VERSION 5.8 ;
BUSBITCHARS "[]" ;
DIVIDERCHAR "/" ;
UNITS
    DATABASE MICRONS 1000 ;
END UNITS

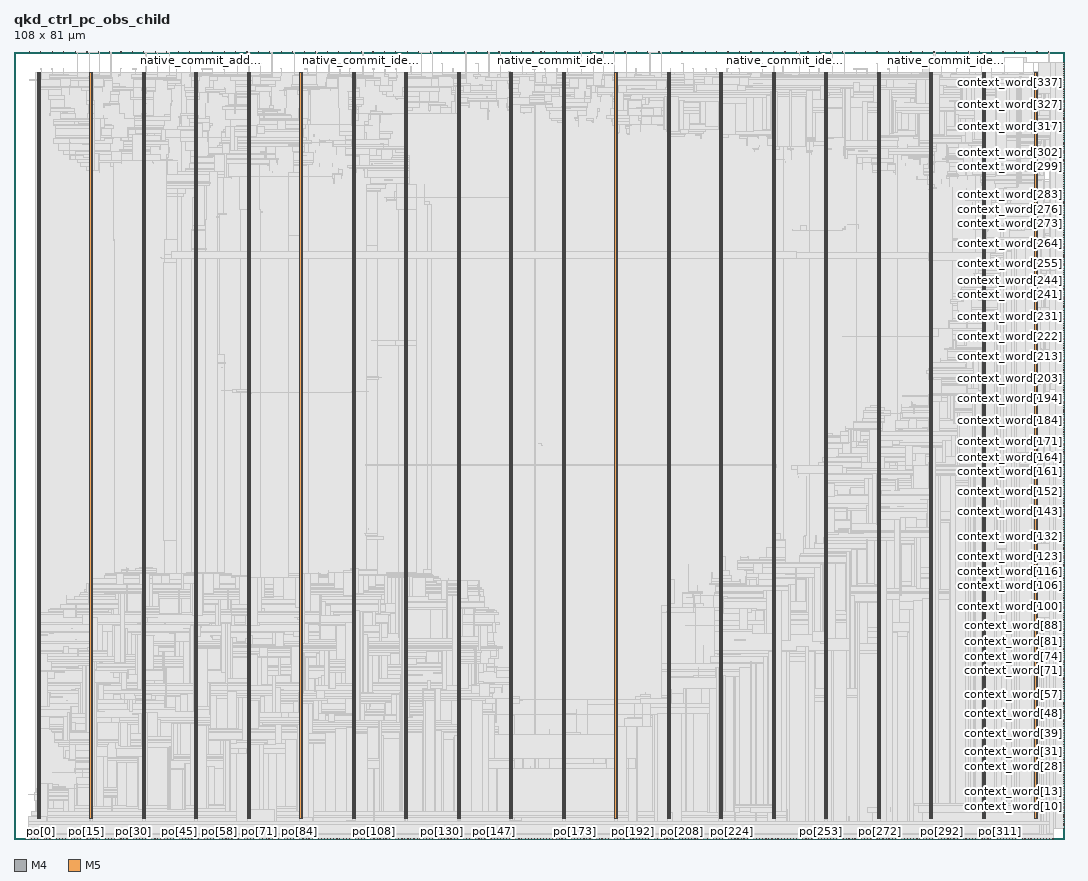
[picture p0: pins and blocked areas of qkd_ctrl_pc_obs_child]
MACRO qkd_ctrl_pc_obs_child
  FOREIGN qkd_ctrl_pc_obs_child 0 0 ;
  CLASS BLOCK ;
  SIZE 108 BY 81 ;
  PIN context_word[0]
    DIRECTION INPUT ;
    USE SIGNAL ;
    PORT
      LAYER M4 ;
        RECT  107.916 1.104 108 1.128 ;
    END
  END context_word[0]
  PIN context_word[100]
    DIRECTION INPUT ;
    USE SIGNAL ;
    PORT
      LAYER M4 ;
        RECT  107.916 23.856 108 23.88 ;
    END
  END context_word[100]
  PIN context_word[101]
    DIRECTION INPUT ;
    USE SIGNAL ;
    PORT
      LAYER M4 ;
        RECT  107.916 24.096 108 24.12 ;
    END
  END context_word[101]
  PIN context_word[102]
    DIRECTION INPUT ;
    USE SIGNAL ;
    PORT
      LAYER M4 ;
        RECT  107.916 24.336 108 24.36 ;
    END
  END context_word[102]
  PIN context_word[103]
    DIRECTION INPUT ;
    USE SIGNAL ;
    PORT
      LAYER M4 ;
        RECT  107.916 24.528 108 24.552 ;
    END
  END context_word[103]
  PIN context_word[104]
    DIRECTION INPUT ;
    USE SIGNAL ;
    PORT
      LAYER M4 ;
        RECT  107.916 24.768 108 24.792 ;
    END
  END context_word[104]
  PIN context_word[105]
    DIRECTION INPUT ;
    USE SIGNAL ;
    PORT
      LAYER M4 ;
        RECT  107.916 25.008 108 25.032 ;
    END
  END context_word[105]
  PIN context_word[106]
    DIRECTION INPUT ;
    USE SIGNAL ;
    PORT
      LAYER M4 ;
        RECT  107.916 25.248 108 25.272 ;
    END
  END context_word[106]
  PIN context_word[107]
    DIRECTION INPUT ;
    USE SIGNAL ;
    PORT
      LAYER M4 ;
        RECT  107.916 25.44 108 25.464 ;
    END
  END context_word[107]
  PIN context_word[108]
    DIRECTION INPUT ;
    USE SIGNAL ;
    PORT
      LAYER M4 ;
        RECT  107.916 25.68 108 25.704 ;
    END
  END context_word[108]
  PIN context_word[109]
    DIRECTION INPUT ;
    USE SIGNAL ;
    PORT
      LAYER M4 ;
        RECT  107.916 25.92 108 25.944 ;
    END
  END context_word[109]
  PIN context_word[10]
    DIRECTION INPUT ;
    USE SIGNAL ;
    PORT
      LAYER M4 ;
        RECT  107.916 3.36 108 3.384 ;
    END
  END context_word[10]
  PIN context_word[110]
    DIRECTION INPUT ;
    USE SIGNAL ;
    PORT
      LAYER M4 ;
        RECT  107.916 26.16 108 26.184 ;
    END
  END context_word[110]
  PIN context_word[111]
    DIRECTION INPUT ;
    USE SIGNAL ;
    PORT
      LAYER M4 ;
        RECT  107.916 26.352 108 26.376 ;
    END
  END context_word[111]
  PIN context_word[112]
    DIRECTION INPUT ;
    USE SIGNAL ;
    PORT
      LAYER M4 ;
        RECT  107.916 26.592 108 26.616 ;
    END
  END context_word[112]
  PIN context_word[113]
    DIRECTION INPUT ;
    USE SIGNAL ;
    PORT
      LAYER M4 ;
        RECT  107.916 26.832 108 26.856 ;
    END
  END context_word[113]
  PIN context_word[114]
    DIRECTION INPUT ;
    USE SIGNAL ;
    PORT
      LAYER M4 ;
        RECT  107.916 27.072 108 27.096 ;
    END
  END context_word[114]
  PIN context_word[115]
    DIRECTION INPUT ;
    USE SIGNAL ;
    PORT
      LAYER M4 ;
        RECT  107.916 27.264 108 27.288 ;
    END
  END context_word[115]
  PIN context_word[116]
    DIRECTION INPUT ;
    USE SIGNAL ;
    PORT
      LAYER M4 ;
        RECT  107.916 27.504 108 27.528 ;
    END
  END context_word[116]
  PIN context_word[117]
    DIRECTION INPUT ;
    USE SIGNAL ;
    PORT
      LAYER M4 ;
        RECT  107.916 27.744 108 27.768 ;
    END
  END context_word[117]
  PIN context_word[118]
    DIRECTION INPUT ;
    USE SIGNAL ;
    PORT
      LAYER M4 ;
        RECT  107.916 27.984 108 28.008 ;
    END
  END context_word[118]
  PIN context_word[119]
    DIRECTION INPUT ;
    USE SIGNAL ;
    PORT
      LAYER M4 ;
        RECT  107.916 28.176 108 28.2 ;
    END
  END context_word[119]
  PIN context_word[11]
    DIRECTION INPUT ;
    USE SIGNAL ;
    PORT
      LAYER M4 ;
        RECT  107.916 3.6 108 3.624 ;
    END
  END context_word[11]
  PIN context_word[120]
    DIRECTION INPUT ;
    USE SIGNAL ;
    PORT
      LAYER M4 ;
        RECT  107.916 28.416 108 28.44 ;
    END
  END context_word[120]
  PIN context_word[121]
    DIRECTION INPUT ;
    USE SIGNAL ;
    PORT
      LAYER M4 ;
        RECT  107.916 28.656 108 28.68 ;
    END
  END context_word[121]
  PIN context_word[122]
    DIRECTION INPUT ;
    USE SIGNAL ;
    PORT
      LAYER M4 ;
        RECT  107.916 28.896 108 28.92 ;
    END
  END context_word[122]
  PIN context_word[123]
    DIRECTION INPUT ;
    USE SIGNAL ;
    PORT
      LAYER M4 ;
        RECT  107.916 29.088 108 29.112 ;
    END
  END context_word[123]
  PIN context_word[124]
    DIRECTION INPUT ;
    USE SIGNAL ;
    PORT
      LAYER M4 ;
        RECT  107.916 29.328 108 29.352 ;
    END
  END context_word[124]
  PIN context_word[125]
    DIRECTION INPUT ;
    USE SIGNAL ;
    PORT
      LAYER M4 ;
        RECT  107.916 29.568 108 29.592 ;
    END
  END context_word[125]
  PIN context_word[126]
    DIRECTION INPUT ;
    USE SIGNAL ;
    PORT
      LAYER M4 ;
        RECT  107.916 29.808 108 29.832 ;
    END
  END context_word[126]
  PIN context_word[127]
    DIRECTION INPUT ;
    USE SIGNAL ;
    PORT
      LAYER M4 ;
        RECT  107.916 30 108 30.024 ;
    END
  END context_word[127]
  PIN context_word[128]
    DIRECTION INPUT ;
    USE SIGNAL ;
    PORT
      LAYER M4 ;
        RECT  107.916 30.24 108 30.264 ;
    END
  END context_word[128]
  PIN context_word[129]
    DIRECTION INPUT ;
    USE SIGNAL ;
    PORT
      LAYER M4 ;
        RECT  107.916 30.48 108 30.504 ;
    END
  END context_word[129]
  PIN context_word[12]
    DIRECTION INPUT ;
    USE SIGNAL ;
    PORT
      LAYER M4 ;
        RECT  107.916 3.84 108 3.864 ;
    END
  END context_word[12]
  PIN context_word[130]
    DIRECTION INPUT ;
    USE SIGNAL ;
    PORT
      LAYER M4 ;
        RECT  107.916 30.72 108 30.744 ;
    END
  END context_word[130]
  PIN context_word[131]
    DIRECTION INPUT ;
    USE SIGNAL ;
    PORT
      LAYER M4 ;
        RECT  107.916 30.912 108 30.936 ;
    END
  END context_word[131]
  PIN context_word[132]
    DIRECTION INPUT ;
    USE SIGNAL ;
    PORT
      LAYER M4 ;
        RECT  107.916 31.152 108 31.176 ;
    END
  END context_word[132]
  PIN context_word[133]
    DIRECTION INPUT ;
    USE SIGNAL ;
    PORT
      LAYER M4 ;
        RECT  107.916 31.392 108 31.416 ;
    END
  END context_word[133]
  PIN context_word[134]
    DIRECTION INPUT ;
    USE SIGNAL ;
    PORT
      LAYER M4 ;
        RECT  107.916 31.632 108 31.656 ;
    END
  END context_word[134]
  PIN context_word[135]
    DIRECTION INPUT ;
    USE SIGNAL ;
    PORT
      LAYER M4 ;
        RECT  107.916 31.824 108 31.848 ;
    END
  END context_word[135]
  PIN context_word[136]
    DIRECTION INPUT ;
    USE SIGNAL ;
    PORT
      LAYER M4 ;
        RECT  107.916 32.064 108 32.088 ;
    END
  END context_word[136]
  PIN context_word[137]
    DIRECTION INPUT ;
    USE SIGNAL ;
    PORT
      LAYER M4 ;
        RECT  107.916 32.304 108 32.328 ;
    END
  END context_word[137]
  PIN context_word[138]
    DIRECTION INPUT ;
    USE SIGNAL ;
    PORT
      LAYER M4 ;
        RECT  107.916 32.544 108 32.568 ;
    END
  END context_word[138]
  PIN context_word[139]
    DIRECTION INPUT ;
    USE SIGNAL ;
    PORT
      LAYER M4 ;
        RECT  107.916 32.736 108 32.76 ;
    END
  END context_word[139]
  PIN context_word[13]
    DIRECTION INPUT ;
    USE SIGNAL ;
    PORT
      LAYER M4 ;
        RECT  107.916 4.08 108 4.104 ;
    END
  END context_word[13]
  PIN context_word[140]
    DIRECTION INPUT ;
    USE SIGNAL ;
    PORT
      LAYER M4 ;
        RECT  107.916 32.976 108 33 ;
    END
  END context_word[140]
  PIN context_word[141]
    DIRECTION INPUT ;
    USE SIGNAL ;
    PORT
      LAYER M4 ;
        RECT  107.916 33.216 108 33.24 ;
    END
  END context_word[141]
  PIN context_word[142]
    DIRECTION INPUT ;
    USE SIGNAL ;
    PORT
      LAYER M4 ;
        RECT  107.916 33.408 108 33.432 ;
    END
  END context_word[142]
  PIN context_word[143]
    DIRECTION INPUT ;
    USE SIGNAL ;
    PORT
      LAYER M4 ;
        RECT  107.916 33.648 108 33.672 ;
    END
  END context_word[143]
  PIN context_word[144]
    DIRECTION INPUT ;
    USE SIGNAL ;
    PORT
      LAYER M4 ;
        RECT  107.916 33.888 108 33.912 ;
    END
  END context_word[144]
  PIN context_word[145]
    DIRECTION INPUT ;
    USE SIGNAL ;
    PORT
      LAYER M4 ;
        RECT  107.916 34.128 108 34.152 ;
    END
  END context_word[145]
  PIN context_word[146]
    DIRECTION INPUT ;
    USE SIGNAL ;
    PORT
      LAYER M4 ;
        RECT  107.916 34.32 108 34.344 ;
    END
  END context_word[146]
  PIN context_word[147]
    DIRECTION INPUT ;
    USE SIGNAL ;
    PORT
      LAYER M4 ;
        RECT  107.916 34.56 108 34.584 ;
    END
  END context_word[147]
  PIN context_word[148]
    DIRECTION INPUT ;
    USE SIGNAL ;
    PORT
      LAYER M4 ;
        RECT  107.916 34.8 108 34.824 ;
    END
  END context_word[148]
  PIN context_word[149]
    DIRECTION INPUT ;
    USE SIGNAL ;
    PORT
      LAYER M4 ;
        RECT  107.916 35.04 108 35.064 ;
    END
  END context_word[149]
  PIN context_word[14]
    DIRECTION INPUT ;
    USE SIGNAL ;
    PORT
      LAYER M4 ;
        RECT  107.916 4.272 108 4.296 ;
    END
  END context_word[14]
  PIN context_word[150]
    DIRECTION INPUT ;
    USE SIGNAL ;
    PORT
      LAYER M4 ;
        RECT  107.916 35.232 108 35.256 ;
    END
  END context_word[150]
  PIN context_word[151]
    DIRECTION INPUT ;
    USE SIGNAL ;
    PORT
      LAYER M4 ;
        RECT  107.916 35.472 108 35.496 ;
    END
  END context_word[151]
  PIN context_word[152]
    DIRECTION INPUT ;
    USE SIGNAL ;
    PORT
      LAYER M4 ;
        RECT  107.916 35.712 108 35.736 ;
    END
  END context_word[152]
  PIN context_word[153]
    DIRECTION INPUT ;
    USE SIGNAL ;
    PORT
      LAYER M4 ;
        RECT  107.916 35.952 108 35.976 ;
    END
  END context_word[153]
  PIN context_word[154]
    DIRECTION INPUT ;
    USE SIGNAL ;
    PORT
      LAYER M4 ;
        RECT  107.916 36.144 108 36.168 ;
    END
  END context_word[154]
  PIN context_word[155]
    DIRECTION INPUT ;
    USE SIGNAL ;
    PORT
      LAYER M4 ;
        RECT  107.916 36.384 108 36.408 ;
    END
  END context_word[155]
  PIN context_word[156]
    DIRECTION INPUT ;
    USE SIGNAL ;
    PORT
      LAYER M4 ;
        RECT  107.916 36.624 108 36.648 ;
    END
  END context_word[156]
  PIN context_word[157]
    DIRECTION INPUT ;
    USE SIGNAL ;
    PORT
      LAYER M4 ;
        RECT  107.916 36.864 108 36.888 ;
    END
  END context_word[157]
  PIN context_word[158]
    DIRECTION INPUT ;
    USE SIGNAL ;
    PORT
      LAYER M4 ;
        RECT  107.916 37.056 108 37.08 ;
    END
  END context_word[158]
  PIN context_word[159]
    DIRECTION INPUT ;
    USE SIGNAL ;
    PORT
      LAYER M4 ;
        RECT  107.916 37.296 108 37.32 ;
    END
  END context_word[159]
  PIN context_word[15]
    DIRECTION INPUT ;
    USE SIGNAL ;
    PORT
      LAYER M4 ;
        RECT  107.916 4.512 108 4.536 ;
    END
  END context_word[15]
  PIN context_word[160]
    DIRECTION INPUT ;
    USE SIGNAL ;
    PORT
      LAYER M4 ;
        RECT  107.916 37.536 108 37.56 ;
    END
  END context_word[160]
  PIN context_word[161]
    DIRECTION INPUT ;
    USE SIGNAL ;
    PORT
      LAYER M4 ;
        RECT  107.916 37.776 108 37.8 ;
    END
  END context_word[161]
  PIN context_word[162]
    DIRECTION INPUT ;
    USE SIGNAL ;
    PORT
      LAYER M4 ;
        RECT  107.916 37.968 108 37.992 ;
    END
  END context_word[162]
  PIN context_word[163]
    DIRECTION INPUT ;
    USE SIGNAL ;
    PORT
      LAYER M4 ;
        RECT  107.916 38.208 108 38.232 ;
    END
  END context_word[163]
  PIN context_word[164]
    DIRECTION INPUT ;
    USE SIGNAL ;
    PORT
      LAYER M4 ;
        RECT  107.916 38.448 108 38.472 ;
    END
  END context_word[164]
  PIN context_word[165]
    DIRECTION INPUT ;
    USE SIGNAL ;
    PORT
      LAYER M4 ;
        RECT  107.916 38.688 108 38.712 ;
    END
  END context_word[165]
  PIN context_word[166]
    DIRECTION INPUT ;
    USE SIGNAL ;
    PORT
      LAYER M4 ;
        RECT  107.916 38.88 108 38.904 ;
    END
  END context_word[166]
  PIN context_word[167]
    DIRECTION INPUT ;
    USE SIGNAL ;
    PORT
      LAYER M4 ;
        RECT  107.916 39.12 108 39.144 ;
    END
  END context_word[167]
  PIN context_word[168]
    DIRECTION INPUT ;
    USE SIGNAL ;
    PORT
      LAYER M4 ;
        RECT  107.916 39.36 108 39.384 ;
    END
  END context_word[168]
  PIN context_word[169]
    DIRECTION INPUT ;
    USE SIGNAL ;
    PORT
      LAYER M4 ;
        RECT  107.916 39.6 108 39.624 ;
    END
  END context_word[169]
  PIN context_word[16]
    DIRECTION INPUT ;
    USE SIGNAL ;
    PORT
      LAYER M4 ;
        RECT  107.916 4.752 108 4.776 ;
    END
  END context_word[16]
  PIN context_word[170]
    DIRECTION INPUT ;
    USE SIGNAL ;
    PORT
      LAYER M4 ;
        RECT  107.916 39.792 108 39.816 ;
    END
  END context_word[170]
  PIN context_word[171]
    DIRECTION INPUT ;
    USE SIGNAL ;
    PORT
      LAYER M4 ;
        RECT  107.916 40.032 108 40.056 ;
    END
  END context_word[171]
  PIN context_word[172]
    DIRECTION INPUT ;
    USE SIGNAL ;
    PORT
      LAYER M4 ;
        RECT  107.916 40.272 108 40.296 ;
    END
  END context_word[172]
  PIN context_word[173]
    DIRECTION INPUT ;
    USE SIGNAL ;
    PORT
      LAYER M4 ;
        RECT  107.916 40.512 108 40.536 ;
    END
  END context_word[173]
  PIN context_word[174]
    DIRECTION INPUT ;
    USE SIGNAL ;
    PORT
      LAYER M4 ;
        RECT  107.916 40.704 108 40.728 ;
    END
  END context_word[174]
  PIN context_word[175]
    DIRECTION INPUT ;
    USE SIGNAL ;
    PORT
      LAYER M4 ;
        RECT  107.916 40.944 108 40.968 ;
    END
  END context_word[175]
  PIN context_word[176]
    DIRECTION INPUT ;
    USE SIGNAL ;
    PORT
      LAYER M4 ;
        RECT  107.916 41.184 108 41.208 ;
    END
  END context_word[176]
  PIN context_word[177]
    DIRECTION INPUT ;
    USE SIGNAL ;
    PORT
      LAYER M4 ;
        RECT  107.916 41.376 108 41.4 ;
    END
  END context_word[177]
  PIN context_word[178]
    DIRECTION INPUT ;
    USE SIGNAL ;
    PORT
      LAYER M4 ;
        RECT  107.916 41.616 108 41.64 ;
    END
  END context_word[178]
  PIN context_word[179]
    DIRECTION INPUT ;
    USE SIGNAL ;
    PORT
      LAYER M4 ;
        RECT  107.916 41.856 108 41.88 ;
    END
  END context_word[179]
  PIN context_word[17]
    DIRECTION INPUT ;
    USE SIGNAL ;
    PORT
      LAYER M4 ;
        RECT  107.916 4.992 108 5.016 ;
    END
  END context_word[17]
  PIN context_word[180]
    DIRECTION INPUT ;
    USE SIGNAL ;
    PORT
      LAYER M4 ;
        RECT  107.916 42.096 108 42.12 ;
    END
  END context_word[180]
  PIN context_word[181]
    DIRECTION INPUT ;
    USE SIGNAL ;
    PORT
      LAYER M4 ;
        RECT  107.916 42.288 108 42.312 ;
    END
  END context_word[181]
  PIN context_word[182]
    DIRECTION INPUT ;
    USE SIGNAL ;
    PORT
      LAYER M4 ;
        RECT  107.916 42.528 108 42.552 ;
    END
  END context_word[182]
  PIN context_word[183]
    DIRECTION INPUT ;
    USE SIGNAL ;
    PORT
      LAYER M4 ;
        RECT  107.916 42.768 108 42.792 ;
    END
  END context_word[183]
  PIN context_word[184]
    DIRECTION INPUT ;
    USE SIGNAL ;
    PORT
      LAYER M4 ;
        RECT  107.916 43.008 108 43.032 ;
    END
  END context_word[184]
  PIN context_word[185]
    DIRECTION INPUT ;
    USE SIGNAL ;
    PORT
      LAYER M4 ;
        RECT  107.916 43.2 108 43.224 ;
    END
  END context_word[185]
  PIN context_word[186]
    DIRECTION INPUT ;
    USE SIGNAL ;
    PORT
      LAYER M4 ;
        RECT  107.916 43.44 108 43.464 ;
    END
  END context_word[186]
  PIN context_word[187]
    DIRECTION INPUT ;
    USE SIGNAL ;
    PORT
      LAYER M4 ;
        RECT  107.916 43.68 108 43.704 ;
    END
  END context_word[187]
  PIN context_word[188]
    DIRECTION INPUT ;
    USE SIGNAL ;
    PORT
      LAYER M4 ;
        RECT  107.916 43.92 108 43.944 ;
    END
  END context_word[188]
  PIN context_word[189]
    DIRECTION INPUT ;
    USE SIGNAL ;
    PORT
      LAYER M4 ;
        RECT  107.916 44.112 108 44.136 ;
    END
  END context_word[189]
  PIN context_word[18]
    DIRECTION INPUT ;
    USE SIGNAL ;
    PORT
      LAYER M4 ;
        RECT  107.916 5.184 108 5.208 ;
    END
  END context_word[18]
  PIN context_word[190]
    DIRECTION INPUT ;
    USE SIGNAL ;
    PORT
      LAYER M4 ;
        RECT  107.916 44.352 108 44.376 ;
    END
  END context_word[190]
  PIN context_word[191]
    DIRECTION INPUT ;
    USE SIGNAL ;
    PORT
      LAYER M4 ;
        RECT  107.916 44.592 108 44.616 ;
    END
  END context_word[191]
  PIN context_word[192]
    DIRECTION INPUT ;
    USE SIGNAL ;
    PORT
      LAYER M4 ;
        RECT  107.916 44.832 108 44.856 ;
    END
  END context_word[192]
  PIN context_word[193]
    DIRECTION INPUT ;
    USE SIGNAL ;
    PORT
      LAYER M4 ;
        RECT  107.916 45.024 108 45.048 ;
    END
  END context_word[193]
  PIN context_word[194]
    DIRECTION INPUT ;
    USE SIGNAL ;
    PORT
      LAYER M4 ;
        RECT  107.916 45.264 108 45.288 ;
    END
  END context_word[194]
  PIN context_word[195]
    DIRECTION INPUT ;
    USE SIGNAL ;
    PORT
      LAYER M4 ;
        RECT  107.916 45.504 108 45.528 ;
    END
  END context_word[195]
  PIN context_word[196]
    DIRECTION INPUT ;
    USE SIGNAL ;
    PORT
      LAYER M4 ;
        RECT  107.916 45.744 108 45.768 ;
    END
  END context_word[196]
  PIN context_word[197]
    DIRECTION INPUT ;
    USE SIGNAL ;
    PORT
      LAYER M4 ;
        RECT  107.916 45.936 108 45.96 ;
    END
  END context_word[197]
  PIN context_word[198]
    DIRECTION INPUT ;
    USE SIGNAL ;
    PORT
      LAYER M4 ;
        RECT  107.916 46.176 108 46.2 ;
    END
  END context_word[198]
  PIN context_word[199]
    DIRECTION INPUT ;
    USE SIGNAL ;
    PORT
      LAYER M4 ;
        RECT  107.916 46.416 108 46.44 ;
    END
  END context_word[199]
  PIN context_word[19]
    DIRECTION INPUT ;
    USE SIGNAL ;
    PORT
      LAYER M4 ;
        RECT  107.916 5.424 108 5.448 ;
    END
  END context_word[19]
  PIN context_word[1]
    DIRECTION INPUT ;
    USE SIGNAL ;
    PORT
      LAYER M4 ;
        RECT  107.916 1.344 108 1.368 ;
    END
  END context_word[1]
  PIN context_word[200]
    DIRECTION INPUT ;
    USE SIGNAL ;
    PORT
      LAYER M4 ;
        RECT  107.916 46.656 108 46.68 ;
    END
  END context_word[200]
  PIN context_word[201]
    DIRECTION INPUT ;
    USE SIGNAL ;
    PORT
      LAYER M4 ;
        RECT  107.916 46.848 108 46.872 ;
    END
  END context_word[201]
  PIN context_word[202]
    DIRECTION INPUT ;
    USE SIGNAL ;
    PORT
      LAYER M4 ;
        RECT  107.916 47.088 108 47.112 ;
    END
  END context_word[202]
  PIN context_word[203]
    DIRECTION INPUT ;
    USE SIGNAL ;
    PORT
      LAYER M4 ;
        RECT  107.916 47.328 108 47.352 ;
    END
  END context_word[203]
  PIN context_word[204]
    DIRECTION INPUT ;
    USE SIGNAL ;
    PORT
      LAYER M4 ;
        RECT  107.916 47.568 108 47.592 ;
    END
  END context_word[204]
  PIN context_word[205]
    DIRECTION INPUT ;
    USE SIGNAL ;
    PORT
      LAYER M4 ;
        RECT  107.916 47.76 108 47.784 ;
    END
  END context_word[205]
  PIN context_word[206]
    DIRECTION INPUT ;
    USE SIGNAL ;
    PORT
      LAYER M4 ;
        RECT  107.916 48 108 48.024 ;
    END
  END context_word[206]
  PIN context_word[207]
    DIRECTION INPUT ;
    USE SIGNAL ;
    PORT
      LAYER M4 ;
        RECT  107.916 48.24 108 48.264 ;
    END
  END context_word[207]
  PIN context_word[208]
    DIRECTION INPUT ;
    USE SIGNAL ;
    PORT
      LAYER M4 ;
        RECT  107.916 48.48 108 48.504 ;
    END
  END context_word[208]
  PIN context_word[209]
    DIRECTION INPUT ;
    USE SIGNAL ;
    PORT
      LAYER M4 ;
        RECT  107.916 48.672 108 48.696 ;
    END
  END context_word[209]
  PIN context_word[20]
    DIRECTION INPUT ;
    USE SIGNAL ;
    PORT
      LAYER M4 ;
        RECT  107.916 5.664 108 5.688 ;
    END
  END context_word[20]
  PIN context_word[210]
    DIRECTION INPUT ;
    USE SIGNAL ;
    PORT
      LAYER M4 ;
        RECT  107.916 48.912 108 48.936 ;
    END
  END context_word[210]
  PIN context_word[211]
    DIRECTION INPUT ;
    USE SIGNAL ;
    PORT
      LAYER M4 ;
        RECT  107.916 49.152 108 49.176 ;
    END
  END context_word[211]
  PIN context_word[212]
    DIRECTION INPUT ;
    USE SIGNAL ;
    PORT
      LAYER M4 ;
        RECT  107.916 49.344 108 49.368 ;
    END
  END context_word[212]
  PIN context_word[213]
    DIRECTION INPUT ;
    USE SIGNAL ;
    PORT
      LAYER M4 ;
        RECT  107.916 49.584 108 49.608 ;
    END
  END context_word[213]
  PIN context_word[214]
    DIRECTION INPUT ;
    USE SIGNAL ;
    PORT
      LAYER M4 ;
        RECT  107.916 49.824 108 49.848 ;
    END
  END context_word[214]
  PIN context_word[215]
    DIRECTION INPUT ;
    USE SIGNAL ;
    PORT
      LAYER M4 ;
        RECT  107.916 50.064 108 50.088 ;
    END
  END context_word[215]
  PIN context_word[216]
    DIRECTION INPUT ;
    USE SIGNAL ;
    PORT
      LAYER M4 ;
        RECT  107.916 50.256 108 50.28 ;
    END
  END context_word[216]
  PIN context_word[217]
    DIRECTION INPUT ;
    USE SIGNAL ;
    PORT
      LAYER M4 ;
        RECT  107.916 50.496 108 50.52 ;
    END
  END context_word[217]
  PIN context_word[218]
    DIRECTION INPUT ;
    USE SIGNAL ;
    PORT
      LAYER M4 ;
        RECT  107.916 50.736 108 50.76 ;
    END
  END context_word[218]
  PIN context_word[219]
    DIRECTION INPUT ;
    USE SIGNAL ;
    PORT
      LAYER M4 ;
        RECT  107.916 50.976 108 51 ;
    END
  END context_word[219]
  PIN context_word[21]
    DIRECTION INPUT ;
    USE SIGNAL ;
    PORT
      LAYER M4 ;
        RECT  107.916 5.904 108 5.928 ;
    END
  END context_word[21]
  PIN context_word[220]
    DIRECTION INPUT ;
    USE SIGNAL ;
    PORT
      LAYER M4 ;
        RECT  107.916 51.168 108 51.192 ;
    END
  END context_word[220]
  PIN context_word[221]
    DIRECTION INPUT ;
    USE SIGNAL ;
    PORT
      LAYER M4 ;
        RECT  107.916 51.408 108 51.432 ;
    END
  END context_word[221]
  PIN context_word[222]
    DIRECTION INPUT ;
    USE SIGNAL ;
    PORT
      LAYER M4 ;
        RECT  107.916 51.648 108 51.672 ;
    END
  END context_word[222]
  PIN context_word[223]
    DIRECTION INPUT ;
    USE SIGNAL ;
    PORT
      LAYER M4 ;
        RECT  107.916 51.888 108 51.912 ;
    END
  END context_word[223]
  PIN context_word[224]
    DIRECTION INPUT ;
    USE SIGNAL ;
    PORT
      LAYER M4 ;
        RECT  107.916 52.08 108 52.104 ;
    END
  END context_word[224]
  PIN context_word[225]
    DIRECTION INPUT ;
    USE SIGNAL ;
    PORT
      LAYER M4 ;
        RECT  107.916 52.32 108 52.344 ;
    END
  END context_word[225]
  PIN context_word[226]
    DIRECTION INPUT ;
    USE SIGNAL ;
    PORT
      LAYER M4 ;
        RECT  107.916 52.56 108 52.584 ;
    END
  END context_word[226]
  PIN context_word[227]
    DIRECTION INPUT ;
    USE SIGNAL ;
    PORT
      LAYER M4 ;
        RECT  107.916 52.8 108 52.824 ;
    END
  END context_word[227]
  PIN context_word[228]
    DIRECTION INPUT ;
    USE SIGNAL ;
    PORT
      LAYER M4 ;
        RECT  107.916 52.992 108 53.016 ;
    END
  END context_word[228]
  PIN context_word[229]
    DIRECTION INPUT ;
    USE SIGNAL ;
    PORT
      LAYER M4 ;
        RECT  107.916 53.232 108 53.256 ;
    END
  END context_word[229]
  PIN context_word[22]
    DIRECTION INPUT ;
    USE SIGNAL ;
    PORT
      LAYER M4 ;
        RECT  107.916 6.096 108 6.12 ;
    END
  END context_word[22]
  PIN context_word[230]
    DIRECTION INPUT ;
    USE SIGNAL ;
    PORT
      LAYER M4 ;
        RECT  107.916 53.472 108 53.496 ;
    END
  END context_word[230]
  PIN context_word[231]
    DIRECTION INPUT ;
    USE SIGNAL ;
    PORT
      LAYER M4 ;
        RECT  107.916 53.712 108 53.736 ;
    END
  END context_word[231]
  PIN context_word[232]
    DIRECTION INPUT ;
    USE SIGNAL ;
    PORT
      LAYER M4 ;
        RECT  107.916 53.904 108 53.928 ;
    END
  END context_word[232]
  PIN context_word[233]
    DIRECTION INPUT ;
    USE SIGNAL ;
    PORT
      LAYER M4 ;
        RECT  107.916 54.144 108 54.168 ;
    END
  END context_word[233]
  PIN context_word[234]
    DIRECTION INPUT ;
    USE SIGNAL ;
    PORT
      LAYER M4 ;
        RECT  107.916 54.384 108 54.408 ;
    END
  END context_word[234]
  PIN context_word[235]
    DIRECTION INPUT ;
    USE SIGNAL ;
    PORT
      LAYER M4 ;
        RECT  107.916 54.624 108 54.648 ;
    END
  END context_word[235]
  PIN context_word[236]
    DIRECTION INPUT ;
    USE SIGNAL ;
    PORT
      LAYER M4 ;
        RECT  107.916 54.816 108 54.84 ;
    END
  END context_word[236]
  PIN context_word[237]
    DIRECTION INPUT ;
    USE SIGNAL ;
    PORT
      LAYER M4 ;
        RECT  107.916 55.056 108 55.08 ;
    END
  END context_word[237]
  PIN context_word[238]
    DIRECTION INPUT ;
    USE SIGNAL ;
    PORT
      LAYER M4 ;
        RECT  107.916 55.296 108 55.32 ;
    END
  END context_word[238]
  PIN context_word[239]
    DIRECTION INPUT ;
    USE SIGNAL ;
    PORT
      LAYER M4 ;
        RECT  107.916 55.536 108 55.56 ;
    END
  END context_word[239]
  PIN context_word[23]
    DIRECTION INPUT ;
    USE SIGNAL ;
    PORT
      LAYER M4 ;
        RECT  107.916 6.336 108 6.36 ;
    END
  END context_word[23]
  PIN context_word[240]
    DIRECTION INPUT ;
    USE SIGNAL ;
    PORT
      LAYER M4 ;
        RECT  107.916 55.728 108 55.752 ;
    END
  END context_word[240]
  PIN context_word[241]
    DIRECTION INPUT ;
    USE SIGNAL ;
    PORT
      LAYER M4 ;
        RECT  107.916 55.968 108 55.992 ;
    END
  END context_word[241]
  PIN context_word[242]
    DIRECTION INPUT ;
    USE SIGNAL ;
    PORT
      LAYER M4 ;
        RECT  107.916 56.208 108 56.232 ;
    END
  END context_word[242]
  PIN context_word[243]
    DIRECTION INPUT ;
    USE SIGNAL ;
    PORT
      LAYER M4 ;
        RECT  107.916 56.448 108 56.472 ;
    END
  END context_word[243]
  PIN context_word[244]
    DIRECTION INPUT ;
    USE SIGNAL ;
    PORT
      LAYER M4 ;
        RECT  107.916 56.64 108 56.664 ;
    END
  END context_word[244]
  PIN context_word[245]
    DIRECTION INPUT ;
    USE SIGNAL ;
    PORT
      LAYER M4 ;
        RECT  107.916 56.88 108 56.904 ;
    END
  END context_word[245]
  PIN context_word[246]
    DIRECTION INPUT ;
    USE SIGNAL ;
    PORT
      LAYER M4 ;
        RECT  107.916 57.12 108 57.144 ;
    END
  END context_word[246]
  PIN context_word[247]
    DIRECTION INPUT ;
    USE SIGNAL ;
    PORT
      LAYER M4 ;
        RECT  107.916 57.312 108 57.336 ;
    END
  END context_word[247]
  PIN context_word[248]
    DIRECTION INPUT ;
    USE SIGNAL ;
    PORT
      LAYER M4 ;
        RECT  107.916 57.552 108 57.576 ;
    END
  END context_word[248]
  PIN context_word[249]
    DIRECTION INPUT ;
    USE SIGNAL ;
    PORT
      LAYER M4 ;
        RECT  107.916 57.792 108 57.816 ;
    END
  END context_word[249]
  PIN context_word[24]
    DIRECTION INPUT ;
    USE SIGNAL ;
    PORT
      LAYER M4 ;
        RECT  107.916 6.576 108 6.6 ;
    END
  END context_word[24]
  PIN context_word[250]
    DIRECTION INPUT ;
    USE SIGNAL ;
    PORT
      LAYER M4 ;
        RECT  107.916 58.032 108 58.056 ;
    END
  END context_word[250]
  PIN context_word[251]
    DIRECTION INPUT ;
    USE SIGNAL ;
    PORT
      LAYER M4 ;
        RECT  107.916 58.224 108 58.248 ;
    END
  END context_word[251]
  PIN context_word[252]
    DIRECTION INPUT ;
    USE SIGNAL ;
    PORT
      LAYER M4 ;
        RECT  107.916 58.464 108 58.488 ;
    END
  END context_word[252]
  PIN context_word[253]
    DIRECTION INPUT ;
    USE SIGNAL ;
    PORT
      LAYER M4 ;
        RECT  107.916 58.704 108 58.728 ;
    END
  END context_word[253]
  PIN context_word[254]
    DIRECTION INPUT ;
    USE SIGNAL ;
    PORT
      LAYER M4 ;
        RECT  107.916 58.944 108 58.968 ;
    END
  END context_word[254]
  PIN context_word[255]
    DIRECTION INPUT ;
    USE SIGNAL ;
    PORT
      LAYER M4 ;
        RECT  107.916 59.136 108 59.16 ;
    END
  END context_word[255]
  PIN context_word[256]
    DIRECTION INPUT ;
    USE SIGNAL ;
    PORT
      LAYER M4 ;
        RECT  107.916 59.376 108 59.4 ;
    END
  END context_word[256]
  PIN context_word[257]
    DIRECTION INPUT ;
    USE SIGNAL ;
    PORT
      LAYER M4 ;
        RECT  107.916 59.616 108 59.64 ;
    END
  END context_word[257]
  PIN context_word[258]
    DIRECTION INPUT ;
    USE SIGNAL ;
    PORT
      LAYER M4 ;
        RECT  107.916 59.856 108 59.88 ;
    END
  END context_word[258]
  PIN context_word[259]
    DIRECTION INPUT ;
    USE SIGNAL ;
    PORT
      LAYER M4 ;
        RECT  107.916 60.048 108 60.072 ;
    END
  END context_word[259]
  PIN context_word[25]
    DIRECTION INPUT ;
    USE SIGNAL ;
    PORT
      LAYER M4 ;
        RECT  107.916 6.816 108 6.84 ;
    END
  END context_word[25]
  PIN context_word[260]
    DIRECTION INPUT ;
    USE SIGNAL ;
    PORT
      LAYER M4 ;
        RECT  107.916 60.288 108 60.312 ;
    END
  END context_word[260]
  PIN context_word[261]
    DIRECTION INPUT ;
    USE SIGNAL ;
    PORT
      LAYER M4 ;
        RECT  107.916 60.528 108 60.552 ;
    END
  END context_word[261]
  PIN context_word[262]
    DIRECTION INPUT ;
    USE SIGNAL ;
    PORT
      LAYER M4 ;
        RECT  107.916 60.768 108 60.792 ;
    END
  END context_word[262]
  PIN context_word[263]
    DIRECTION INPUT ;
    USE SIGNAL ;
    PORT
      LAYER M4 ;
        RECT  107.916 60.96 108 60.984 ;
    END
  END context_word[263]
  PIN context_word[264]
    DIRECTION INPUT ;
    USE SIGNAL ;
    PORT
      LAYER M4 ;
        RECT  107.916 61.2 108 61.224 ;
    END
  END context_word[264]
  PIN context_word[265]
    DIRECTION INPUT ;
    USE SIGNAL ;
    PORT
      LAYER M4 ;
        RECT  107.916 61.44 108 61.464 ;
    END
  END context_word[265]
  PIN context_word[266]
    DIRECTION INPUT ;
    USE SIGNAL ;
    PORT
      LAYER M4 ;
        RECT  107.916 61.68 108 61.704 ;
    END
  END context_word[266]
  PIN context_word[267]
    DIRECTION INPUT ;
    USE SIGNAL ;
    PORT
      LAYER M4 ;
        RECT  107.916 61.872 108 61.896 ;
    END
  END context_word[267]
  PIN context_word[268]
    DIRECTION INPUT ;
    USE SIGNAL ;
    PORT
      LAYER M4 ;
        RECT  107.916 62.112 108 62.136 ;
    END
  END context_word[268]
  PIN context_word[269]
    DIRECTION INPUT ;
    USE SIGNAL ;
    PORT
      LAYER M4 ;
        RECT  107.916 62.352 108 62.376 ;
    END
  END context_word[269]
  PIN context_word[26]
    DIRECTION INPUT ;
    USE SIGNAL ;
    PORT
      LAYER M4 ;
        RECT  107.916 7.008 108 7.032 ;
    END
  END context_word[26]
  PIN context_word[270]
    DIRECTION INPUT ;
    USE SIGNAL ;
    PORT
      LAYER M4 ;
        RECT  107.916 62.592 108 62.616 ;
    END
  END context_word[270]
  PIN context_word[271]
    DIRECTION INPUT ;
    USE SIGNAL ;
    PORT
      LAYER M4 ;
        RECT  107.916 62.784 108 62.808 ;
    END
  END context_word[271]
  PIN context_word[272]
    DIRECTION INPUT ;
    USE SIGNAL ;
    PORT
      LAYER M4 ;
        RECT  107.916 63.024 108 63.048 ;
    END
  END context_word[272]
  PIN context_word[273]
    DIRECTION INPUT ;
    USE SIGNAL ;
    PORT
      LAYER M4 ;
        RECT  107.916 63.264 108 63.288 ;
    END
  END context_word[273]
  PIN context_word[274]
    DIRECTION INPUT ;
    USE SIGNAL ;
    PORT
      LAYER M4 ;
        RECT  107.916 63.504 108 63.528 ;
    END
  END context_word[274]
  PIN context_word[275]
    DIRECTION INPUT ;
    USE SIGNAL ;
    PORT
      LAYER M4 ;
        RECT  107.916 63.696 108 63.72 ;
    END
  END context_word[275]
  PIN context_word[276]
    DIRECTION INPUT ;
    USE SIGNAL ;
    PORT
      LAYER M4 ;
        RECT  107.916 63.936 108 63.96 ;
    END
  END context_word[276]
  PIN context_word[277]
    DIRECTION INPUT ;
    USE SIGNAL ;
    PORT
      LAYER M4 ;
        RECT  107.916 64.176 108 64.2 ;
    END
  END context_word[277]
  PIN context_word[278]
    DIRECTION INPUT ;
    USE SIGNAL ;
    PORT
      LAYER M4 ;
        RECT  107.916 64.416 108 64.44 ;
    END
  END context_word[278]
  PIN context_word[279]
    DIRECTION INPUT ;
    USE SIGNAL ;
    PORT
      LAYER M4 ;
        RECT  107.916 64.608 108 64.632 ;
    END
  END context_word[279]
  PIN context_word[27]
    DIRECTION INPUT ;
    USE SIGNAL ;
    PORT
      LAYER M4 ;
        RECT  107.916 7.248 108 7.272 ;
    END
  END context_word[27]
  PIN context_word[280]
    DIRECTION INPUT ;
    USE SIGNAL ;
    PORT
      LAYER M4 ;
        RECT  107.916 64.848 108 64.872 ;
    END
  END context_word[280]
  PIN context_word[281]
    DIRECTION INPUT ;
    USE SIGNAL ;
    PORT
      LAYER M4 ;
        RECT  107.916 65.088 108 65.112 ;
    END
  END context_word[281]
  PIN context_word[282]
    DIRECTION INPUT ;
    USE SIGNAL ;
    PORT
      LAYER M4 ;
        RECT  107.916 65.328 108 65.352 ;
    END
  END context_word[282]
  PIN context_word[283]
    DIRECTION INPUT ;
    USE SIGNAL ;
    PORT
      LAYER M4 ;
        RECT  107.916 65.52 108 65.544 ;
    END
  END context_word[283]
  PIN context_word[284]
    DIRECTION INPUT ;
    USE SIGNAL ;
    PORT
      LAYER M4 ;
        RECT  107.916 65.76 108 65.784 ;
    END
  END context_word[284]
  PIN context_word[285]
    DIRECTION INPUT ;
    USE SIGNAL ;
    PORT
      LAYER M4 ;
        RECT  107.916 66 108 66.024 ;
    END
  END context_word[285]
  PIN context_word[286]
    DIRECTION INPUT ;
    USE SIGNAL ;
    PORT
      LAYER M4 ;
        RECT  107.916 66.192 108 66.216 ;
    END
  END context_word[286]
  PIN context_word[287]
    DIRECTION INPUT ;
    USE SIGNAL ;
    PORT
      LAYER M4 ;
        RECT  107.916 66.432 108 66.456 ;
    END
  END context_word[287]
  PIN context_word[288]
    DIRECTION INPUT ;
    USE SIGNAL ;
    PORT
      LAYER M4 ;
        RECT  107.916 66.672 108 66.696 ;
    END
  END context_word[288]
  PIN context_word[289]
    DIRECTION INPUT ;
    USE SIGNAL ;
    PORT
      LAYER M4 ;
        RECT  107.916 66.912 108 66.936 ;
    END
  END context_word[289]
  PIN context_word[28]
    DIRECTION INPUT ;
    USE SIGNAL ;
    PORT
      LAYER M4 ;
        RECT  107.916 7.488 108 7.512 ;
    END
  END context_word[28]
  PIN context_word[290]
    DIRECTION INPUT ;
    USE SIGNAL ;
    PORT
      LAYER M4 ;
        RECT  107.916 67.104 108 67.128 ;
    END
  END context_word[290]
  PIN context_word[291]
    DIRECTION INPUT ;
    USE SIGNAL ;
    PORT
      LAYER M4 ;
        RECT  107.916 67.344 108 67.368 ;
    END
  END context_word[291]
  PIN context_word[292]
    DIRECTION INPUT ;
    USE SIGNAL ;
    PORT
      LAYER M4 ;
        RECT  107.916 67.584 108 67.608 ;
    END
  END context_word[292]
  PIN context_word[293]
    DIRECTION INPUT ;
    USE SIGNAL ;
    PORT
      LAYER M4 ;
        RECT  107.916 67.824 108 67.848 ;
    END
  END context_word[293]
  PIN context_word[294]
    DIRECTION INPUT ;
    USE SIGNAL ;
    PORT
      LAYER M4 ;
        RECT  107.916 68.016 108 68.04 ;
    END
  END context_word[294]
  PIN context_word[295]
    DIRECTION INPUT ;
    USE SIGNAL ;
    PORT
      LAYER M4 ;
        RECT  107.916 68.256 108 68.28 ;
    END
  END context_word[295]
  PIN context_word[296]
    DIRECTION INPUT ;
    USE SIGNAL ;
    PORT
      LAYER M4 ;
        RECT  107.916 68.496 108 68.52 ;
    END
  END context_word[296]
  PIN context_word[297]
    DIRECTION INPUT ;
    USE SIGNAL ;
    PORT
      LAYER M4 ;
        RECT  107.916 68.736 108 68.76 ;
    END
  END context_word[297]
  PIN context_word[298]
    DIRECTION INPUT ;
    USE SIGNAL ;
    PORT
      LAYER M4 ;
        RECT  107.916 68.928 108 68.952 ;
    END
  END context_word[298]
  PIN context_word[299]
    DIRECTION INPUT ;
    USE SIGNAL ;
    PORT
      LAYER M4 ;
        RECT  107.916 69.168 108 69.192 ;
    END
  END context_word[299]
  PIN context_word[29]
    DIRECTION INPUT ;
    USE SIGNAL ;
    PORT
      LAYER M4 ;
        RECT  107.916 7.728 108 7.752 ;
    END
  END context_word[29]
  PIN context_word[2]
    DIRECTION INPUT ;
    USE SIGNAL ;
    PORT
      LAYER M4 ;
        RECT  107.916 1.536 108 1.56 ;
    END
  END context_word[2]
  PIN context_word[300]
    DIRECTION INPUT ;
    USE SIGNAL ;
    PORT
      LAYER M4 ;
        RECT  107.916 69.408 108 69.432 ;
    END
  END context_word[300]
  PIN context_word[301]
    DIRECTION INPUT ;
    USE SIGNAL ;
    PORT
      LAYER M4 ;
        RECT  107.916 69.648 108 69.672 ;
    END
  END context_word[301]
  PIN context_word[302]
    DIRECTION INPUT ;
    USE SIGNAL ;
    PORT
      LAYER M4 ;
        RECT  107.916 69.84 108 69.864 ;
    END
  END context_word[302]
  PIN context_word[303]
    DIRECTION INPUT ;
    USE SIGNAL ;
    PORT
      LAYER M4 ;
        RECT  107.916 70.08 108 70.104 ;
    END
  END context_word[303]
  PIN context_word[304]
    DIRECTION INPUT ;
    USE SIGNAL ;
    PORT
      LAYER M4 ;
        RECT  107.916 70.32 108 70.344 ;
    END
  END context_word[304]
  PIN context_word[305]
    DIRECTION INPUT ;
    USE SIGNAL ;
    PORT
      LAYER M4 ;
        RECT  107.916 70.56 108 70.584 ;
    END
  END context_word[305]
  PIN context_word[306]
    DIRECTION INPUT ;
    USE SIGNAL ;
    PORT
      LAYER M4 ;
        RECT  107.916 70.752 108 70.776 ;
    END
  END context_word[306]
  PIN context_word[307]
    DIRECTION INPUT ;
    USE SIGNAL ;
    PORT
      LAYER M4 ;
        RECT  107.916 70.992 108 71.016 ;
    END
  END context_word[307]
  PIN context_word[308]
    DIRECTION INPUT ;
    USE SIGNAL ;
    PORT
      LAYER M4 ;
        RECT  107.916 71.232 108 71.256 ;
    END
  END context_word[308]
  PIN context_word[309]
    DIRECTION INPUT ;
    USE SIGNAL ;
    PORT
      LAYER M4 ;
        RECT  107.916 71.472 108 71.496 ;
    END
  END context_word[309]
  PIN context_word[30]
    DIRECTION INPUT ;
    USE SIGNAL ;
    PORT
      LAYER M4 ;
        RECT  107.916 7.92 108 7.944 ;
    END
  END context_word[30]
  PIN context_word[310]
    DIRECTION INPUT ;
    USE SIGNAL ;
    PORT
      LAYER M4 ;
        RECT  107.916 71.664 108 71.688 ;
    END
  END context_word[310]
  PIN context_word[311]
    DIRECTION INPUT ;
    USE SIGNAL ;
    PORT
      LAYER M4 ;
        RECT  107.916 71.904 108 71.928 ;
    END
  END context_word[311]
  PIN context_word[312]
    DIRECTION INPUT ;
    USE SIGNAL ;
    PORT
      LAYER M4 ;
        RECT  107.916 72.144 108 72.168 ;
    END
  END context_word[312]
  PIN context_word[313]
    DIRECTION INPUT ;
    USE SIGNAL ;
    PORT
      LAYER M4 ;
        RECT  107.916 72.384 108 72.408 ;
    END
  END context_word[313]
  PIN context_word[314]
    DIRECTION INPUT ;
    USE SIGNAL ;
    PORT
      LAYER M4 ;
        RECT  107.916 72.576 108 72.6 ;
    END
  END context_word[314]
  PIN context_word[315]
    DIRECTION INPUT ;
    USE SIGNAL ;
    PORT
      LAYER M4 ;
        RECT  107.916 72.816 108 72.84 ;
    END
  END context_word[315]
  PIN context_word[316]
    DIRECTION INPUT ;
    USE SIGNAL ;
    PORT
      LAYER M4 ;
        RECT  107.916 73.056 108 73.08 ;
    END
  END context_word[316]
  PIN context_word[317]
    DIRECTION INPUT ;
    USE SIGNAL ;
    PORT
      LAYER M4 ;
        RECT  107.916 73.296 108 73.32 ;
    END
  END context_word[317]
  PIN context_word[318]
    DIRECTION INPUT ;
    USE SIGNAL ;
    PORT
      LAYER M4 ;
        RECT  107.916 73.488 108 73.512 ;
    END
  END context_word[318]
  PIN context_word[319]
    DIRECTION INPUT ;
    USE SIGNAL ;
    PORT
      LAYER M4 ;
        RECT  107.916 73.728 108 73.752 ;
    END
  END context_word[319]
  PIN context_word[31]
    DIRECTION INPUT ;
    USE SIGNAL ;
    PORT
      LAYER M4 ;
        RECT  107.916 8.16 108 8.184 ;
    END
  END context_word[31]
  PIN context_word[320]
    DIRECTION INPUT ;
    USE SIGNAL ;
    PORT
      LAYER M4 ;
        RECT  107.916 73.968 108 73.992 ;
    END
  END context_word[320]
  PIN context_word[321]
    DIRECTION INPUT ;
    USE SIGNAL ;
    PORT
      LAYER M4 ;
        RECT  107.916 74.16 108 74.184 ;
    END
  END context_word[321]
  PIN context_word[322]
    DIRECTION INPUT ;
    USE SIGNAL ;
    PORT
      LAYER M4 ;
        RECT  107.916 74.4 108 74.424 ;
    END
  END context_word[322]
  PIN context_word[323]
    DIRECTION INPUT ;
    USE SIGNAL ;
    PORT
      LAYER M4 ;
        RECT  107.916 74.64 108 74.664 ;
    END
  END context_word[323]
  PIN context_word[324]
    DIRECTION INPUT ;
    USE SIGNAL ;
    PORT
      LAYER M4 ;
        RECT  107.916 74.88 108 74.904 ;
    END
  END context_word[324]
  PIN context_word[325]
    DIRECTION INPUT ;
    USE SIGNAL ;
    PORT
      LAYER M4 ;
        RECT  107.916 75.072 108 75.096 ;
    END
  END context_word[325]
  PIN context_word[326]
    DIRECTION INPUT ;
    USE SIGNAL ;
    PORT
      LAYER M4 ;
        RECT  107.916 75.312 108 75.336 ;
    END
  END context_word[326]
  PIN context_word[327]
    DIRECTION INPUT ;
    USE SIGNAL ;
    PORT
      LAYER M4 ;
        RECT  107.916 75.552 108 75.576 ;
    END
  END context_word[327]
  PIN context_word[328]
    DIRECTION INPUT ;
    USE SIGNAL ;
    PORT
      LAYER M4 ;
        RECT  107.916 75.792 108 75.816 ;
    END
  END context_word[328]
  PIN context_word[329]
    DIRECTION INPUT ;
    USE SIGNAL ;
    PORT
      LAYER M4 ;
        RECT  107.916 75.984 108 76.008 ;
    END
  END context_word[329]
  PIN context_word[32]
    DIRECTION INPUT ;
    USE SIGNAL ;
    PORT
      LAYER M4 ;
        RECT  107.916 8.4 108 8.424 ;
    END
  END context_word[32]
  PIN context_word[330]
    DIRECTION INPUT ;
    USE SIGNAL ;
    PORT
      LAYER M4 ;
        RECT  107.916 76.224 108 76.248 ;
    END
  END context_word[330]
  PIN context_word[331]
    DIRECTION INPUT ;
    USE SIGNAL ;
    PORT
      LAYER M4 ;
        RECT  107.916 76.464 108 76.488 ;
    END
  END context_word[331]
  PIN context_word[332]
    DIRECTION INPUT ;
    USE SIGNAL ;
    PORT
      LAYER M4 ;
        RECT  107.916 76.704 108 76.728 ;
    END
  END context_word[332]
  PIN context_word[333]
    DIRECTION INPUT ;
    USE SIGNAL ;
    PORT
      LAYER M4 ;
        RECT  107.916 76.896 108 76.92 ;
    END
  END context_word[333]
  PIN context_word[334]
    DIRECTION INPUT ;
    USE SIGNAL ;
    PORT
      LAYER M4 ;
        RECT  107.916 77.136 108 77.16 ;
    END
  END context_word[334]
  PIN context_word[335]
    DIRECTION INPUT ;
    USE SIGNAL ;
    PORT
      LAYER M4 ;
        RECT  107.916 77.376 108 77.4 ;
    END
  END context_word[335]
  PIN context_word[336]
    DIRECTION INPUT ;
    USE SIGNAL ;
    PORT
      LAYER M4 ;
        RECT  107.916 77.616 108 77.64 ;
    END
  END context_word[336]
  PIN context_word[337]
    DIRECTION INPUT ;
    USE SIGNAL ;
    PORT
      LAYER M4 ;
        RECT  107.916 77.808 108 77.832 ;
    END
  END context_word[337]
  PIN context_word[338]
    DIRECTION INPUT ;
    USE SIGNAL ;
    PORT
      LAYER M4 ;
        RECT  107.916 78.048 108 78.072 ;
    END
  END context_word[338]
  PIN context_word[339]
    DIRECTION INPUT ;
    USE SIGNAL ;
    PORT
      LAYER M4 ;
        RECT  107.916 78.288 108 78.312 ;
    END
  END context_word[339]
  PIN context_word[33]
    DIRECTION INPUT ;
    USE SIGNAL ;
    PORT
      LAYER M4 ;
        RECT  107.916 8.592 108 8.616 ;
    END
  END context_word[33]
  PIN context_word[340]
    DIRECTION INPUT ;
    USE SIGNAL ;
    PORT
      LAYER M4 ;
        RECT  107.916 78.528 108 78.552 ;
    END
  END context_word[340]
  PIN context_word[341]
    DIRECTION INPUT ;
    USE SIGNAL ;
    PORT
      LAYER M4 ;
        RECT  107.916 78.72 108 78.744 ;
    END
  END context_word[341]
  PIN context_word[342]
    DIRECTION INPUT ;
    USE SIGNAL ;
    PORT
      LAYER M4 ;
        RECT  107.916 78.96 108 78.984 ;
    END
  END context_word[342]
  PIN context_word[343]
    DIRECTION INPUT ;
    USE SIGNAL ;
    PORT
      LAYER M4 ;
        RECT  107.916 79.2 108 79.224 ;
    END
  END context_word[343]
  PIN context_word[344]
    DIRECTION INPUT ;
    USE SIGNAL ;
    PORT
      LAYER M4 ;
        RECT  107.916 79.44 108 79.464 ;
    END
  END context_word[344]
  PIN context_word[345]
    DIRECTION INPUT ;
    USE SIGNAL ;
    PORT
      LAYER M4 ;
        RECT  107.916 79.632 108 79.656 ;
    END
  END context_word[345]
  PIN context_word[346]
    DIRECTION INPUT ;
    USE SIGNAL ;
    PORT
      LAYER M4 ;
        RECT  107.916 79.872 108 79.896 ;
    END
  END context_word[346]
  PIN context_word[34]
    DIRECTION INPUT ;
    USE SIGNAL ;
    PORT
      LAYER M4 ;
        RECT  107.916 8.832 108 8.856 ;
    END
  END context_word[34]
  PIN context_word[35]
    DIRECTION INPUT ;
    USE SIGNAL ;
    PORT
      LAYER M4 ;
        RECT  107.916 9.072 108 9.096 ;
    END
  END context_word[35]
  PIN context_word[36]
    DIRECTION INPUT ;
    USE SIGNAL ;
    PORT
      LAYER M4 ;
        RECT  107.916 9.312 108 9.336 ;
    END
  END context_word[36]
  PIN context_word[37]
    DIRECTION INPUT ;
    USE SIGNAL ;
    PORT
      LAYER M4 ;
        RECT  107.916 9.504 108 9.528 ;
    END
  END context_word[37]
  PIN context_word[38]
    DIRECTION INPUT ;
    USE SIGNAL ;
    PORT
      LAYER M4 ;
        RECT  107.916 9.744 108 9.768 ;
    END
  END context_word[38]
  PIN context_word[39]
    DIRECTION INPUT ;
    USE SIGNAL ;
    PORT
      LAYER M4 ;
        RECT  107.916 9.984 108 10.008 ;
    END
  END context_word[39]
  PIN context_word[3]
    DIRECTION INPUT ;
    USE SIGNAL ;
    PORT
      LAYER M4 ;
        RECT  107.916 1.776 108 1.8 ;
    END
  END context_word[3]
  PIN context_word[40]
    DIRECTION INPUT ;
    USE SIGNAL ;
    PORT
      LAYER M4 ;
        RECT  107.916 10.224 108 10.248 ;
    END
  END context_word[40]
  PIN context_word[41]
    DIRECTION INPUT ;
    USE SIGNAL ;
    PORT
      LAYER M4 ;
        RECT  107.916 10.416 108 10.44 ;
    END
  END context_word[41]
  PIN context_word[42]
    DIRECTION INPUT ;
    USE SIGNAL ;
    PORT
      LAYER M4 ;
        RECT  107.916 10.656 108 10.68 ;
    END
  END context_word[42]
  PIN context_word[43]
    DIRECTION INPUT ;
    USE SIGNAL ;
    PORT
      LAYER M4 ;
        RECT  107.916 10.896 108 10.92 ;
    END
  END context_word[43]
  PIN context_word[44]
    DIRECTION INPUT ;
    USE SIGNAL ;
    PORT
      LAYER M4 ;
        RECT  107.916 11.136 108 11.16 ;
    END
  END context_word[44]
  PIN context_word[45]
    DIRECTION INPUT ;
    USE SIGNAL ;
    PORT
      LAYER M4 ;
        RECT  107.916 11.328 108 11.352 ;
    END
  END context_word[45]
  PIN context_word[46]
    DIRECTION INPUT ;
    USE SIGNAL ;
    PORT
      LAYER M4 ;
        RECT  107.916 11.568 108 11.592 ;
    END
  END context_word[46]
  PIN context_word[47]
    DIRECTION INPUT ;
    USE SIGNAL ;
    PORT
      LAYER M4 ;
        RECT  107.916 11.808 108 11.832 ;
    END
  END context_word[47]
  PIN context_word[48]
    DIRECTION INPUT ;
    USE SIGNAL ;
    PORT
      LAYER M4 ;
        RECT  107.916 12.048 108 12.072 ;
    END
  END context_word[48]
  PIN context_word[49]
    DIRECTION INPUT ;
    USE SIGNAL ;
    PORT
      LAYER M4 ;
        RECT  107.916 12.24 108 12.264 ;
    END
  END context_word[49]
  PIN context_word[4]
    DIRECTION INPUT ;
    USE SIGNAL ;
    PORT
      LAYER M4 ;
        RECT  107.916 2.016 108 2.04 ;
    END
  END context_word[4]
  PIN context_word[50]
    DIRECTION INPUT ;
    USE SIGNAL ;
    PORT
      LAYER M4 ;
        RECT  107.916 12.48 108 12.504 ;
    END
  END context_word[50]
  PIN context_word[51]
    DIRECTION INPUT ;
    USE SIGNAL ;
    PORT
      LAYER M4 ;
        RECT  107.916 12.72 108 12.744 ;
    END
  END context_word[51]
  PIN context_word[52]
    DIRECTION INPUT ;
    USE SIGNAL ;
    PORT
      LAYER M4 ;
        RECT  107.916 12.96 108 12.984 ;
    END
  END context_word[52]
  PIN context_word[53]
    DIRECTION INPUT ;
    USE SIGNAL ;
    PORT
      LAYER M4 ;
        RECT  107.916 13.152 108 13.176 ;
    END
  END context_word[53]
  PIN context_word[54]
    DIRECTION INPUT ;
    USE SIGNAL ;
    PORT
      LAYER M4 ;
        RECT  107.916 13.392 108 13.416 ;
    END
  END context_word[54]
  PIN context_word[55]
    DIRECTION INPUT ;
    USE SIGNAL ;
    PORT
      LAYER M4 ;
        RECT  107.916 13.632 108 13.656 ;
    END
  END context_word[55]
  PIN context_word[56]
    DIRECTION INPUT ;
    USE SIGNAL ;
    PORT
      LAYER M4 ;
        RECT  107.916 13.872 108 13.896 ;
    END
  END context_word[56]
  PIN context_word[57]
    DIRECTION INPUT ;
    USE SIGNAL ;
    PORT
      LAYER M4 ;
        RECT  107.916 14.064 108 14.088 ;
    END
  END context_word[57]
  PIN context_word[58]
    DIRECTION INPUT ;
    USE SIGNAL ;
    PORT
      LAYER M4 ;
        RECT  107.916 14.304 108 14.328 ;
    END
  END context_word[58]
  PIN context_word[59]
    DIRECTION INPUT ;
    USE SIGNAL ;
    PORT
      LAYER M4 ;
        RECT  107.916 14.544 108 14.568 ;
    END
  END context_word[59]
  PIN context_word[5]
    DIRECTION INPUT ;
    USE SIGNAL ;
    PORT
      LAYER M4 ;
        RECT  107.916 2.256 108 2.28 ;
    END
  END context_word[5]
  PIN context_word[60]
    DIRECTION INPUT ;
    USE SIGNAL ;
    PORT
      LAYER M4 ;
        RECT  107.916 14.784 108 14.808 ;
    END
  END context_word[60]
  PIN context_word[61]
    DIRECTION INPUT ;
    USE SIGNAL ;
    PORT
      LAYER M4 ;
        RECT  107.916 14.976 108 15 ;
    END
  END context_word[61]
  PIN context_word[62]
    DIRECTION INPUT ;
    USE SIGNAL ;
    PORT
      LAYER M4 ;
        RECT  107.916 15.216 108 15.24 ;
    END
  END context_word[62]
  PIN context_word[63]
    DIRECTION INPUT ;
    USE SIGNAL ;
    PORT
      LAYER M4 ;
        RECT  107.916 15.456 108 15.48 ;
    END
  END context_word[63]
  PIN context_word[64]
    DIRECTION INPUT ;
    USE SIGNAL ;
    PORT
      LAYER M4 ;
        RECT  107.916 15.696 108 15.72 ;
    END
  END context_word[64]
  PIN context_word[65]
    DIRECTION INPUT ;
    USE SIGNAL ;
    PORT
      LAYER M4 ;
        RECT  107.916 15.888 108 15.912 ;
    END
  END context_word[65]
  PIN context_word[66]
    DIRECTION INPUT ;
    USE SIGNAL ;
    PORT
      LAYER M4 ;
        RECT  107.916 16.128 108 16.152 ;
    END
  END context_word[66]
  PIN context_word[67]
    DIRECTION INPUT ;
    USE SIGNAL ;
    PORT
      LAYER M4 ;
        RECT  107.916 16.368 108 16.392 ;
    END
  END context_word[67]
  PIN context_word[68]
    DIRECTION INPUT ;
    USE SIGNAL ;
    PORT
      LAYER M4 ;
        RECT  107.916 16.56 108 16.584 ;
    END
  END context_word[68]
  PIN context_word[69]
    DIRECTION INPUT ;
    USE SIGNAL ;
    PORT
      LAYER M4 ;
        RECT  107.916 16.8 108 16.824 ;
    END
  END context_word[69]
  PIN context_word[6]
    DIRECTION INPUT ;
    USE SIGNAL ;
    PORT
      LAYER M4 ;
        RECT  107.916 2.448 108 2.472 ;
    END
  END context_word[6]
  PIN context_word[70]
    DIRECTION INPUT ;
    USE SIGNAL ;
    PORT
      LAYER M4 ;
        RECT  107.916 17.04 108 17.064 ;
    END
  END context_word[70]
  PIN context_word[71]
    DIRECTION INPUT ;
    USE SIGNAL ;
    PORT
      LAYER M4 ;
        RECT  107.916 17.28 108 17.304 ;
    END
  END context_word[71]
  PIN context_word[72]
    DIRECTION INPUT ;
    USE SIGNAL ;
    PORT
      LAYER M4 ;
        RECT  107.916 17.472 108 17.496 ;
    END
  END context_word[72]
  PIN context_word[73]
    DIRECTION INPUT ;
    USE SIGNAL ;
    PORT
      LAYER M4 ;
        RECT  107.916 17.712 108 17.736 ;
    END
  END context_word[73]
  PIN context_word[74]
    DIRECTION INPUT ;
    USE SIGNAL ;
    PORT
      LAYER M4 ;
        RECT  107.916 17.952 108 17.976 ;
    END
  END context_word[74]
  PIN context_word[75]
    DIRECTION INPUT ;
    USE SIGNAL ;
    PORT
      LAYER M4 ;
        RECT  107.916 18.192 108 18.216 ;
    END
  END context_word[75]
  PIN context_word[76]
    DIRECTION INPUT ;
    USE SIGNAL ;
    PORT
      LAYER M4 ;
        RECT  107.916 18.384 108 18.408 ;
    END
  END context_word[76]
  PIN context_word[77]
    DIRECTION INPUT ;
    USE SIGNAL ;
    PORT
      LAYER M4 ;
        RECT  107.916 18.624 108 18.648 ;
    END
  END context_word[77]
  PIN context_word[78]
    DIRECTION INPUT ;
    USE SIGNAL ;
    PORT
      LAYER M4 ;
        RECT  107.916 18.864 108 18.888 ;
    END
  END context_word[78]
  PIN context_word[79]
    DIRECTION INPUT ;
    USE SIGNAL ;
    PORT
      LAYER M4 ;
        RECT  107.916 19.104 108 19.128 ;
    END
  END context_word[79]
  PIN context_word[7]
    DIRECTION INPUT ;
    USE SIGNAL ;
    PORT
      LAYER M4 ;
        RECT  107.916 2.688 108 2.712 ;
    END
  END context_word[7]
  PIN context_word[80]
    DIRECTION INPUT ;
    USE SIGNAL ;
    PORT
      LAYER M4 ;
        RECT  107.916 19.296 108 19.32 ;
    END
  END context_word[80]
  PIN context_word[81]
    DIRECTION INPUT ;
    USE SIGNAL ;
    PORT
      LAYER M4 ;
        RECT  107.916 19.536 108 19.56 ;
    END
  END context_word[81]
  PIN context_word[82]
    DIRECTION INPUT ;
    USE SIGNAL ;
    PORT
      LAYER M4 ;
        RECT  107.916 19.776 108 19.8 ;
    END
  END context_word[82]
  PIN context_word[83]
    DIRECTION INPUT ;
    USE SIGNAL ;
    PORT
      LAYER M4 ;
        RECT  107.916 20.016 108 20.04 ;
    END
  END context_word[83]
  PIN context_word[84]
    DIRECTION INPUT ;
    USE SIGNAL ;
    PORT
      LAYER M4 ;
        RECT  107.916 20.208 108 20.232 ;
    END
  END context_word[84]
  PIN context_word[85]
    DIRECTION INPUT ;
    USE SIGNAL ;
    PORT
      LAYER M4 ;
        RECT  107.916 20.448 108 20.472 ;
    END
  END context_word[85]
  PIN context_word[86]
    DIRECTION INPUT ;
    USE SIGNAL ;
    PORT
      LAYER M4 ;
        RECT  107.916 20.688 108 20.712 ;
    END
  END context_word[86]
  PIN context_word[87]
    DIRECTION INPUT ;
    USE SIGNAL ;
    PORT
      LAYER M4 ;
        RECT  107.916 20.928 108 20.952 ;
    END
  END context_word[87]
  PIN context_word[88]
    DIRECTION INPUT ;
    USE SIGNAL ;
    PORT
      LAYER M4 ;
        RECT  107.916 21.12 108 21.144 ;
    END
  END context_word[88]
  PIN context_word[89]
    DIRECTION INPUT ;
    USE SIGNAL ;
    PORT
      LAYER M4 ;
        RECT  107.916 21.36 108 21.384 ;
    END
  END context_word[89]
  PIN context_word[8]
    DIRECTION INPUT ;
    USE SIGNAL ;
    PORT
      LAYER M4 ;
        RECT  107.916 2.928 108 2.952 ;
    END
  END context_word[8]
  PIN context_word[90]
    DIRECTION INPUT ;
    USE SIGNAL ;
    PORT
      LAYER M4 ;
        RECT  107.916 21.6 108 21.624 ;
    END
  END context_word[90]
  PIN context_word[91]
    DIRECTION INPUT ;
    USE SIGNAL ;
    PORT
      LAYER M4 ;
        RECT  107.916 21.84 108 21.864 ;
    END
  END context_word[91]
  PIN context_word[92]
    DIRECTION INPUT ;
    USE SIGNAL ;
    PORT
      LAYER M4 ;
        RECT  107.916 22.032 108 22.056 ;
    END
  END context_word[92]
  PIN context_word[93]
    DIRECTION INPUT ;
    USE SIGNAL ;
    PORT
      LAYER M4 ;
        RECT  107.916 22.272 108 22.296 ;
    END
  END context_word[93]
  PIN context_word[94]
    DIRECTION INPUT ;
    USE SIGNAL ;
    PORT
      LAYER M4 ;
        RECT  107.916 22.512 108 22.536 ;
    END
  END context_word[94]
  PIN context_word[95]
    DIRECTION INPUT ;
    USE SIGNAL ;
    PORT
      LAYER M4 ;
        RECT  107.916 22.752 108 22.776 ;
    END
  END context_word[95]
  PIN context_word[96]
    DIRECTION INPUT ;
    USE SIGNAL ;
    PORT
      LAYER M4 ;
        RECT  107.916 22.944 108 22.968 ;
    END
  END context_word[96]
  PIN context_word[97]
    DIRECTION INPUT ;
    USE SIGNAL ;
    PORT
      LAYER M4 ;
        RECT  107.916 23.184 108 23.208 ;
    END
  END context_word[97]
  PIN context_word[98]
    DIRECTION INPUT ;
    USE SIGNAL ;
    PORT
      LAYER M4 ;
        RECT  107.916 23.424 108 23.448 ;
    END
  END context_word[98]
  PIN context_word[99]
    DIRECTION INPUT ;
    USE SIGNAL ;
    PORT
      LAYER M4 ;
        RECT  107.916 23.664 108 23.688 ;
    END
  END context_word[99]
  PIN context_word[9]
    DIRECTION INPUT ;
    USE SIGNAL ;
    PORT
      LAYER M4 ;
        RECT  107.916 3.168 108 3.192 ;
    END
  END context_word[9]
  PIN expected_static_column
    DIRECTION INPUT ;
    USE SIGNAL ;
    PORT
      LAYER M5 ;
        RECT  1.152 0 1.176 0.084 ;
    END
  END expected_static_column
  PIN fault
    DIRECTION OUTPUT ;
    USE SIGNAL ;
    PORT
      LAYER M5 ;
        RECT  1.488 0 1.512 0.084 ;
    END
  END fault
  PIN hrst
    DIRECTION INPUT ;
    USE SIGNAL ;
    PORT
      LAYER M5 ;
        RECT  1.776 0 1.8 0.084 ;
    END
  END hrst
  PIN native_commit_address[0]
    DIRECTION OUTPUT ;
    USE SIGNAL ;
    PORT
      LAYER M5 ;
        RECT  1.584 80.916 1.608 81 ;
    END
  END native_commit_address[0]
  PIN native_commit_address[10]
    DIRECTION OUTPUT ;
    USE SIGNAL ;
    PORT
      LAYER M5 ;
        RECT  13.344 80.916 13.368 81 ;
    END
  END native_commit_address[10]
  PIN native_commit_address[11]
    DIRECTION OUTPUT ;
    USE SIGNAL ;
    PORT
      LAYER M5 ;
        RECT  14.544 80.916 14.568 81 ;
    END
  END native_commit_address[11]
  PIN native_commit_address[12]
    DIRECTION OUTPUT ;
    USE SIGNAL ;
    PORT
      LAYER M5 ;
        RECT  15.696 80.916 15.72 81 ;
    END
  END native_commit_address[12]
  PIN native_commit_address[13]
    DIRECTION OUTPUT ;
    USE SIGNAL ;
    PORT
      LAYER M5 ;
        RECT  16.896 80.916 16.92 81 ;
    END
  END native_commit_address[13]
  PIN native_commit_address[14]
    DIRECTION OUTPUT ;
    USE SIGNAL ;
    PORT
      LAYER M5 ;
        RECT  18.048 80.916 18.072 81 ;
    END
  END native_commit_address[14]
  PIN native_commit_address[15]
    DIRECTION OUTPUT ;
    USE SIGNAL ;
    PORT
      LAYER M5 ;
        RECT  19.248 80.916 19.272 81 ;
    END
  END native_commit_address[15]
  PIN native_commit_address[16]
    DIRECTION OUTPUT ;
    USE SIGNAL ;
    PORT
      LAYER M5 ;
        RECT  20.4 80.916 20.424 81 ;
    END
  END native_commit_address[16]
  PIN native_commit_address[17]
    DIRECTION OUTPUT ;
    USE SIGNAL ;
    PORT
      LAYER M5 ;
        RECT  21.6 80.916 21.624 81 ;
    END
  END native_commit_address[17]
  PIN native_commit_address[18]
    DIRECTION OUTPUT ;
    USE SIGNAL ;
    PORT
      LAYER M5 ;
        RECT  22.8 80.916 22.824 81 ;
    END
  END native_commit_address[18]
  PIN native_commit_address[19]
    DIRECTION OUTPUT ;
    USE SIGNAL ;
    PORT
      LAYER M5 ;
        RECT  23.952 80.916 23.976 81 ;
    END
  END native_commit_address[19]
  PIN native_commit_address[1]
    DIRECTION OUTPUT ;
    USE SIGNAL ;
    PORT
      LAYER M5 ;
        RECT  2.736 80.916 2.76 81 ;
    END
  END native_commit_address[1]
  PIN native_commit_address[20]
    DIRECTION OUTPUT ;
    USE SIGNAL ;
    PORT
      LAYER M5 ;
        RECT  25.152 80.916 25.176 81 ;
    END
  END native_commit_address[20]
  PIN native_commit_address[21]
    DIRECTION OUTPUT ;
    USE SIGNAL ;
    PORT
      LAYER M5 ;
        RECT  26.304 80.916 26.328 81 ;
    END
  END native_commit_address[21]
  PIN native_commit_address[22]
    DIRECTION OUTPUT ;
    USE SIGNAL ;
    PORT
      LAYER M5 ;
        RECT  27.504 80.916 27.528 81 ;
    END
  END native_commit_address[22]
  PIN native_commit_address[23]
    DIRECTION OUTPUT ;
    USE SIGNAL ;
    PORT
      LAYER M5 ;
        RECT  28.656 80.916 28.68 81 ;
    END
  END native_commit_address[23]
  PIN native_commit_address[24]
    DIRECTION OUTPUT ;
    USE SIGNAL ;
    PORT
      LAYER M5 ;
        RECT  29.856 80.916 29.88 81 ;
    END
  END native_commit_address[24]
  PIN native_commit_address[25]
    DIRECTION OUTPUT ;
    USE SIGNAL ;
    PORT
      LAYER M5 ;
        RECT  31.008 80.916 31.032 81 ;
    END
  END native_commit_address[25]
  PIN native_commit_address[26]
    DIRECTION OUTPUT ;
    USE SIGNAL ;
    PORT
      LAYER M5 ;
        RECT  32.208 80.916 32.232 81 ;
    END
  END native_commit_address[26]
  PIN native_commit_address[27]
    DIRECTION OUTPUT ;
    USE SIGNAL ;
    PORT
      LAYER M5 ;
        RECT  33.36 80.916 33.384 81 ;
    END
  END native_commit_address[27]
  PIN native_commit_address[28]
    DIRECTION OUTPUT ;
    USE SIGNAL ;
    PORT
      LAYER M5 ;
        RECT  34.56 80.916 34.584 81 ;
    END
  END native_commit_address[28]
  PIN native_commit_address[2]
    DIRECTION OUTPUT ;
    USE SIGNAL ;
    PORT
      LAYER M5 ;
        RECT  3.936 80.916 3.96 81 ;
    END
  END native_commit_address[2]
  PIN native_commit_address[3]
    DIRECTION OUTPUT ;
    USE SIGNAL ;
    PORT
      LAYER M5 ;
        RECT  5.088 80.916 5.112 81 ;
    END
  END native_commit_address[3]
  PIN native_commit_address[4]
    DIRECTION OUTPUT ;
    USE SIGNAL ;
    PORT
      LAYER M5 ;
        RECT  6.288 80.916 6.312 81 ;
    END
  END native_commit_address[4]
  PIN native_commit_address[5]
    DIRECTION OUTPUT ;
    USE SIGNAL ;
    PORT
      LAYER M5 ;
        RECT  7.488 80.916 7.512 81 ;
    END
  END native_commit_address[5]
  PIN native_commit_address[6]
    DIRECTION OUTPUT ;
    USE SIGNAL ;
    PORT
      LAYER M5 ;
        RECT  8.64 80.916 8.664 81 ;
    END
  END native_commit_address[6]
  PIN native_commit_address[7]
    DIRECTION OUTPUT ;
    USE SIGNAL ;
    PORT
      LAYER M5 ;
        RECT  9.84 80.916 9.864 81 ;
    END
  END native_commit_address[7]
  PIN native_commit_address[8]
    DIRECTION OUTPUT ;
    USE SIGNAL ;
    PORT
      LAYER M5 ;
        RECT  10.992 80.916 11.016 81 ;
    END
  END native_commit_address[8]
  PIN native_commit_address[9]
    DIRECTION OUTPUT ;
    USE SIGNAL ;
    PORT
      LAYER M5 ;
        RECT  12.192 80.916 12.216 81 ;
    END
  END native_commit_address[9]
  PIN native_commit_identity[0]
    DIRECTION OUTPUT ;
    USE SIGNAL ;
    PORT
      LAYER M5 ;
        RECT  35.712 80.916 35.736 81 ;
    END
  END native_commit_identity[0]
  PIN native_commit_identity[10]
    DIRECTION OUTPUT ;
    USE SIGNAL ;
    PORT
      LAYER M5 ;
        RECT  47.52 80.916 47.544 81 ;
    END
  END native_commit_identity[10]
  PIN native_commit_identity[11]
    DIRECTION OUTPUT ;
    USE SIGNAL ;
    PORT
      LAYER M5 ;
        RECT  48.672 80.916 48.696 81 ;
    END
  END native_commit_identity[11]
  PIN native_commit_identity[12]
    DIRECTION OUTPUT ;
    USE SIGNAL ;
    PORT
      LAYER M5 ;
        RECT  49.872 80.916 49.896 81 ;
    END
  END native_commit_identity[12]
  PIN native_commit_identity[13]
    DIRECTION OUTPUT ;
    USE SIGNAL ;
    PORT
      LAYER M5 ;
        RECT  51.024 80.916 51.048 81 ;
    END
  END native_commit_identity[13]
  PIN native_commit_identity[14]
    DIRECTION OUTPUT ;
    USE SIGNAL ;
    PORT
      LAYER M5 ;
        RECT  52.224 80.916 52.248 81 ;
    END
  END native_commit_identity[14]
  PIN native_commit_identity[15]
    DIRECTION OUTPUT ;
    USE SIGNAL ;
    PORT
      LAYER M5 ;
        RECT  53.376 80.916 53.4 81 ;
    END
  END native_commit_identity[15]
  PIN native_commit_identity[16]
    DIRECTION OUTPUT ;
    USE SIGNAL ;
    PORT
      LAYER M5 ;
        RECT  54.576 80.916 54.6 81 ;
    END
  END native_commit_identity[16]
  PIN native_commit_identity[17]
    DIRECTION OUTPUT ;
    USE SIGNAL ;
    PORT
      LAYER M5 ;
        RECT  55.776 80.916 55.8 81 ;
    END
  END native_commit_identity[17]
  PIN native_commit_identity[18]
    DIRECTION OUTPUT ;
    USE SIGNAL ;
    PORT
      LAYER M5 ;
        RECT  56.928 80.916 56.952 81 ;
    END
  END native_commit_identity[18]
  PIN native_commit_identity[19]
    DIRECTION OUTPUT ;
    USE SIGNAL ;
    PORT
      LAYER M5 ;
        RECT  58.128 80.916 58.152 81 ;
    END
  END native_commit_identity[19]
  PIN native_commit_identity[1]
    DIRECTION OUTPUT ;
    USE SIGNAL ;
    PORT
      LAYER M5 ;
        RECT  36.912 80.916 36.936 81 ;
    END
  END native_commit_identity[1]
  PIN native_commit_identity[20]
    DIRECTION OUTPUT ;
    USE SIGNAL ;
    PORT
      LAYER M5 ;
        RECT  59.28 80.916 59.304 81 ;
    END
  END native_commit_identity[20]
  PIN native_commit_identity[21]
    DIRECTION OUTPUT ;
    USE SIGNAL ;
    PORT
      LAYER M5 ;
        RECT  60.48 80.916 60.504 81 ;
    END
  END native_commit_identity[21]
  PIN native_commit_identity[22]
    DIRECTION OUTPUT ;
    USE SIGNAL ;
    PORT
      LAYER M5 ;
        RECT  61.632 80.916 61.656 81 ;
    END
  END native_commit_identity[22]
  PIN native_commit_identity[23]
    DIRECTION OUTPUT ;
    USE SIGNAL ;
    PORT
      LAYER M5 ;
        RECT  62.832 80.916 62.856 81 ;
    END
  END native_commit_identity[23]
  PIN native_commit_identity[24]
    DIRECTION OUTPUT ;
    USE SIGNAL ;
    PORT
      LAYER M5 ;
        RECT  63.984 80.916 64.008 81 ;
    END
  END native_commit_identity[24]
  PIN native_commit_identity[25]
    DIRECTION OUTPUT ;
    USE SIGNAL ;
    PORT
      LAYER M5 ;
        RECT  65.184 80.916 65.208 81 ;
    END
  END native_commit_identity[25]
  PIN native_commit_identity[26]
    DIRECTION OUTPUT ;
    USE SIGNAL ;
    PORT
      LAYER M5 ;
        RECT  66.336 80.916 66.36 81 ;
    END
  END native_commit_identity[26]
  PIN native_commit_identity[27]
    DIRECTION OUTPUT ;
    USE SIGNAL ;
    PORT
      LAYER M5 ;
        RECT  67.536 80.916 67.56 81 ;
    END
  END native_commit_identity[27]
  PIN native_commit_identity[28]
    DIRECTION OUTPUT ;
    USE SIGNAL ;
    PORT
      LAYER M5 ;
        RECT  68.688 80.916 68.712 81 ;
    END
  END native_commit_identity[28]
  PIN native_commit_identity[29]
    DIRECTION OUTPUT ;
    USE SIGNAL ;
    PORT
      LAYER M5 ;
        RECT  69.888 80.916 69.912 81 ;
    END
  END native_commit_identity[29]
  PIN native_commit_identity[2]
    DIRECTION OUTPUT ;
    USE SIGNAL ;
    PORT
      LAYER M5 ;
        RECT  38.112 80.916 38.136 81 ;
    END
  END native_commit_identity[2]
  PIN native_commit_identity[30]
    DIRECTION OUTPUT ;
    USE SIGNAL ;
    PORT
      LAYER M5 ;
        RECT  71.088 80.916 71.112 81 ;
    END
  END native_commit_identity[30]
  PIN native_commit_identity[31]
    DIRECTION OUTPUT ;
    USE SIGNAL ;
    PORT
      LAYER M5 ;
        RECT  72.24 80.916 72.264 81 ;
    END
  END native_commit_identity[31]
  PIN native_commit_identity[32]
    DIRECTION OUTPUT ;
    USE SIGNAL ;
    PORT
      LAYER M5 ;
        RECT  73.44 80.916 73.464 81 ;
    END
  END native_commit_identity[32]
  PIN native_commit_identity[33]
    DIRECTION OUTPUT ;
    USE SIGNAL ;
    PORT
      LAYER M5 ;
        RECT  74.592 80.916 74.616 81 ;
    END
  END native_commit_identity[33]
  PIN native_commit_identity[34]
    DIRECTION OUTPUT ;
    USE SIGNAL ;
    PORT
      LAYER M5 ;
        RECT  75.792 80.916 75.816 81 ;
    END
  END native_commit_identity[34]
  PIN native_commit_identity[35]
    DIRECTION OUTPUT ;
    USE SIGNAL ;
    PORT
      LAYER M5 ;
        RECT  76.944 80.916 76.968 81 ;
    END
  END native_commit_identity[35]
  PIN native_commit_identity[36]
    DIRECTION OUTPUT ;
    USE SIGNAL ;
    PORT
      LAYER M5 ;
        RECT  78.144 80.916 78.168 81 ;
    END
  END native_commit_identity[36]
  PIN native_commit_identity[37]
    DIRECTION OUTPUT ;
    USE SIGNAL ;
    PORT
      LAYER M5 ;
        RECT  79.296 80.916 79.32 81 ;
    END
  END native_commit_identity[37]
  PIN native_commit_identity[38]
    DIRECTION OUTPUT ;
    USE SIGNAL ;
    PORT
      LAYER M5 ;
        RECT  80.496 80.916 80.52 81 ;
    END
  END native_commit_identity[38]
  PIN native_commit_identity[39]
    DIRECTION OUTPUT ;
    USE SIGNAL ;
    PORT
      LAYER M5 ;
        RECT  81.648 80.916 81.672 81 ;
    END
  END native_commit_identity[39]
  PIN native_commit_identity[3]
    DIRECTION OUTPUT ;
    USE SIGNAL ;
    PORT
      LAYER M5 ;
        RECT  39.264 80.916 39.288 81 ;
    END
  END native_commit_identity[3]
  PIN native_commit_identity[40]
    DIRECTION OUTPUT ;
    USE SIGNAL ;
    PORT
      LAYER M5 ;
        RECT  82.848 80.916 82.872 81 ;
    END
  END native_commit_identity[40]
  PIN native_commit_identity[41]
    DIRECTION OUTPUT ;
    USE SIGNAL ;
    PORT
      LAYER M5 ;
        RECT  84 80.916 84.024 81 ;
    END
  END native_commit_identity[41]
  PIN native_commit_identity[42]
    DIRECTION OUTPUT ;
    USE SIGNAL ;
    PORT
      LAYER M5 ;
        RECT  85.2 80.916 85.224 81 ;
    END
  END native_commit_identity[42]
  PIN native_commit_identity[43]
    DIRECTION OUTPUT ;
    USE SIGNAL ;
    PORT
      LAYER M5 ;
        RECT  86.4 80.916 86.424 81 ;
    END
  END native_commit_identity[43]
  PIN native_commit_identity[44]
    DIRECTION OUTPUT ;
    USE SIGNAL ;
    PORT
      LAYER M5 ;
        RECT  87.552 80.916 87.576 81 ;
    END
  END native_commit_identity[44]
  PIN native_commit_identity[45]
    DIRECTION OUTPUT ;
    USE SIGNAL ;
    PORT
      LAYER M5 ;
        RECT  88.752 80.916 88.776 81 ;
    END
  END native_commit_identity[45]
  PIN native_commit_identity[46]
    DIRECTION OUTPUT ;
    USE SIGNAL ;
    PORT
      LAYER M5 ;
        RECT  89.904 80.916 89.928 81 ;
    END
  END native_commit_identity[46]
  PIN native_commit_identity[47]
    DIRECTION OUTPUT ;
    USE SIGNAL ;
    PORT
      LAYER M5 ;
        RECT  91.104 80.916 91.128 81 ;
    END
  END native_commit_identity[47]
  PIN native_commit_identity[48]
    DIRECTION OUTPUT ;
    USE SIGNAL ;
    PORT
      LAYER M5 ;
        RECT  92.256 80.916 92.28 81 ;
    END
  END native_commit_identity[48]
  PIN native_commit_identity[49]
    DIRECTION OUTPUT ;
    USE SIGNAL ;
    PORT
      LAYER M5 ;
        RECT  93.456 80.916 93.48 81 ;
    END
  END native_commit_identity[49]
  PIN native_commit_identity[4]
    DIRECTION OUTPUT ;
    USE SIGNAL ;
    PORT
      LAYER M5 ;
        RECT  40.464 80.916 40.488 81 ;
    END
  END native_commit_identity[4]
  PIN native_commit_identity[50]
    DIRECTION OUTPUT ;
    USE SIGNAL ;
    PORT
      LAYER M5 ;
        RECT  94.608 80.916 94.632 81 ;
    END
  END native_commit_identity[50]
  PIN native_commit_identity[51]
    DIRECTION OUTPUT ;
    USE SIGNAL ;
    PORT
      LAYER M5 ;
        RECT  95.808 80.916 95.832 81 ;
    END
  END native_commit_identity[51]
  PIN native_commit_identity[52]
    DIRECTION OUTPUT ;
    USE SIGNAL ;
    PORT
      LAYER M5 ;
        RECT  96.96 80.916 96.984 81 ;
    END
  END native_commit_identity[52]
  PIN native_commit_identity[53]
    DIRECTION OUTPUT ;
    USE SIGNAL ;
    PORT
      LAYER M5 ;
        RECT  98.16 80.916 98.184 81 ;
    END
  END native_commit_identity[53]
  PIN native_commit_identity[54]
    DIRECTION OUTPUT ;
    USE SIGNAL ;
    PORT
      LAYER M5 ;
        RECT  99.312 80.916 99.336 81 ;
    END
  END native_commit_identity[54]
  PIN native_commit_identity[55]
    DIRECTION OUTPUT ;
    USE SIGNAL ;
    PORT
      LAYER M5 ;
        RECT  100.512 80.916 100.536 81 ;
    END
  END native_commit_identity[55]
  PIN native_commit_identity[56]
    DIRECTION OUTPUT ;
    USE SIGNAL ;
    PORT
      LAYER M5 ;
        RECT  101.712 80.916 101.736 81 ;
    END
  END native_commit_identity[56]
  PIN native_commit_identity[57]
    DIRECTION OUTPUT ;
    USE SIGNAL ;
    PORT
      LAYER M5 ;
        RECT  102.864 80.916 102.888 81 ;
    END
  END native_commit_identity[57]
  PIN native_commit_identity[58]
    DIRECTION OUTPUT ;
    USE SIGNAL ;
    PORT
      LAYER M5 ;
        RECT  104.064 80.916 104.088 81 ;
    END
  END native_commit_identity[58]
  PIN native_commit_identity[59]
    DIRECTION OUTPUT ;
    USE SIGNAL ;
    PORT
      LAYER M5 ;
        RECT  105.216 80.916 105.24 81 ;
    END
  END native_commit_identity[59]
  PIN native_commit_identity[5]
    DIRECTION OUTPUT ;
    USE SIGNAL ;
    PORT
      LAYER M5 ;
        RECT  41.616 80.916 41.64 81 ;
    END
  END native_commit_identity[5]
  PIN native_commit_identity[60]
    DIRECTION OUTPUT ;
    USE SIGNAL ;
    PORT
      LAYER M5 ;
        RECT  106.416 80.916 106.44 81 ;
    END
  END native_commit_identity[60]
  PIN native_commit_identity[6]
    DIRECTION OUTPUT ;
    USE SIGNAL ;
    PORT
      LAYER M5 ;
        RECT  42.816 80.916 42.84 81 ;
    END
  END native_commit_identity[6]
  PIN native_commit_identity[7]
    DIRECTION OUTPUT ;
    USE SIGNAL ;
    PORT
      LAYER M5 ;
        RECT  43.968 80.916 43.992 81 ;
    END
  END native_commit_identity[7]
  PIN native_commit_identity[8]
    DIRECTION OUTPUT ;
    USE SIGNAL ;
    PORT
      LAYER M5 ;
        RECT  45.168 80.916 45.192 81 ;
    END
  END native_commit_identity[8]
  PIN native_commit_identity[9]
    DIRECTION OUTPUT ;
    USE SIGNAL ;
    PORT
      LAYER M5 ;
        RECT  46.32 80.916 46.344 81 ;
    END
  END native_commit_identity[9]
  PIN native_commit_valid
    DIRECTION OUTPUT ;
    USE SIGNAL ;
    PORT
      LAYER M5 ;
        RECT  2.112 0 2.136 0.084 ;
    END
  END native_commit_valid
  PIN obs_commit_valid
    DIRECTION OUTPUT ;
    USE SIGNAL ;
    PORT
      LAYER M5 ;
        RECT  2.4 0 2.424 0.084 ;
    END
  END obs_commit_valid
  PIN pll_hbm
    DIRECTION INPUT ;
    USE SIGNAL ;
    PORT
      LAYER M5 ;
        RECT  54.192 80.916 54.216 81 ;
    END
  END pll_hbm
  PIN po[0]
    DIRECTION INPUT ;
    USE SIGNAL ;
    PORT
      LAYER M5 ;
        RECT  2.736 0 2.76 0.084 ;
    END
  END po[0]
  PIN po[100]
    DIRECTION INPUT ;
    USE SIGNAL ;
    PORT
      LAYER M5 ;
        RECT  34.464 0 34.488 0.084 ;
    END
  END po[100]
  PIN po[101]
    DIRECTION INPUT ;
    USE SIGNAL ;
    PORT
      LAYER M5 ;
        RECT  34.8 0 34.824 0.084 ;
    END
  END po[101]
  PIN po[102]
    DIRECTION INPUT ;
    USE SIGNAL ;
    PORT
      LAYER M5 ;
        RECT  35.088 0 35.112 0.084 ;
    END
  END po[102]
  PIN po[103]
    DIRECTION INPUT ;
    USE SIGNAL ;
    PORT
      LAYER M5 ;
        RECT  35.424 0 35.448 0.084 ;
    END
  END po[103]
  PIN po[104]
    DIRECTION INPUT ;
    USE SIGNAL ;
    PORT
      LAYER M5 ;
        RECT  35.76 0 35.784 0.084 ;
    END
  END po[104]
  PIN po[105]
    DIRECTION INPUT ;
    USE SIGNAL ;
    PORT
      LAYER M5 ;
        RECT  36.048 0 36.072 0.084 ;
    END
  END po[105]
  PIN po[106]
    DIRECTION INPUT ;
    USE SIGNAL ;
    PORT
      LAYER M5 ;
        RECT  36.384 0 36.408 0.084 ;
    END
  END po[106]
  PIN po[107]
    DIRECTION INPUT ;
    USE SIGNAL ;
    PORT
      LAYER M5 ;
        RECT  36.672 0 36.696 0.084 ;
    END
  END po[107]
  PIN po[108]
    DIRECTION INPUT ;
    USE SIGNAL ;
    PORT
      LAYER M5 ;
        RECT  37.008 0 37.032 0.084 ;
    END
  END po[108]
  PIN po[109]
    DIRECTION INPUT ;
    USE SIGNAL ;
    PORT
      LAYER M5 ;
        RECT  37.344 0 37.368 0.084 ;
    END
  END po[109]
  PIN po[10]
    DIRECTION INPUT ;
    USE SIGNAL ;
    PORT
      LAYER M5 ;
        RECT  5.904 0 5.928 0.084 ;
    END
  END po[10]
  PIN po[110]
    DIRECTION INPUT ;
    USE SIGNAL ;
    PORT
      LAYER M5 ;
        RECT  37.632 0 37.656 0.084 ;
    END
  END po[110]
  PIN po[111]
    DIRECTION INPUT ;
    USE SIGNAL ;
    PORT
      LAYER M5 ;
        RECT  37.968 0 37.992 0.084 ;
    END
  END po[111]
  PIN po[112]
    DIRECTION INPUT ;
    USE SIGNAL ;
    PORT
      LAYER M5 ;
        RECT  38.256 0 38.28 0.084 ;
    END
  END po[112]
  PIN po[113]
    DIRECTION INPUT ;
    USE SIGNAL ;
    PORT
      LAYER M5 ;
        RECT  38.592 0 38.616 0.084 ;
    END
  END po[113]
  PIN po[114]
    DIRECTION INPUT ;
    USE SIGNAL ;
    PORT
      LAYER M5 ;
        RECT  38.928 0 38.952 0.084 ;
    END
  END po[114]
  PIN po[115]
    DIRECTION INPUT ;
    USE SIGNAL ;
    PORT
      LAYER M5 ;
        RECT  39.216 0 39.24 0.084 ;
    END
  END po[115]
  PIN po[116]
    DIRECTION INPUT ;
    USE SIGNAL ;
    PORT
      LAYER M5 ;
        RECT  39.552 0 39.576 0.084 ;
    END
  END po[116]
  PIN po[117]
    DIRECTION INPUT ;
    USE SIGNAL ;
    PORT
      LAYER M5 ;
        RECT  39.888 0 39.912 0.084 ;
    END
  END po[117]
  PIN po[118]
    DIRECTION INPUT ;
    USE SIGNAL ;
    PORT
      LAYER M5 ;
        RECT  40.176 0 40.2 0.084 ;
    END
  END po[118]
  PIN po[119]
    DIRECTION INPUT ;
    USE SIGNAL ;
    PORT
      LAYER M5 ;
        RECT  40.512 0 40.536 0.084 ;
    END
  END po[119]
  PIN po[11]
    DIRECTION INPUT ;
    USE SIGNAL ;
    PORT
      LAYER M5 ;
        RECT  6.24 0 6.264 0.084 ;
    END
  END po[11]
  PIN po[120]
    DIRECTION INPUT ;
    USE SIGNAL ;
    PORT
      LAYER M5 ;
        RECT  40.8 0 40.824 0.084 ;
    END
  END po[120]
  PIN po[121]
    DIRECTION INPUT ;
    USE SIGNAL ;
    PORT
      LAYER M5 ;
        RECT  41.136 0 41.16 0.084 ;
    END
  END po[121]
  PIN po[122]
    DIRECTION INPUT ;
    USE SIGNAL ;
    PORT
      LAYER M5 ;
        RECT  41.472 0 41.496 0.084 ;
    END
  END po[122]
  PIN po[123]
    DIRECTION INPUT ;
    USE SIGNAL ;
    PORT
      LAYER M5 ;
        RECT  41.76 0 41.784 0.084 ;
    END
  END po[123]
  PIN po[124]
    DIRECTION INPUT ;
    USE SIGNAL ;
    PORT
      LAYER M5 ;
        RECT  42.096 0 42.12 0.084 ;
    END
  END po[124]
  PIN po[125]
    DIRECTION INPUT ;
    USE SIGNAL ;
    PORT
      LAYER M5 ;
        RECT  42.384 0 42.408 0.084 ;
    END
  END po[125]
  PIN po[126]
    DIRECTION INPUT ;
    USE SIGNAL ;
    PORT
      LAYER M5 ;
        RECT  42.72 0 42.744 0.084 ;
    END
  END po[126]
  PIN po[127]
    DIRECTION INPUT ;
    USE SIGNAL ;
    PORT
      LAYER M5 ;
        RECT  43.056 0 43.08 0.084 ;
    END
  END po[127]
  PIN po[128]
    DIRECTION INPUT ;
    USE SIGNAL ;
    PORT
      LAYER M5 ;
        RECT  43.344 0 43.368 0.084 ;
    END
  END po[128]
  PIN po[129]
    DIRECTION INPUT ;
    USE SIGNAL ;
    PORT
      LAYER M5 ;
        RECT  43.68 0 43.704 0.084 ;
    END
  END po[129]
  PIN po[12]
    DIRECTION INPUT ;
    USE SIGNAL ;
    PORT
      LAYER M5 ;
        RECT  6.528 0 6.552 0.084 ;
    END
  END po[12]
  PIN po[130]
    DIRECTION INPUT ;
    USE SIGNAL ;
    PORT
      LAYER M5 ;
        RECT  43.968 0 43.992 0.084 ;
    END
  END po[130]
  PIN po[131]
    DIRECTION INPUT ;
    USE SIGNAL ;
    PORT
      LAYER M5 ;
        RECT  44.304 0 44.328 0.084 ;
    END
  END po[131]
  PIN po[132]
    DIRECTION INPUT ;
    USE SIGNAL ;
    PORT
      LAYER M5 ;
        RECT  44.64 0 44.664 0.084 ;
    END
  END po[132]
  PIN po[133]
    DIRECTION INPUT ;
    USE SIGNAL ;
    PORT
      LAYER M5 ;
        RECT  44.928 0 44.952 0.084 ;
    END
  END po[133]
  PIN po[134]
    DIRECTION INPUT ;
    USE SIGNAL ;
    PORT
      LAYER M5 ;
        RECT  45.264 0 45.288 0.084 ;
    END
  END po[134]
  PIN po[135]
    DIRECTION INPUT ;
    USE SIGNAL ;
    PORT
      LAYER M5 ;
        RECT  45.6 0 45.624 0.084 ;
    END
  END po[135]
  PIN po[136]
    DIRECTION INPUT ;
    USE SIGNAL ;
    PORT
      LAYER M5 ;
        RECT  45.888 0 45.912 0.084 ;
    END
  END po[136]
  PIN po[137]
    DIRECTION INPUT ;
    USE SIGNAL ;
    PORT
      LAYER M5 ;
        RECT  46.224 0 46.248 0.084 ;
    END
  END po[137]
  PIN po[138]
    DIRECTION INPUT ;
    USE SIGNAL ;
    PORT
      LAYER M5 ;
        RECT  46.512 0 46.536 0.084 ;
    END
  END po[138]
  PIN po[139]
    DIRECTION INPUT ;
    USE SIGNAL ;
    PORT
      LAYER M5 ;
        RECT  46.848 0 46.872 0.084 ;
    END
  END po[139]
  PIN po[13]
    DIRECTION INPUT ;
    USE SIGNAL ;
    PORT
      LAYER M5 ;
        RECT  6.864 0 6.888 0.084 ;
    END
  END po[13]
  PIN po[140]
    DIRECTION INPUT ;
    USE SIGNAL ;
    PORT
      LAYER M5 ;
        RECT  47.184 0 47.208 0.084 ;
    END
  END po[140]
  PIN po[141]
    DIRECTION INPUT ;
    USE SIGNAL ;
    PORT
      LAYER M5 ;
        RECT  47.472 0 47.496 0.084 ;
    END
  END po[141]
  PIN po[142]
    DIRECTION INPUT ;
    USE SIGNAL ;
    PORT
      LAYER M5 ;
        RECT  47.808 0 47.832 0.084 ;
    END
  END po[142]
  PIN po[143]
    DIRECTION INPUT ;
    USE SIGNAL ;
    PORT
      LAYER M5 ;
        RECT  48.096 0 48.12 0.084 ;
    END
  END po[143]
  PIN po[144]
    DIRECTION INPUT ;
    USE SIGNAL ;
    PORT
      LAYER M5 ;
        RECT  48.432 0 48.456 0.084 ;
    END
  END po[144]
  PIN po[145]
    DIRECTION INPUT ;
    USE SIGNAL ;
    PORT
      LAYER M5 ;
        RECT  48.768 0 48.792 0.084 ;
    END
  END po[145]
  PIN po[146]
    DIRECTION INPUT ;
    USE SIGNAL ;
    PORT
      LAYER M5 ;
        RECT  49.056 0 49.08 0.084 ;
    END
  END po[146]
  PIN po[147]
    DIRECTION INPUT ;
    USE SIGNAL ;
    PORT
      LAYER M5 ;
        RECT  49.392 0 49.416 0.084 ;
    END
  END po[147]
  PIN po[148]
    DIRECTION INPUT ;
    USE SIGNAL ;
    PORT
      LAYER M5 ;
        RECT  49.728 0 49.752 0.084 ;
    END
  END po[148]
  PIN po[149]
    DIRECTION INPUT ;
    USE SIGNAL ;
    PORT
      LAYER M5 ;
        RECT  50.016 0 50.04 0.084 ;
    END
  END po[149]
  PIN po[14]
    DIRECTION INPUT ;
    USE SIGNAL ;
    PORT
      LAYER M5 ;
        RECT  7.2 0 7.224 0.084 ;
    END
  END po[14]
  PIN po[150]
    DIRECTION INPUT ;
    USE SIGNAL ;
    PORT
      LAYER M5 ;
        RECT  50.352 0 50.376 0.084 ;
    END
  END po[150]
  PIN po[151]
    DIRECTION INPUT ;
    USE SIGNAL ;
    PORT
      LAYER M5 ;
        RECT  50.64 0 50.664 0.084 ;
    END
  END po[151]
  PIN po[152]
    DIRECTION INPUT ;
    USE SIGNAL ;
    PORT
      LAYER M5 ;
        RECT  50.976 0 51 0.084 ;
    END
  END po[152]
  PIN po[153]
    DIRECTION INPUT ;
    USE SIGNAL ;
    PORT
      LAYER M5 ;
        RECT  51.312 0 51.336 0.084 ;
    END
  END po[153]
  PIN po[154]
    DIRECTION INPUT ;
    USE SIGNAL ;
    PORT
      LAYER M5 ;
        RECT  51.6 0 51.624 0.084 ;
    END
  END po[154]
  PIN po[155]
    DIRECTION INPUT ;
    USE SIGNAL ;
    PORT
      LAYER M5 ;
        RECT  51.936 0 51.96 0.084 ;
    END
  END po[155]
  PIN po[156]
    DIRECTION INPUT ;
    USE SIGNAL ;
    PORT
      LAYER M5 ;
        RECT  52.224 0 52.248 0.084 ;
    END
  END po[156]
  PIN po[157]
    DIRECTION INPUT ;
    USE SIGNAL ;
    PORT
      LAYER M5 ;
        RECT  52.56 0 52.584 0.084 ;
    END
  END po[157]
  PIN po[158]
    DIRECTION INPUT ;
    USE SIGNAL ;
    PORT
      LAYER M5 ;
        RECT  52.896 0 52.92 0.084 ;
    END
  END po[158]
  PIN po[159]
    DIRECTION INPUT ;
    USE SIGNAL ;
    PORT
      LAYER M5 ;
        RECT  53.184 0 53.208 0.084 ;
    END
  END po[159]
  PIN po[15]
    DIRECTION INPUT ;
    USE SIGNAL ;
    PORT
      LAYER M5 ;
        RECT  7.488 0 7.512 0.084 ;
    END
  END po[15]
  PIN po[160]
    DIRECTION INPUT ;
    USE SIGNAL ;
    PORT
      LAYER M5 ;
        RECT  53.52 0 53.544 0.084 ;
    END
  END po[160]
  PIN po[161]
    DIRECTION INPUT ;
    USE SIGNAL ;
    PORT
      LAYER M5 ;
        RECT  53.808 0 53.832 0.084 ;
    END
  END po[161]
  PIN po[162]
    DIRECTION INPUT ;
    USE SIGNAL ;
    PORT
      LAYER M5 ;
        RECT  54.144 0 54.168 0.084 ;
    END
  END po[162]
  PIN po[163]
    DIRECTION INPUT ;
    USE SIGNAL ;
    PORT
      LAYER M5 ;
        RECT  54.48 0 54.504 0.084 ;
    END
  END po[163]
  PIN po[164]
    DIRECTION INPUT ;
    USE SIGNAL ;
    PORT
      LAYER M5 ;
        RECT  54.768 0 54.792 0.084 ;
    END
  END po[164]
  PIN po[165]
    DIRECTION INPUT ;
    USE SIGNAL ;
    PORT
      LAYER M5 ;
        RECT  55.104 0 55.128 0.084 ;
    END
  END po[165]
  PIN po[166]
    DIRECTION INPUT ;
    USE SIGNAL ;
    PORT
      LAYER M5 ;
        RECT  55.44 0 55.464 0.084 ;
    END
  END po[166]
  PIN po[167]
    DIRECTION INPUT ;
    USE SIGNAL ;
    PORT
      LAYER M5 ;
        RECT  55.728 0 55.752 0.084 ;
    END
  END po[167]
  PIN po[168]
    DIRECTION INPUT ;
    USE SIGNAL ;
    PORT
      LAYER M5 ;
        RECT  56.064 0 56.088 0.084 ;
    END
  END po[168]
  PIN po[169]
    DIRECTION INPUT ;
    USE SIGNAL ;
    PORT
      LAYER M5 ;
        RECT  56.352 0 56.376 0.084 ;
    END
  END po[169]
  PIN po[16]
    DIRECTION INPUT ;
    USE SIGNAL ;
    PORT
      LAYER M5 ;
        RECT  7.824 0 7.848 0.084 ;
    END
  END po[16]
  PIN po[170]
    DIRECTION INPUT ;
    USE SIGNAL ;
    PORT
      LAYER M5 ;
        RECT  56.688 0 56.712 0.084 ;
    END
  END po[170]
  PIN po[171]
    DIRECTION INPUT ;
    USE SIGNAL ;
    PORT
      LAYER M5 ;
        RECT  57.024 0 57.048 0.084 ;
    END
  END po[171]
  PIN po[172]
    DIRECTION INPUT ;
    USE SIGNAL ;
    PORT
      LAYER M5 ;
        RECT  57.312 0 57.336 0.084 ;
    END
  END po[172]
  PIN po[173]
    DIRECTION INPUT ;
    USE SIGNAL ;
    PORT
      LAYER M5 ;
        RECT  57.648 0 57.672 0.084 ;
    END
  END po[173]
  PIN po[174]
    DIRECTION INPUT ;
    USE SIGNAL ;
    PORT
      LAYER M5 ;
        RECT  57.936 0 57.96 0.084 ;
    END
  END po[174]
  PIN po[175]
    DIRECTION INPUT ;
    USE SIGNAL ;
    PORT
      LAYER M5 ;
        RECT  58.272 0 58.296 0.084 ;
    END
  END po[175]
  PIN po[176]
    DIRECTION INPUT ;
    USE SIGNAL ;
    PORT
      LAYER M5 ;
        RECT  58.608 0 58.632 0.084 ;
    END
  END po[176]
  PIN po[177]
    DIRECTION INPUT ;
    USE SIGNAL ;
    PORT
      LAYER M5 ;
        RECT  58.896 0 58.92 0.084 ;
    END
  END po[177]
  PIN po[178]
    DIRECTION INPUT ;
    USE SIGNAL ;
    PORT
      LAYER M5 ;
        RECT  59.232 0 59.256 0.084 ;
    END
  END po[178]
  PIN po[179]
    DIRECTION INPUT ;
    USE SIGNAL ;
    PORT
      LAYER M5 ;
        RECT  59.52 0 59.544 0.084 ;
    END
  END po[179]
  PIN po[17]
    DIRECTION INPUT ;
    USE SIGNAL ;
    PORT
      LAYER M5 ;
        RECT  8.112 0 8.136 0.084 ;
    END
  END po[17]
  PIN po[180]
    DIRECTION INPUT ;
    USE SIGNAL ;
    PORT
      LAYER M5 ;
        RECT  59.856 0 59.88 0.084 ;
    END
  END po[180]
  PIN po[181]
    DIRECTION INPUT ;
    USE SIGNAL ;
    PORT
      LAYER M5 ;
        RECT  60.192 0 60.216 0.084 ;
    END
  END po[181]
  PIN po[182]
    DIRECTION INPUT ;
    USE SIGNAL ;
    PORT
      LAYER M5 ;
        RECT  60.48 0 60.504 0.084 ;
    END
  END po[182]
  PIN po[183]
    DIRECTION INPUT ;
    USE SIGNAL ;
    PORT
      LAYER M5 ;
        RECT  60.816 0 60.84 0.084 ;
    END
  END po[183]
  PIN po[184]
    DIRECTION INPUT ;
    USE SIGNAL ;
    PORT
      LAYER M5 ;
        RECT  61.152 0 61.176 0.084 ;
    END
  END po[184]
  PIN po[185]
    DIRECTION INPUT ;
    USE SIGNAL ;
    PORT
      LAYER M5 ;
        RECT  61.44 0 61.464 0.084 ;
    END
  END po[185]
  PIN po[186]
    DIRECTION INPUT ;
    USE SIGNAL ;
    PORT
      LAYER M5 ;
        RECT  61.776 0 61.8 0.084 ;
    END
  END po[186]
  PIN po[187]
    DIRECTION INPUT ;
    USE SIGNAL ;
    PORT
      LAYER M5 ;
        RECT  62.064 0 62.088 0.084 ;
    END
  END po[187]
  PIN po[188]
    DIRECTION INPUT ;
    USE SIGNAL ;
    PORT
      LAYER M5 ;
        RECT  62.4 0 62.424 0.084 ;
    END
  END po[188]
  PIN po[189]
    DIRECTION INPUT ;
    USE SIGNAL ;
    PORT
      LAYER M5 ;
        RECT  62.736 0 62.76 0.084 ;
    END
  END po[189]
  PIN po[18]
    DIRECTION INPUT ;
    USE SIGNAL ;
    PORT
      LAYER M5 ;
        RECT  8.448 0 8.472 0.084 ;
    END
  END po[18]
  PIN po[190]
    DIRECTION INPUT ;
    USE SIGNAL ;
    PORT
      LAYER M5 ;
        RECT  63.024 0 63.048 0.084 ;
    END
  END po[190]
  PIN po[191]
    DIRECTION INPUT ;
    USE SIGNAL ;
    PORT
      LAYER M5 ;
        RECT  63.36 0 63.384 0.084 ;
    END
  END po[191]
  PIN po[192]
    DIRECTION INPUT ;
    USE SIGNAL ;
    PORT
      LAYER M5 ;
        RECT  63.648 0 63.672 0.084 ;
    END
  END po[192]
  PIN po[193]
    DIRECTION INPUT ;
    USE SIGNAL ;
    PORT
      LAYER M5 ;
        RECT  63.984 0 64.008 0.084 ;
    END
  END po[193]
  PIN po[194]
    DIRECTION INPUT ;
    USE SIGNAL ;
    PORT
      LAYER M5 ;
        RECT  64.32 0 64.344 0.084 ;
    END
  END po[194]
  PIN po[195]
    DIRECTION INPUT ;
    USE SIGNAL ;
    PORT
      LAYER M5 ;
        RECT  64.608 0 64.632 0.084 ;
    END
  END po[195]
  PIN po[196]
    DIRECTION INPUT ;
    USE SIGNAL ;
    PORT
      LAYER M5 ;
        RECT  64.944 0 64.968 0.084 ;
    END
  END po[196]
  PIN po[197]
    DIRECTION INPUT ;
    USE SIGNAL ;
    PORT
      LAYER M5 ;
        RECT  65.232 0 65.256 0.084 ;
    END
  END po[197]
  PIN po[198]
    DIRECTION INPUT ;
    USE SIGNAL ;
    PORT
      LAYER M5 ;
        RECT  65.568 0 65.592 0.084 ;
    END
  END po[198]
  PIN po[199]
    DIRECTION INPUT ;
    USE SIGNAL ;
    PORT
      LAYER M5 ;
        RECT  65.904 0 65.928 0.084 ;
    END
  END po[199]
  PIN po[19]
    DIRECTION INPUT ;
    USE SIGNAL ;
    PORT
      LAYER M5 ;
        RECT  8.784 0 8.808 0.084 ;
    END
  END po[19]
  PIN po[1]
    DIRECTION INPUT ;
    USE SIGNAL ;
    PORT
      LAYER M5 ;
        RECT  3.072 0 3.096 0.084 ;
    END
  END po[1]
  PIN po[200]
    DIRECTION INPUT ;
    USE SIGNAL ;
    PORT
      LAYER M5 ;
        RECT  66.192 0 66.216 0.084 ;
    END
  END po[200]
  PIN po[201]
    DIRECTION INPUT ;
    USE SIGNAL ;
    PORT
      LAYER M5 ;
        RECT  66.528 0 66.552 0.084 ;
    END
  END po[201]
  PIN po[202]
    DIRECTION INPUT ;
    USE SIGNAL ;
    PORT
      LAYER M5 ;
        RECT  66.864 0 66.888 0.084 ;
    END
  END po[202]
  PIN po[203]
    DIRECTION INPUT ;
    USE SIGNAL ;
    PORT
      LAYER M5 ;
        RECT  67.152 0 67.176 0.084 ;
    END
  END po[203]
  PIN po[204]
    DIRECTION INPUT ;
    USE SIGNAL ;
    PORT
      LAYER M5 ;
        RECT  67.488 0 67.512 0.084 ;
    END
  END po[204]
  PIN po[205]
    DIRECTION INPUT ;
    USE SIGNAL ;
    PORT
      LAYER M5 ;
        RECT  67.776 0 67.8 0.084 ;
    END
  END po[205]
  PIN po[206]
    DIRECTION INPUT ;
    USE SIGNAL ;
    PORT
      LAYER M5 ;
        RECT  68.112 0 68.136 0.084 ;
    END
  END po[206]
  PIN po[207]
    DIRECTION INPUT ;
    USE SIGNAL ;
    PORT
      LAYER M5 ;
        RECT  68.448 0 68.472 0.084 ;
    END
  END po[207]
  PIN po[208]
    DIRECTION INPUT ;
    USE SIGNAL ;
    PORT
      LAYER M5 ;
        RECT  68.736 0 68.76 0.084 ;
    END
  END po[208]
  PIN po[209]
    DIRECTION INPUT ;
    USE SIGNAL ;
    PORT
      LAYER M5 ;
        RECT  69.072 0 69.096 0.084 ;
    END
  END po[209]
  PIN po[20]
    DIRECTION INPUT ;
    USE SIGNAL ;
    PORT
      LAYER M5 ;
        RECT  9.072 0 9.096 0.084 ;
    END
  END po[20]
  PIN po[210]
    DIRECTION INPUT ;
    USE SIGNAL ;
    PORT
      LAYER M5 ;
        RECT  69.36 0 69.384 0.084 ;
    END
  END po[210]
  PIN po[211]
    DIRECTION INPUT ;
    USE SIGNAL ;
    PORT
      LAYER M5 ;
        RECT  69.696 0 69.72 0.084 ;
    END
  END po[211]
  PIN po[212]
    DIRECTION INPUT ;
    USE SIGNAL ;
    PORT
      LAYER M5 ;
        RECT  70.032 0 70.056 0.084 ;
    END
  END po[212]
  PIN po[213]
    DIRECTION INPUT ;
    USE SIGNAL ;
    PORT
      LAYER M5 ;
        RECT  70.32 0 70.344 0.084 ;
    END
  END po[213]
  PIN po[214]
    DIRECTION INPUT ;
    USE SIGNAL ;
    PORT
      LAYER M5 ;
        RECT  70.656 0 70.68 0.084 ;
    END
  END po[214]
  PIN po[215]
    DIRECTION INPUT ;
    USE SIGNAL ;
    PORT
      LAYER M5 ;
        RECT  70.944 0 70.968 0.084 ;
    END
  END po[215]
  PIN po[216]
    DIRECTION INPUT ;
    USE SIGNAL ;
    PORT
      LAYER M5 ;
        RECT  71.28 0 71.304 0.084 ;
    END
  END po[216]
  PIN po[217]
    DIRECTION INPUT ;
    USE SIGNAL ;
    PORT
      LAYER M5 ;
        RECT  71.616 0 71.64 0.084 ;
    END
  END po[217]
  PIN po[218]
    DIRECTION INPUT ;
    USE SIGNAL ;
    PORT
      LAYER M5 ;
        RECT  71.904 0 71.928 0.084 ;
    END
  END po[218]
  PIN po[219]
    DIRECTION INPUT ;
    USE SIGNAL ;
    PORT
      LAYER M5 ;
        RECT  72.24 0 72.264 0.084 ;
    END
  END po[219]
  PIN po[21]
    DIRECTION INPUT ;
    USE SIGNAL ;
    PORT
      LAYER M5 ;
        RECT  9.408 0 9.432 0.084 ;
    END
  END po[21]
  PIN po[220]
    DIRECTION INPUT ;
    USE SIGNAL ;
    PORT
      LAYER M5 ;
        RECT  72.576 0 72.6 0.084 ;
    END
  END po[220]
  PIN po[221]
    DIRECTION INPUT ;
    USE SIGNAL ;
    PORT
      LAYER M5 ;
        RECT  72.864 0 72.888 0.084 ;
    END
  END po[221]
  PIN po[222]
    DIRECTION INPUT ;
    USE SIGNAL ;
    PORT
      LAYER M5 ;
        RECT  73.2 0 73.224 0.084 ;
    END
  END po[222]
  PIN po[223]
    DIRECTION INPUT ;
    USE SIGNAL ;
    PORT
      LAYER M5 ;
        RECT  73.488 0 73.512 0.084 ;
    END
  END po[223]
  PIN po[224]
    DIRECTION INPUT ;
    USE SIGNAL ;
    PORT
      LAYER M5 ;
        RECT  73.824 0 73.848 0.084 ;
    END
  END po[224]
  PIN po[225]
    DIRECTION INPUT ;
    USE SIGNAL ;
    PORT
      LAYER M5 ;
        RECT  74.16 0 74.184 0.084 ;
    END
  END po[225]
  PIN po[226]
    DIRECTION INPUT ;
    USE SIGNAL ;
    PORT
      LAYER M5 ;
        RECT  74.448 0 74.472 0.084 ;
    END
  END po[226]
  PIN po[227]
    DIRECTION INPUT ;
    USE SIGNAL ;
    PORT
      LAYER M5 ;
        RECT  74.784 0 74.808 0.084 ;
    END
  END po[227]
  PIN po[228]
    DIRECTION INPUT ;
    USE SIGNAL ;
    PORT
      LAYER M5 ;
        RECT  75.072 0 75.096 0.084 ;
    END
  END po[228]
  PIN po[229]
    DIRECTION INPUT ;
    USE SIGNAL ;
    PORT
      LAYER M5 ;
        RECT  75.408 0 75.432 0.084 ;
    END
  END po[229]
  PIN po[22]
    DIRECTION INPUT ;
    USE SIGNAL ;
    PORT
      LAYER M5 ;
        RECT  9.696 0 9.72 0.084 ;
    END
  END po[22]
  PIN po[230]
    DIRECTION INPUT ;
    USE SIGNAL ;
    PORT
      LAYER M5 ;
        RECT  75.744 0 75.768 0.084 ;
    END
  END po[230]
  PIN po[231]
    DIRECTION INPUT ;
    USE SIGNAL ;
    PORT
      LAYER M5 ;
        RECT  76.032 0 76.056 0.084 ;
    END
  END po[231]
  PIN po[232]
    DIRECTION INPUT ;
    USE SIGNAL ;
    PORT
      LAYER M5 ;
        RECT  76.368 0 76.392 0.084 ;
    END
  END po[232]
  PIN po[233]
    DIRECTION INPUT ;
    USE SIGNAL ;
    PORT
      LAYER M5 ;
        RECT  76.704 0 76.728 0.084 ;
    END
  END po[233]
  PIN po[234]
    DIRECTION INPUT ;
    USE SIGNAL ;
    PORT
      LAYER M5 ;
        RECT  76.992 0 77.016 0.084 ;
    END
  END po[234]
  PIN po[235]
    DIRECTION INPUT ;
    USE SIGNAL ;
    PORT
      LAYER M5 ;
        RECT  77.328 0 77.352 0.084 ;
    END
  END po[235]
  PIN po[236]
    DIRECTION INPUT ;
    USE SIGNAL ;
    PORT
      LAYER M5 ;
        RECT  77.616 0 77.64 0.084 ;
    END
  END po[236]
  PIN po[237]
    DIRECTION INPUT ;
    USE SIGNAL ;
    PORT
      LAYER M5 ;
        RECT  77.952 0 77.976 0.084 ;
    END
  END po[237]
  PIN po[238]
    DIRECTION INPUT ;
    USE SIGNAL ;
    PORT
      LAYER M5 ;
        RECT  78.288 0 78.312 0.084 ;
    END
  END po[238]
  PIN po[239]
    DIRECTION INPUT ;
    USE SIGNAL ;
    PORT
      LAYER M5 ;
        RECT  78.576 0 78.6 0.084 ;
    END
  END po[239]
  PIN po[23]
    DIRECTION INPUT ;
    USE SIGNAL ;
    PORT
      LAYER M5 ;
        RECT  10.032 0 10.056 0.084 ;
    END
  END po[23]
  PIN po[240]
    DIRECTION INPUT ;
    USE SIGNAL ;
    PORT
      LAYER M5 ;
        RECT  78.912 0 78.936 0.084 ;
    END
  END po[240]
  PIN po[241]
    DIRECTION INPUT ;
    USE SIGNAL ;
    PORT
      LAYER M5 ;
        RECT  79.2 0 79.224 0.084 ;
    END
  END po[241]
  PIN po[242]
    DIRECTION INPUT ;
    USE SIGNAL ;
    PORT
      LAYER M5 ;
        RECT  79.536 0 79.56 0.084 ;
    END
  END po[242]
  PIN po[243]
    DIRECTION INPUT ;
    USE SIGNAL ;
    PORT
      LAYER M5 ;
        RECT  79.872 0 79.896 0.084 ;
    END
  END po[243]
  PIN po[244]
    DIRECTION INPUT ;
    USE SIGNAL ;
    PORT
      LAYER M5 ;
        RECT  80.16 0 80.184 0.084 ;
    END
  END po[244]
  PIN po[245]
    DIRECTION INPUT ;
    USE SIGNAL ;
    PORT
      LAYER M5 ;
        RECT  80.496 0 80.52 0.084 ;
    END
  END po[245]
  PIN po[246]
    DIRECTION INPUT ;
    USE SIGNAL ;
    PORT
      LAYER M5 ;
        RECT  80.784 0 80.808 0.084 ;
    END
  END po[246]
  PIN po[247]
    DIRECTION INPUT ;
    USE SIGNAL ;
    PORT
      LAYER M5 ;
        RECT  81.12 0 81.144 0.084 ;
    END
  END po[247]
  PIN po[248]
    DIRECTION INPUT ;
    USE SIGNAL ;
    PORT
      LAYER M5 ;
        RECT  81.456 0 81.48 0.084 ;
    END
  END po[248]
  PIN po[249]
    DIRECTION INPUT ;
    USE SIGNAL ;
    PORT
      LAYER M5 ;
        RECT  81.744 0 81.768 0.084 ;
    END
  END po[249]
  PIN po[24]
    DIRECTION INPUT ;
    USE SIGNAL ;
    PORT
      LAYER M5 ;
        RECT  10.368 0 10.392 0.084 ;
    END
  END po[24]
  PIN po[250]
    DIRECTION INPUT ;
    USE SIGNAL ;
    PORT
      LAYER M5 ;
        RECT  82.08 0 82.104 0.084 ;
    END
  END po[250]
  PIN po[251]
    DIRECTION INPUT ;
    USE SIGNAL ;
    PORT
      LAYER M5 ;
        RECT  82.416 0 82.44 0.084 ;
    END
  END po[251]
  PIN po[252]
    DIRECTION INPUT ;
    USE SIGNAL ;
    PORT
      LAYER M5 ;
        RECT  82.704 0 82.728 0.084 ;
    END
  END po[252]
  PIN po[253]
    DIRECTION INPUT ;
    USE SIGNAL ;
    PORT
      LAYER M5 ;
        RECT  83.04 0 83.064 0.084 ;
    END
  END po[253]
  PIN po[254]
    DIRECTION INPUT ;
    USE SIGNAL ;
    PORT
      LAYER M5 ;
        RECT  83.328 0 83.352 0.084 ;
    END
  END po[254]
  PIN po[255]
    DIRECTION INPUT ;
    USE SIGNAL ;
    PORT
      LAYER M5 ;
        RECT  83.664 0 83.688 0.084 ;
    END
  END po[255]
  PIN po[256]
    DIRECTION INPUT ;
    USE SIGNAL ;
    PORT
      LAYER M5 ;
        RECT  84 0 84.024 0.084 ;
    END
  END po[256]
  PIN po[257]
    DIRECTION INPUT ;
    USE SIGNAL ;
    PORT
      LAYER M5 ;
        RECT  84.288 0 84.312 0.084 ;
    END
  END po[257]
  PIN po[258]
    DIRECTION INPUT ;
    USE SIGNAL ;
    PORT
      LAYER M5 ;
        RECT  84.624 0 84.648 0.084 ;
    END
  END po[258]
  PIN po[259]
    DIRECTION INPUT ;
    USE SIGNAL ;
    PORT
      LAYER M5 ;
        RECT  84.912 0 84.936 0.084 ;
    END
  END po[259]
  PIN po[25]
    DIRECTION INPUT ;
    USE SIGNAL ;
    PORT
      LAYER M5 ;
        RECT  10.656 0 10.68 0.084 ;
    END
  END po[25]
  PIN po[260]
    DIRECTION INPUT ;
    USE SIGNAL ;
    PORT
      LAYER M5 ;
        RECT  85.248 0 85.272 0.084 ;
    END
  END po[260]
  PIN po[261]
    DIRECTION INPUT ;
    USE SIGNAL ;
    PORT
      LAYER M5 ;
        RECT  85.584 0 85.608 0.084 ;
    END
  END po[261]
  PIN po[262]
    DIRECTION INPUT ;
    USE SIGNAL ;
    PORT
      LAYER M5 ;
        RECT  85.872 0 85.896 0.084 ;
    END
  END po[262]
  PIN po[263]
    DIRECTION INPUT ;
    USE SIGNAL ;
    PORT
      LAYER M5 ;
        RECT  86.208 0 86.232 0.084 ;
    END
  END po[263]
  PIN po[264]
    DIRECTION INPUT ;
    USE SIGNAL ;
    PORT
      LAYER M5 ;
        RECT  86.496 0 86.52 0.084 ;
    END
  END po[264]
  PIN po[265]
    DIRECTION INPUT ;
    USE SIGNAL ;
    PORT
      LAYER M5 ;
        RECT  86.832 0 86.856 0.084 ;
    END
  END po[265]
  PIN po[266]
    DIRECTION INPUT ;
    USE SIGNAL ;
    PORT
      LAYER M5 ;
        RECT  87.168 0 87.192 0.084 ;
    END
  END po[266]
  PIN po[267]
    DIRECTION INPUT ;
    USE SIGNAL ;
    PORT
      LAYER M5 ;
        RECT  87.456 0 87.48 0.084 ;
    END
  END po[267]
  PIN po[268]
    DIRECTION INPUT ;
    USE SIGNAL ;
    PORT
      LAYER M5 ;
        RECT  87.792 0 87.816 0.084 ;
    END
  END po[268]
  PIN po[269]
    DIRECTION INPUT ;
    USE SIGNAL ;
    PORT
      LAYER M5 ;
        RECT  88.128 0 88.152 0.084 ;
    END
  END po[269]
  PIN po[26]
    DIRECTION INPUT ;
    USE SIGNAL ;
    PORT
      LAYER M5 ;
        RECT  10.992 0 11.016 0.084 ;
    END
  END po[26]
  PIN po[270]
    DIRECTION INPUT ;
    USE SIGNAL ;
    PORT
      LAYER M5 ;
        RECT  88.416 0 88.44 0.084 ;
    END
  END po[270]
  PIN po[271]
    DIRECTION INPUT ;
    USE SIGNAL ;
    PORT
      LAYER M5 ;
        RECT  88.752 0 88.776 0.084 ;
    END
  END po[271]
  PIN po[272]
    DIRECTION INPUT ;
    USE SIGNAL ;
    PORT
      LAYER M5 ;
        RECT  89.04 0 89.064 0.084 ;
    END
  END po[272]
  PIN po[273]
    DIRECTION INPUT ;
    USE SIGNAL ;
    PORT
      LAYER M5 ;
        RECT  89.376 0 89.4 0.084 ;
    END
  END po[273]
  PIN po[274]
    DIRECTION INPUT ;
    USE SIGNAL ;
    PORT
      LAYER M5 ;
        RECT  89.712 0 89.736 0.084 ;
    END
  END po[274]
  PIN po[275]
    DIRECTION INPUT ;
    USE SIGNAL ;
    PORT
      LAYER M5 ;
        RECT  90 0 90.024 0.084 ;
    END
  END po[275]
  PIN po[276]
    DIRECTION INPUT ;
    USE SIGNAL ;
    PORT
      LAYER M5 ;
        RECT  90.336 0 90.36 0.084 ;
    END
  END po[276]
  PIN po[277]
    DIRECTION INPUT ;
    USE SIGNAL ;
    PORT
      LAYER M5 ;
        RECT  90.624 0 90.648 0.084 ;
    END
  END po[277]
  PIN po[278]
    DIRECTION INPUT ;
    USE SIGNAL ;
    PORT
      LAYER M5 ;
        RECT  90.96 0 90.984 0.084 ;
    END
  END po[278]
  PIN po[279]
    DIRECTION INPUT ;
    USE SIGNAL ;
    PORT
      LAYER M5 ;
        RECT  91.296 0 91.32 0.084 ;
    END
  END po[279]
  PIN po[27]
    DIRECTION INPUT ;
    USE SIGNAL ;
    PORT
      LAYER M5 ;
        RECT  11.28 0 11.304 0.084 ;
    END
  END po[27]
  PIN po[280]
    DIRECTION INPUT ;
    USE SIGNAL ;
    PORT
      LAYER M5 ;
        RECT  91.584 0 91.608 0.084 ;
    END
  END po[280]
  PIN po[281]
    DIRECTION INPUT ;
    USE SIGNAL ;
    PORT
      LAYER M5 ;
        RECT  91.92 0 91.944 0.084 ;
    END
  END po[281]
  PIN po[282]
    DIRECTION INPUT ;
    USE SIGNAL ;
    PORT
      LAYER M5 ;
        RECT  92.208 0 92.232 0.084 ;
    END
  END po[282]
  PIN po[283]
    DIRECTION INPUT ;
    USE SIGNAL ;
    PORT
      LAYER M5 ;
        RECT  92.544 0 92.568 0.084 ;
    END
  END po[283]
  PIN po[284]
    DIRECTION INPUT ;
    USE SIGNAL ;
    PORT
      LAYER M5 ;
        RECT  92.88 0 92.904 0.084 ;
    END
  END po[284]
  PIN po[285]
    DIRECTION INPUT ;
    USE SIGNAL ;
    PORT
      LAYER M5 ;
        RECT  93.168 0 93.192 0.084 ;
    END
  END po[285]
  PIN po[286]
    DIRECTION INPUT ;
    USE SIGNAL ;
    PORT
      LAYER M5 ;
        RECT  93.504 0 93.528 0.084 ;
    END
  END po[286]
  PIN po[287]
    DIRECTION INPUT ;
    USE SIGNAL ;
    PORT
      LAYER M5 ;
        RECT  93.84 0 93.864 0.084 ;
    END
  END po[287]
  PIN po[288]
    DIRECTION INPUT ;
    USE SIGNAL ;
    PORT
      LAYER M5 ;
        RECT  94.128 0 94.152 0.084 ;
    END
  END po[288]
  PIN po[289]
    DIRECTION INPUT ;
    USE SIGNAL ;
    PORT
      LAYER M5 ;
        RECT  94.464 0 94.488 0.084 ;
    END
  END po[289]
  PIN po[28]
    DIRECTION INPUT ;
    USE SIGNAL ;
    PORT
      LAYER M5 ;
        RECT  11.616 0 11.64 0.084 ;
    END
  END po[28]
  PIN po[290]
    DIRECTION INPUT ;
    USE SIGNAL ;
    PORT
      LAYER M5 ;
        RECT  94.752 0 94.776 0.084 ;
    END
  END po[290]
  PIN po[291]
    DIRECTION INPUT ;
    USE SIGNAL ;
    PORT
      LAYER M5 ;
        RECT  95.088 0 95.112 0.084 ;
    END
  END po[291]
  PIN po[292]
    DIRECTION INPUT ;
    USE SIGNAL ;
    PORT
      LAYER M5 ;
        RECT  95.424 0 95.448 0.084 ;
    END
  END po[292]
  PIN po[293]
    DIRECTION INPUT ;
    USE SIGNAL ;
    PORT
      LAYER M5 ;
        RECT  95.712 0 95.736 0.084 ;
    END
  END po[293]
  PIN po[294]
    DIRECTION INPUT ;
    USE SIGNAL ;
    PORT
      LAYER M5 ;
        RECT  96.048 0 96.072 0.084 ;
    END
  END po[294]
  PIN po[295]
    DIRECTION INPUT ;
    USE SIGNAL ;
    PORT
      LAYER M5 ;
        RECT  96.336 0 96.36 0.084 ;
    END
  END po[295]
  PIN po[296]
    DIRECTION INPUT ;
    USE SIGNAL ;
    PORT
      LAYER M5 ;
        RECT  96.672 0 96.696 0.084 ;
    END
  END po[296]
  PIN po[297]
    DIRECTION INPUT ;
    USE SIGNAL ;
    PORT
      LAYER M5 ;
        RECT  97.008 0 97.032 0.084 ;
    END
  END po[297]
  PIN po[298]
    DIRECTION INPUT ;
    USE SIGNAL ;
    PORT
      LAYER M5 ;
        RECT  97.296 0 97.32 0.084 ;
    END
  END po[298]
  PIN po[299]
    DIRECTION INPUT ;
    USE SIGNAL ;
    PORT
      LAYER M5 ;
        RECT  97.632 0 97.656 0.084 ;
    END
  END po[299]
  PIN po[29]
    DIRECTION INPUT ;
    USE SIGNAL ;
    PORT
      LAYER M5 ;
        RECT  11.952 0 11.976 0.084 ;
    END
  END po[29]
  PIN po[2]
    DIRECTION INPUT ;
    USE SIGNAL ;
    PORT
      LAYER M5 ;
        RECT  3.36 0 3.384 0.084 ;
    END
  END po[2]
  PIN po[300]
    DIRECTION INPUT ;
    USE SIGNAL ;
    PORT
      LAYER M5 ;
        RECT  97.92 0 97.944 0.084 ;
    END
  END po[300]
  PIN po[301]
    DIRECTION INPUT ;
    USE SIGNAL ;
    PORT
      LAYER M5 ;
        RECT  98.256 0 98.28 0.084 ;
    END
  END po[301]
  PIN po[302]
    DIRECTION INPUT ;
    USE SIGNAL ;
    PORT
      LAYER M5 ;
        RECT  98.592 0 98.616 0.084 ;
    END
  END po[302]
  PIN po[303]
    DIRECTION INPUT ;
    USE SIGNAL ;
    PORT
      LAYER M5 ;
        RECT  98.88 0 98.904 0.084 ;
    END
  END po[303]
  PIN po[304]
    DIRECTION INPUT ;
    USE SIGNAL ;
    PORT
      LAYER M5 ;
        RECT  99.216 0 99.24 0.084 ;
    END
  END po[304]
  PIN po[305]
    DIRECTION INPUT ;
    USE SIGNAL ;
    PORT
      LAYER M5 ;
        RECT  99.552 0 99.576 0.084 ;
    END
  END po[305]
  PIN po[306]
    DIRECTION INPUT ;
    USE SIGNAL ;
    PORT
      LAYER M5 ;
        RECT  99.84 0 99.864 0.084 ;
    END
  END po[306]
  PIN po[307]
    DIRECTION INPUT ;
    USE SIGNAL ;
    PORT
      LAYER M5 ;
        RECT  100.176 0 100.2 0.084 ;
    END
  END po[307]
  PIN po[308]
    DIRECTION INPUT ;
    USE SIGNAL ;
    PORT
      LAYER M5 ;
        RECT  100.464 0 100.488 0.084 ;
    END
  END po[308]
  PIN po[309]
    DIRECTION INPUT ;
    USE SIGNAL ;
    PORT
      LAYER M5 ;
        RECT  100.8 0 100.824 0.084 ;
    END
  END po[309]
  PIN po[30]
    DIRECTION INPUT ;
    USE SIGNAL ;
    PORT
      LAYER M5 ;
        RECT  12.24 0 12.264 0.084 ;
    END
  END po[30]
  PIN po[310]
    DIRECTION INPUT ;
    USE SIGNAL ;
    PORT
      LAYER M5 ;
        RECT  101.136 0 101.16 0.084 ;
    END
  END po[310]
  PIN po[311]
    DIRECTION INPUT ;
    USE SIGNAL ;
    PORT
      LAYER M5 ;
        RECT  101.424 0 101.448 0.084 ;
    END
  END po[311]
  PIN po[312]
    DIRECTION INPUT ;
    USE SIGNAL ;
    PORT
      LAYER M5 ;
        RECT  101.76 0 101.784 0.084 ;
    END
  END po[312]
  PIN po[313]
    DIRECTION INPUT ;
    USE SIGNAL ;
    PORT
      LAYER M5 ;
        RECT  102.048 0 102.072 0.084 ;
    END
  END po[313]
  PIN po[314]
    DIRECTION INPUT ;
    USE SIGNAL ;
    PORT
      LAYER M5 ;
        RECT  102.384 0 102.408 0.084 ;
    END
  END po[314]
  PIN po[315]
    DIRECTION INPUT ;
    USE SIGNAL ;
    PORT
      LAYER M5 ;
        RECT  102.72 0 102.744 0.084 ;
    END
  END po[315]
  PIN po[316]
    DIRECTION INPUT ;
    USE SIGNAL ;
    PORT
      LAYER M5 ;
        RECT  103.008 0 103.032 0.084 ;
    END
  END po[316]
  PIN po[317]
    DIRECTION INPUT ;
    USE SIGNAL ;
    PORT
      LAYER M5 ;
        RECT  103.344 0 103.368 0.084 ;
    END
  END po[317]
  PIN po[318]
    DIRECTION INPUT ;
    USE SIGNAL ;
    PORT
      LAYER M5 ;
        RECT  103.68 0 103.704 0.084 ;
    END
  END po[318]
  PIN po[319]
    DIRECTION INPUT ;
    USE SIGNAL ;
    PORT
      LAYER M5 ;
        RECT  103.968 0 103.992 0.084 ;
    END
  END po[319]
  PIN po[31]
    DIRECTION INPUT ;
    USE SIGNAL ;
    PORT
      LAYER M5 ;
        RECT  12.576 0 12.6 0.084 ;
    END
  END po[31]
  PIN po[320]
    DIRECTION INPUT ;
    USE SIGNAL ;
    PORT
      LAYER M5 ;
        RECT  104.304 0 104.328 0.084 ;
    END
  END po[320]
  PIN po[321]
    DIRECTION INPUT ;
    USE SIGNAL ;
    PORT
      LAYER M5 ;
        RECT  104.592 0 104.616 0.084 ;
    END
  END po[321]
  PIN po[322]
    DIRECTION INPUT ;
    USE SIGNAL ;
    PORT
      LAYER M5 ;
        RECT  104.928 0 104.952 0.084 ;
    END
  END po[322]
  PIN po[323]
    DIRECTION INPUT ;
    USE SIGNAL ;
    PORT
      LAYER M5 ;
        RECT  105.264 0 105.288 0.084 ;
    END
  END po[323]
  PIN po[324]
    DIRECTION INPUT ;
    USE SIGNAL ;
    PORT
      LAYER M5 ;
        RECT  105.552 0 105.576 0.084 ;
    END
  END po[324]
  PIN po[325]
    DIRECTION INPUT ;
    USE SIGNAL ;
    PORT
      LAYER M5 ;
        RECT  105.888 0 105.912 0.084 ;
    END
  END po[325]
  PIN po[326]
    DIRECTION INPUT ;
    USE SIGNAL ;
    PORT
      LAYER M5 ;
        RECT  106.176 0 106.2 0.084 ;
    END
  END po[326]
  PIN po[327]
    DIRECTION INPUT ;
    USE SIGNAL ;
    PORT
      LAYER M5 ;
        RECT  106.512 0 106.536 0.084 ;
    END
  END po[327]
  PIN po[32]
    DIRECTION INPUT ;
    USE SIGNAL ;
    PORT
      LAYER M5 ;
        RECT  12.912 0 12.936 0.084 ;
    END
  END po[32]
  PIN po[33]
    DIRECTION INPUT ;
    USE SIGNAL ;
    PORT
      LAYER M5 ;
        RECT  13.2 0 13.224 0.084 ;
    END
  END po[33]
  PIN po[34]
    DIRECTION INPUT ;
    USE SIGNAL ;
    PORT
      LAYER M5 ;
        RECT  13.536 0 13.56 0.084 ;
    END
  END po[34]
  PIN po[35]
    DIRECTION INPUT ;
    USE SIGNAL ;
    PORT
      LAYER M5 ;
        RECT  13.824 0 13.848 0.084 ;
    END
  END po[35]
  PIN po[36]
    DIRECTION INPUT ;
    USE SIGNAL ;
    PORT
      LAYER M5 ;
        RECT  14.16 0 14.184 0.084 ;
    END
  END po[36]
  PIN po[37]
    DIRECTION INPUT ;
    USE SIGNAL ;
    PORT
      LAYER M5 ;
        RECT  14.496 0 14.52 0.084 ;
    END
  END po[37]
  PIN po[38]
    DIRECTION INPUT ;
    USE SIGNAL ;
    PORT
      LAYER M5 ;
        RECT  14.784 0 14.808 0.084 ;
    END
  END po[38]
  PIN po[39]
    DIRECTION INPUT ;
    USE SIGNAL ;
    PORT
      LAYER M5 ;
        RECT  15.12 0 15.144 0.084 ;
    END
  END po[39]
  PIN po[3]
    DIRECTION INPUT ;
    USE SIGNAL ;
    PORT
      LAYER M5 ;
        RECT  3.696 0 3.72 0.084 ;
    END
  END po[3]
  PIN po[40]
    DIRECTION INPUT ;
    USE SIGNAL ;
    PORT
      LAYER M5 ;
        RECT  15.408 0 15.432 0.084 ;
    END
  END po[40]
  PIN po[41]
    DIRECTION INPUT ;
    USE SIGNAL ;
    PORT
      LAYER M5 ;
        RECT  15.744 0 15.768 0.084 ;
    END
  END po[41]
  PIN po[42]
    DIRECTION INPUT ;
    USE SIGNAL ;
    PORT
      LAYER M5 ;
        RECT  16.08 0 16.104 0.084 ;
    END
  END po[42]
  PIN po[43]
    DIRECTION INPUT ;
    USE SIGNAL ;
    PORT
      LAYER M5 ;
        RECT  16.368 0 16.392 0.084 ;
    END
  END po[43]
  PIN po[44]
    DIRECTION INPUT ;
    USE SIGNAL ;
    PORT
      LAYER M5 ;
        RECT  16.704 0 16.728 0.084 ;
    END
  END po[44]
  PIN po[45]
    DIRECTION INPUT ;
    USE SIGNAL ;
    PORT
      LAYER M5 ;
        RECT  16.992 0 17.016 0.084 ;
    END
  END po[45]
  PIN po[46]
    DIRECTION INPUT ;
    USE SIGNAL ;
    PORT
      LAYER M5 ;
        RECT  17.328 0 17.352 0.084 ;
    END
  END po[46]
  PIN po[47]
    DIRECTION INPUT ;
    USE SIGNAL ;
    PORT
      LAYER M5 ;
        RECT  17.664 0 17.688 0.084 ;
    END
  END po[47]
  PIN po[48]
    DIRECTION INPUT ;
    USE SIGNAL ;
    PORT
      LAYER M5 ;
        RECT  17.952 0 17.976 0.084 ;
    END
  END po[48]
  PIN po[49]
    DIRECTION INPUT ;
    USE SIGNAL ;
    PORT
      LAYER M5 ;
        RECT  18.288 0 18.312 0.084 ;
    END
  END po[49]
  PIN po[4]
    DIRECTION INPUT ;
    USE SIGNAL ;
    PORT
      LAYER M5 ;
        RECT  3.984 0 4.008 0.084 ;
    END
  END po[4]
  PIN po[50]
    DIRECTION INPUT ;
    USE SIGNAL ;
    PORT
      LAYER M5 ;
        RECT  18.624 0 18.648 0.084 ;
    END
  END po[50]
  PIN po[51]
    DIRECTION INPUT ;
    USE SIGNAL ;
    PORT
      LAYER M5 ;
        RECT  18.912 0 18.936 0.084 ;
    END
  END po[51]
  PIN po[52]
    DIRECTION INPUT ;
    USE SIGNAL ;
    PORT
      LAYER M5 ;
        RECT  19.248 0 19.272 0.084 ;
    END
  END po[52]
  PIN po[53]
    DIRECTION INPUT ;
    USE SIGNAL ;
    PORT
      LAYER M5 ;
        RECT  19.536 0 19.56 0.084 ;
    END
  END po[53]
  PIN po[54]
    DIRECTION INPUT ;
    USE SIGNAL ;
    PORT
      LAYER M5 ;
        RECT  19.872 0 19.896 0.084 ;
    END
  END po[54]
  PIN po[55]
    DIRECTION INPUT ;
    USE SIGNAL ;
    PORT
      LAYER M5 ;
        RECT  20.208 0 20.232 0.084 ;
    END
  END po[55]
  PIN po[56]
    DIRECTION INPUT ;
    USE SIGNAL ;
    PORT
      LAYER M5 ;
        RECT  20.496 0 20.52 0.084 ;
    END
  END po[56]
  PIN po[57]
    DIRECTION INPUT ;
    USE SIGNAL ;
    PORT
      LAYER M5 ;
        RECT  20.832 0 20.856 0.084 ;
    END
  END po[57]
  PIN po[58]
    DIRECTION INPUT ;
    USE SIGNAL ;
    PORT
      LAYER M5 ;
        RECT  21.12 0 21.144 0.084 ;
    END
  END po[58]
  PIN po[59]
    DIRECTION INPUT ;
    USE SIGNAL ;
    PORT
      LAYER M5 ;
        RECT  21.456 0 21.48 0.084 ;
    END
  END po[59]
  PIN po[5]
    DIRECTION INPUT ;
    USE SIGNAL ;
    PORT
      LAYER M5 ;
        RECT  4.32 0 4.344 0.084 ;
    END
  END po[5]
  PIN po[60]
    DIRECTION INPUT ;
    USE SIGNAL ;
    PORT
      LAYER M5 ;
        RECT  21.792 0 21.816 0.084 ;
    END
  END po[60]
  PIN po[61]
    DIRECTION INPUT ;
    USE SIGNAL ;
    PORT
      LAYER M5 ;
        RECT  22.08 0 22.104 0.084 ;
    END
  END po[61]
  PIN po[62]
    DIRECTION INPUT ;
    USE SIGNAL ;
    PORT
      LAYER M5 ;
        RECT  22.416 0 22.44 0.084 ;
    END
  END po[62]
  PIN po[63]
    DIRECTION INPUT ;
    USE SIGNAL ;
    PORT
      LAYER M5 ;
        RECT  22.752 0 22.776 0.084 ;
    END
  END po[63]
  PIN po[64]
    DIRECTION INPUT ;
    USE SIGNAL ;
    PORT
      LAYER M5 ;
        RECT  23.04 0 23.064 0.084 ;
    END
  END po[64]
  PIN po[65]
    DIRECTION INPUT ;
    USE SIGNAL ;
    PORT
      LAYER M5 ;
        RECT  23.376 0 23.4 0.084 ;
    END
  END po[65]
  PIN po[66]
    DIRECTION INPUT ;
    USE SIGNAL ;
    PORT
      LAYER M5 ;
        RECT  23.664 0 23.688 0.084 ;
    END
  END po[66]
  PIN po[67]
    DIRECTION INPUT ;
    USE SIGNAL ;
    PORT
      LAYER M5 ;
        RECT  24 0 24.024 0.084 ;
    END
  END po[67]
  PIN po[68]
    DIRECTION INPUT ;
    USE SIGNAL ;
    PORT
      LAYER M5 ;
        RECT  24.336 0 24.36 0.084 ;
    END
  END po[68]
  PIN po[69]
    DIRECTION INPUT ;
    USE SIGNAL ;
    PORT
      LAYER M5 ;
        RECT  24.624 0 24.648 0.084 ;
    END
  END po[69]
  PIN po[6]
    DIRECTION INPUT ;
    USE SIGNAL ;
    PORT
      LAYER M5 ;
        RECT  4.656 0 4.68 0.084 ;
    END
  END po[6]
  PIN po[70]
    DIRECTION INPUT ;
    USE SIGNAL ;
    PORT
      LAYER M5 ;
        RECT  24.96 0 24.984 0.084 ;
    END
  END po[70]
  PIN po[71]
    DIRECTION INPUT ;
    USE SIGNAL ;
    PORT
      LAYER M5 ;
        RECT  25.248 0 25.272 0.084 ;
    END
  END po[71]
  PIN po[72]
    DIRECTION INPUT ;
    USE SIGNAL ;
    PORT
      LAYER M5 ;
        RECT  25.584 0 25.608 0.084 ;
    END
  END po[72]
  PIN po[73]
    DIRECTION INPUT ;
    USE SIGNAL ;
    PORT
      LAYER M5 ;
        RECT  25.92 0 25.944 0.084 ;
    END
  END po[73]
  PIN po[74]
    DIRECTION INPUT ;
    USE SIGNAL ;
    PORT
      LAYER M5 ;
        RECT  26.208 0 26.232 0.084 ;
    END
  END po[74]
  PIN po[75]
    DIRECTION INPUT ;
    USE SIGNAL ;
    PORT
      LAYER M5 ;
        RECT  26.544 0 26.568 0.084 ;
    END
  END po[75]
  PIN po[76]
    DIRECTION INPUT ;
    USE SIGNAL ;
    PORT
      LAYER M5 ;
        RECT  26.832 0 26.856 0.084 ;
    END
  END po[76]
  PIN po[77]
    DIRECTION INPUT ;
    USE SIGNAL ;
    PORT
      LAYER M5 ;
        RECT  27.168 0 27.192 0.084 ;
    END
  END po[77]
  PIN po[78]
    DIRECTION INPUT ;
    USE SIGNAL ;
    PORT
      LAYER M5 ;
        RECT  27.504 0 27.528 0.084 ;
    END
  END po[78]
  PIN po[79]
    DIRECTION INPUT ;
    USE SIGNAL ;
    PORT
      LAYER M5 ;
        RECT  27.792 0 27.816 0.084 ;
    END
  END po[79]
  PIN po[7]
    DIRECTION INPUT ;
    USE SIGNAL ;
    PORT
      LAYER M5 ;
        RECT  4.944 0 4.968 0.084 ;
    END
  END po[7]
  PIN po[80]
    DIRECTION INPUT ;
    USE SIGNAL ;
    PORT
      LAYER M5 ;
        RECT  28.128 0 28.152 0.084 ;
    END
  END po[80]
  PIN po[81]
    DIRECTION INPUT ;
    USE SIGNAL ;
    PORT
      LAYER M5 ;
        RECT  28.464 0 28.488 0.084 ;
    END
  END po[81]
  PIN po[82]
    DIRECTION INPUT ;
    USE SIGNAL ;
    PORT
      LAYER M5 ;
        RECT  28.752 0 28.776 0.084 ;
    END
  END po[82]
  PIN po[83]
    DIRECTION INPUT ;
    USE SIGNAL ;
    PORT
      LAYER M5 ;
        RECT  29.088 0 29.112 0.084 ;
    END
  END po[83]
  PIN po[84]
    DIRECTION INPUT ;
    USE SIGNAL ;
    PORT
      LAYER M5 ;
        RECT  29.376 0 29.4 0.084 ;
    END
  END po[84]
  PIN po[85]
    DIRECTION INPUT ;
    USE SIGNAL ;
    PORT
      LAYER M5 ;
        RECT  29.712 0 29.736 0.084 ;
    END
  END po[85]
  PIN po[86]
    DIRECTION INPUT ;
    USE SIGNAL ;
    PORT
      LAYER M5 ;
        RECT  30.048 0 30.072 0.084 ;
    END
  END po[86]
  PIN po[87]
    DIRECTION INPUT ;
    USE SIGNAL ;
    PORT
      LAYER M5 ;
        RECT  30.336 0 30.36 0.084 ;
    END
  END po[87]
  PIN po[88]
    DIRECTION INPUT ;
    USE SIGNAL ;
    PORT
      LAYER M5 ;
        RECT  30.672 0 30.696 0.084 ;
    END
  END po[88]
  PIN po[89]
    DIRECTION INPUT ;
    USE SIGNAL ;
    PORT
      LAYER M5 ;
        RECT  30.96 0 30.984 0.084 ;
    END
  END po[89]
  PIN po[8]
    DIRECTION INPUT ;
    USE SIGNAL ;
    PORT
      LAYER M5 ;
        RECT  5.28 0 5.304 0.084 ;
    END
  END po[8]
  PIN po[90]
    DIRECTION INPUT ;
    USE SIGNAL ;
    PORT
      LAYER M5 ;
        RECT  31.296 0 31.32 0.084 ;
    END
  END po[90]
  PIN po[91]
    DIRECTION INPUT ;
    USE SIGNAL ;
    PORT
      LAYER M5 ;
        RECT  31.632 0 31.656 0.084 ;
    END
  END po[91]
  PIN po[92]
    DIRECTION INPUT ;
    USE SIGNAL ;
    PORT
      LAYER M5 ;
        RECT  31.92 0 31.944 0.084 ;
    END
  END po[92]
  PIN po[93]
    DIRECTION INPUT ;
    USE SIGNAL ;
    PORT
      LAYER M5 ;
        RECT  32.256 0 32.28 0.084 ;
    END
  END po[93]
  PIN po[94]
    DIRECTION INPUT ;
    USE SIGNAL ;
    PORT
      LAYER M5 ;
        RECT  32.544 0 32.568 0.084 ;
    END
  END po[94]
  PIN po[95]
    DIRECTION INPUT ;
    USE SIGNAL ;
    PORT
      LAYER M5 ;
        RECT  32.88 0 32.904 0.084 ;
    END
  END po[95]
  PIN po[96]
    DIRECTION INPUT ;
    USE SIGNAL ;
    PORT
      LAYER M5 ;
        RECT  33.216 0 33.24 0.084 ;
    END
  END po[96]
  PIN po[97]
    DIRECTION INPUT ;
    USE SIGNAL ;
    PORT
      LAYER M5 ;
        RECT  33.504 0 33.528 0.084 ;
    END
  END po[97]
  PIN po[98]
    DIRECTION INPUT ;
    USE SIGNAL ;
    PORT
      LAYER M5 ;
        RECT  33.84 0 33.864 0.084 ;
    END
  END po[98]
  PIN po[99]
    DIRECTION INPUT ;
    USE SIGNAL ;
    PORT
      LAYER M5 ;
        RECT  34.176 0 34.2 0.084 ;
    END
  END po[99]
  PIN po[9]
    DIRECTION INPUT ;
    USE SIGNAL ;
    PORT
      LAYER M5 ;
        RECT  5.568 0 5.592 0.084 ;
    END
  END po[9]
  PIN static_column
    DIRECTION INPUT ;
    USE SIGNAL ;
    PORT
      LAYER M5 ;
        RECT  106.848 0 106.872 0.084 ;
    END
  END static_column
  PIN VDD
    DIRECTION INOUT ;
    USE POWER ;
    PORT
      LAYER M5 ;
        RECT  105.192 2.151 105.312 78.849 ;
        RECT  99.792 2.151 99.912 78.849 ;
        RECT  94.392 2.151 94.512 78.849 ;
        RECT  88.992 2.151 89.112 78.849 ;
        RECT  83.592 2.151 83.712 78.849 ;
        RECT  78.192 2.151 78.312 78.849 ;
        RECT  72.792 2.151 72.912 78.849 ;
        RECT  67.392 2.151 67.512 78.849 ;
        RECT  61.992 2.151 62.112 78.849 ;
        RECT  56.592 2.151 56.712 78.849 ;
        RECT  51.192 2.151 51.312 78.849 ;
        RECT  45.792 2.151 45.912 78.849 ;
        RECT  40.392 2.151 40.512 78.849 ;
        RECT  34.992 2.151 35.112 78.849 ;
        RECT  29.592 2.151 29.712 78.849 ;
        RECT  24.192 2.151 24.312 78.849 ;
        RECT  18.792 2.151 18.912 78.849 ;
        RECT  13.392 2.151 13.512 78.849 ;
        RECT  7.992 2.151 8.112 78.849 ;
        RECT  2.592 2.151 2.712 78.849 ;
    END
  END VDD
  PIN VSS
    DIRECTION INOUT ;
    USE GROUND ;
    PORT
      LAYER M5 ;
        RECT  105 2.137 105.12 78.863 ;
        RECT  99.6 2.137 99.72 78.863 ;
        RECT  94.2 2.137 94.32 78.863 ;
        RECT  88.8 2.137 88.92 78.863 ;
        RECT  83.4 2.137 83.52 78.863 ;
        RECT  78 2.137 78.12 78.863 ;
        RECT  72.6 2.137 72.72 78.863 ;
        RECT  67.2 2.137 67.32 78.863 ;
        RECT  61.8 2.137 61.92 78.863 ;
        RECT  56.4 2.137 56.52 78.863 ;
        RECT  51 2.137 51.12 78.863 ;
        RECT  45.6 2.137 45.72 78.863 ;
        RECT  40.2 2.137 40.32 78.863 ;
        RECT  34.8 2.137 34.92 78.863 ;
        RECT  29.4 2.137 29.52 78.863 ;
        RECT  24 2.137 24.12 78.863 ;
        RECT  18.6 2.137 18.72 78.863 ;
        RECT  13.2 2.137 13.32 78.863 ;
        RECT  7.8 2.137 7.92 78.863 ;
        RECT  2.4 2.137 2.52 78.863 ;
    END
  END VSS
  OBS
    LAYER RVTN ;
     RECT  2.16 2.16 105.84 2.295 ;
     RECT  2.16 2.565 105.84 2.835 ;
     RECT  2.16 3.105 105.84 3.375 ;
     RECT  2.16 3.645 105.84 3.915 ;
     RECT  2.16 4.185 105.84 4.455 ;
     RECT  2.16 4.725 105.84 4.995 ;
     RECT  2.16 5.265 105.84 5.535 ;
     RECT  2.16 5.805 105.84 6.075 ;
     RECT  2.16 6.345 105.84 6.615 ;
     RECT  2.16 6.885 105.84 7.155 ;
     RECT  2.16 7.425 105.84 7.695 ;
     RECT  2.16 7.965 105.84 8.235 ;
     RECT  2.16 8.505 105.84 8.775 ;
     RECT  2.16 9.045 105.84 9.315 ;
     RECT  2.16 9.585 105.84 9.855 ;
     RECT  2.16 10.125 105.84 10.395 ;
     RECT  2.16 10.665 105.84 10.935 ;
     RECT  2.16 11.205 105.84 11.475 ;
     RECT  2.16 11.745 105.84 12.015 ;
     RECT  2.16 12.285 105.84 12.555 ;
     RECT  2.16 12.825 105.84 13.095 ;
     RECT  2.16 13.365 105.84 13.635 ;
     RECT  2.16 13.905 105.84 14.175 ;
     RECT  2.16 14.445 105.84 14.715 ;
     RECT  2.16 14.985 105.84 15.255 ;
     RECT  2.16 15.525 105.84 15.795 ;
     RECT  2.16 16.065 105.84 16.335 ;
     RECT  2.16 16.605 105.84 16.875 ;
     RECT  2.16 17.145 105.84 17.415 ;
     RECT  2.16 17.685 105.84 17.955 ;
     RECT  2.16 18.225 105.84 18.495 ;
     RECT  2.16 18.765 105.84 19.035 ;
     RECT  2.16 19.305 105.84 19.575 ;
     RECT  2.16 19.845 105.84 20.115 ;
     RECT  2.16 20.385 105.84 20.655 ;
     RECT  2.16 20.925 105.84 21.195 ;
     RECT  2.16 21.465 105.84 21.735 ;
     RECT  2.16 22.005 105.84 22.275 ;
     RECT  2.16 22.545 105.84 22.815 ;
     RECT  2.16 23.085 105.84 23.355 ;
     RECT  2.16 23.625 105.84 23.895 ;
     RECT  2.16 24.165 105.84 24.435 ;
     RECT  2.16 24.705 105.84 24.975 ;
     RECT  2.16 25.245 105.84 25.515 ;
     RECT  2.16 25.785 105.84 26.055 ;
     RECT  2.16 26.325 105.84 26.595 ;
     RECT  2.16 26.865 105.84 27.135 ;
     RECT  2.16 27.405 105.84 27.675 ;
     RECT  2.16 27.945 105.84 28.215 ;
     RECT  2.16 28.485 105.84 28.755 ;
     RECT  2.16 29.025 105.84 29.295 ;
     RECT  2.16 29.565 105.84 29.835 ;
     RECT  2.16 30.105 105.84 30.375 ;
     RECT  2.16 30.645 105.84 30.915 ;
     RECT  2.16 31.185 105.84 31.455 ;
     RECT  2.16 31.725 105.84 31.995 ;
     RECT  2.16 32.265 105.84 32.535 ;
     RECT  2.16 32.805 105.84 33.075 ;
     RECT  2.16 33.345 105.84 33.615 ;
     RECT  2.16 33.885 105.84 34.155 ;
     RECT  2.16 34.425 105.84 34.695 ;
     RECT  2.16 34.965 105.84 35.235 ;
     RECT  2.16 35.505 105.84 35.775 ;
     RECT  2.16 36.045 105.84 36.315 ;
     RECT  2.16 36.585 105.84 36.855 ;
     RECT  2.16 37.125 105.84 37.395 ;
     RECT  2.16 37.665 105.84 37.935 ;
     RECT  2.16 38.205 105.84 38.475 ;
     RECT  2.16 38.745 105.84 39.015 ;
     RECT  2.16 39.285 105.84 39.555 ;
     RECT  2.16 39.825 105.84 40.095 ;
     RECT  2.16 40.365 105.84 40.635 ;
     RECT  2.16 40.905 105.84 41.175 ;
     RECT  2.16 41.445 105.84 41.715 ;
     RECT  2.16 41.985 105.84 42.255 ;
     RECT  2.16 42.525 105.84 42.795 ;
     RECT  2.16 43.065 105.84 43.335 ;
     RECT  2.16 43.605 105.84 43.875 ;
     RECT  2.16 44.145 105.84 44.415 ;
     RECT  2.16 44.685 105.84 44.955 ;
     RECT  2.16 45.225 105.84 45.495 ;
     RECT  2.16 45.765 105.84 46.035 ;
     RECT  2.16 46.305 105.84 46.575 ;
     RECT  2.16 46.845 105.84 47.115 ;
     RECT  2.16 47.385 105.84 47.655 ;
     RECT  2.16 47.925 105.84 48.195 ;
     RECT  2.16 48.465 105.84 48.735 ;
     RECT  2.16 49.005 105.84 49.275 ;
     RECT  2.16 49.545 105.84 49.815 ;
     RECT  2.16 50.085 105.84 50.355 ;
     RECT  2.16 50.625 105.84 50.895 ;
     RECT  2.16 51.165 105.84 51.435 ;
     RECT  2.16 51.705 105.84 51.975 ;
     RECT  2.16 52.245 105.84 52.515 ;
     RECT  2.16 52.785 105.84 53.055 ;
     RECT  2.16 53.325 105.84 53.595 ;
     RECT  2.16 53.865 105.84 54.135 ;
     RECT  2.16 54.405 105.84 54.675 ;
     RECT  2.16 54.945 105.84 55.215 ;
     RECT  2.16 55.485 105.84 55.755 ;
     RECT  2.16 56.025 105.84 56.295 ;
     RECT  2.16 56.565 105.84 56.835 ;
     RECT  2.16 57.105 105.84 57.375 ;
     RECT  2.16 57.645 105.84 57.915 ;
     RECT  2.16 58.185 105.84 58.455 ;
     RECT  2.16 58.725 105.84 58.995 ;
     RECT  2.16 59.265 105.84 59.535 ;
     RECT  2.16 59.805 105.84 60.075 ;
     RECT  2.16 60.345 105.84 60.615 ;
     RECT  2.16 60.885 105.84 61.155 ;
     RECT  2.16 61.425 105.84 61.695 ;
     RECT  2.16 61.965 105.84 62.235 ;
     RECT  2.16 62.505 105.84 62.775 ;
     RECT  2.16 63.045 105.84 63.315 ;
     RECT  2.16 63.585 105.84 63.855 ;
     RECT  2.16 64.125 105.84 64.395 ;
     RECT  2.16 64.665 105.84 64.935 ;
     RECT  2.16 65.205 105.84 65.475 ;
     RECT  2.16 65.745 105.84 66.015 ;
     RECT  2.16 66.285 105.84 66.555 ;
     RECT  2.16 66.825 105.84 67.095 ;
     RECT  2.16 67.365 105.84 67.635 ;
     RECT  2.16 67.905 105.84 68.175 ;
     RECT  2.16 68.445 105.84 68.715 ;
     RECT  2.16 68.985 105.84 69.255 ;
     RECT  2.16 69.525 105.84 69.795 ;
     RECT  2.16 70.065 105.84 70.335 ;
     RECT  2.16 70.605 105.84 70.875 ;
     RECT  2.16 71.145 105.84 71.415 ;
     RECT  2.16 71.685 105.84 71.955 ;
     RECT  2.16 72.225 105.84 72.495 ;
     RECT  2.16 72.765 105.84 73.035 ;
     RECT  2.16 73.305 105.84 73.575 ;
     RECT  2.16 73.845 105.84 74.115 ;
     RECT  2.16 74.385 105.84 74.655 ;
     RECT  2.16 74.925 105.84 75.195 ;
     RECT  2.16 75.465 105.84 75.735 ;
     RECT  2.16 76.005 105.84 76.275 ;
     RECT  2.16 76.545 105.84 76.815 ;
     RECT  2.16 77.085 105.84 77.355 ;
     RECT  2.16 77.625 105.84 77.895 ;
     RECT  2.16 78.165 105.84 78.435 ;
     RECT  2.16 78.705 105.84 78.84 ;
    LAYER RVTP ;
     RECT  2.16 2.295 105.84 2.565 ;
     RECT  2.16 2.835 105.84 3.105 ;
     RECT  2.16 3.375 105.84 3.645 ;
     RECT  2.16 3.915 105.84 4.185 ;
     RECT  2.16 4.455 105.84 4.725 ;
     RECT  2.16 4.995 105.84 5.265 ;
     RECT  2.16 5.535 105.84 5.805 ;
     RECT  2.16 6.075 105.84 6.345 ;
     RECT  2.16 6.615 105.84 6.885 ;
     RECT  2.16 7.155 105.84 7.425 ;
     RECT  2.16 7.695 105.84 7.965 ;
     RECT  2.16 8.235 105.84 8.505 ;
     RECT  2.16 8.775 105.84 9.045 ;
     RECT  2.16 9.315 105.84 9.585 ;
     RECT  2.16 9.855 105.84 10.125 ;
     RECT  2.16 10.395 105.84 10.665 ;
     RECT  2.16 10.935 105.84 11.205 ;
     RECT  2.16 11.475 105.84 11.745 ;
     RECT  2.16 12.015 105.84 12.285 ;
     RECT  2.16 12.555 105.84 12.825 ;
     RECT  2.16 13.095 105.84 13.365 ;
     RECT  2.16 13.635 105.84 13.905 ;
     RECT  2.16 14.175 105.84 14.445 ;
     RECT  2.16 14.715 105.84 14.985 ;
     RECT  2.16 15.255 105.84 15.525 ;
     RECT  2.16 15.795 105.84 16.065 ;
     RECT  2.16 16.335 105.84 16.605 ;
     RECT  2.16 16.875 105.84 17.145 ;
     RECT  2.16 17.415 105.84 17.685 ;
     RECT  2.16 17.955 105.84 18.225 ;
     RECT  2.16 18.495 105.84 18.765 ;
     RECT  2.16 19.035 105.84 19.305 ;
     RECT  2.16 19.575 105.84 19.845 ;
     RECT  2.16 20.115 105.84 20.385 ;
     RECT  2.16 20.655 105.84 20.925 ;
     RECT  2.16 21.195 105.84 21.465 ;
     RECT  2.16 21.735 105.84 22.005 ;
     RECT  2.16 22.275 105.84 22.545 ;
     RECT  2.16 22.815 105.84 23.085 ;
     RECT  2.16 23.355 105.84 23.625 ;
     RECT  2.16 23.895 105.84 24.165 ;
     RECT  2.16 24.435 105.84 24.705 ;
     RECT  2.16 24.975 105.84 25.245 ;
     RECT  2.16 25.515 105.84 25.785 ;
     RECT  2.16 26.055 105.84 26.325 ;
     RECT  2.16 26.595 105.84 26.865 ;
     RECT  2.16 27.135 105.84 27.405 ;
     RECT  2.16 27.675 105.84 27.945 ;
     RECT  2.16 28.215 105.84 28.485 ;
     RECT  2.16 28.755 105.84 29.025 ;
     RECT  2.16 29.295 105.84 29.565 ;
     RECT  2.16 29.835 105.84 30.105 ;
     RECT  2.16 30.375 105.84 30.645 ;
     RECT  2.16 30.915 105.84 31.185 ;
     RECT  2.16 31.455 105.84 31.725 ;
     RECT  2.16 31.995 105.84 32.265 ;
     RECT  2.16 32.535 105.84 32.805 ;
     RECT  2.16 33.075 105.84 33.345 ;
     RECT  2.16 33.615 105.84 33.885 ;
     RECT  2.16 34.155 105.84 34.425 ;
     RECT  2.16 34.695 105.84 34.965 ;
     RECT  2.16 35.235 105.84 35.505 ;
     RECT  2.16 35.775 105.84 36.045 ;
     RECT  2.16 36.315 105.84 36.585 ;
     RECT  2.16 36.855 105.84 37.125 ;
     RECT  2.16 37.395 105.84 37.665 ;
     RECT  2.16 37.935 105.84 38.205 ;
     RECT  2.16 38.475 105.84 38.745 ;
     RECT  2.16 39.015 105.84 39.285 ;
     RECT  2.16 39.555 105.84 39.825 ;
     RECT  2.16 40.095 105.84 40.365 ;
     RECT  2.16 40.635 105.84 40.905 ;
     RECT  2.16 41.175 105.84 41.445 ;
     RECT  2.16 41.715 105.84 41.985 ;
     RECT  2.16 42.255 105.84 42.525 ;
     RECT  2.16 42.795 105.84 43.065 ;
     RECT  2.16 43.335 105.84 43.605 ;
     RECT  2.16 43.875 105.84 44.145 ;
     RECT  2.16 44.415 105.84 44.685 ;
     RECT  2.16 44.955 105.84 45.225 ;
     RECT  2.16 45.495 105.84 45.765 ;
     RECT  2.16 46.035 105.84 46.305 ;
     RECT  2.16 46.575 105.84 46.845 ;
     RECT  2.16 47.115 105.84 47.385 ;
     RECT  2.16 47.655 105.84 47.925 ;
     RECT  2.16 48.195 105.84 48.465 ;
     RECT  2.16 48.735 105.84 49.005 ;
     RECT  2.16 49.275 105.84 49.545 ;
     RECT  2.16 49.815 105.84 50.085 ;
     RECT  2.16 50.355 105.84 50.625 ;
     RECT  2.16 50.895 105.84 51.165 ;
     RECT  2.16 51.435 105.84 51.705 ;
     RECT  2.16 51.975 105.84 52.245 ;
     RECT  2.16 52.515 105.84 52.785 ;
     RECT  2.16 53.055 105.84 53.325 ;
     RECT  2.16 53.595 105.84 53.865 ;
     RECT  2.16 54.135 105.84 54.405 ;
     RECT  2.16 54.675 105.84 54.945 ;
     RECT  2.16 55.215 105.84 55.485 ;
     RECT  2.16 55.755 105.84 56.025 ;
     RECT  2.16 56.295 105.84 56.565 ;
     RECT  2.16 56.835 105.84 57.105 ;
     RECT  2.16 57.375 105.84 57.645 ;
     RECT  2.16 57.915 105.84 58.185 ;
     RECT  2.16 58.455 105.84 58.725 ;
     RECT  2.16 58.995 105.84 59.265 ;
     RECT  2.16 59.535 105.84 59.805 ;
     RECT  2.16 60.075 105.84 60.345 ;
     RECT  2.16 60.615 105.84 60.885 ;
     RECT  2.16 61.155 105.84 61.425 ;
     RECT  2.16 61.695 105.84 61.965 ;
     RECT  2.16 62.235 105.84 62.505 ;
     RECT  2.16 62.775 105.84 63.045 ;
     RECT  2.16 63.315 105.84 63.585 ;
     RECT  2.16 63.855 105.84 64.125 ;
     RECT  2.16 64.395 105.84 64.665 ;
     RECT  2.16 64.935 105.84 65.205 ;
     RECT  2.16 65.475 105.84 65.745 ;
     RECT  2.16 66.015 105.84 66.285 ;
     RECT  2.16 66.555 105.84 66.825 ;
     RECT  2.16 67.095 105.84 67.365 ;
     RECT  2.16 67.635 105.84 67.905 ;
     RECT  2.16 68.175 105.84 68.445 ;
     RECT  2.16 68.715 105.84 68.985 ;
     RECT  2.16 69.255 105.84 69.525 ;
     RECT  2.16 69.795 105.84 70.065 ;
     RECT  2.16 70.335 105.84 70.605 ;
     RECT  2.16 70.875 105.84 71.145 ;
     RECT  2.16 71.415 105.84 71.685 ;
     RECT  2.16 71.955 105.84 72.225 ;
     RECT  2.16 72.495 105.84 72.765 ;
     RECT  2.16 73.035 105.84 73.305 ;
     RECT  2.16 73.575 105.84 73.845 ;
     RECT  2.16 74.115 105.84 74.385 ;
     RECT  2.16 74.655 105.84 74.925 ;
     RECT  2.16 75.195 105.84 75.465 ;
     RECT  2.16 75.735 105.84 76.005 ;
     RECT  2.16 76.275 105.84 76.545 ;
     RECT  2.16 76.815 105.84 77.085 ;
     RECT  2.16 77.355 105.84 77.625 ;
     RECT  2.16 77.895 105.84 78.165 ;
     RECT  2.16 78.435 105.84 78.705 ;
    LAYER M1 ;
     RECT  2.16 2.151 105.84 78.849 ;
    LAYER M2 ;
     RECT  1.795 2.772 2.16 2.79 ;
     RECT  2.119 4.734 2.16 4.752 ;
     RECT  1.615 77.976 2.16 77.994 ;
     RECT  2.371 1.152 2.579 1.17 ;
     RECT  2.16 2.151 17.203 78.849 ;
     RECT  17.203 1.692 30.307 78.849 ;
     RECT  30.307 1.566 53.527 78.849 ;
     RECT  53.527 1.494 53.635 78.849 ;
     RECT  53.635 1.458 79.115 78.849 ;
     RECT  79.115 1.494 81.815 78.849 ;
     RECT  81.815 1.53 86.639 78.849 ;
     RECT  86.639 1.656 90.851 78.849 ;
     RECT  90.851 1.692 98.879 78.849 ;
     RECT  98.879 2.106 102.227 78.849 ;
     RECT  102.227 2.151 105.84 78.849 ;
     RECT  105.84 27.684 105.899 78.66 ;
     RECT  105.899 27.684 106.007 78.579 ;
     RECT  105.84 5.58 106.043 5.796 ;
     RECT  106.007 27.684 106.043 44.136 ;
     RECT  106.007 45 106.043 78.579 ;
     RECT  106.043 68.76 106.079 77.616 ;
     RECT  106.043 27.72 106.115 35.298 ;
     RECT  106.043 45.198 106.115 55.746 ;
     RECT  105.84 6.66 106.511 6.678 ;
     RECT  105.84 25.218 106.511 26.424 ;
     RECT  105.84 13.716 106.547 15.516 ;
     RECT  106.115 27.918 106.547 35.298 ;
     RECT  106.043 36.288 106.547 44.136 ;
     RECT  106.115 45.198 106.547 45.216 ;
     RECT  106.115 46.008 106.547 55.746 ;
     RECT  106.043 56.808 106.547 60.336 ;
     RECT  106.043 61.128 106.547 64.656 ;
     RECT  106.043 65.448 106.547 67.662 ;
     RECT  106.079 68.76 106.547 73.332 ;
     RECT  105.84 9.828 106.583 11.268 ;
     RECT  105.84 16.848 106.583 19.026 ;
     RECT  105.84 20.358 106.583 24.228 ;
     RECT  106.547 31.428 106.583 34.146 ;
     RECT  106.547 38.448 106.583 39.006 ;
     RECT  106.547 39.87 106.583 41.436 ;
     RECT  106.547 44.118 106.583 44.136 ;
     RECT  106.547 46.278 106.583 48.726 ;
     RECT  106.547 52.29 106.583 53.586 ;
     RECT  106.547 56.808 106.583 59.796 ;
     RECT  106.547 61.74 106.583 64.224 ;
     RECT  106.547 65.718 106.583 67.662 ;
     RECT  106.547 68.76 106.583 71.334 ;
     RECT  106.079 74.088 106.583 77.616 ;
     RECT  105.84 2.916 106.619 4.788 ;
     RECT  106.583 9.828 106.619 10.422 ;
     RECT  106.583 11.25 106.619 11.268 ;
     RECT  105.84 12.528 106.619 12.546 ;
     RECT  106.583 16.848 106.619 18.216 ;
     RECT  106.583 32.778 106.619 34.146 ;
     RECT  106.547 49.518 106.619 50.076 ;
     RECT  106.583 52.29 106.619 53.01 ;
     RECT  106.583 75.006 106.619 77.616 ;
     RECT  106.043 78.444 106.619 78.579 ;
     RECT  106.619 75.006 106.655 77.418 ;
     RECT  106.619 78.561 106.655 78.579 ;
     RECT  106.583 70.65 106.727 71.334 ;
     RECT  105.84 9.018 107.023 9.036 ;
     RECT  106.619 9.828 107.023 9.846 ;
     RECT  106.583 74.088 107.087 74.106 ;
     RECT  106.619 2.916 107.123 3.708 ;
     RECT  107.023 9.018 107.123 9.846 ;
     RECT  106.619 16.848 107.123 17.406 ;
     RECT  106.583 21.78 107.123 24.228 ;
     RECT  106.583 48.438 107.123 48.726 ;
     RECT  106.583 67.338 107.123 67.662 ;
     RECT  106.583 68.76 107.123 69.516 ;
     RECT  106.655 75.168 107.123 77.418 ;
     RECT  106.619 4.464 107.159 4.788 ;
     RECT  106.547 13.716 107.159 15.246 ;
     RECT  107.123 17.388 107.159 17.406 ;
     RECT  106.619 18.198 107.159 18.216 ;
     RECT  106.583 19.008 107.159 19.026 ;
     RECT  106.583 20.358 107.159 20.916 ;
     RECT  107.123 21.78 107.159 23.148 ;
     RECT  107.123 24.21 107.159 24.228 ;
     RECT  106.511 25.218 107.159 26.388 ;
     RECT  106.547 28.188 107.159 29.016 ;
     RECT  106.547 29.808 107.159 29.826 ;
     RECT  106.547 30.618 107.159 30.636 ;
     RECT  106.583 31.428 107.159 31.95 ;
     RECT  106.619 32.778 107.159 33.606 ;
     RECT  106.547 34.938 107.159 35.298 ;
     RECT  106.547 36.288 107.159 36.306 ;
     RECT  106.547 37.098 107.159 37.62 ;
     RECT  106.583 38.988 107.159 39.006 ;
     RECT  106.583 39.87 107.159 40.356 ;
     RECT  106.583 41.22 107.159 41.436 ;
     RECT  106.547 42.606 107.159 43.326 ;
     RECT  106.583 46.278 107.159 46.908 ;
     RECT  107.123 48.438 107.159 48.456 ;
     RECT  106.619 49.518 107.159 49.536 ;
     RECT  106.547 51.48 107.159 51.498 ;
     RECT  106.619 52.29 107.159 52.308 ;
     RECT  106.547 54.99 107.159 55.746 ;
     RECT  106.583 56.808 107.159 58.986 ;
     RECT  106.583 59.778 107.159 59.796 ;
     RECT  106.583 61.74 107.159 63.576 ;
     RECT  106.583 65.718 107.159 66.276 ;
     RECT  107.123 67.338 107.159 67.464 ;
     RECT  107.123 68.76 107.159 69.318 ;
     RECT  107.123 77.13 107.159 77.418 ;
     RECT  107.123 3.69 107.195 3.708 ;
     RECT  107.159 46.314 107.195 46.908 ;
     RECT  107.159 63.054 107.195 63.27 ;
     RECT  107.159 67.41 107.195 67.464 ;
     RECT  106.547 72.27 107.195 73.332 ;
     RECT  107.123 75.168 107.195 75.186 ;
     RECT  107.123 76.086 107.195 76.374 ;
     RECT  107.159 77.13 107.195 77.148 ;
     RECT  107.159 21.78 107.231 22.608 ;
     RECT  107.195 73.008 107.231 73.332 ;
     RECT  107.195 76.086 107.231 76.104 ;
     RECT  107.195 67.41 107.267 67.428 ;
     RECT  107.231 73.008 107.267 73.026 ;
     RECT  106.043 5.778 107.843 5.796 ;
     RECT  107.231 22.59 107.843 22.608 ;
     RECT  107.159 20.43 107.879 20.916 ;
     RECT  107.159 25.794 107.879 25.848 ;
     RECT  107.123 2.916 107.915 2.934 ;
     RECT  107.159 13.716 107.915 13.734 ;
     RECT  107.879 20.43 107.915 20.448 ;
     RECT  107.231 21.78 107.915 21.798 ;
     RECT  107.879 25.794 107.915 25.812 ;
     RECT  107.159 40.104 107.915 40.122 ;
     RECT  107.159 43.308 107.915 43.326 ;
     RECT  107.195 46.314 107.915 46.332 ;
     RECT  107.159 57.114 107.915 57.132 ;
     RECT  107.159 57.96 107.915 57.978 ;
     RECT  106.727 71.316 107.915 71.334 ;
    LAYER M3 ;
     RECT  105.912 0.091 105.93 0.139 ;
     RECT  104.832 0.427 104.85 0.523 ;
     RECT  2.376 0.523 2.394 0.571 ;
     RECT  77.328 0.091 77.346 0.571 ;
     RECT  2.304 0.571 2.394 1.147 ;
     RECT  84.204 0.091 84.222 1.147 ;
     RECT  53.64 1.453 53.658 1.489 ;
     RECT  84.132 1.147 84.222 1.606 ;
     RECT  17.64 0.091 17.91 1.687 ;
     RECT  2.304 1.147 2.574 1.723 ;
     RECT  3.924 0.091 3.942 1.723 ;
     RECT  9.36 0.091 9.378 1.723 ;
     RECT  17.208 1.687 17.91 1.723 ;
     RECT  23.976 0.571 23.994 1.723 ;
     RECT  28.512 1.147 28.53 1.723 ;
     RECT  30.312 1.561 30.33 1.723 ;
     RECT  34.704 0.091 34.722 1.723 ;
     RECT  38.016 1.606 38.034 1.723 ;
     RECT  43.92 1.651 43.938 1.723 ;
     RECT  45.756 1.099 45.774 1.723 ;
     RECT  52.488 0.571 52.506 1.723 ;
     RECT  53.532 1.489 53.658 1.723 ;
     RECT  54.864 1.525 54.882 1.723 ;
     RECT  56.988 0.091 57.006 1.723 ;
     RECT  58.572 0.091 58.59 1.723 ;
     RECT  59.976 1.099 59.994 1.723 ;
     RECT  60.768 0.091 60.786 1.723 ;
     RECT  73.944 1.561 73.962 1.723 ;
     RECT  76.968 0.571 77.346 1.723 ;
     RECT  79.092 1.453 79.11 1.723 ;
     RECT  81.792 1.489 81.81 1.723 ;
     RECT  84.132 1.606 84.69 1.723 ;
     RECT  86.616 1.525 86.634 1.723 ;
     RECT  87.804 0.571 87.822 1.723 ;
     RECT  90.828 1.651 90.846 1.723 ;
     RECT  93.492 0.571 93.51 1.723 ;
     RECT  95.184 0.091 95.202 1.723 ;
     RECT  98.856 1.687 98.874 1.723 ;
     RECT  96.264 1.723 96.282 1.771 ;
     RECT  106.848 0.523 106.866 1.771 ;
     RECT  1.8 1.723 18.09 1.819 ;
     RECT  18.936 1.723 25.002 1.819 ;
     RECT  104.832 0.523 104.886 1.963 ;
     RECT  105.696 0.139 105.93 1.963 ;
     RECT  94.536 1.723 95.202 2.059 ;
     RECT  97.956 1.723 98.91 2.101 ;
     RECT  100.152 0.571 100.17 2.101 ;
     RECT  102.96 1.723 102.978 2.107 ;
     RECT  92.736 1.723 93.51 2.143 ;
     RECT  94.392 2.059 95.202 2.143 ;
     RECT  102.204 2.101 102.222 2.155 ;
     RECT  102.96 2.107 103.626 2.155 ;
     RECT  1.8 1.819 25.002 2.191 ;
     RECT  26.28 1.723 51.462 2.191 ;
     RECT  52.2 1.723 91.998 2.191 ;
     RECT  92.736 2.143 95.202 2.191 ;
     RECT  96.084 1.771 96.282 2.191 ;
     RECT  97.02 2.155 97.038 2.191 ;
     RECT  97.956 2.101 100.638 2.191 ;
     RECT  101.556 2.155 102.222 2.191 ;
     RECT  102.96 2.155 103.842 2.191 ;
     RECT  104.832 1.963 105.93 2.191 ;
     RECT  92.736 2.191 96.282 2.227 ;
     RECT  97.02 2.191 102.222 2.227 ;
     RECT  92.736 2.227 102.222 2.251 ;
     RECT  102.96 2.191 105.93 2.251 ;
     RECT  1.8 2.191 91.998 2.371 ;
     RECT  92.736 2.251 105.93 2.371 ;
     RECT  1.8 2.371 105.93 2.795 ;
     RECT  107.892 2.443 107.91 2.939 ;
     RECT  2.304 2.795 105.93 3.145 ;
     RECT  106.848 1.771 107.118 3.145 ;
     RECT  2.304 3.145 107.118 3.479 ;
     RECT  107.064 3.479 107.118 3.595 ;
     RECT  2.304 3.479 105.93 3.613 ;
     RECT  107.064 3.595 107.154 3.685 ;
     RECT  107.064 3.685 107.19 3.869 ;
     RECT  2.268 3.613 105.93 3.979 ;
     RECT  2.124 3.979 105.93 4.019 ;
     RECT  107.892 4.075 107.91 4.205 ;
     RECT  107.064 3.869 107.154 4.225 ;
     RECT  106.596 4.225 107.154 4.301 ;
     RECT  2.124 4.019 105.714 4.415 ;
     RECT  2.124 4.415 63.162 4.523 ;
     RECT  2.124 4.523 63.054 4.757 ;
     RECT  107.136 4.301 107.154 4.793 ;
     RECT  2.304 4.757 63.054 4.829 ;
     RECT  2.304 4.829 53.154 4.955 ;
     RECT  2.304 4.955 52.398 5.027 ;
     RECT  2.304 5.027 52.362 5.063 ;
     RECT  53.964 4.829 63.054 5.063 ;
     RECT  2.304 5.063 51.498 5.099 ;
     RECT  52.236 5.063 52.362 5.099 ;
     RECT  55.98 5.063 63.054 5.099 ;
     RECT  6.192 5.099 51.498 5.117 ;
     RECT  2.304 5.099 5.274 5.189 ;
     RECT  56.304 5.099 63.054 5.189 ;
     RECT  64.008 4.415 105.714 5.233 ;
     RECT  2.415 5.189 5.274 5.333 ;
     RECT  56.304 5.189 60.894 5.369 ;
     RECT  3.672 5.333 5.274 5.405 ;
     RECT  61.815 5.189 63.054 5.503 ;
     RECT  63.792 5.233 105.714 5.503 ;
     RECT  3.672 5.405 4.554 5.567 ;
     RECT  61.815 5.503 105.714 5.575 ;
     RECT  4.536 5.567 4.554 5.603 ;
     RECT  6.264 5.117 51.498 5.603 ;
     RECT  61.815 5.575 106.038 5.639 ;
     RECT  3.672 5.567 3.69 5.693 ;
     RECT  63.792 5.639 106.038 5.693 ;
     RECT  107.82 5.419 107.838 5.801 ;
     RECT  107.892 5.899 107.91 6.029 ;
     RECT  63.792 5.693 105.714 6.107 ;
     RECT  6.444 5.603 51.498 6.305 ;
     RECT  106.488 6.571 106.506 6.683 ;
     RECT  61.815 5.639 63.054 6.781 ;
     RECT  63.792 6.107 105.534 6.781 ;
     RECT  6.336 6.691 6.354 6.808 ;
     RECT  61.815 6.781 105.534 6.809 ;
     RECT  6.192 6.808 6.354 6.845 ;
     RECT  6.264 6.845 6.354 7.195 ;
     RECT  7.092 6.305 51.498 7.195 ;
     RECT  6.264 7.195 51.498 7.223 ;
     RECT  63.936 6.809 105.534 7.231 ;
     RECT  53.136 4.955 53.154 7.493 ;
     RECT  107.892 7.243 107.91 7.661 ;
     RECT  63.936 7.231 105.606 7.723 ;
     RECT  56.415 5.369 60.894 7.727 ;
     RECT  63.936 7.723 105.714 7.763 ;
     RECT  6.336 7.223 51.498 8.041 ;
     RECT  5.652 8.041 51.498 8.299 ;
     RECT  5.112 8.299 51.498 8.429 ;
     RECT  60.876 7.727 60.894 8.465 ;
     RECT  10.512 8.429 51.498 8.525 ;
     RECT  10.512 8.525 23.166 8.537 ;
     RECT  53.964 5.063 55.098 8.537 ;
     RECT  56.415 7.727 59.562 8.671 ;
     RECT  56.304 8.671 59.562 8.717 ;
     RECT  56.415 8.717 59.562 8.771 ;
     RECT  107.1 8.587 107.118 8.827 ;
     RECT  63.936 7.763 105.606 8.851 ;
     RECT  54.54 8.537 55.098 8.969 ;
     RECT  61.815 6.809 63.162 9.085 ;
     RECT  63.936 8.851 105.714 9.085 ;
     RECT  61.815 9.085 105.714 9.239 ;
     RECT  10.512 8.537 23.094 9.319 ;
     RECT  10.476 9.319 23.094 9.355 ;
     RECT  23.94 8.525 51.498 9.355 ;
     RECT  52.344 5.099 52.362 9.389 ;
     RECT  5.112 8.429 9.594 9.481 ;
     RECT  107.028 8.827 107.118 9.739 ;
     RECT  4.572 9.481 9.666 9.751 ;
     RECT  106.56 9.739 107.118 9.851 ;
     RECT  106.56 9.851 106.614 9.869 ;
     RECT  4.572 9.751 9.738 9.895 ;
     RECT  4.212 9.895 9.738 9.931 ;
     RECT  10.476 9.355 51.498 9.931 ;
     RECT  4.212 9.931 51.498 10.165 ;
     RECT  4.14 10.165 51.498 10.193 ;
     RECT  107.892 10.123 107.91 10.253 ;
     RECT  106.596 9.869 106.614 10.445 ;
     RECT  61.815 9.239 105.57 10.471 ;
     RECT  58.968 8.771 59.562 10.625 ;
     RECT  61.815 10.471 105.714 10.781 ;
     RECT  4.14 10.193 49.878 10.903 ;
     RECT  56.415 8.771 58.23 10.931 ;
     RECT  106.56 10.651 106.578 11.003 ;
     RECT  3.996 10.903 49.878 11.011 ;
     RECT  3.816 11.011 49.878 11.245 ;
     RECT  55.08 8.969 55.098 11.309 ;
     RECT  106.596 11.245 106.614 11.357 ;
     RECT  61.815 10.781 105.642 11.399 ;
     RECT  61.815 11.399 64.638 11.549 ;
     RECT  3.636 11.245 49.878 11.551 ;
     RECT  3.42 11.551 49.878 11.579 ;
     RECT  2.415 5.333 2.697 11.749 ;
     RECT  3.42 11.579 49.374 11.749 ;
     RECT  2.415 11.749 49.374 11.777 ;
     RECT  10.836 11.777 49.374 11.975 ;
     RECT  10.836 11.975 49.266 12.209 ;
     RECT  62.82 11.549 64.638 12.389 ;
     RECT  10.836 12.209 31.158 12.479 ;
     RECT  63.144 12.389 64.638 12.479 ;
     RECT  2.415 11.777 10.026 12.523 ;
     RECT  10.836 12.479 27.486 12.523 ;
     RECT  65.484 11.399 105.642 12.523 ;
     RECT  107.892 11.803 107.91 12.571 ;
     RECT  51.015 10.193 51.498 12.659 ;
     RECT  32.04 12.209 49.266 12.721 ;
     RECT  65.484 12.523 105.714 12.749 ;
     RECT  32.04 12.721 49.446 12.829 ;
     RECT  56.415 10.931 57.834 12.929 ;
     RECT  28.224 12.479 31.158 13.027 ;
     RECT  32.04 12.829 49.554 13.027 ;
     RECT  107.856 12.571 107.91 13.085 ;
     RECT  28.224 13.027 49.554 13.163 ;
     RECT  106.596 12.523 106.614 13.181 ;
     RECT  51.015 12.659 51.297 13.243 ;
     RECT  57.816 12.929 57.834 13.325 ;
     RECT  2.415 12.523 27.486 13.333 ;
     RECT  28.224 13.163 49.23 13.333 ;
     RECT  2.415 13.333 49.23 13.361 ;
     RECT  65.484 12.749 105.606 13.483 ;
     RECT  50.904 13.243 51.297 13.565 ;
     RECT  107.892 13.085 107.91 13.739 ;
     RECT  58.968 10.625 58.986 13.901 ;
     RECT  51.015 13.565 51.297 13.915 ;
     RECT  2.415 13.361 23.094 13.937 ;
     RECT  65.484 13.483 105.714 13.937 ;
     RECT  23.976 13.361 49.23 13.945 ;
     RECT  65.484 13.937 65.502 13.981 ;
     RECT  63.792 12.479 64.638 14.059 ;
     RECT  63.216 14.059 64.638 14.071 ;
     RECT  65.412 13.981 65.502 14.071 ;
     RECT  23.976 13.945 49.554 14.099 ;
     RECT  63.216 14.071 65.502 14.135 ;
     RECT  12.456 13.937 23.094 14.251 ;
     RECT  23.976 14.099 49.266 14.251 ;
     RECT  51.015 13.915 52.002 14.251 ;
     RECT  51.015 14.251 52.29 14.381 ;
     RECT  12.456 14.251 49.266 14.405 ;
     RECT  66.564 13.937 105.714 14.539 ;
     RECT  51.015 14.381 52.002 14.639 ;
     RECT  63.936 14.135 65.502 14.639 ;
     RECT  31.896 14.405 49.266 14.675 ;
     RECT  66.564 14.539 106.038 14.779 ;
     RECT  107.136 14.299 107.154 14.779 ;
     RECT  66.564 14.779 107.154 14.783 ;
     RECT  12.456 14.405 31.122 14.791 ;
     RECT  64.44 14.639 65.502 14.909 ;
     RECT  12.42 14.791 31.122 14.953 ;
     RECT  2.415 13.937 11.358 14.989 ;
     RECT  12.348 14.953 31.122 14.989 ;
     RECT  48.888 14.675 49.266 14.989 ;
     RECT  31.896 14.675 47.898 15.017 ;
     RECT  64.98 14.909 64.998 15.053 ;
     RECT  48.888 14.989 49.338 15.061 ;
     RECT  2.415 14.989 31.122 15.223 ;
     RECT  31.896 15.017 47.034 15.223 ;
     RECT  106.524 14.783 107.154 15.251 ;
     RECT  106.524 15.251 106.578 15.521 ;
     RECT  48.888 15.061 49.41 15.601 ;
     RECT  50.184 15.061 50.202 15.601 ;
     RECT  2.415 15.223 47.034 15.763 ;
     RECT  2.415 15.763 47.07 15.799 ;
     RECT  47.88 15.017 47.898 15.799 ;
     RECT  106.56 15.521 106.578 15.821 ;
     RECT  48.888 15.601 50.202 15.871 ;
     RECT  51.015 14.639 51.297 15.871 ;
     RECT  2.415 15.799 47.898 15.979 ;
     RECT  2.415 15.979 48.042 16.105 ;
     RECT  48.888 15.871 51.297 16.105 ;
     RECT  107.892 16.555 107.91 16.685 ;
     RECT  107.136 16.123 107.154 16.795 ;
     RECT  107.1 16.795 107.154 16.915 ;
     RECT  66.564 14.783 105.714 17.275 ;
     RECT  106.596 16.915 107.154 17.275 ;
     RECT  2.415 16.105 51.297 17.375 ;
     RECT  66.564 17.275 107.154 17.483 ;
     RECT  3.888 17.375 51.297 17.645 ;
     RECT  3.888 17.645 49.77 17.654 ;
     RECT  3.888 17.654 49.734 17.789 ;
     RECT  66.564 17.483 105.714 18.023 ;
     RECT  3.888 17.789 49.41 18.029 ;
     RECT  66.564 18.023 70.902 18.059 ;
     RECT  71.64 18.023 105.714 18.149 ;
     RECT  3.888 18.029 48.006 18.229 ;
     RECT  3.744 18.229 48.006 18.301 ;
     RECT  3.492 18.301 48.006 18.455 ;
     RECT  48.78 18.029 49.41 18.527 ;
     RECT  48.996 18.527 49.41 18.535 ;
     RECT  106.56 17.483 107.154 18.599 ;
     RECT  3.492 18.455 47.97 18.725 ;
     RECT  71.64 18.149 105.642 18.725 ;
     RECT  3.492 18.725 25.218 18.805 ;
     RECT  107.136 18.599 107.154 19.031 ;
     RECT  2.415 17.375 2.697 19.111 ;
     RECT  3.456 18.805 25.218 19.111 ;
     RECT  72 18.725 105.642 19.111 ;
     RECT  26.028 18.725 47.97 19.201 ;
     RECT  2.415 19.111 25.218 19.277 ;
     RECT  72 19.111 105.714 19.373 ;
     RECT  26.028 19.201 48.078 19.381 ;
     RECT  48.996 18.535 49.842 19.381 ;
     RECT  26.028 19.381 49.842 19.579 ;
     RECT  12.492 19.277 25.218 19.651 ;
     RECT  26.028 19.579 50.202 19.651 ;
     RECT  12.492 19.651 50.202 19.769 ;
     RECT  107.892 19.291 107.91 19.771 ;
     RECT  12.492 19.769 49.95 19.811 ;
     RECT  12.492 19.811 49.59 19.913 ;
     RECT  70.884 18.059 70.902 19.949 ;
     RECT  2.415 19.277 11.718 20.083 ;
     RECT  12.492 19.913 49.41 20.083 ;
     RECT  106.56 20.011 106.578 20.203 ;
     RECT  107.856 19.771 107.91 20.203 ;
     RECT  2.415 20.083 49.41 20.345 ;
     RECT  106.56 20.203 107.91 20.381 ;
     RECT  106.56 20.381 106.578 21.191 ;
     RECT  2.415 20.345 49.338 21.199 ;
     RECT  2.415 21.199 49.554 21.245 ;
     RECT  2.415 21.245 49.446 21.299 ;
     RECT  72 19.373 105.534 21.355 ;
     RECT  107.82 20.381 107.91 21.803 ;
     RECT  107.82 21.803 107.838 21.811 ;
     RECT  2.415 21.299 49.338 22.081 ;
     RECT  2.415 22.081 49.95 22.235 ;
     RECT  72 21.355 106.038 22.469 ;
     RECT  77.04 22.469 106.038 22.504 ;
     RECT  107.172 21.811 107.838 22.504 ;
     RECT  77.04 22.504 107.838 22.541 ;
     RECT  107.1 22.541 107.838 22.613 ;
     RECT  2.415 22.235 49.446 23.089 ;
     RECT  77.04 22.541 106.002 23.117 ;
     RECT  2.415 23.089 49.806 23.279 ;
     RECT  66.564 18.059 70.11 23.279 ;
     RECT  2.415 23.279 38.214 23.315 ;
     RECT  39.204 23.279 49.662 23.315 ;
     RECT  3.528 23.315 38.214 23.405 ;
     RECT  72 22.469 76.302 23.515 ;
     RECT  77.04 23.117 105.642 23.515 ;
     RECT  39.204 23.315 49.626 23.549 ;
     RECT  3.528 23.405 24.297 23.585 ;
     RECT  39.204 23.549 49.446 23.585 ;
     RECT  107.892 23.419 107.91 23.597 ;
     RECT  3.708 23.585 24.297 23.621 ;
     RECT  3.78 23.621 24.297 23.693 ;
     RECT  39.204 23.585 48.798 23.819 ;
     RECT  39.204 23.819 48.69 23.855 ;
     RECT  66.564 23.279 67.497 23.999 ;
     RECT  4.752 23.693 24.297 24.089 ;
     RECT  25.056 23.405 38.214 24.089 ;
     RECT  107.1 22.613 107.154 24.161 ;
     RECT  68.76 23.279 70.11 24.205 ;
     RECT  70.92 23.971 70.938 24.205 ;
     RECT  68.76 24.205 70.938 24.233 ;
     RECT  107.136 24.161 107.154 24.233 ;
     RECT  5.364 24.089 24.297 24.241 ;
     RECT  25.056 24.089 37.782 24.241 ;
     RECT  67.215 23.999 67.497 24.241 ;
     RECT  39.204 23.855 48.438 24.367 ;
     RECT  38.988 24.367 48.438 24.395 ;
     RECT  38.988 24.395 46.71 24.403 ;
     RECT  72 23.515 105.642 24.431 ;
     RECT  47.736 24.395 48.438 24.467 ;
     RECT  5.364 24.241 37.782 24.665 ;
     RECT  6.264 24.665 37.782 24.899 ;
     RECT  47.88 24.467 48.438 24.899 ;
     RECT  47.88 24.899 48.366 24.935 ;
     RECT  5.364 24.665 5.382 25.079 ;
     RECT  6.732 24.899 37.782 25.141 ;
     RECT  38.664 24.403 46.71 25.141 ;
     RECT  6.732 25.141 46.71 25.169 ;
     RECT  107.136 25.003 107.154 25.241 ;
     RECT  68.76 24.233 70.65 25.285 ;
     RECT  72 24.431 105.606 25.291 ;
     RECT  6.876 25.169 46.71 25.313 ;
     RECT  72 25.291 105.714 25.313 ;
     RECT  68.76 25.285 70.83 25.349 ;
     RECT  47.88 24.935 48.33 25.435 ;
     RECT  107.892 24.331 107.91 25.435 ;
     RECT  69.336 25.349 70.83 25.439 ;
     RECT  72.108 25.313 105.714 25.439 ;
     RECT  7.2 25.313 46.71 25.447 ;
     RECT  47.664 25.435 48.33 25.447 ;
     RECT  7.2 25.447 48.33 25.619 ;
     RECT  106.488 25.243 106.542 25.675 ;
     RECT  7.596 25.619 48.33 25.709 ;
     RECT  69.336 25.439 69.426 25.709 ;
     RECT  7.596 25.709 48.078 25.817 ;
     RECT  30.42 25.817 48.078 25.853 ;
     RECT  107.856 25.435 107.91 25.853 ;
     RECT  72.108 25.439 105.606 25.979 ;
     RECT  107.892 25.853 107.91 26.045 ;
     RECT  72.108 25.979 105.462 26.051 ;
     RECT  106.38 25.675 106.542 26.051 ;
     RECT  30.42 25.853 47.718 26.087 ;
     RECT  70.272 25.439 70.29 26.087 ;
     RECT  7.596 25.817 29.697 26.159 ;
     RECT  30.42 26.087 46.638 26.159 ;
     RECT  47.7 26.087 47.718 26.159 ;
     RECT  72.108 26.051 74.754 26.203 ;
     RECT  7.596 26.159 24.297 26.249 ;
     RECT  25.344 26.159 29.697 26.249 ;
     RECT  71.532 26.203 74.754 26.285 ;
     RECT  7.596 26.249 14.202 26.291 ;
     RECT  106.488 26.051 106.542 26.347 ;
     RECT  106.488 26.347 107.154 26.393 ;
     RECT  30.42 26.159 46.53 26.429 ;
     RECT  106.488 26.393 106.542 26.429 ;
     RECT  26.496 26.249 29.697 26.519 ;
     RECT  30.42 26.429 44.802 26.519 ;
     RECT  71.784 26.285 74.754 26.519 ;
     RECT  26.532 26.519 29.697 26.555 ;
     RECT  27.972 26.555 29.697 26.627 ;
     RECT  44.676 26.519 44.802 26.627 ;
     RECT  45.615 26.429 46.53 26.627 ;
     RECT  25.344 26.249 25.758 26.663 ;
     RECT  26.532 26.555 26.802 26.663 ;
     RECT  28.116 26.627 29.697 26.663 ;
     RECT  28.26 26.663 29.697 26.671 ;
     RECT  30.42 26.519 30.438 26.671 ;
     RECT  67.215 24.241 67.914 26.699 ;
     RECT  74.664 26.519 74.754 26.699 ;
     RECT  75.672 26.051 105.462 26.779 ;
     RECT  7.815 26.291 14.202 26.789 ;
     RECT  28.26 26.671 30.438 26.789 ;
     RECT  31.212 26.519 43.902 26.789 ;
     RECT  44.676 26.627 44.694 26.789 ;
     RECT  71.784 26.519 73.782 26.789 ;
     RECT  31.212 26.789 43.65 26.861 ;
     RECT  75.312 26.779 105.462 26.905 ;
     RECT  31.284 26.861 43.65 26.969 ;
     RECT  9.36 26.789 14.202 27.059 ;
     RECT  28.26 26.789 30.33 27.059 ;
     RECT  31.284 26.969 43.182 27.059 ;
     RECT  72.615 26.789 73.782 27.059 ;
     RECT  9.396 27.059 14.202 27.067 ;
     RECT  15.192 26.249 24.297 27.067 ;
     RECT  9.396 27.067 24.297 27.095 ;
     RECT  33.912 27.059 43.038 27.167 ;
     RECT  9.396 27.095 22.374 27.203 ;
     RECT  31.284 27.059 32.526 27.203 ;
     RECT  75.312 26.905 105.534 27.259 ;
     RECT  106.524 26.429 106.542 27.259 ;
     RECT  9.396 27.203 9.558 27.329 ;
     RECT  15.444 27.203 22.374 27.329 ;
     RECT  31.284 27.203 31.482 27.329 ;
     RECT  32.256 27.203 32.526 27.329 ;
     RECT  38.268 27.167 42.966 27.329 ;
     RECT  9.396 27.329 9.414 27.341 ;
     RECT  17.784 27.329 22.374 27.341 ;
     RECT  28.26 27.059 30.186 27.341 ;
     RECT  32.328 27.329 32.526 27.341 ;
     RECT  75.312 27.259 106.542 27.341 ;
     RECT  10.296 27.203 14.706 27.365 ;
     RECT  17.784 27.341 21.654 27.365 ;
     RECT  31.284 27.329 31.302 27.365 ;
     RECT  38.268 27.329 41.418 27.365 ;
     RECT  17.856 27.365 19.674 27.401 ;
     RECT  71.784 26.789 71.802 27.437 ;
     RECT  11.052 27.365 14.706 27.599 ;
     RECT  32.328 27.341 32.346 27.599 ;
     RECT  33.912 27.167 37.35 27.599 ;
     RECT  75.312 27.341 76.086 27.607 ;
     RECT  72.615 27.059 73.638 27.635 ;
     RECT  11.052 27.599 11.754 27.707 ;
     RECT  34.56 27.599 37.35 27.707 ;
     RECT  42.156 27.329 42.966 27.707 ;
     RECT  75.096 27.607 76.086 27.751 ;
     RECT  11.592 27.707 11.754 27.869 ;
     RECT  12.528 27.599 14.706 27.869 ;
     RECT  34.56 27.707 35.334 27.869 ;
     RECT  11.592 27.869 11.61 27.905 ;
     RECT  12.888 27.869 14.238 27.905 ;
     RECT  76.968 27.341 106.542 27.941 ;
     RECT  69.408 25.709 69.426 28.211 ;
     RECT  74.412 27.751 76.086 28.291 ;
     RECT  76.968 27.941 106.038 28.291 ;
     RECT  74.412 28.291 106.038 28.409 ;
     RECT  74.412 28.409 79.578 28.445 ;
     RECT  74.412 28.445 79.398 28.679 ;
     RECT  74.736 28.679 79.398 28.751 ;
     RECT  76.68 28.751 79.398 28.949 ;
     RECT  74.736 28.751 75.51 28.985 ;
     RECT  75.492 28.985 75.51 29.021 ;
     RECT  74.736 28.985 74.754 29.057 ;
     RECT  80.82 28.409 106.038 29.083 ;
     RECT  107.136 28.171 107.154 29.083 ;
     RECT  72.615 27.635 73.17 29.093 ;
     RECT  80.82 29.083 107.154 29.129 ;
     RECT  80.856 29.129 107.154 29.327 ;
     RECT  81.252 29.327 107.154 29.831 ;
     RECT  82.332 29.831 107.154 29.903 ;
     RECT  77.364 28.949 79.398 30.029 ;
     RECT  82.332 29.903 105.714 30.407 ;
     RECT  82.332 30.407 82.494 30.479 ;
     RECT  83.304 30.407 105.714 30.713 ;
     RECT  106.524 29.903 107.154 30.715 ;
     RECT  15.444 27.329 16.758 30.721 ;
     RECT  78.015 30.029 79.398 30.749 ;
     RECT  82.404 30.479 82.494 30.749 ;
     RECT  36.216 27.707 37.35 30.811 ;
     RECT  78.015 30.749 79.326 30.839 ;
     RECT  83.304 30.713 105.606 31.019 ;
     RECT  36.216 30.811 37.998 31.109 ;
     RECT  81.252 29.831 81.378 31.109 ;
     RECT  106.488 30.715 107.154 31.181 ;
     RECT  82.476 30.749 82.494 31.217 ;
     RECT  36.216 31.109 37.35 31.225 ;
     RECT  81.36 31.109 81.378 31.225 ;
     RECT  81.36 31.225 81.522 31.253 ;
     RECT  78.015 30.839 78.858 31.379 ;
     RECT  36.144 31.225 37.35 31.469 ;
     RECT  83.376 31.019 105.606 31.487 ;
     RECT  84.42 31.487 105.606 31.627 ;
     RECT  84.42 31.627 106.038 31.757 ;
     RECT  106.02 31.757 106.038 32.299 ;
     RECT  107.136 31.181 107.154 32.299 ;
     RECT  106.02 32.299 107.154 32.333 ;
     RECT  84.42 31.757 105.297 32.731 ;
     RECT  84.42 32.731 105.714 32.873 ;
     RECT  106.56 32.333 107.154 33.211 ;
     RECT  106.524 33.211 107.154 33.611 ;
     RECT  84.42 32.873 105.426 33.643 ;
     RECT  106.524 33.611 106.614 33.643 ;
     RECT  83.415 31.487 83.697 33.961 ;
     RECT  84.42 33.643 106.614 33.961 ;
     RECT  83.415 33.961 106.614 34.493 ;
     RECT  106.524 34.493 106.614 34.691 ;
     RECT  107.136 34.795 107.154 35.303 ;
     RECT  83.415 34.493 105.534 35.309 ;
     RECT  84.42 35.309 105.534 35.311 ;
     RECT  84.42 35.311 105.642 35.467 ;
     RECT  84.42 35.467 106.038 36.379 ;
     RECT  84.42 36.379 106.074 36.619 ;
     RECT  107.136 36.139 107.154 36.619 ;
     RECT  83.415 35.309 83.697 36.661 ;
     RECT  84.42 36.619 107.154 36.661 ;
     RECT  83.415 36.661 107.154 36.851 ;
     RECT  80.712 37.165 80.73 37.319 ;
     RECT  81.504 31.253 81.522 37.319 ;
     RECT  83.415 36.851 106.038 37.463 ;
     RECT  83.415 37.463 105.714 37.579 ;
     RECT  80.568 37.471 80.586 37.613 ;
     RECT  107.136 36.851 107.154 37.625 ;
     RECT  82.8 37.579 105.714 37.859 ;
     RECT  91.656 37.859 105.714 37.931 ;
     RECT  91.656 37.931 92.502 37.967 ;
     RECT  93.384 37.931 105.714 38.003 ;
     RECT  82.8 37.859 90.918 38.137 ;
     RECT  78.015 31.379 78.297 38.245 ;
     RECT  93.384 38.003 105.642 38.309 ;
     RECT  91.656 37.967 92.43 38.399 ;
     RECT  79.992 37.963 80.01 38.435 ;
     RECT  93.564 38.309 105.642 38.435 ;
     RECT  106.524 37.771 106.542 38.443 ;
     RECT  78.015 38.245 78.426 38.477 ;
     RECT  93.708 38.435 105.642 38.543 ;
     RECT  82.764 38.137 90.918 38.705 ;
     RECT  83.124 38.705 90.918 38.785 ;
     RECT  91.656 38.399 91.674 38.785 ;
     RECT  106.524 38.443 106.578 38.875 ;
     RECT  92.412 38.399 92.43 38.911 ;
     RECT  83.124 38.785 91.674 39.209 ;
     RECT  106.524 38.875 107.154 39.281 ;
     RECT  84.564 39.209 91.674 39.317 ;
     RECT  93.708 38.543 105.426 39.355 ;
     RECT  93.708 39.355 105.606 39.587 ;
     RECT  92.412 38.911 92.682 39.631 ;
     RECT  93.708 39.587 105.354 39.631 ;
     RECT  84.78 39.317 91.674 39.677 ;
     RECT  107.892 39.787 107.91 40.127 ;
     RECT  83.415 39.209 83.697 40.135 ;
     RECT  84.78 39.677 85.266 40.135 ;
     RECT  86.112 39.677 91.674 40.289 ;
     RECT  92.412 39.631 105.354 40.333 ;
     RECT  86.652 40.289 91.674 40.433 ;
     RECT  92.412 40.333 105.426 40.433 ;
     RECT  86.832 40.433 91.674 40.441 ;
     RECT  92.412 40.433 105.297 40.441 ;
     RECT  107.136 39.281 107.154 40.507 ;
     RECT  54.288 40.459 54.306 40.559 ;
     RECT  53.964 40.639 53.982 40.685 ;
     RECT  106.56 40.507 107.154 40.699 ;
     RECT  83.415 40.135 85.266 40.711 ;
     RECT  86.832 40.441 105.297 40.739 ;
     RECT  106.524 40.699 107.154 41.179 ;
     RECT  83.415 40.711 85.878 41.251 ;
     RECT  83.415 41.251 85.986 41.371 ;
     RECT  106.02 41.179 107.154 41.441 ;
     RECT  87.084 40.739 105.297 41.521 ;
     RECT  106.02 41.441 106.542 41.521 ;
     RECT  83.415 41.371 86.346 41.549 ;
     RECT  83.415 41.549 84.222 41.747 ;
     RECT  87.084 41.521 106.542 41.909 ;
     RECT  84.996 41.549 86.346 41.945 ;
     RECT  85.5 41.945 86.346 42.025 ;
     RECT  87.084 41.909 89.334 42.025 ;
     RECT  90.648 41.909 106.542 42.053 ;
     RECT  85.5 42.025 89.334 42.215 ;
     RECT  90.648 42.053 105.57 42.215 ;
     RECT  106.524 42.053 106.542 42.251 ;
     RECT  85.5 42.215 85.518 42.449 ;
     RECT  86.328 42.215 89.334 42.835 ;
     RECT  86.328 42.835 89.55 42.899 ;
     RECT  92.844 42.215 105.57 43.003 ;
     RECT  90.648 42.215 91.998 43.033 ;
     RECT  92.844 43.003 105.966 43.061 ;
     RECT  90.648 43.033 92.07 43.069 ;
     RECT  90.648 43.069 92.106 43.097 ;
     RECT  107.136 42.523 107.154 43.133 ;
     RECT  91.188 43.097 92.106 43.231 ;
     RECT  92.844 43.061 105.534 43.231 ;
     RECT  87.264 42.899 89.55 43.277 ;
     RECT  91.188 43.231 105.534 43.325 ;
     RECT  107.892 43.195 107.91 43.331 ;
     RECT  87.408 43.277 89.55 43.609 ;
     RECT  91.224 43.325 105.534 43.835 ;
     RECT  91.296 43.835 105.534 43.843 ;
     RECT  106.524 43.435 106.542 43.843 ;
     RECT  87.408 43.609 90.162 44.069 ;
     RECT  91.296 43.843 106.542 44.093 ;
     RECT  95.364 44.093 106.542 44.104 ;
     RECT  87.408 44.069 90.09 44.105 ;
     RECT  95.364 44.104 106.578 44.141 ;
     RECT  95.364 44.141 106.074 44.249 ;
     RECT  87.552 44.105 89.586 44.339 ;
     RECT  91.296 44.093 94.497 44.339 ;
     RECT  92.16 44.339 94.497 44.477 ;
     RECT  88.092 44.339 89.097 44.609 ;
     RECT  92.268 44.477 94.497 44.609 ;
     RECT  92.268 44.609 92.718 44.645 ;
     RECT  91.296 44.339 91.314 44.717 ;
     RECT  92.268 44.645 92.502 44.717 ;
     RECT  92.268 44.717 92.466 44.879 ;
     RECT  92.268 44.879 92.358 44.915 ;
     RECT  92.268 44.915 92.286 44.987 ;
     RECT  95.436 44.249 106.074 45.019 ;
     RECT  95.436 45.019 106.542 45.419 ;
     RECT  106.02 45.419 106.542 45.563 ;
     RECT  94.032 44.609 94.497 45.571 ;
     RECT  95.436 45.419 105.297 45.571 ;
     RECT  94.032 45.571 105.297 45.689 ;
     RECT  106.092 45.563 106.542 45.833 ;
     RECT  94.215 45.689 105.297 45.869 ;
     RECT  34.815 27.869 35.097 45.925 ;
     RECT  23.292 27.095 24.297 45.931 ;
     RECT  34.704 45.925 35.097 45.965 ;
     RECT  34.776 45.965 35.097 46.013 ;
     RECT  106.524 45.833 106.542 46.031 ;
     RECT  22.5 45.931 24.297 46.061 ;
     RECT  22.5 46.061 22.518 46.253 ;
     RECT  107.892 45.931 107.91 46.337 ;
     RECT  107.136 46.171 107.154 46.642 ;
     RECT  95.436 45.869 105.297 46.651 ;
     RECT  95.436 46.651 105.354 46.741 ;
     RECT  95.436 46.741 105.534 46.843 ;
     RECT  107.136 46.642 107.19 46.913 ;
     RECT  95.436 46.843 106.038 47.083 ;
     RECT  94.215 45.869 94.497 47.272 ;
     RECT  36.216 31.469 37.35 47.275 ;
     RECT  95.436 47.083 106.11 47.323 ;
     RECT  36.216 47.275 37.458 47.461 ;
     RECT  94.215 47.272 94.626 47.461 ;
     RECT  95.436 47.323 106.578 47.461 ;
     RECT  36.216 47.461 37.782 47.501 ;
     RECT  36.216 47.501 37.458 47.579 ;
     RECT  94.215 47.461 106.578 47.899 ;
     RECT  93.888 47.899 106.578 48.155 ;
     RECT  94.032 48.155 106.578 48.235 ;
     RECT  94.032 48.235 107.154 48.389 ;
     RECT  94.215 48.389 107.154 48.461 ;
     RECT  20.952 27.365 21.654 48.901 ;
     RECT  20.952 48.901 21.726 49.037 ;
     RECT  94.215 48.461 107.118 49.037 ;
     RECT  95.256 49.037 107.118 49.235 ;
     RECT  96.048 49.235 107.118 49.339 ;
     RECT  95.256 49.235 95.274 49.469 ;
     RECT  96.048 49.339 107.154 49.541 ;
     RECT  20.952 49.037 21.654 49.883 ;
     RECT  96.048 49.541 106.614 50.093 ;
     RECT  96.048 50.093 106.542 50.351 ;
     RECT  96.048 50.351 105.714 50.389 ;
     RECT  95.724 50.389 105.714 50.429 ;
     RECT  96.264 50.429 105.714 50.459 ;
     RECT  96.264 50.459 105.534 50.549 ;
     RECT  39.564 27.365 41.418 50.731 ;
     RECT  106.524 50.351 106.542 51.161 ;
     RECT  39.168 50.731 41.418 51.293 ;
     RECT  96.516 50.549 105.534 51.403 ;
     RECT  94.215 49.037 94.497 51.643 ;
     RECT  94.215 51.643 95.094 51.821 ;
     RECT  96.516 51.403 106.038 51.883 ;
     RECT  107.136 51.163 107.154 51.883 ;
     RECT  96.516 51.883 107.154 52.313 ;
     RECT  96.516 52.313 106.614 52.459 ;
     RECT  96.156 52.459 106.614 53.021 ;
     RECT  96.156 53.021 106.578 53.309 ;
     RECT  96.516 53.309 106.578 53.555 ;
     RECT  97.884 53.555 106.578 53.591 ;
     RECT  97.884 53.591 106.542 53.597 ;
     RECT  98.352 53.597 106.542 53.789 ;
     RECT  96.516 53.555 97.146 54.329 ;
     RECT  98.532 53.789 106.542 54.473 ;
     RECT  106.488 54.473 106.542 54.671 ;
     RECT  98.532 54.473 105.714 54.707 ;
     RECT  106.524 54.671 106.542 54.811 ;
     RECT  96.516 54.329 97.074 54.841 ;
     RECT  96.48 54.841 97.074 55.111 ;
     RECT  96.372 55.111 97.074 55.243 ;
     RECT  96.372 55.243 97.686 55.445 ;
     RECT  98.532 54.707 105.642 55.469 ;
     RECT  106.524 54.811 107.154 55.481 ;
     RECT  98.532 55.469 98.55 55.679 ;
     RECT  96.516 55.445 97.686 55.831 ;
     RECT  99.288 55.469 105.642 55.831 ;
     RECT  96.516 55.831 98.37 56.129 ;
     RECT  99.288 55.831 105.714 56.203 ;
     RECT  99.288 56.203 106.038 56.363 ;
     RECT  99.288 56.363 105.534 56.371 ;
     RECT  97.344 56.129 98.37 56.443 ;
     RECT  99.144 56.371 105.534 56.443 ;
     RECT  97.344 56.443 105.534 56.531 ;
     RECT  97.488 56.531 105.534 56.759 ;
     RECT  97.812 56.759 105.534 57.029 ;
     RECT  99.615 57.029 105.534 57.115 ;
     RECT  97.812 57.029 98.442 57.137 ;
     RECT  98.424 57.137 98.442 57.407 ;
     RECT  107.892 56.635 107.91 57.983 ;
     RECT  98.784 57.883 98.802 57.991 ;
     RECT  99.615 57.115 106.038 57.991 ;
     RECT  98.784 57.991 106.218 58.157 ;
     RECT  99.216 58.157 106.218 58.459 ;
     RECT  107.136 55.481 107.154 58.459 ;
     RECT  99.216 58.459 107.154 58.721 ;
     RECT  99.216 58.721 106.218 59.189 ;
     RECT  15.408 30.721 16.758 59.297 ;
     RECT  99.216 59.189 101.034 59.341 ;
     RECT  101.808 59.189 106.218 59.611 ;
     RECT  107.136 58.721 107.154 59.611 ;
     RECT  78.015 38.477 78.297 59.701 ;
     RECT  98.964 59.341 101.034 59.729 ;
     RECT  77.58 59.701 78.297 59.789 ;
     RECT  101.808 59.611 107.154 59.801 ;
     RECT  96.516 56.129 96.534 59.845 ;
     RECT  99.432 59.729 101.034 59.971 ;
     RECT  101.808 59.801 106.542 59.971 ;
     RECT  15.444 59.297 16.758 60.151 ;
     RECT  96.516 59.845 96.93 60.179 ;
     RECT  99.432 59.971 106.542 60.179 ;
     RECT  99.615 60.179 106.542 60.269 ;
     RECT  80.172 60.241 80.478 60.365 ;
     RECT  99.615 60.269 100.998 60.365 ;
     RECT  80.46 60.365 80.478 60.413 ;
     RECT  101.772 60.269 106.542 60.575 ;
     RECT  18.288 27.401 19.674 60.619 ;
     RECT  18.288 60.619 19.818 60.719 ;
     RECT  101.952 60.575 106.542 60.809 ;
     RECT  101.952 60.809 105.297 60.881 ;
     RECT  106.02 60.809 106.542 60.953 ;
     RECT  36.216 47.579 37.35 61.051 ;
     RECT  99.615 60.365 99.897 61.123 ;
     RECT  99.615 61.123 99.99 61.159 ;
     RECT  99.432 61.159 99.99 61.259 ;
     RECT  106.524 60.953 106.542 61.435 ;
     RECT  10.296 27.365 10.314 61.591 ;
     RECT  96.516 60.179 96.534 61.591 ;
     RECT  10.26 61.591 10.314 61.619 ;
     RECT  15.444 60.151 16.794 61.619 ;
     RECT  96.516 61.591 96.93 61.627 ;
     RECT  102.384 60.881 105.297 61.627 ;
     RECT  15.48 61.619 16.794 61.655 ;
     RECT  106.524 61.435 107.154 61.675 ;
     RECT  100.98 60.365 100.998 61.699 ;
     RECT  101.988 61.627 105.297 61.699 ;
     RECT  96.516 61.627 97.002 61.799 ;
     RECT  99.615 61.259 99.99 61.867 ;
     RECT  100.98 61.699 105.297 61.889 ;
     RECT  100.98 61.889 101.502 61.901 ;
     RECT  106.02 61.675 107.154 62.033 ;
     RECT  28.26 27.341 29.697 62.041 ;
     RECT  106.056 62.033 107.154 62.231 ;
     RECT  106.056 62.231 106.074 62.303 ;
     RECT  99.615 61.867 100.026 62.473 ;
     RECT  18.288 60.719 19.746 62.545 ;
     RECT  99.615 62.473 100.17 62.545 ;
     RECT  107.136 62.231 107.154 62.587 ;
     RECT  101.484 61.901 101.502 62.635 ;
     RECT  18.216 62.545 19.746 62.699 ;
     RECT  80.064 62.539 80.082 62.699 ;
     RECT  99.615 62.545 100.242 62.699 ;
     RECT  102.384 61.889 105.297 62.699 ;
     RECT  99.615 62.699 100.026 62.765 ;
     RECT  103.104 62.699 105.297 62.941 ;
     RECT  85.464 62.731 85.482 62.969 ;
     RECT  98.748 62.731 98.766 63.005 ;
     RECT  99.615 62.765 99.897 63.067 ;
     RECT  101.484 62.635 101.574 63.067 ;
     RECT  98.892 63.067 99.897 63.113 ;
     RECT  103.104 62.941 106.038 63.113 ;
     RECT  18.324 62.699 19.746 63.149 ;
     RECT  80.928 62.671 80.946 63.149 ;
     RECT  101.484 63.067 101.898 63.149 ;
     RECT  86.868 62.743 86.886 63.197 ;
     RECT  101.772 63.149 101.898 63.275 ;
     RECT  107.136 62.587 107.19 63.293 ;
     RECT  103.104 63.113 105.426 63.451 ;
     RECT  107.136 63.293 107.154 63.581 ;
     RECT  19.62 63.149 19.746 63.751 ;
     RECT  20.952 49.883 21.186 63.931 ;
     RECT  99.615 63.113 99.897 64.021 ;
     RECT  20.88 63.931 21.186 64.049 ;
     RECT  102.024 63.451 105.426 64.049 ;
     RECT  100.908 63.895 100.926 64.129 ;
     RECT  20.952 64.049 21.186 64.201 ;
     RECT  106.524 63.691 106.578 64.229 ;
     RECT  20.952 64.201 21.906 64.319 ;
     RECT  100.908 64.129 100.962 64.327 ;
     RECT  106.524 64.229 106.542 64.411 ;
     RECT  25.344 26.663 25.362 64.435 ;
     RECT  99.615 64.021 99.954 64.435 ;
     RECT  99.615 64.435 100.134 64.471 ;
     RECT  100.908 64.327 101.106 64.471 ;
     RECT  25.344 64.435 25.578 64.589 ;
     RECT  102.024 64.049 105.297 64.597 ;
     RECT  39.564 51.293 41.418 64.705 ;
     RECT  23.292 46.061 24.297 64.741 ;
     RECT  25.344 64.589 25.362 64.741 ;
     RECT  23.184 64.741 24.297 64.769 ;
     RECT  25.2 64.741 25.362 64.769 ;
     RECT  39.348 64.705 41.418 64.769 ;
     RECT  101.88 64.597 105.297 64.843 ;
     RECT  106.02 64.411 106.542 64.843 ;
     RECT  99.615 64.471 101.106 64.867 ;
     RECT  101.88 64.843 106.542 64.895 ;
     RECT  99.18 64.867 101.106 64.973 ;
     RECT  99.615 64.973 101.106 65.173 ;
     RECT  102.024 64.895 106.542 65.201 ;
     RECT  42.516 27.707 42.966 65.237 ;
     RECT  42.516 65.237 42.786 65.281 ;
     RECT  102.024 65.201 105.297 65.399 ;
     RECT  99.615 65.173 101.25 65.435 ;
     RECT  106.524 65.201 106.542 65.471 ;
     RECT  98.604 65.281 98.622 65.507 ;
     RECT  42.192 65.281 42.786 65.579 ;
     RECT  38.268 65.551 38.286 65.641 ;
     RECT  39.348 64.769 39.366 65.641 ;
     RECT  38.268 65.641 39.366 65.741 ;
     RECT  100.908 65.435 101.25 65.803 ;
     RECT  18.324 63.149 18.897 65.939 ;
     RECT  38.268 65.741 38.358 65.939 ;
     RECT  38.16 65.947 38.178 65.984 ;
     RECT  15.66 61.655 16.794 66.091 ;
     RECT  102.528 65.399 105.297 66.187 ;
     RECT  107.1 65.515 107.154 66.281 ;
     RECT  100.908 65.803 101.754 66.325 ;
     RECT  102.528 66.187 105.714 66.325 ;
     RECT  15.66 66.091 17.478 66.361 ;
     RECT  99.615 65.435 99.897 66.475 ;
     RECT  100.908 66.325 105.714 66.475 ;
     RECT  99.615 66.475 105.714 66.515 ;
     RECT  36.216 61.051 37.386 66.595 ;
     RECT  39.096 65.741 39.366 66.623 ;
     RECT  100.908 66.515 105.714 66.623 ;
     RECT  36.216 66.595 37.674 66.721 ;
     RECT  94.215 51.821 94.497 66.757 ;
     RECT  106.56 66.427 106.578 66.892 ;
     RECT  15.66 66.361 17.622 66.901 ;
     RECT  18.615 65.939 18.897 66.901 ;
     RECT  36.216 66.721 37.71 66.901 ;
     RECT  94.212 66.757 94.497 66.901 ;
     RECT  97.992 66.757 98.01 66.929 ;
     RECT  96.516 61.799 96.534 67.019 ;
     RECT  94.212 66.901 94.914 67.055 ;
     RECT  106.524 66.892 106.578 67.091 ;
     RECT  15.66 66.901 18.897 67.171 ;
     RECT  19.62 63.751 19.782 67.171 ;
     RECT  99.615 66.515 99.897 67.261 ;
     RECT  36.216 66.901 38.25 67.289 ;
     RECT  42.192 65.579 42.21 67.289 ;
     RECT  36.684 67.289 38.25 67.297 ;
     RECT  94.212 67.055 94.662 67.325 ;
     RECT  40.215 64.769 41.418 67.361 ;
     RECT  94.212 67.325 94.497 67.369 ;
     RECT  15.66 67.171 20.142 67.405 ;
     RECT  107.064 67.099 107.154 67.405 ;
     RECT  36.684 67.297 38.286 67.441 ;
     RECT  39.348 66.623 39.366 67.441 ;
     RECT  40.215 67.361 40.698 67.441 ;
     RECT  99.54 67.261 99.897 67.441 ;
     RECT  100.908 66.623 105.297 67.441 ;
     RECT  15.66 67.405 20.214 67.559 ;
     RECT  99.504 67.441 99.897 67.567 ;
     RECT  15.66 67.559 20.142 67.595 ;
     RECT  107.064 67.405 107.262 67.631 ;
     RECT  107.1 67.631 107.262 67.667 ;
     RECT  99.432 67.567 99.897 67.711 ;
     RECT  100.872 67.441 105.297 67.711 ;
     RECT  99.432 67.711 105.714 67.819 ;
     RECT  95.4 67.441 95.418 67.829 ;
     RECT  32.904 67.441 32.922 67.945 ;
     RECT  96.192 67.135 96.21 67.981 ;
     RECT  36.684 67.441 40.698 68.011 ;
     RECT  20.952 64.319 21.582 68.059 ;
     RECT  22.392 67.981 22.41 68.059 ;
     RECT  92.88 67.819 92.898 68.099 ;
     RECT  95.94 67.981 96.21 68.107 ;
     RECT  97.056 67.945 97.074 68.107 ;
     RECT  95.94 68.107 97.074 68.179 ;
     RECT  99.432 67.819 106.038 68.243 ;
     RECT  98.028 67.801 98.046 68.245 ;
     RECT  33.66 67.981 33.678 68.251 ;
     RECT  93.996 67.369 94.497 68.251 ;
     RECT  98.028 68.245 98.514 68.251 ;
     RECT  99.432 68.243 105.534 68.251 ;
     RECT  95.94 68.179 97.11 68.285 ;
     RECT  98.028 68.251 105.534 68.285 ;
     RECT  107.172 67.667 107.262 68.285 ;
     RECT  20.952 68.059 22.41 68.341 ;
     RECT  23.184 64.769 23.202 68.341 ;
     RECT  24.015 64.769 24.297 68.341 ;
     RECT  15.66 67.595 20.106 68.369 ;
     RECT  96.048 68.285 97.11 68.369 ;
     RECT  98.64 68.285 105.534 68.369 ;
     RECT  93.672 68.251 94.497 68.377 ;
     RECT  32.76 67.945 32.922 68.395 ;
     RECT  33.66 68.251 33.822 68.395 ;
     RECT  96.048 68.369 97.038 68.405 ;
     RECT  32.76 68.395 33.822 68.429 ;
     RECT  34.815 46.013 35.097 68.521 ;
     RECT  88.815 44.609 89.097 68.521 ;
     RECT  90.648 68.341 90.666 68.521 ;
     RECT  93.528 68.377 94.497 68.521 ;
     RECT  28.188 62.041 29.697 68.549 ;
     RECT  16.776 68.369 20.106 68.635 ;
     RECT  20.952 68.341 24.297 68.635 ;
     RECT  26.604 68.521 26.622 68.639 ;
     RECT  93.528 68.521 94.698 68.639 ;
     RECT  96.048 68.405 96.894 68.639 ;
     RECT  16.776 68.635 24.297 68.669 ;
     RECT  16.776 68.669 20.718 68.675 ;
     RECT  107.136 68.491 107.154 68.731 ;
     RECT  7.815 26.789 8.097 68.755 ;
     RECT  88.308 68.521 89.097 68.755 ;
     RECT  90.432 68.521 90.666 68.755 ;
     RECT  7.488 68.755 8.097 68.791 ;
     RECT  8.82 68.521 8.838 68.791 ;
     RECT  21.672 68.669 24.297 68.791 ;
     RECT  36.108 68.011 40.698 68.791 ;
     RECT  17.604 68.675 20.574 68.909 ;
     RECT  33.336 68.429 33.822 68.909 ;
     RECT  34.815 68.521 35.19 68.923 ;
     RECT  33.336 68.909 33.354 68.945 ;
     RECT  34.56 68.923 35.19 68.953 ;
     RECT  35.964 68.791 40.698 68.953 ;
     RECT  17.676 68.909 20.574 68.981 ;
     RECT  34.56 68.953 40.698 69.061 ;
     RECT  96.192 68.639 96.894 69.151 ;
     RECT  97.884 68.875 97.902 69.151 ;
     RECT  96.192 69.151 97.902 69.179 ;
     RECT  7.488 68.791 8.838 69.187 ;
     RECT  10.26 61.619 10.278 69.187 ;
     RECT  28.764 68.549 29.697 69.223 ;
     RECT  98.64 68.369 105.462 69.223 ;
     RECT  106.524 68.731 107.154 69.223 ;
     RECT  34.308 69.061 40.698 69.251 ;
     RECT  26.28 68.791 26.298 69.295 ;
     RECT  87.228 68.881 87.246 69.295 ;
     RECT  34.815 69.251 40.698 69.323 ;
     RECT  98.64 69.223 107.154 69.323 ;
     RECT  21.672 68.791 24.354 69.331 ;
     RECT  25.2 64.769 25.218 69.331 ;
     RECT  26.1 69.295 26.298 69.331 ;
     RECT  28.764 69.223 30.078 69.331 ;
     RECT  88.308 68.755 90.666 69.331 ;
     RECT  98.64 69.323 107.118 69.331 ;
     RECT  15.66 68.369 15.822 69.359 ;
     RECT  93.528 68.639 94.662 69.359 ;
     RECT  21.672 69.331 25.218 69.421 ;
     RECT  25.992 69.331 26.298 69.421 ;
     RECT  93.996 69.359 94.662 69.421 ;
     RECT  18 68.981 20.574 69.449 ;
     RECT  31.428 69.151 31.446 69.449 ;
     RECT  91.728 69.259 91.746 69.449 ;
     RECT  88.164 69.331 90.666 69.485 ;
     RECT  21.672 69.421 26.298 69.499 ;
     RECT  32.724 69.151 32.742 69.521 ;
     RECT  93.996 69.421 94.698 69.521 ;
     RECT  98.604 69.331 107.118 69.521 ;
     RECT  87.228 69.295 87.282 69.529 ;
     RECT  11.088 69.529 11.106 69.565 ;
     RECT  96.192 69.179 97.686 69.565 ;
     RECT  6.84 69.187 8.838 69.601 ;
     RECT  9.9 69.187 10.278 69.601 ;
     RECT  11.016 69.565 11.106 69.601 ;
     RECT  14.328 69.529 14.346 69.601 ;
     RECT  18.108 69.449 20.574 69.601 ;
     RECT  27.072 69.331 27.09 69.601 ;
     RECT  28.764 69.331 30.654 69.601 ;
     RECT  94.104 69.521 94.698 69.601 ;
     RECT  14.22 69.601 14.346 69.629 ;
     RECT  16.776 68.675 16.794 69.629 ;
     RECT  36.54 69.323 40.698 69.719 ;
     RECT  79.308 69.601 79.326 69.719 ;
     RECT  94.104 69.601 94.77 69.719 ;
     RECT  13.215 27.905 13.497 69.727 ;
     RECT  28.764 69.601 30.798 69.755 ;
     RECT  36.54 69.719 40.662 69.863 ;
     RECT  6.48 69.601 11.106 69.871 ;
     RECT  13.212 69.727 13.497 69.871 ;
     RECT  14.22 69.629 14.274 69.871 ;
     RECT  21.636 69.499 26.298 69.871 ;
     RECT  27.036 69.601 27.09 69.871 ;
     RECT  93.096 69.421 93.258 69.871 ;
     RECT  95.904 69.565 97.686 69.871 ;
     RECT  5.832 69.871 11.106 69.917 ;
     RECT  79.164 69.871 79.182 69.917 ;
     RECT  21.636 69.871 27.162 69.989 ;
     RECT  95.544 69.871 97.686 69.989 ;
     RECT  92.484 69.871 93.258 69.997 ;
     RECT  21.636 69.989 27.054 70.025 ;
     RECT  88.164 69.485 90.486 70.025 ;
     RECT  13.212 69.871 14.274 70.069 ;
     RECT  38.808 69.863 40.662 70.097 ;
     RECT  98.604 69.521 106.578 70.105 ;
     RECT  98.532 70.105 106.578 70.109 ;
     RECT  15.696 69.359 15.822 70.141 ;
     RECT  86.724 69.529 87.282 70.141 ;
     RECT  88.164 70.025 89.097 70.141 ;
     RECT  95.76 69.989 97.686 70.141 ;
     RECT  98.532 70.109 105.642 70.141 ;
     RECT  18.108 69.601 20.646 70.157 ;
     RECT  19.728 70.157 20.646 70.169 ;
     RECT  95.76 70.141 105.642 70.169 ;
     RECT  34.815 69.323 35.586 70.231 ;
     RECT  92.016 69.997 93.258 70.231 ;
     RECT  12.42 70.069 14.274 70.259 ;
     RECT  36.54 69.863 37.782 70.259 ;
     RECT  85.464 69.961 85.482 70.267 ;
     RECT  92.016 70.231 93.294 70.267 ;
     RECT  94.104 69.719 94.662 70.267 ;
     RECT  12.42 70.259 14.13 70.295 ;
     RECT  19.944 70.169 20.646 70.295 ;
     RECT  95.904 70.169 105.642 70.295 ;
     RECT  6.336 69.917 11.106 70.303 ;
     RECT  12.42 70.295 14.022 70.303 ;
     RECT  34.776 70.231 35.586 70.303 ;
     RECT  91.26 69.871 91.278 70.303 ;
     RECT  92.016 70.267 94.662 70.303 ;
     RECT  106.56 70.109 106.578 70.315 ;
     RECT  38.952 70.097 40.662 70.331 ;
     RECT  15.696 70.141 15.93 70.367 ;
     RECT  34.092 70.303 35.586 70.375 ;
     RECT  36.54 70.259 36.558 70.375 ;
     RECT  89.964 70.025 90.486 70.375 ;
     RECT  91.26 70.303 94.662 70.375 ;
     RECT  19.98 70.295 20.646 70.411 ;
     RECT  21.636 70.025 26.91 70.411 ;
     RECT  85.356 70.267 85.626 70.411 ;
     RECT  86.652 70.141 89.097 70.411 ;
     RECT  19.98 70.411 26.91 70.529 ;
     RECT  96.12 70.295 105.642 70.529 ;
     RECT  28.764 69.755 30.762 70.565 ;
     RECT  98.172 70.529 105.606 70.565 ;
     RECT  82.008 70.411 82.026 70.573 ;
     RECT  15.84 70.367 15.93 70.609 ;
     RECT  106.56 70.315 106.722 70.673 ;
     RECT  5.112 70.363 5.13 70.681 ;
     RECT  28.764 70.565 29.898 70.681 ;
     RECT  33.192 70.411 33.21 70.681 ;
     RECT  81.468 70.573 82.026 70.681 ;
     RECT  89.964 70.375 94.662 70.681 ;
     RECT  6.336 70.303 14.022 70.685 ;
     RECT  18.108 70.157 18.897 70.771 ;
     RECT  5.112 70.681 5.202 70.795 ;
     RECT  6.336 70.685 9.882 70.795 ;
     RECT  10.836 70.685 14.022 70.799 ;
     RECT  79.956 69.871 79.974 70.807 ;
     RECT  30.96 70.645 30.978 70.835 ;
     RECT  81.468 70.681 82.134 70.835 ;
     RECT  10.872 70.799 14.022 70.871 ;
     RECT  79.848 70.807 79.974 70.879 ;
     RECT  37.296 70.259 37.782 70.915 ;
     RECT  38.952 70.331 40.497 70.915 ;
     RECT  78.015 59.789 78.297 70.915 ;
     RECT  79.848 70.879 80.154 70.915 ;
     RECT  83.415 41.747 83.697 70.915 ;
     RECT  76.176 70.681 76.194 70.951 ;
     RECT  79.812 70.915 80.154 70.951 ;
     RECT  79.56 70.951 80.154 70.979 ;
     RECT  76.032 70.951 76.554 71.021 ;
     RECT  34.092 70.375 36.558 71.041 ;
     RECT  37.296 70.915 40.497 71.041 ;
     RECT  85.356 70.411 89.097 71.041 ;
     RECT  89.964 70.681 94.842 71.041 ;
     RECT  15.84 70.609 16.038 71.069 ;
     RECT  83.415 70.915 84.042 71.069 ;
     RECT  85.356 71.041 94.842 71.069 ;
     RECT  19.98 70.529 21.474 71.105 ;
     RECT  76.536 71.021 76.554 71.105 ;
     RECT  96.12 70.529 97.146 71.113 ;
     RECT  15.84 71.069 16.002 71.177 ;
     RECT  28.62 70.681 29.898 71.185 ;
     RECT  33.156 70.681 33.21 71.185 ;
     RECT  78.015 70.915 78.786 71.185 ;
     RECT  79.56 70.979 79.902 71.185 ;
     RECT  34.092 71.041 40.497 71.213 ;
     RECT  11.304 70.871 14.022 71.221 ;
     RECT  15.012 70.951 15.03 71.221 ;
     RECT  22.212 70.529 26.91 71.221 ;
     RECT  28.224 71.185 29.898 71.221 ;
     RECT  32.76 71.185 33.21 71.221 ;
     RECT  34.092 71.213 39.042 71.221 ;
     RECT  81.468 70.835 81.486 71.221 ;
     RECT  32.76 71.221 39.042 71.249 ;
     RECT  85.356 71.069 90.918 71.249 ;
     RECT  91.872 71.069 94.842 71.249 ;
     RECT  78.015 71.185 79.902 71.261 ;
     RECT  85.464 71.249 90.918 71.261 ;
     RECT  78.015 71.261 78.297 71.311 ;
     RECT  82.26 71.221 82.278 71.311 ;
     RECT  83.415 71.069 83.697 71.311 ;
     RECT  98.532 70.565 105.606 71.311 ;
     RECT  20.952 71.105 21.474 71.339 ;
     RECT  107.892 69.835 107.91 71.339 ;
     RECT  98.316 71.311 105.606 71.347 ;
     RECT  76.68 71.221 76.698 71.375 ;
     RECT  11.304 71.221 15.03 71.383 ;
     RECT  15.84 71.177 15.858 71.383 ;
     RECT  32.76 71.249 38.538 71.411 ;
     RECT  91.872 71.249 91.89 71.411 ;
     RECT  33.696 71.411 38.538 71.483 ;
     RECT  4.572 70.795 9.882 71.491 ;
     RECT  21.168 71.339 21.474 71.491 ;
     RECT  22.212 71.221 29.898 71.491 ;
     RECT  93.024 71.249 94.842 71.491 ;
     RECT  95.868 71.113 97.146 71.491 ;
     RECT  98.208 71.347 105.606 71.491 ;
     RECT  93.024 71.491 97.47 71.563 ;
     RECT  98.208 71.491 105.678 71.563 ;
     RECT  93.024 71.563 105.678 71.609 ;
     RECT  19.98 71.105 19.998 71.645 ;
     RECT  21.168 71.491 30.582 71.645 ;
     RECT  31.428 71.311 31.446 71.659 ;
     RECT  106.56 70.673 106.614 71.659 ;
     RECT  17.604 70.771 18.897 71.725 ;
     RECT  11.304 71.383 15.858 71.753 ;
     RECT  31.428 71.659 32.022 71.761 ;
     RECT  79.272 71.261 79.902 71.761 ;
     RECT  81.324 71.221 81.486 71.761 ;
     RECT  82.26 71.311 83.697 71.761 ;
     RECT  98.28 71.609 105.678 71.761 ;
     RECT  11.304 71.753 13.734 71.803 ;
     RECT  31.428 71.761 32.49 71.837 ;
     RECT  79.272 71.761 80.046 71.851 ;
     RECT  81.324 71.761 83.697 71.851 ;
     RECT  11.016 71.803 13.734 71.879 ;
     RECT  21.312 71.645 30.582 71.879 ;
     RECT  85.572 71.261 90.918 71.887 ;
     RECT  31.428 71.837 31.446 71.915 ;
     RECT  34.092 71.483 38.538 71.915 ;
     RECT  14.472 71.753 15.858 71.951 ;
     RECT  32.472 71.837 32.49 71.951 ;
     RECT  34.092 71.915 36.738 71.951 ;
     RECT  35.892 71.951 36.738 71.987 ;
     RECT  79.272 71.851 83.697 71.995 ;
     RECT  40.176 71.213 40.497 72.023 ;
     RECT  4.104 71.491 10.098 72.031 ;
     RECT  37.584 71.915 38.538 72.031 ;
     RECT  67.215 26.699 67.497 72.031 ;
     RECT  75.384 71.311 75.402 72.031 ;
     RECT  77.508 71.311 78.297 72.031 ;
     RECT  79.236 71.995 83.697 72.031 ;
     RECT  93.024 71.609 97.506 72.031 ;
     RECT  4.104 72.031 10.206 72.059 ;
     RECT  76.572 72.031 76.59 72.121 ;
     RECT  85.572 71.887 90.99 72.121 ;
     RECT  77.508 72.031 84.258 72.139 ;
     RECT  98.28 71.761 105.714 72.139 ;
     RECT  106.524 71.659 106.614 72.139 ;
     RECT  21.312 71.879 30.078 72.149 ;
     RECT  4.284 72.059 10.206 72.185 ;
     RECT  11.772 71.879 13.734 72.185 ;
     RECT  72.615 29.093 72.897 72.193 ;
     RECT  74.664 72.031 75.402 72.229 ;
     RECT  76.5 72.121 76.59 72.229 ;
     RECT  92.556 72.031 97.506 72.229 ;
     RECT  77.508 72.139 84.33 72.265 ;
     RECT  98.28 72.139 106.614 72.265 ;
     RECT  67.215 72.031 67.554 72.301 ;
     RECT  85.248 72.121 90.99 72.301 ;
     RECT  92.34 72.229 97.506 72.301 ;
     RECT  4.284 72.185 10.062 72.317 ;
     RECT  34.092 71.951 35.154 72.391 ;
     RECT  70.596 72.031 70.686 72.391 ;
     RECT  74.664 72.229 76.59 72.391 ;
     RECT  77.364 72.265 84.33 72.391 ;
     RECT  85.176 72.301 97.506 72.391 ;
     RECT  98.28 72.265 107.19 72.391 ;
     RECT  70.056 72.391 70.686 72.427 ;
     RECT  72.615 72.193 73.494 72.427 ;
     RECT  74.664 72.391 84.33 72.427 ;
     RECT  30.852 72.301 30.87 72.491 ;
     RECT  67.215 72.301 68.994 72.499 ;
     RECT  61.815 11.549 62.097 72.535 ;
     RECT  12.528 72.185 13.734 72.571 ;
     RECT  14.472 71.951 15.606 72.571 ;
     RECT  17.1 71.725 18.897 72.571 ;
     RECT  37.584 72.031 38.682 72.571 ;
     RECT  63.144 72.427 63.27 72.571 ;
     RECT  67.215 72.499 69.066 72.571 ;
     RECT  70.056 72.427 70.758 72.571 ;
     RECT  12.528 72.571 15.606 72.599 ;
     RECT  67.215 72.571 70.938 72.599 ;
     RECT  36.036 71.987 36.306 72.689 ;
     RECT  21.312 72.149 29.79 72.725 ;
     RECT  33.48 72.391 35.154 72.725 ;
     RECT  37.584 72.571 38.97 72.725 ;
     RECT  69.336 72.599 70.938 72.733 ;
     RECT  61.815 72.535 62.154 72.749 ;
     RECT  67.215 72.599 68.562 72.763 ;
     RECT  38.952 72.725 38.97 72.797 ;
     RECT  16.776 72.571 18.897 72.805 ;
     RECT  19.944 71.761 19.962 72.805 ;
     RECT  16.776 72.805 19.962 72.841 ;
     RECT  72.615 72.427 84.33 72.841 ;
     RECT  85.176 72.391 107.19 72.841 ;
     RECT  16.776 72.841 20.142 72.869 ;
     RECT  16.776 72.869 19.386 72.907 ;
     RECT  11.772 72.185 11.79 72.931 ;
     RECT  12.528 72.599 15.426 72.931 ;
     RECT  69.336 72.733 71.082 72.931 ;
     RECT  72.615 72.841 107.19 72.931 ;
     RECT  67.14 72.763 68.562 72.955 ;
     RECT  16.632 72.907 19.386 72.959 ;
     RECT  25.056 72.725 29.79 72.959 ;
     RECT  21.528 72.725 24.297 72.995 ;
     RECT  69.336 72.931 107.19 73.003 ;
     RECT  9.036 72.317 10.062 73.075 ;
     RECT  11.772 72.931 15.426 73.075 ;
     RECT  4.284 72.317 8.154 73.111 ;
     RECT  9 73.075 10.062 73.111 ;
     RECT  27.936 72.959 29.79 73.111 ;
     RECT  63.036 72.571 63.27 73.111 ;
     RECT  11.7 73.075 15.426 73.133 ;
     RECT  20.124 72.869 20.142 73.201 ;
     RECT  16.848 72.959 19.386 73.265 ;
     RECT  62.928 73.111 63.27 73.273 ;
     RECT  22.212 72.995 24.297 73.301 ;
     RECT  62.856 73.273 63.27 73.345 ;
     RECT  66.78 72.955 68.562 73.345 ;
     RECT  4.248 73.111 10.278 73.373 ;
     RECT  4.248 73.373 9.99 73.381 ;
     RECT  12.42 73.133 15.426 73.381 ;
     RECT  20.124 73.201 20.25 73.381 ;
     RECT  27.936 73.111 29.934 73.471 ;
     RECT  61.815 72.749 62.097 73.471 ;
     RECT  62.856 73.345 63.558 73.471 ;
     RECT  66.168 73.345 68.562 73.483 ;
     RECT  4.104 73.381 9.99 73.499 ;
     RECT  25.056 72.959 27.126 73.499 ;
     RECT  61.815 73.471 63.558 73.499 ;
     RECT  36.036 72.689 36.054 73.507 ;
     RECT  66.024 73.483 68.562 73.507 ;
     RECT  69.336 73.003 107.262 73.507 ;
     RECT  4.104 73.499 9.882 73.535 ;
     RECT  33.48 72.725 35.097 73.535 ;
     RECT  16.992 73.265 17.262 73.571 ;
     RECT  20.124 73.381 20.394 73.571 ;
     RECT  18.072 73.265 19.386 73.651 ;
     RECT  37.584 72.725 37.602 73.651 ;
     RECT  56.415 12.929 56.697 73.651 ;
     RECT  66.024 73.507 107.262 73.741 ;
     RECT  4.104 73.535 9.306 73.769 ;
     RECT  36.036 73.507 36.486 73.805 ;
     RECT  59.544 73.651 59.562 73.813 ;
     RECT  64.404 72.769 64.422 73.813 ;
     RECT  65.628 73.741 107.262 73.813 ;
     RECT  61.815 73.499 63.342 73.849 ;
     RECT  12.42 73.381 15.498 73.885 ;
     RECT  55.908 73.651 56.697 73.885 ;
     RECT  58.068 73.273 58.086 73.885 ;
     RECT  64.404 73.813 64.458 73.885 ;
     RECT  12.348 73.885 15.498 73.921 ;
     RECT  25.2 73.499 27.126 73.921 ;
     RECT  27.936 73.471 30.51 73.921 ;
     RECT  34.74 73.535 35.097 73.921 ;
     RECT  57.924 73.885 58.086 73.921 ;
     RECT  59.436 73.813 59.562 73.921 ;
     RECT  64.224 73.885 64.458 73.921 ;
     RECT  25.2 73.921 30.51 73.997 ;
     RECT  65.268 73.813 107.262 73.997 ;
     RECT  36.468 73.805 36.486 74.011 ;
     RECT  4.104 73.769 9.198 74.039 ;
     RECT  22.32 73.301 24.297 74.047 ;
     RECT  61.416 73.849 63.342 74.059 ;
     RECT  4.824 74.039 8.298 74.075 ;
     RECT  18.072 73.651 20.106 74.075 ;
     RECT  58.932 73.921 59.562 74.075 ;
     RECT  18.072 74.075 18.99 74.083 ;
     RECT  57.708 73.921 58.086 74.083 ;
     RECT  25.2 73.997 29.697 74.093 ;
     RECT  17.892 74.083 18.99 74.111 ;
     RECT  65.268 73.997 107.082 74.111 ;
     RECT  55.296 73.885 56.697 74.119 ;
     RECT  64.224 73.921 64.53 74.155 ;
     RECT  65.268 74.111 106.65 74.155 ;
     RECT  57.636 74.083 58.086 74.219 ;
     RECT  16.992 73.571 17.118 74.251 ;
     RECT  59.94 74.155 59.958 74.281 ;
     RECT  12.348 73.921 16.146 74.309 ;
     RECT  16.956 74.251 17.118 74.309 ;
     RECT  59.94 74.281 60.03 74.309 ;
     RECT  19.728 74.075 20.106 74.345 ;
     RECT  9.18 74.039 9.198 74.381 ;
     RECT  17.892 74.111 18.954 74.381 ;
     RECT  60.984 74.059 63.342 74.389 ;
     RECT  64.224 74.155 106.65 74.389 ;
     RECT  60.984 74.389 106.65 74.417 ;
     RECT  57.924 74.219 58.086 74.425 ;
     RECT  25.2 74.093 28.494 74.453 ;
     RECT  60.984 74.417 65.826 74.453 ;
     RECT  12.348 74.309 14.382 74.461 ;
     RECT  17.1 74.309 17.118 74.461 ;
     RECT  17.892 74.381 18.897 74.461 ;
     RECT  25.2 74.453 28.458 74.461 ;
     RECT  15.444 74.309 16.146 74.489 ;
     RECT  25.02 74.461 28.458 74.489 ;
     RECT  37.584 73.651 37.674 74.539 ;
     RECT  36.468 74.011 36.666 74.551 ;
     RECT  37.584 74.539 37.854 74.551 ;
     RECT  3.636 74.461 3.762 74.579 ;
     RECT  36.468 74.551 36.774 74.587 ;
     RECT  37.584 74.551 38.79 74.587 ;
     RECT  4.824 74.075 6.282 74.615 ;
     RECT  7.56 74.075 8.298 74.615 ;
     RECT  17.1 74.461 18.897 74.615 ;
     RECT  29.232 74.093 29.697 74.615 ;
     RECT  36.468 74.587 38.79 74.621 ;
     RECT  11.376 74.107 11.394 74.623 ;
     RECT  36.468 74.621 37.926 74.623 ;
     RECT  10.836 74.623 11.394 74.651 ;
     RECT  25.02 74.489 27.882 74.651 ;
     RECT  36.252 74.623 37.926 74.669 ;
     RECT  38.772 74.621 38.79 74.669 ;
     RECT  52.452 74.587 52.47 74.695 ;
     RECT  52.092 74.695 52.47 74.731 ;
     RECT  3.744 74.579 3.762 74.821 ;
     RECT  4.824 74.615 6.174 74.821 ;
     RECT  48.744 74.047 48.762 74.821 ;
     RECT  60.012 74.309 60.03 74.821 ;
     RECT  25.02 74.651 27.09 74.849 ;
     RECT  36.648 74.669 37.926 74.849 ;
     RECT  36.648 74.849 37.242 74.885 ;
     RECT  66.564 74.417 106.65 74.909 ;
     RECT  42.768 74.857 42.786 74.929 ;
     RECT  44.172 74.857 44.19 74.929 ;
     RECT  51.015 17.645 51.297 74.929 ;
     RECT  55.116 74.119 56.697 74.929 ;
     RECT  48.744 74.821 48.87 74.957 ;
     RECT  40.215 72.023 40.497 74.965 ;
     RECT  54.72 74.929 56.697 74.965 ;
     RECT  57.924 74.425 58.914 74.965 ;
     RECT  21.708 74.047 24.297 75.001 ;
     RECT  34.74 73.921 35.406 75.001 ;
     RECT  44.1 74.929 44.19 75.001 ;
     RECT  50.76 74.929 51.297 75.001 ;
     RECT  25.02 74.849 26.946 75.005 ;
     RECT  48.744 74.957 48.834 75.091 ;
     RECT  3.744 74.821 6.174 75.119 ;
     RECT  25.02 75.005 26.73 75.119 ;
     RECT  60.012 74.821 60.174 75.119 ;
     RECT  61.38 74.453 65.826 75.119 ;
     RECT  44.028 75.001 44.19 75.127 ;
     RECT  27.864 74.651 27.882 75.155 ;
     RECT  29.304 74.615 29.697 75.155 ;
     RECT  33.48 73.535 33.498 75.155 ;
     RECT  60.012 75.119 60.03 75.155 ;
     RECT  48.06 75.091 48.834 75.163 ;
     RECT  106.524 74.909 106.65 75.163 ;
     RECT  54.72 74.965 58.914 75.191 ;
     RECT  56.34 75.191 58.914 75.199 ;
     RECT  3.744 75.119 5.778 75.227 ;
     RECT  64.008 75.119 65.826 75.227 ;
     RECT  52.092 74.731 53.19 75.235 ;
     RECT  54.72 75.191 55.386 75.235 ;
     RECT  64.656 75.227 65.826 75.235 ;
     RECT  66.564 74.909 105.678 75.235 ;
     RECT  40.215 74.965 40.986 75.271 ;
     RECT  43.884 75.127 44.19 75.271 ;
     RECT  50.724 75.001 51.297 75.271 ;
     RECT  106.524 75.163 107.19 75.341 ;
     RECT  34.416 75.001 35.406 75.361 ;
     RECT  21.42 75.001 24.297 75.389 ;
     RECT  56.34 75.199 58.95 75.389 ;
     RECT  26.28 75.119 26.73 75.425 ;
     RECT  43.884 75.271 44.55 75.425 ;
     RECT  49.824 75.271 49.842 75.433 ;
     RECT  37.224 74.885 37.242 75.461 ;
     RECT  52.092 75.235 53.586 75.461 ;
     RECT  16.128 74.489 16.146 75.469 ;
     RECT  42.66 74.929 42.858 75.469 ;
     RECT  43.884 75.425 44.334 75.469 ;
     RECT  45.615 26.627 45.897 75.469 ;
     RECT  46.8 75.271 46.818 75.469 ;
     RECT  9.252 75.259 9.27 75.482 ;
     RECT  21.744 75.389 24.297 75.497 ;
     RECT  26.28 75.425 26.514 75.497 ;
     RECT  42.66 75.469 44.334 75.505 ;
     RECT  53.028 75.461 53.586 75.505 ;
     RECT  7.632 74.615 8.298 75.541 ;
     RECT  9.252 75.482 9.918 75.541 ;
     RECT  10.836 74.651 10.854 75.541 ;
     RECT  34.416 75.361 35.766 75.541 ;
     RECT  53.028 75.505 53.91 75.541 ;
     RECT  54.684 75.235 55.386 75.541 ;
     RECT  16.128 75.469 16.182 75.631 ;
     RECT  45.615 75.469 46.818 75.631 ;
     RECT  9.252 75.541 10.854 75.659 ;
     RECT  50.652 75.271 51.297 75.659 ;
     RECT  16.128 75.631 16.218 75.695 ;
     RECT  19.728 74.345 19.746 75.695 ;
     RECT  26.352 75.497 26.514 75.695 ;
     RECT  28.008 75.271 28.026 75.695 ;
     RECT  53.028 75.541 55.386 75.695 ;
     RECT  56.415 75.389 58.95 75.739 ;
     RECT  106.524 75.341 107.154 75.739 ;
     RECT  42.588 75.505 44.334 75.767 ;
     RECT  53.028 75.695 54.81 75.767 ;
     RECT  40.215 75.271 41.706 75.775 ;
     RECT  42.588 75.767 43.65 75.775 ;
     RECT  45.615 75.631 46.854 75.787 ;
     RECT  52.092 75.461 52.218 75.803 ;
     RECT  16.164 75.695 16.218 75.811 ;
     RECT  45.288 75.787 46.854 75.811 ;
     RECT  48.024 75.163 48.834 75.811 ;
     RECT  49.716 75.433 49.842 75.811 ;
     RECT  50.724 75.659 51.297 75.811 ;
     RECT  40.215 75.775 43.65 75.821 ;
     RECT  9.864 75.659 10.71 75.839 ;
     RECT  61.596 75.119 63.054 75.901 ;
     RECT  16.164 75.811 16.254 75.929 ;
     RECT  45.288 75.811 49.842 75.929 ;
     RECT  7.416 75.541 8.298 75.965 ;
     RECT  16.164 75.929 16.218 75.965 ;
     RECT  45.288 75.929 49.734 75.965 ;
     RECT  61.596 75.901 63.09 76.058 ;
     RECT  3.744 75.227 5.202 76.081 ;
     RECT  12.312 74.461 14.382 76.081 ;
     RECT  17.784 74.615 18.897 76.081 ;
     RECT  34.416 75.541 35.946 76.081 ;
     RECT  106.452 75.739 107.154 76.081 ;
     RECT  39.384 76.081 39.402 76.171 ;
     RECT  56.415 75.739 59.238 76.171 ;
     RECT  39.24 76.171 39.402 76.199 ;
     RECT  56.415 76.171 59.346 76.205 ;
     RECT  61.596 76.058 63.27 76.207 ;
     RECT  11.988 76.081 14.382 76.235 ;
     RECT  34.416 76.081 35.982 76.235 ;
     RECT  50.724 75.811 52.038 76.301 ;
     RECT  50.796 76.301 52.038 76.307 ;
     RECT  22.032 75.497 24.297 76.315 ;
     RECT  64.656 75.235 105.678 76.315 ;
     RECT  58.68 76.205 59.346 76.349 ;
     RECT  17.784 76.081 19.062 76.351 ;
     RECT  26.352 75.695 26.442 76.351 ;
     RECT  40.215 75.821 41.742 76.351 ;
     RECT  60.3 75.901 60.318 76.351 ;
     RECT  61.596 76.207 63.414 76.351 ;
     RECT  21.996 76.315 24.297 76.363 ;
     RECT  40.176 76.351 41.742 76.363 ;
     RECT  56.415 76.205 57.618 76.363 ;
     RECT  39.24 76.199 39.258 76.397 ;
     RECT  28.044 75.775 28.062 76.441 ;
     RECT  3.528 76.081 5.202 76.469 ;
     RECT  53.028 75.767 54.738 76.505 ;
     RECT  61.308 76.351 63.414 76.513 ;
     RECT  39.06 76.441 39.078 76.541 ;
     RECT  51.015 76.307 52.038 76.549 ;
     RECT  45.288 75.965 49.662 76.585 ;
     RECT  61.308 76.513 63.486 76.585 ;
     RECT  9.9 75.839 10.71 76.621 ;
     RECT  21.42 76.363 24.297 76.621 ;
     RECT  25.02 75.119 25.254 76.621 ;
     RECT  29.34 75.155 29.697 76.621 ;
     RECT  30.492 73.997 30.51 76.621 ;
     RECT  38.304 76.363 38.322 76.621 ;
     RECT  53.352 76.505 54.738 76.621 ;
     RECT  55.764 76.363 57.618 76.621 ;
     RECT  60.012 76.351 60.462 76.621 ;
     RECT  61.308 76.585 63.594 76.621 ;
     RECT  64.656 76.315 105.714 76.621 ;
     RECT  21.096 76.621 25.254 76.637 ;
     RECT  51.015 76.549 52.11 76.739 ;
     RECT  17.676 76.351 19.062 76.741 ;
     RECT  19.944 75.775 19.962 76.741 ;
     RECT  45.036 76.585 49.662 76.775 ;
     RECT  51.015 76.739 52.038 76.775 ;
     RECT  53.352 76.621 57.618 76.775 ;
     RECT  17.676 76.741 19.962 76.781 ;
     RECT  60.012 76.621 105.714 76.781 ;
     RECT  46.98 76.775 49.662 76.811 ;
     RECT  34.416 76.235 35.55 76.843 ;
     RECT  22.788 76.637 25.254 76.855 ;
     RECT  26.28 76.351 26.442 76.855 ;
     RECT  34.272 76.843 35.55 76.883 ;
     RECT  53.352 76.775 54.594 76.883 ;
     RECT  13.215 76.235 14.382 76.891 ;
     RECT  19.728 76.781 19.962 76.891 ;
     RECT  21.096 76.637 21.762 76.891 ;
     RECT  37.944 76.621 38.322 76.891 ;
     RECT  39.996 76.363 41.742 76.891 ;
     RECT  42.696 75.821 43.65 76.891 ;
     RECT  9.9 76.621 10.89 76.919 ;
     RECT  58.68 76.349 58.734 76.919 ;
     RECT  27.864 76.441 28.062 76.939 ;
     RECT  29.124 76.621 29.697 76.939 ;
     RECT  30.42 76.621 30.51 76.939 ;
     RECT  7.416 75.965 8.154 76.981 ;
     RECT  10.116 76.919 10.89 76.981 ;
     RECT  11.988 76.235 12.33 76.981 ;
     RECT  13.215 76.891 14.562 76.981 ;
     RECT  17.676 76.781 18.954 76.981 ;
     RECT  45.036 76.775 46.206 76.981 ;
     RECT  46.98 76.811 49.626 77.009 ;
     RECT  10.116 76.981 12.33 77.045 ;
     RECT  19.728 76.891 21.762 77.045 ;
     RECT  27.684 76.939 28.062 77.045 ;
     RECT  63 76.781 105.714 77.045 ;
     RECT  2.415 23.315 2.697 77.125 ;
     RECT  3.528 76.469 4.842 77.125 ;
     RECT  16.2 75.965 16.218 77.125 ;
     RECT  27.864 77.045 28.062 77.131 ;
     RECT  29.124 76.939 30.51 77.131 ;
     RECT  67.032 77.045 105.714 77.131 ;
     RECT  106.452 76.081 107.226 77.131 ;
     RECT  21.636 77.045 21.762 77.153 ;
     RECT  15.804 77.125 16.218 77.161 ;
     RECT  27.864 77.131 30.51 77.161 ;
     RECT  31.356 77.131 31.374 77.161 ;
     RECT  32.508 76.981 32.526 77.161 ;
     RECT  34.776 76.883 35.55 77.161 ;
     RECT  51.015 76.775 51.93 77.161 ;
     RECT  55.332 76.775 57.618 77.161 ;
     RECT  27.864 77.161 32.526 77.179 ;
     RECT  33.336 75.199 33.354 77.179 ;
     RECT  34.776 77.161 35.586 77.189 ;
     RECT  5.724 76.621 5.742 77.251 ;
     RECT  10.152 77.045 12.33 77.275 ;
     RECT  13.14 76.981 14.562 77.275 ;
     RECT  17.496 76.981 18.954 77.279 ;
     RECT  34.815 77.189 35.586 77.279 ;
     RECT  6.912 76.981 8.154 77.287 ;
     RECT  9.108 76.891 9.126 77.287 ;
     RECT  10.152 77.275 14.562 77.315 ;
     RECT  19.728 77.045 20.538 77.315 ;
     RECT  21.636 77.153 21.654 77.315 ;
     RECT  27.864 77.179 33.354 77.315 ;
     RECT  34.815 77.279 35.262 77.315 ;
     RECT  39.996 76.891 43.722 77.315 ;
     RECT  55.332 77.161 58.05 77.315 ;
     RECT  60.012 76.781 62.226 77.315 ;
     RECT  67.032 77.131 107.226 77.315 ;
     RECT  6.912 77.287 9.126 77.323 ;
     RECT  10.152 77.315 11.466 77.351 ;
     RECT  2.415 77.125 4.842 77.357 ;
     RECT  6.624 77.323 9.126 77.357 ;
     RECT  40.215 77.315 43.65 77.357 ;
     RECT  44.964 76.981 46.206 77.357 ;
     RECT  28.548 77.315 32.13 77.387 ;
     RECT  58.86 77.161 59.274 77.395 ;
     RECT  60.012 77.315 60.714 77.395 ;
     RECT  22.788 76.855 26.442 77.431 ;
     RECT  5.724 77.251 5.778 77.459 ;
     RECT  67.104 77.315 89.766 77.459 ;
     RECT  15.804 77.161 16.542 77.467 ;
     RECT  17.496 77.279 17.55 77.501 ;
     RECT  46.98 77.009 48.186 77.501 ;
     RECT  37.62 76.891 38.97 77.515 ;
     RECT  53.568 76.883 54.594 77.515 ;
     RECT  55.332 77.315 57.114 77.515 ;
     RECT  45.216 77.357 46.206 77.521 ;
     RECT  46.98 77.501 46.998 77.521 ;
     RECT  61.74 77.315 62.226 77.521 ;
     RECT  63 77.045 66.114 77.521 ;
     RECT  37.08 77.515 38.97 77.549 ;
     RECT  58.86 77.395 60.714 77.549 ;
     RECT  67.104 77.459 74.646 77.549 ;
     RECT  17.496 77.501 17.514 77.585 ;
     RECT  22.752 77.431 26.874 77.585 ;
     RECT  53.568 77.515 57.114 77.585 ;
     RECT  67.104 77.549 74.574 77.585 ;
     RECT  28.548 77.387 31.194 77.621 ;
     RECT  47.844 77.501 48.186 77.621 ;
     RECT  28.548 77.621 31.158 77.657 ;
     RECT  45.216 77.521 46.998 77.693 ;
     RECT  15.804 77.467 16.65 77.701 ;
     RECT  50.868 77.161 51.93 77.701 ;
     RECT  10.152 77.351 10.89 77.729 ;
     RECT  32.004 77.387 32.13 77.855 ;
     RECT  53.568 77.585 54.738 77.855 ;
     RECT  55.764 77.585 57.114 77.855 ;
     RECT  67.104 77.585 70.974 77.855 ;
     RECT  18.288 77.279 18.954 77.971 ;
     RECT  20.16 77.315 20.538 77.971 ;
     RECT  22.752 77.585 24.534 77.971 ;
     RECT  33.228 77.315 33.354 77.971 ;
     RECT  36.18 77.431 36.198 77.971 ;
     RECT  37.08 77.549 37.746 77.971 ;
     RECT  49.104 77.009 49.626 77.971 ;
     RECT  50.724 77.701 51.966 77.971 ;
     RECT  53.568 77.855 53.586 77.971 ;
     RECT  5.76 77.459 5.778 78.061 ;
     RECT  6.624 77.357 8.154 78.061 ;
     RECT  9.252 77.431 9.27 78.061 ;
     RECT  10.152 77.729 10.17 78.061 ;
     RECT  15.804 77.701 17.154 78.061 ;
     RECT  25.38 77.585 26.874 78.061 ;
     RECT  38.52 77.549 38.97 78.061 ;
     RECT  61.74 77.521 66.114 78.061 ;
     RECT  67.104 77.855 68.994 78.061 ;
     RECT  1.62 77.971 1.638 78.077 ;
     RECT  2.415 77.357 4.806 78.089 ;
     RECT  15.408 78.061 17.154 78.089 ;
     RECT  61.56 78.061 68.994 78.089 ;
     RECT  69.768 77.855 70.974 78.089 ;
     RECT  12.24 77.315 14.562 78.097 ;
     RECT  15.408 78.089 16.758 78.097 ;
     RECT  75.528 77.459 89.766 78.097 ;
     RECT  90.504 77.315 107.226 78.097 ;
     RECT  60.444 77.549 60.714 78.161 ;
     RECT  3.6 78.089 4.806 78.205 ;
     RECT  5.76 78.061 8.154 78.205 ;
     RECT  58.032 77.315 58.05 78.205 ;
     RECT  58.86 77.549 59.562 78.205 ;
     RECT  3.6 78.205 8.154 78.241 ;
     RECT  9.252 78.061 10.17 78.241 ;
     RECT  12.24 78.097 16.758 78.241 ;
     RECT  32.112 77.855 32.13 78.241 ;
     RECT  33.228 77.971 33.39 78.241 ;
     RECT  34.815 77.315 35.226 78.241 ;
     RECT  36.18 77.971 37.746 78.241 ;
     RECT  38.52 78.061 39.294 78.241 ;
     RECT  40.215 77.357 42.894 78.241 ;
     RECT  43.632 77.357 43.65 78.241 ;
     RECT  45.216 77.693 46.494 78.241 ;
     RECT  55.8 77.855 57.114 78.241 ;
     RECT  58.032 78.205 59.562 78.241 ;
     RECT  34.815 78.241 37.746 78.331 ;
     RECT  38.52 78.241 39.33 78.331 ;
     RECT  45.108 78.241 46.494 78.331 ;
     RECT  2.415 78.089 2.862 78.359 ;
     RECT  3.6 78.241 10.17 78.359 ;
     RECT  12.096 78.241 16.758 78.359 ;
     RECT  25.38 78.061 27.45 78.359 ;
     RECT  32.112 78.241 33.39 78.359 ;
     RECT  34.668 78.331 37.746 78.359 ;
     RECT  38.52 78.331 39.474 78.359 ;
     RECT  40.215 78.241 43.65 78.359 ;
     RECT  48.456 77.971 51.966 78.359 ;
     RECT  54.36 77.855 54.738 78.359 ;
     RECT  55.8 78.241 59.562 78.359 ;
     RECT  61.56 78.089 68.922 78.359 ;
     RECT  75.528 78.097 107.226 78.359 ;
     RECT  71.82 77.585 74.574 78.367 ;
     RECT  75.528 78.359 75.798 78.367 ;
     RECT  27.36 78.359 27.45 78.395 ;
     RECT  76.752 78.359 95.526 78.395 ;
     RECT  7.704 78.359 9.99 78.431 ;
     RECT  40.215 78.359 42.282 78.431 ;
     RECT  20.16 77.971 20.898 78.439 ;
     RECT  22.284 77.971 24.534 78.439 ;
     RECT  32.256 78.359 33.39 78.439 ;
     RECT  34.668 78.359 37.026 78.439 ;
     RECT  43.056 78.359 43.65 78.439 ;
     RECT  44.964 78.331 46.494 78.439 ;
     RECT  47.484 78.241 47.646 78.439 ;
     RECT  48.456 78.359 48.87 78.439 ;
     RECT  50.868 78.359 51.966 78.439 ;
     RECT  53.028 77.971 53.586 78.439 ;
     RECT  69.876 78.089 70.974 78.439 ;
     RECT  71.82 78.367 75.798 78.439 ;
     RECT  47.484 78.439 48.87 78.467 ;
     RECT  18.288 77.971 19.062 78.475 ;
     RECT  20.16 78.439 21.366 78.475 ;
     RECT  22.104 78.439 24.534 78.475 ;
     RECT  25.38 78.359 26.55 78.475 ;
     RECT  38.52 78.359 38.538 78.475 ;
     RECT  47.484 78.467 47.97 78.475 ;
     RECT  15.732 78.359 16.758 78.503 ;
     RECT  39.312 78.359 39.474 78.503 ;
     RECT  10.764 78.475 10.782 78.511 ;
     RECT  18.072 78.475 19.314 78.511 ;
     RECT  20.16 78.475 26.55 78.511 ;
     RECT  55.836 78.359 59.562 78.511 ;
     RECT  60.516 78.161 60.714 78.511 ;
     RECT  61.56 78.359 62.097 78.511 ;
     RECT  3.6 78.359 6.57 78.539 ;
     RECT  7.74 78.431 9.99 78.539 ;
     RECT  15.912 78.503 15.966 78.539 ;
     RECT  18.072 78.511 26.55 78.539 ;
     RECT  28.62 77.657 31.158 78.539 ;
     RECT  32.256 78.439 37.026 78.539 ;
     RECT  43.056 78.439 46.494 78.539 ;
     RECT  54.36 78.359 54.702 78.539 ;
     RECT  63.792 78.359 65.862 78.539 ;
     RECT  76.752 78.395 95.49 78.539 ;
     RECT  7.74 78.539 8.802 78.587 ;
     RECT  18.072 78.539 24.297 78.587 ;
     RECT  60.516 78.511 62.097 78.587 ;
     RECT  10.764 78.511 10.998 78.629 ;
     RECT  12.096 78.359 14.742 78.629 ;
     RECT  18.072 78.587 24.174 78.629 ;
     RECT  25.236 78.539 26.55 78.629 ;
     RECT  32.256 78.539 35.91 78.629 ;
     RECT  38.088 78.475 38.538 78.629 ;
     RECT  40.215 78.431 41.886 78.629 ;
     RECT  44.064 78.539 46.494 78.629 ;
     RECT  47.268 78.475 47.97 78.629 ;
     RECT  50.868 78.439 53.586 78.629 ;
     RECT  55.836 78.511 59.634 78.629 ;
     RECT  60.516 78.587 61.974 78.629 ;
     RECT  63.792 78.539 64.53 78.629 ;
     RECT  66.6 78.359 68.922 78.629 ;
     RECT  69.876 78.439 75.798 78.629 ;
     RECT  76.752 78.539 79.938 78.629 ;
     RECT  80.676 78.539 95.382 78.629 ;
     RECT  96.336 78.359 107.226 78.629 ;
     RECT  3.6 78.539 5.598 78.665 ;
     RECT  18.072 78.629 20.43 78.665 ;
     RECT  21.348 78.629 24.174 78.665 ;
     RECT  25.38 78.629 26.55 78.665 ;
     RECT  28.872 78.539 31.158 78.665 ;
     RECT  32.4 78.629 33.534 78.665 ;
     RECT  47.628 78.629 47.826 78.665 ;
     RECT  49.716 78.359 50.058 78.665 ;
     RECT  58.392 78.629 59.634 78.665 ;
     RECT  63.972 78.629 64.53 78.665 ;
     RECT  66.6 78.629 68.85 78.665 ;
     RECT  71.208 78.629 73.818 78.665 ;
     RECT  78.015 78.629 79.938 78.665 ;
     RECT  82.584 78.629 84.186 78.665 ;
     RECT  84.96 78.629 85.698 78.665 ;
     RECT  86.616 78.629 86.778 78.665 ;
     RECT  87.516 78.629 87.75 78.665 ;
     RECT  90.036 78.629 90.882 78.665 ;
     RECT  95.184 78.629 95.382 78.665 ;
     RECT  96.408 78.629 97.506 78.665 ;
     RECT  99.108 78.629 102.006 78.665 ;
     RECT  102.852 78.629 107.226 78.665 ;
     RECT  75.42 78.629 75.726 78.701 ;
     RECT  76.752 78.629 76.986 78.701 ;
     RECT  78.015 78.665 79.11 78.701 ;
     RECT  92.304 78.629 92.322 78.701 ;
     RECT  93.096 78.629 94.305 78.701 ;
     RECT  96.408 78.665 96.966 78.701 ;
     RECT  101.7 78.665 101.898 78.701 ;
     RECT  18.144 78.665 20.43 78.737 ;
     RECT  103.392 78.665 103.878 78.737 ;
     RECT  99.468 78.665 100.566 78.773 ;
     RECT  3.96 78.665 5.13 78.809 ;
     RECT  23.004 78.665 24.174 78.809 ;
     RECT  38.088 78.629 38.178 78.809 ;
     RECT  44.064 78.629 45.705 78.809 ;
     RECT  47.736 78.665 47.826 78.809 ;
     RECT  50.868 78.629 51.105 78.809 ;
     RECT  52.272 78.629 52.758 78.809 ;
     RECT  55.836 78.629 57.006 78.809 ;
     RECT  60.624 78.629 61.905 78.809 ;
     RECT  66.6 78.665 67.95 78.809 ;
     RECT  72.216 78.665 73.818 78.809 ;
     RECT  75.42 78.701 75.438 78.809 ;
     RECT  78.912 78.701 79.11 78.809 ;
     RECT  88.74 78.629 88.905 78.809 ;
     RECT  93.276 78.701 94.305 78.809 ;
     RECT  103.464 78.737 103.878 78.809 ;
     RECT  104.724 78.665 105.426 78.809 ;
     RECT  2.415 78.359 2.826 78.857 ;
     RECT  7.74 78.587 7.905 78.857 ;
     RECT  12.528 78.629 13.59 78.857 ;
     RECT  18.144 78.737 19.386 78.857 ;
     RECT  24.015 78.809 24.174 78.857 ;
     RECT  28.872 78.665 30.186 78.857 ;
     RECT  34.524 78.629 34.905 78.857 ;
     RECT  40.215 78.629 40.842 78.857 ;
     RECT  45.144 78.809 45.705 78.857 ;
     RECT  50.904 78.809 51.105 78.857 ;
     RECT  55.836 78.809 56.97 78.857 ;
     RECT  61.776 78.809 61.905 78.857 ;
     RECT  66.6 78.809 67.554 78.857 ;
     RECT  72.216 78.809 73.35 78.857 ;
     RECT  78.015 78.701 78.174 78.857 ;
     RECT  82.8 78.665 84.186 78.857 ;
     RECT  88.776 78.809 88.905 78.857 ;
     RECT  93.42 78.809 94.305 78.857 ;
     RECT  99.468 78.773 99.705 78.857 ;
     RECT  50.904 78.857 50.922 78.989 ;
     RECT  104.832 78.809 105.426 78.989 ;
     RECT  2.808 78.857 2.826 79.229 ;
     RECT  3.96 78.809 3.978 79.229 ;
     RECT  5.112 78.809 5.13 79.229 ;
     RECT  12.528 78.857 12.546 79.229 ;
     RECT  19.368 78.857 19.386 79.229 ;
     RECT  20.412 78.737 20.43 79.229 ;
     RECT  21.636 78.665 21.654 79.229 ;
     RECT  30.168 78.857 30.186 79.229 ;
     RECT  37.008 78.539 37.026 79.229 ;
     RECT  39.312 78.503 39.33 79.229 ;
     RECT  53.568 78.629 53.586 79.229 ;
     RECT  54.684 78.539 54.702 79.229 ;
     RECT  55.836 78.857 55.854 79.229 ;
     RECT  56.952 78.857 56.97 79.229 ;
     RECT  71.208 78.665 71.226 79.229 ;
     RECT  86.616 78.665 86.634 79.229 ;
     RECT  87.732 78.665 87.75 79.229 ;
     RECT  90.036 78.665 90.054 79.229 ;
     RECT  100.548 78.773 100.566 79.229 ;
     RECT  106.164 78.665 107.226 79.229 ;
     RECT  10.98 78.629 10.998 79.277 ;
     RECT  16.74 78.503 16.758 79.277 ;
     RECT  27.504 78.511 27.522 79.277 ;
     RECT  34.524 78.857 34.542 79.277 ;
     RECT  45.144 78.857 45.162 79.277 ;
     RECT  63.972 78.665 63.99 79.277 ;
     RECT  67.536 78.857 67.554 79.277 ;
     RECT  69.876 78.629 69.894 79.277 ;
     RECT  72.216 78.857 72.234 79.277 ;
     RECT  73.332 78.857 73.35 79.277 ;
     RECT  74.592 78.629 74.61 79.277 ;
     RECT  82.8 78.857 82.818 79.277 ;
     RECT  93.42 78.857 94.122 79.277 ;
     RECT  96.948 78.701 96.966 79.277 ;
     RECT  106.452 79.229 107.226 79.469 ;
     RECT  107.208 79.469 107.226 79.661 ;
     RECT  18.144 78.857 18.162 79.805 ;
     RECT  23.004 78.809 23.022 79.805 ;
     RECT  25.38 78.665 25.398 79.805 ;
     RECT  32.4 78.665 32.418 79.805 ;
     RECT  33.516 78.665 33.534 79.805 ;
     RECT  38.16 78.809 38.178 79.805 ;
     RECT  40.824 78.857 40.842 79.805 ;
     RECT  44.064 78.809 44.082 79.805 ;
     RECT  47.736 78.809 47.754 79.805 ;
     RECT  52.272 78.809 52.29 79.805 ;
     RECT  59.616 78.665 59.634 79.805 ;
     RECT  68.832 78.665 68.85 79.805 ;
     RECT  76.968 78.701 76.986 79.805 ;
     RECT  78.156 78.857 78.174 79.805 ;
     RECT  81.792 78.629 81.81 79.805 ;
     RECT  88.776 78.857 88.794 79.805 ;
     RECT  99.468 78.857 99.486 79.805 ;
     RECT  101.844 78.701 101.898 79.805 ;
     RECT  79.092 78.809 79.11 79.853 ;
     RECT  95.364 78.665 95.382 79.853 ;
     RECT  104.832 78.989 104.85 79.853 ;
     RECT  103.824 78.809 103.878 79.901 ;
     RECT  90.864 78.665 90.882 80.429 ;
     RECT  94.104 79.277 94.122 80.429 ;
     RECT  101.88 79.805 101.898 80.429 ;
     RECT  103.824 79.901 103.842 80.429 ;
     RECT  6.552 78.539 6.57 80.909 ;
     RECT  7.74 78.857 7.758 80.909 ;
     RECT  8.784 78.587 8.802 80.909 ;
     RECT  9.972 78.539 9.99 80.909 ;
     RECT  13.572 78.857 13.59 80.909 ;
     RECT  14.724 78.629 14.742 80.909 ;
     RECT  15.948 78.539 15.966 80.909 ;
     RECT  24.156 78.857 24.174 80.909 ;
     RECT  26.532 78.665 26.55 80.909 ;
     RECT  28.872 78.857 28.89 80.909 ;
     RECT  31.14 78.665 31.158 80.909 ;
     RECT  35.892 78.629 35.91 80.909 ;
     RECT  41.868 78.629 41.886 80.909 ;
     RECT  43.056 78.539 43.074 80.909 ;
     RECT  46.476 78.629 46.494 80.909 ;
     RECT  48.852 78.467 48.87 80.909 ;
     RECT  50.04 78.665 50.058 80.909 ;
     RECT  58.392 78.665 58.41 80.909 ;
     RECT  60.624 78.809 60.642 80.909 ;
     RECT  61.776 78.857 61.794 80.909 ;
     RECT  63 78.359 63.018 80.909 ;
     RECT  65.412 78.539 65.43 80.909 ;
     RECT  66.6 78.857 66.618 80.909 ;
     RECT  80.748 78.629 80.766 80.909 ;
     RECT  84.168 78.857 84.186 80.909 ;
     RECT  85.392 78.665 85.41 80.909 ;
     RECT  98.244 78.629 98.262 80.909 ;
     RECT  106.452 79.469 106.47 80.909 ;
    LAYER M4 ;
     RECT  1.477 4.56 2.069 4.584 ;
     RECT  1.141 0.576 2.332 0.6 ;
     RECT  2.332 0.528 2.333 0.6 ;
     RECT  1.745 1.728 2.408 1.752 ;
     RECT  2.069 3.984 2.408 4.584 ;
     RECT  1.565 78.048 2.408 78.072 ;
     RECT  2.333 0.528 2.435 0.552 ;
     RECT  2.408 1.728 2.704 78.852 ;
     RECT  2.725 79.2 2.837 79.224 ;
     RECT  2.704 1.728 3.395 5.688 ;
     RECT  2.704 13.68 3.443 17.208 ;
     RECT  2.704 20.976 3.449 21 ;
     RECT  3.395 3.12 3.593 5.688 ;
     RECT  2.704 11.376 3.629 12.552 ;
     RECT  3.443 13.68 3.683 15.048 ;
     RECT  3.683 14.592 3.737 15.048 ;
     RECT  3.593 5.088 3.971 5.688 ;
     RECT  3.971 5.088 3.989 5.112 ;
     RECT  3.905 79.2 3.989 79.224 ;
     RECT  3.913 0.096 4.019 0.12 ;
     RECT  3.593 3.12 4.061 4.008 ;
     RECT  3.697 21.12 4.061 21.144 ;
     RECT  3.443 16.512 4.205 17.208 ;
     RECT  4.129 10.176 4.957 10.2 ;
     RECT  3.629 11.376 4.957 11.4 ;
     RECT  2.704 19.392 4.993 19.416 ;
     RECT  3.737 14.592 5.033 14.616 ;
     RECT  4.061 3.12 5.101 3.96 ;
     RECT  4.993 19.104 5.101 19.416 ;
     RECT  2.704 23.28 5.101 23.304 ;
     RECT  4.561 70.8 5.101 70.824 ;
     RECT  4.957 10.176 5.137 11.4 ;
     RECT  3.629 12.528 5.137 12.552 ;
     RECT  5.101 22.752 5.137 23.304 ;
     RECT  5.057 79.2 5.141 79.224 ;
     RECT  4.205 17.088 5.177 17.208 ;
     RECT  5.228 5.376 5.245 5.4 ;
     RECT  5.101 8.304 5.269 8.328 ;
     RECT  5.245 5.184 5.315 5.4 ;
     RECT  5.137 10.176 5.497 12.552 ;
     RECT  5.425 14.208 5.509 14.232 ;
     RECT  4.993 74.688 5.537 74.712 ;
     RECT  5.101 19.104 5.573 19.8 ;
     RECT  5.101 2.88 5.605 3.96 ;
     RECT  5.315 5.184 5.605 5.208 ;
     RECT  5.269 8.304 5.677 9.144 ;
     RECT  5.497 10.176 5.677 12.984 ;
     RECT  5.101 70.368 5.701 70.824 ;
     RECT  5.605 72.096 5.701 72.12 ;
     RECT  5.677 8.304 5.713 12.984 ;
     RECT  5.713 8.208 5.717 12.984 ;
     RECT  5.701 69.888 5.747 72.12 ;
     RECT  5.717 11.136 5.821 12.984 ;
     RECT  5.747 71.616 5.825 71.64 ;
     RECT  5.747 69.888 5.861 70.392 ;
     RECT  5.821 11.136 5.933 13.656 ;
     RECT  5.9 21.648 5.987 21.672 ;
     RECT  5.605 2.88 6.221 5.208 ;
     RECT  5.965 73.776 6.253 73.8 ;
     RECT  5.929 15.312 6.289 15.336 ;
     RECT  5.717 8.208 6.325 9.672 ;
     RECT  5.137 22.752 6.325 23.64 ;
     RECT  6.325 7.92 6.365 9.672 ;
     RECT  5.933 11.136 6.365 11.976 ;
     RECT  6.325 22.752 6.409 23.976 ;
     RECT  6.221 3.408 6.433 5.208 ;
     RECT  6.289 20.544 6.467 20.568 ;
     RECT  6.433 3.408 6.517 5.736 ;
     RECT  5.573 19.104 6.572 19.56 ;
     RECT  5.353 17.52 6.613 17.544 ;
     RECT  5.933 12.96 6.649 13.656 ;
     RECT  6.289 15.312 6.649 15.432 ;
     RECT  6.253 73.488 6.653 73.8 ;
     RECT  6.572 18.912 6.659 19.56 ;
     RECT  6.649 12.96 6.853 15.432 ;
     RECT  6.853 12.96 7.045 16.104 ;
     RECT  6.613 17.52 7.045 17.88 ;
     RECT  6.409 22.752 7.045 23.064 ;
     RECT  5.861 70.272 7.189 70.392 ;
     RECT  6.365 11.136 7.333 11.928 ;
     RECT  7.045 12.96 7.333 17.88 ;
     RECT  3.925 6.816 7.405 6.84 ;
     RECT  7.333 11.136 7.477 17.88 ;
     RECT  7.436 25.344 7.477 25.368 ;
     RECT  6.659 19.344 7.585 19.56 ;
     RECT  6.649 24.24 7.693 24.264 ;
     RECT  7.477 25.344 7.693 26.28 ;
     RECT  6.517 3.408 7.801 5.304 ;
     RECT  3.395 1.728 7.808 1.752 ;
     RECT  7.801 3.36 7.808 5.304 ;
     RECT  7.405 6.816 7.808 6.888 ;
     RECT  6.365 7.92 7.808 7.944 ;
     RECT  6.365 9.12 7.808 9.672 ;
     RECT  7.477 10.992 7.808 17.88 ;
     RECT  7.585 19.344 7.808 19.656 ;
     RECT  7.045 22.032 7.808 23.064 ;
     RECT  7.693 24.24 7.808 26.28 ;
     RECT  7.189 70.08 7.808 70.392 ;
     RECT  7.045 71.472 7.808 71.496 ;
     RECT  6.653 73.584 7.808 73.8 ;
     RECT  2.704 77.328 7.808 77.352 ;
     RECT  7.808 1.728 7.912 78.852 ;
     RECT  7.912 1.728 8.104 78.582 ;
     RECT  8.104 3.36 8.237 18.216 ;
     RECT  8.104 68.736 8.237 74.088 ;
     RECT  8.237 68.736 8.281 70.728 ;
     RECT  8.237 17.424 8.453 18.216 ;
     RECT  8.237 3.36 8.524 16.104 ;
     RECT  8.524 9.6 8.531 16.104 ;
     RECT  8.531 9.6 8.597 11.976 ;
     RECT  8.531 13.104 8.633 16.104 ;
     RECT  8.104 19.344 8.633 22.776 ;
     RECT  8.281 68.736 8.675 70.488 ;
     RECT  8.633 13.104 8.705 13.32 ;
     RECT  8.675 69.456 8.716 70.488 ;
     RECT  8.633 14.352 8.741 16.104 ;
     RECT  8.453 18.096 8.777 18.216 ;
     RECT  8.716 69.84 8.777 70.488 ;
     RECT  8.104 26.256 8.813 26.28 ;
     RECT  6.277 80.88 8.813 80.904 ;
     RECT  8.237 71.808 8.849 74.088 ;
     RECT  8.777 18.192 9.065 18.216 ;
     RECT  8.633 19.344 9.101 22.104 ;
     RECT  8.104 77.328 9.137 77.352 ;
     RECT  8.741 14.352 9.173 15.864 ;
     RECT  8.524 3.36 9.209 8.52 ;
     RECT  8.849 71.808 9.281 72.168 ;
     RECT  9.241 75.264 9.325 75.288 ;
     RECT  8.705 13.104 9.353 13.128 ;
     RECT  8.849 73.2 9.353 74.088 ;
     RECT  9.209 5.28 9.605 8.52 ;
     RECT  9.353 74.064 9.635 74.088 ;
     RECT  9.101 19.344 9.637 21.384 ;
     RECT  9.493 23.568 9.709 23.592 ;
     RECT  9.349 0.096 9.731 0.12 ;
     RECT  9.173 15.84 9.929 15.864 ;
     RECT  9.589 75.504 9.929 75.528 ;
     RECT  8.777 69.84 9.98 70.392 ;
     RECT  9.829 80.88 10.001 80.904 ;
     RECT  9.209 3.36 10.069 4.248 ;
     RECT  9.709 23.28 10.069 23.592 ;
     RECT  10.069 2.832 10.156 4.248 ;
     RECT  9.637 18.816 10.177 21.384 ;
     RECT  9.173 14.352 10.249 14.376 ;
     RECT  10.069 23.136 10.249 23.592 ;
     RECT  9.961 17.136 10.261 17.16 ;
     RECT  10.177 18.816 10.309 21.96 ;
     RECT  10.156 3.408 10.465 4.248 ;
     RECT  9.313 25.2 10.465 25.224 ;
     RECT  9.925 26.208 10.501 26.232 ;
     RECT  9.385 27.312 10.501 27.336 ;
     RECT  9.605 5.28 10.505 8.04 ;
     RECT  10.505 5.28 10.613 7.896 ;
     RECT  10.465 3.408 10.681 4.296 ;
     RECT  10.613 5.28 10.681 7.848 ;
     RECT  8.597 10.224 10.789 11.976 ;
     RECT  10.249 23.136 10.789 23.688 ;
     RECT  10.465 24.672 10.789 25.224 ;
     RECT  10.261 16.608 10.897 17.16 ;
     RECT  10.249 14.352 10.937 14.856 ;
     RECT  10.789 9.648 11.005 11.976 ;
     RECT  10.309 18.192 11.005 21.96 ;
     RECT  10.789 23.136 11.005 25.224 ;
     RECT  9.281 72.144 11.005 72.168 ;
     RECT  10.937 14.352 11.009 14.424 ;
     RECT  10.94 79.248 11.027 79.272 ;
     RECT  10.897 16.032 11.041 17.16 ;
     RECT  9.98 69.84 11.075 70.68 ;
     RECT  11.005 71.808 11.089 72.168 ;
     RECT  10.501 26.208 11.297 27.336 ;
     RECT  11.005 18.192 11.363 25.224 ;
     RECT  11.363 18.192 11.441 21.672 ;
     RECT  11.041 15.408 11.549 17.16 ;
     RECT  11.297 27.312 11.564 27.336 ;
     RECT  11.363 23.376 11.605 25.224 ;
     RECT  11.297 26.208 11.605 26.232 ;
     RECT  10.681 3.408 11.617 7.848 ;
     RECT  11.564 27.312 11.651 27.864 ;
     RECT  11.549 16.56 11.653 17.16 ;
     RECT  11.089 72.144 11.66 72.168 ;
     RECT  9.745 13.296 11.689 13.32 ;
     RECT  11.009 14.352 11.689 14.376 ;
     RECT  11.605 23.376 11.692 26.232 ;
     RECT  11.441 18.96 11.693 21.672 ;
     RECT  11.005 9.552 11.699 11.976 ;
     RECT  11.66 72.144 11.747 73.128 ;
     RECT  11.653 16.56 11.765 17.448 ;
     RECT  11.689 13.296 11.833 14.376 ;
     RECT  11.699 9.552 12.017 11.736 ;
     RECT  11.693 18.96 12.053 21.192 ;
     RECT  11.833 13.104 12.161 14.376 ;
     RECT  11.075 69.84 12.229 70.536 ;
     RECT  11.747 72.144 12.229 72.456 ;
     RECT  11.765 16.944 12.524 17.448 ;
     RECT  12.053 18.96 12.524 21 ;
     RECT  12.181 79.2 12.557 79.224 ;
     RECT  11.617 3.36 12.733 7.848 ;
     RECT  11.549 15.408 12.733 15.432 ;
     RECT  12.524 16.944 12.733 21 ;
     RECT  12.733 3.36 12.757 8.472 ;
     RECT  12.017 10.848 12.841 11.736 ;
     RECT  12.229 12.816 12.841 12.888 ;
     RECT  11.692 26.208 12.949 26.232 ;
     RECT  11.651 27.312 12.949 27.336 ;
     RECT  12.017 9.552 13.093 9.576 ;
     RECT  12.841 10.848 13.093 12.888 ;
     RECT  12.733 22.176 13.093 22.2 ;
     RECT  11.692 23.376 13.093 25.224 ;
     RECT  11.365 74.112 13.093 74.136 ;
     RECT  12.733 15.408 13.129 21 ;
     RECT  13.093 22.176 13.129 25.224 ;
     RECT  12.229 69.84 13.201 72.456 ;
     RECT  8.104 1.728 13.208 1.752 ;
     RECT  12.757 3.072 13.208 8.472 ;
     RECT  13.093 9.552 13.208 12.888 ;
     RECT  12.161 14.352 13.208 14.376 ;
     RECT  13.129 15.408 13.208 25.224 ;
     RECT  12.949 26.208 13.208 27.336 ;
     RECT  13.201 69.744 13.208 72.456 ;
     RECT  13.093 74.112 13.208 74.616 ;
     RECT  11.581 77.28 13.208 77.304 ;
     RECT  13.208 1.728 13.312 78.852 ;
     RECT  13.312 1.728 13.504 78.582 ;
     RECT  13.504 74.592 13.619 74.616 ;
     RECT  13.504 75.648 13.619 75.672 ;
     RECT  13.504 76.704 13.619 77.304 ;
     RECT  13.619 76.704 13.66 76.728 ;
     RECT  13.504 22.224 13.709 22.776 ;
     RECT  13.504 3.408 13.745 13.032 ;
     RECT  13.504 23.952 13.961 27.336 ;
     RECT  13.504 14.352 14.105 14.856 ;
     RECT  13.961 23.952 14.285 26.28 ;
     RECT  13.504 17.424 14.321 20.952 ;
     RECT  14.321 18.912 14.357 20.952 ;
     RECT  13.504 15.984 14.429 16.344 ;
     RECT  14.357 20.928 14.429 20.952 ;
     RECT  14.105 14.352 14.605 14.808 ;
     RECT  13.745 10.512 14.717 13.032 ;
     RECT  13.709 22.752 14.789 22.776 ;
     RECT  14.285 23.952 14.861 25.224 ;
     RECT  14.357 18.912 14.897 19.896 ;
     RECT  14.861 23.952 15.001 24.696 ;
     RECT  13.504 71.856 15.037 72.408 ;
     RECT  14.717 10.512 15.041 12.312 ;
     RECT  13.504 69.744 15.107 70.392 ;
     RECT  15.061 59.808 15.157 59.832 ;
     RECT  15.037 71.808 15.181 72.408 ;
     RECT  15.157 59.712 15.203 59.832 ;
     RECT  14.321 17.424 15.325 17.64 ;
     RECT  14.897 18.912 15.325 19.32 ;
     RECT  14.429 15.984 15.397 16.296 ;
     RECT  15.325 17.424 15.397 19.32 ;
     RECT  15.397 15.984 15.443 19.32 ;
     RECT  14.605 14.256 15.469 14.808 ;
     RECT  15.181 71.808 15.545 72.936 ;
     RECT  15.469 13.536 15.577 14.808 ;
     RECT  15.443 15.984 15.577 17.64 ;
     RECT  15.5 22.176 15.587 22.2 ;
     RECT  15.577 13.536 15.725 17.64 ;
     RECT  13.745 3.408 15.757 9.384 ;
     RECT  15.757 3.072 15.937 9.384 ;
     RECT  15.937 3.072 15.973 9.432 ;
     RECT  13.333 80.88 15.977 80.904 ;
     RECT  14.285 26.256 16.009 26.28 ;
     RECT  13.961 27.264 16.009 27.336 ;
     RECT  16.009 26.256 16.013 27.336 ;
     RECT  15.973 3.072 16.049 9.528 ;
     RECT  16.049 8.208 16.153 9.528 ;
     RECT  15.041 10.512 16.153 12.024 ;
     RECT  15.203 59.712 16.213 59.736 ;
     RECT  16.153 8.208 16.229 12.024 ;
     RECT  15.107 69.744 16.259 69.864 ;
     RECT  16.229 8.208 16.445 11.928 ;
     RECT  15.443 18.816 16.549 19.32 ;
     RECT  15.973 21.12 16.549 21.144 ;
     RECT  16.549 18.816 16.595 21.144 ;
     RECT  15.725 13.536 16.621 14.664 ;
     RECT  16.513 66.096 16.789 66.12 ;
     RECT  16.445 8.688 16.805 11.928 ;
     RECT  16.789 66.096 16.835 66.888 ;
     RECT  16.259 69.744 16.835 69.768 ;
     RECT  16.729 79.248 16.931 79.272 ;
     RECT  15.001 23.232 16.933 24.696 ;
     RECT  16.621 25.68 16.933 25.704 ;
     RECT  16.595 18.816 17.017 20.28 ;
     RECT  16.933 23.232 17.02 25.704 ;
     RECT  16.933 74.256 17.02 74.28 ;
     RECT  16.805 8.688 17.129 11.88 ;
     RECT  15.545 72.144 17.129 72.936 ;
     RECT  16.621 13.104 17.161 14.664 ;
     RECT  17.02 25.68 17.221 25.704 ;
     RECT  16.013 26.736 17.221 27.336 ;
     RECT  17.02 23.232 17.237 24.696 ;
     RECT  16.835 66.864 17.273 66.888 ;
     RECT  16.049 3.072 17.377 7.128 ;
     RECT  15.725 15.984 17.413 17.64 ;
     RECT  17.017 18.768 17.413 20.28 ;
     RECT  17.221 25.68 17.417 27.336 ;
     RECT  17.377 3.072 17.557 7.176 ;
     RECT  15.793 77.472 17.561 77.496 ;
     RECT  17.557 3.072 17.597 7.752 ;
     RECT  17.161 13.104 17.797 14.904 ;
     RECT  17.413 15.984 18.085 20.28 ;
     RECT  17.485 21.648 18.085 21.672 ;
     RECT  17.237 23.328 18.169 24.696 ;
     RECT  17.417 25.68 18.169 26.28 ;
     RECT  18.037 79.776 18.173 79.8 ;
     RECT  18.085 15.984 18.181 21.672 ;
     RECT  17.597 3.408 18.205 7.752 ;
     RECT  17.129 8.736 18.205 11.88 ;
     RECT  18.169 23.328 18.313 26.28 ;
     RECT  17.629 0.096 18.323 0.12 ;
     RECT  17.797 13.104 18.469 14.952 ;
     RECT  18.181 15.984 18.469 22.008 ;
     RECT  13.504 1.728 18.529 1.752 ;
     RECT  18.529 1.728 18.608 1.848 ;
     RECT  18.205 3.408 18.608 11.88 ;
     RECT  18.469 13.104 18.608 22.008 ;
     RECT  18.313 23.04 18.608 26.28 ;
     RECT  17.417 27.312 18.608 27.336 ;
     RECT  16.213 59.712 18.608 60.408 ;
     RECT  17.089 68.64 18.608 68.664 ;
     RECT  17.129 72.144 18.608 72.84 ;
     RECT  18.097 76.752 18.608 76.776 ;
     RECT  18.608 1.728 18.904 78.852 ;
     RECT  18.904 20.88 19.217 22.008 ;
     RECT  19.217 21.744 19.325 22.008 ;
     RECT  18.904 23.04 19.379 27.336 ;
     RECT  18.904 72.144 19.379 73.56 ;
     RECT  19.379 72.144 19.433 72.84 ;
     RECT  19.379 23.376 19.541 27.336 ;
     RECT  18.904 3.168 19.829 11.64 ;
     RECT  18.904 13.584 19.865 19.56 ;
     RECT  19.865 13.584 19.901 16.344 ;
     RECT  19.829 3.168 19.973 7.464 ;
     RECT  19.829 8.736 19.973 11.64 ;
     RECT  19.973 3.408 20.009 7.464 ;
     RECT  19.325 21.936 20.113 22.008 ;
     RECT  19.901 13.584 20.149 16.104 ;
     RECT  19.973 11.376 20.257 11.64 ;
     RECT  20.149 12.768 20.257 16.104 ;
     RECT  20.257 11.376 20.261 16.104 ;
     RECT  20.257 20.88 20.293 20.904 ;
     RECT  20.113 21.936 20.297 22.2 ;
     RECT  18.904 70.128 20.369 70.152 ;
     RECT  20.293 20.736 20.401 20.904 ;
     RECT  19.237 79.2 20.441 79.224 ;
     RECT  20.261 15.984 20.549 16.104 ;
     RECT  19.541 25.296 20.549 27.336 ;
     RECT  20.009 3.552 20.585 7.464 ;
     RECT  20.297 21.984 20.725 22.2 ;
     RECT  19.541 23.376 20.725 24.168 ;
     RECT  20.261 11.376 20.819 14.808 ;
     RECT  18.904 1.728 20.821 1.752 ;
     RECT  20.821 1.728 20.945 1.8 ;
     RECT  20.725 21.984 21.049 24.168 ;
     RECT  20.549 25.776 21.089 27.336 ;
     RECT  18.904 76.752 21.125 76.776 ;
     RECT  19.973 8.736 21.193 10.104 ;
     RECT  19.865 17.424 21.193 19.56 ;
     RECT  20.401 20.544 21.193 20.904 ;
     RECT  21.049 21.984 21.233 24.6 ;
     RECT  19.433 72.144 21.301 72.168 ;
     RECT  21.193 17.424 21.337 20.904 ;
     RECT  21.337 17.088 21.373 20.904 ;
     RECT  21.233 21.984 21.373 22.2 ;
     RECT  21.337 48.48 21.421 48.504 ;
     RECT  20.585 3.552 21.553 7.224 ;
     RECT  21.553 3.456 21.589 7.224 ;
     RECT  21.193 8.736 21.589 10.152 ;
     RECT  18.904 68.64 21.625 68.664 ;
     RECT  21.581 79.2 21.665 79.224 ;
     RECT  21.625 68.64 21.685 69.528 ;
     RECT  21.653 49.008 21.737 49.032 ;
     RECT  21.589 3.456 21.769 10.152 ;
     RECT  21.301 72.144 21.781 72.696 ;
     RECT  20.549 15.984 21.805 16.056 ;
     RECT  21.373 17.088 21.805 22.2 ;
     RECT  21.685 68.064 21.873 70.488 ;
     RECT  21.233 23.568 21.925 24.6 ;
     RECT  21.089 25.776 21.925 25.8 ;
     RECT  20.819 11.376 21.949 14.472 ;
     RECT  21.805 15.984 21.949 22.2 ;
     RECT  21.949 11.328 21.989 22.2 ;
     RECT  21.925 23.568 22.012 25.8 ;
     RECT  21.409 76.368 22.021 76.632 ;
     RECT  21.873 68.064 22.097 69.528 ;
     RECT  21.769 2.832 22.129 10.152 ;
     RECT  22.201 70.8 22.237 70.824 ;
     RECT  21.781 72.144 22.237 73.272 ;
     RECT  22.012 23.568 22.273 24.6 ;
     RECT  22.129 2.832 22.277 10.248 ;
     RECT  21.989 16.512 22.313 22.2 ;
     RECT  21.089 27.312 22.345 27.336 ;
     RECT  22.313 21.984 22.381 22.2 ;
     RECT  22.273 23.376 22.381 24.6 ;
     RECT  22.345 26.928 22.385 27.336 ;
     RECT  22.381 21.984 22.403 24.6 ;
     RECT  21.349 46.128 22.489 46.152 ;
     RECT  22.313 16.512 22.493 20.76 ;
     RECT  22.021 75.552 22.661 76.632 ;
     RECT  22.237 70.8 22.673 73.272 ;
     RECT  22.403 21.984 22.717 23.016 ;
     RECT  22.012 25.776 22.741 25.8 ;
     RECT  22.385 26.928 22.741 26.952 ;
     RECT  22.661 74.64 22.745 76.632 ;
     RECT  22.277 9.792 22.835 10.248 ;
     RECT  20.945 1.728 22.849 1.752 ;
     RECT  22.277 2.832 22.849 8.76 ;
     RECT  21.989 11.328 22.853 15.192 ;
     RECT  22.493 20.208 22.853 20.76 ;
     RECT  22.489 45.936 22.853 46.248 ;
     RECT  22.745 75.552 22.885 76.632 ;
     RECT  22.673 73.248 22.921 73.272 ;
     RECT  22.885 75.552 22.925 76.92 ;
     RECT  22.673 70.8 22.961 72.264 ;
     RECT  22.789 79.776 23.033 79.8 ;
     RECT  22.853 11.328 23.101 14.568 ;
     RECT  22.403 24.096 23.221 24.6 ;
     RECT  22.741 25.776 23.221 26.952 ;
     RECT  22.835 10.176 23.533 10.248 ;
     RECT  23.101 11.232 23.533 14.568 ;
     RECT  22.853 20.208 23.605 20.232 ;
     RECT  23.605 20.16 23.785 20.232 ;
     RECT  23.785 20.112 23.821 20.232 ;
     RECT  22.717 21.984 23.821 22.008 ;
     RECT  22.717 22.992 23.821 23.016 ;
     RECT  22.849 1.728 24.008 8.76 ;
     RECT  23.533 10.176 24.008 14.568 ;
     RECT  22.493 16.512 24.008 18.696 ;
     RECT  23.821 20.112 24.008 20.616 ;
     RECT  23.821 21.984 24.008 23.016 ;
     RECT  23.221 24.096 24.008 26.952 ;
     RECT  22.853 46.032 24.008 46.248 ;
     RECT  18.904 59.712 24.008 60.408 ;
     RECT  22.097 68.112 24.008 69.528 ;
     RECT  22.961 70.8 24.008 71.016 ;
     RECT  22.961 72.24 24.008 72.264 ;
     RECT  22.921 73.248 24.008 73.368 ;
     RECT  22.925 75.552 24.008 75.576 ;
     RECT  22.925 76.896 24.008 76.92 ;
     RECT  23.965 0.576 24.049 0.6 ;
     RECT  24.008 1.728 24.112 78.852 ;
     RECT  23.941 80.88 24.185 80.904 ;
     RECT  24.112 1.728 24.304 78.582 ;
     RECT  24.304 45.792 24.419 45.96 ;
     RECT  24.304 20.016 24.581 20.904 ;
     RECT  24.304 77.04 24.797 77.496 ;
     RECT  24.304 72.288 24.94 73.368 ;
     RECT  24.304 1.728 25.013 1.752 ;
     RECT  24.304 21.984 25.013 26.856 ;
     RECT  24.94 72.576 25.085 73.368 ;
     RECT  24.304 15.84 25.091 18.936 ;
     RECT  24.304 11.376 25.193 14.232 ;
     RECT  25.193 11.664 25.265 14.232 ;
     RECT  25.013 21.984 25.283 22.248 ;
     RECT  24.304 2.832 25.297 9.768 ;
     RECT  25.265 13.008 25.333 14.232 ;
     RECT  25.141 79.776 25.409 79.8 ;
     RECT  25.013 23.376 25.445 26.856 ;
     RECT  25.091 15.84 25.481 18.696 ;
     RECT  25.265 11.664 25.589 11.976 ;
     RECT  25.297 2.352 25.667 9.768 ;
     RECT  25.585 74.64 25.669 75 ;
     RECT  25.085 72.576 25.725 73.272 ;
     RECT  25.445 24.864 25.733 26.856 ;
     RECT  25.669 74.256 25.756 75 ;
     RECT  25.725 72.768 25.769 73.272 ;
     RECT  25.667 9.744 25.801 9.768 ;
     RECT  25.333 13.008 25.801 14.616 ;
     RECT  25.333 70.656 25.801 70.68 ;
     RECT  25.445 23.376 25.805 23.688 ;
     RECT  25.805 23.664 25.811 23.688 ;
     RECT  25.801 69.888 25.909 70.68 ;
     RECT  25.909 69.888 25.955 71.256 ;
     RECT  25.283 22.224 26.021 22.248 ;
     RECT  25.481 15.936 26.093 18.696 ;
     RECT  25.801 9.744 26.125 9.816 ;
     RECT  25.955 69.888 26.129 69.912 ;
     RECT  24.797 77.472 26.129 77.496 ;
     RECT  25.667 2.352 26.197 8.76 ;
     RECT  25.955 71.232 26.237 71.256 ;
     RECT  24.581 20.016 26.557 20.616 ;
     RECT  26.293 80.88 26.561 80.904 ;
     RECT  25.801 13.008 26.593 14.808 ;
     RECT  26.093 15.936 26.593 16.824 ;
     RECT  25.733 24.864 26.669 24.888 ;
     RECT  25.733 26.16 26.737 26.856 ;
     RECT  25.589 11.664 26.837 11.784 ;
     RECT  26.593 13.008 26.849 16.824 ;
     RECT  26.125 9.744 26.869 10.2 ;
     RECT  26.837 11.568 26.869 11.784 ;
     RECT  26.557 20.016 26.917 21.192 ;
     RECT  26.869 9.744 26.921 11.784 ;
     RECT  26.197 1.728 27.029 8.76 ;
     RECT  26.849 16.8 27.241 16.824 ;
     RECT  26.093 17.856 27.241 18.696 ;
     RECT  25.769 72.768 27.245 72.792 ;
     RECT  26.849 13.008 27.389 15.624 ;
     RECT  27.389 15.312 27.395 15.624 ;
     RECT  27.241 16.8 27.395 18.696 ;
     RECT  25.756 74.976 27.395 75 ;
     RECT  26.921 9.792 27.497 11.784 ;
     RECT  27.452 79.248 27.539 79.272 ;
     RECT  26.737 24.912 27.673 26.856 ;
     RECT  27.395 15.312 27.713 15.336 ;
     RECT  27.349 76.944 27.713 76.968 ;
     RECT  26.917 19.776 27.749 21.192 ;
     RECT  27.749 19.776 27.821 20.04 ;
     RECT  27.749 21.024 27.853 21.192 ;
     RECT  27.029 3.36 27.889 8.76 ;
     RECT  27.497 9.792 27.889 10.248 ;
     RECT  27.395 16.8 28.393 16.92 ;
     RECT  27.395 17.904 28.465 18.696 ;
     RECT  27.821 19.776 28.465 19.8 ;
     RECT  27.029 1.728 28.501 1.752 ;
     RECT  28.393 16.08 28.501 16.92 ;
     RECT  28.465 17.904 28.501 19.8 ;
     RECT  27.853 21.024 28.717 21.384 ;
     RECT  28.501 1.152 28.787 1.752 ;
     RECT  27.389 13.008 28.789 13.944 ;
     RECT  28.645 80.88 28.901 80.904 ;
     RECT  27.673 24.624 28.933 26.856 ;
     RECT  27.889 3.36 29.041 10.248 ;
     RECT  27.497 11.664 29.077 11.784 ;
     RECT  28.825 22.752 29.173 22.776 ;
     RECT  29.041 2.832 29.185 10.248 ;
     RECT  29.077 11.52 29.185 11.784 ;
     RECT  28.789 13.008 29.269 14.136 ;
     RECT  28.717 20.88 29.365 21.384 ;
     RECT  29.173 22.56 29.365 22.776 ;
     RECT  28.787 1.728 29.408 1.752 ;
     RECT  29.185 2.832 29.408 11.784 ;
     RECT  29.269 13.008 29.408 15.048 ;
     RECT  28.501 16.08 29.408 19.8 ;
     RECT  29.365 20.88 29.408 22.776 ;
     RECT  28.933 23.856 29.408 26.856 ;
     RECT  24.419 45.936 29.408 45.96 ;
     RECT  24.304 59.712 29.408 60.408 ;
     RECT  24.304 68.112 29.408 68.136 ;
     RECT  28.213 71.376 29.408 71.4 ;
     RECT  28.537 74.064 29.408 74.088 ;
     RECT  28.753 77.136 29.408 77.16 ;
     RECT  29.408 1.728 29.704 78.852 ;
     RECT  29.704 15.024 29.729 19.032 ;
     RECT  29.729 15.312 29.837 19.032 ;
     RECT  29.704 20.112 29.837 27.336 ;
     RECT  29.837 15.312 29.945 18.792 ;
     RECT  29.704 70.272 30.089 70.296 ;
     RECT  29.704 73.488 30.179 74.088 ;
     RECT  29.704 76.944 30.179 77.16 ;
     RECT  29.845 79.2 30.197 79.224 ;
     RECT  30.179 73.488 30.233 73.992 ;
     RECT  29.945 15.312 30.269 18.696 ;
     RECT  29.837 20.112 30.269 22.2 ;
     RECT  29.704 1.728 30.341 13.944 ;
     RECT  30.269 20.496 30.341 22.2 ;
     RECT  29.837 23.376 30.449 27.336 ;
     RECT  30.341 10.848 30.665 13.944 ;
     RECT  30.341 1.728 30.773 9.864 ;
     RECT  30.665 12.336 30.805 13.944 ;
     RECT  30.269 15.312 30.949 16.536 ;
     RECT  30.949 15.216 31.043 16.536 ;
     RECT  30.269 17.856 31.093 18.696 ;
     RECT  30.997 80.88 31.169 80.904 ;
     RECT  30.449 26.304 31.313 27.336 ;
     RECT  30.805 12.336 31.331 14.232 ;
     RECT  31.043 15.84 31.333 16.536 ;
     RECT  30.341 22.032 31.345 22.2 ;
     RECT  30.179 77.136 31.384 77.16 ;
     RECT  31.384 77.136 31.385 77.208 ;
     RECT  31.093 17.856 31.453 19.08 ;
     RECT  30.341 20.496 31.453 20.904 ;
     RECT  31.345 21.936 31.453 22.2 ;
     RECT  30.449 23.376 31.453 25.128 ;
     RECT  31.453 20.496 31.493 25.128 ;
     RECT  31.331 12.864 31.601 14.232 ;
     RECT  31.333 15.84 31.633 16.632 ;
     RECT  31.493 22.992 31.637 25.128 ;
     RECT  31.633 15.84 31.957 16.824 ;
     RECT  31.453 17.856 31.957 19.368 ;
     RECT  30.773 2.832 31.993 9.864 ;
     RECT  30.665 10.848 31.993 10.968 ;
     RECT  29.704 71.664 31.993 71.688 ;
     RECT  31.637 22.992 31.997 24.456 ;
     RECT  31.601 13.92 32.209 14.232 ;
     RECT  32.209 13.92 32.281 14.424 ;
     RECT  31.313 26.304 32.317 26.856 ;
     RECT  31.957 15.84 32.353 19.368 ;
     RECT  31.601 12.864 32.389 12.888 ;
     RECT  32.353 15.456 32.483 19.368 ;
     RECT  31.997 22.992 32.573 23.976 ;
     RECT  31.385 77.184 32.681 77.208 ;
     RECT  31.993 71.664 32.732 71.832 ;
     RECT  29.704 68.112 32.749 68.136 ;
     RECT  32.749 68.112 32.789 68.424 ;
     RECT  32.732 71.232 32.819 71.832 ;
     RECT  32.573 22.992 32.861 23.352 ;
     RECT  32.317 26.304 32.929 27.384 ;
     RECT  32.389 12.048 32.969 12.888 ;
     RECT  31.993 2.832 33.037 10.968 ;
     RECT  31.493 20.496 33.073 21.96 ;
     RECT  32.483 15.456 33.113 17.112 ;
     RECT  32.483 18.48 33.145 19.368 ;
     RECT  33.073 20.4 33.145 21.96 ;
     RECT  32.969 12.816 33.221 12.888 ;
     RECT  32.789 68.4 33.365 68.424 ;
     RECT  32.861 22.992 33.437 23.016 ;
     RECT  32.197 79.776 33.545 79.8 ;
     RECT  33.113 15.984 33.685 17.112 ;
     RECT  32.929 25.728 33.901 27.384 ;
     RECT  33.221 12.864 34.081 12.888 ;
     RECT  32.281 13.92 34.081 14.472 ;
     RECT  33.685 15.984 34.117 17.16 ;
     RECT  33.145 18.48 34.117 21.96 ;
     RECT  30.773 1.728 34.153 1.752 ;
     RECT  33.037 2.832 34.225 11.4 ;
     RECT  34.508 79.248 34.595 79.272 ;
     RECT  32.819 71.808 34.729 71.832 ;
     RECT  29.704 45.936 34.732 45.96 ;
     RECT  30.233 73.488 34.765 73.512 ;
     RECT  34.153 1.728 34.808 1.848 ;
     RECT  34.225 2.832 34.808 11.496 ;
     RECT  34.081 12.864 34.808 14.472 ;
     RECT  34.117 15.984 34.808 22.248 ;
     RECT  33.901 23.376 34.808 23.4 ;
     RECT  33.901 25.056 34.808 27.384 ;
     RECT  34.732 45.936 34.808 46.008 ;
     RECT  29.704 59.712 34.808 60.408 ;
     RECT  34.549 68.928 34.808 68.952 ;
     RECT  34.729 71.184 34.808 71.832 ;
     RECT  34.765 73.344 34.808 73.512 ;
     RECT  34.729 75.84 34.808 75.864 ;
     RECT  34.261 76.848 34.808 76.872 ;
     RECT  34.693 0.096 34.835 0.12 ;
     RECT  34.808 1.728 34.912 78.852 ;
     RECT  34.912 1.728 35.104 78.582 ;
     RECT  35.104 74.64 35.219 75.432 ;
     RECT  35.104 76.848 35.273 76.872 ;
     RECT  35.104 25.248 35.411 27.864 ;
     RECT  35.104 12.24 35.548 23.544 ;
     RECT  35.548 12.24 35.605 23.4 ;
     RECT  35.605 15.072 35.849 23.4 ;
     RECT  35.411 25.248 35.921 27.096 ;
     RECT  35.701 80.88 35.921 80.904 ;
     RECT  35.921 25.44 35.957 27.096 ;
     RECT  35.849 15.072 35.987 23.256 ;
     RECT  35.605 12.24 36.065 13.944 ;
     RECT  35.104 68.928 36.097 68.952 ;
     RECT  36.092 31.44 36.179 31.464 ;
     RECT  36.065 13.104 36.209 13.944 ;
     RECT  35.104 2.832 36.317 10.872 ;
     RECT  35.987 15.072 36.353 21 ;
     RECT  36.097 68.016 36.353 68.952 ;
     RECT  36.317 8.256 36.385 10.872 ;
     RECT  35.957 25.584 36.467 27.096 ;
     RECT  35.104 45.984 36.467 46.008 ;
     RECT  36.353 15.072 36.497 20.76 ;
     RECT  36.413 31.872 36.497 31.896 ;
     RECT  36.209 13.296 36.569 13.944 ;
     RECT  35.104 71.184 36.569 71.208 ;
     RECT  36.569 13.584 36.677 13.944 ;
     RECT  35.219 74.64 36.805 74.664 ;
     RECT  36.764 69.408 36.851 69.432 ;
     RECT  35.104 73.344 36.851 73.368 ;
     RECT  36.497 15.072 36.892 18.888 ;
     RECT  35.987 21.984 36.925 23.256 ;
     RECT  35.104 1.728 36.997 1.752 ;
     RECT  36.317 2.832 36.997 7.272 ;
     RECT  36.892 15.072 37.001 15.096 ;
     RECT  36.901 79.2 37.037 79.224 ;
     RECT  36.353 68.016 37.073 68.04 ;
     RECT  36.997 1.728 37.109 7.272 ;
     RECT  36.467 25.968 37.145 27.096 ;
     RECT  36.925 21.984 37.181 23.352 ;
     RECT  36.805 51.264 37.429 51.288 ;
     RECT  36.892 16.128 37.469 18.888 ;
     RECT  36.421 47.28 37.475 47.304 ;
     RECT  36.385 8.256 37.477 11.448 ;
     RECT  37.181 23.232 37.501 23.352 ;
     RECT  37.501 23.232 37.537 24.216 ;
     RECT  37.469 16.224 37.541 18.888 ;
     RECT  36.497 20.304 37.573 20.76 ;
     RECT  37.181 21.984 37.573 22.2 ;
     RECT  37.541 16.512 37.577 18.888 ;
     RECT  37.109 2.832 37.609 7.272 ;
     RECT  37.477 8.256 37.609 12.216 ;
     RECT  37.537 23.232 37.685 24.648 ;
     RECT  37.609 2.832 37.793 12.216 ;
     RECT  37.577 16.512 37.793 18.84 ;
     RECT  37.573 20.304 37.793 22.2 ;
     RECT  37.793 20.4 37.829 22.2 ;
     RECT  37.753 47.472 37.837 47.496 ;
     RECT  36.805 74.544 37.865 74.664 ;
     RECT  37.681 71.52 38.005 71.544 ;
     RECT  37.793 12.192 38.041 12.216 ;
     RECT  37.793 2.832 38.045 10.632 ;
     RECT  38.005 70.944 38.051 71.544 ;
     RECT  37.964 72.576 38.051 72.6 ;
     RECT  37.969 30.816 38.053 30.84 ;
     RECT  38.041 12.192 38.081 12.792 ;
     RECT  37.145 26.16 38.108 27.096 ;
     RECT  38.081 12.768 38.113 12.792 ;
     RECT  36.677 13.92 38.113 13.944 ;
     RECT  37.685 24.192 38.113 24.648 ;
     RECT  38.108 25.632 38.113 27.096 ;
     RECT  38.101 79.776 38.189 79.8 ;
     RECT  38.113 12.768 38.221 13.944 ;
     RECT  37.069 77.52 38.333 77.544 ;
     RECT  37.793 16.56 38.369 18.84 ;
     RECT  37.829 20.736 38.441 22.2 ;
     RECT  38.113 24.192 38.441 27.096 ;
     RECT  38.441 21.12 38.545 22.2 ;
     RECT  38.369 18 38.689 18.84 ;
     RECT  38.545 21.12 38.761 23.016 ;
     RECT  38.441 24.192 38.837 26.904 ;
     RECT  38.221 12.768 38.869 13.992 ;
     RECT  38.113 67.776 38.909 67.8 ;
     RECT  37.105 69.504 38.945 69.528 ;
     RECT  37.429 50.736 39.197 51.288 ;
     RECT  38.051 70.944 39.205 70.968 ;
     RECT  38.293 76.368 39.212 76.392 ;
     RECT  38.761 21.12 39.229 23.16 ;
     RECT  38.837 24.192 39.229 26.856 ;
     RECT  38.869 12.768 39.301 14.856 ;
     RECT  39.253 79.2 39.341 79.224 ;
     RECT  39.229 21.12 39.589 26.856 ;
     RECT  38.045 2.832 39.661 10.296 ;
     RECT  39.301 11.952 39.661 14.856 ;
     RECT  38.689 18 39.697 19.128 ;
     RECT  39.589 20.688 39.697 26.856 ;
     RECT  39.661 2.832 39.733 10.968 ;
     RECT  39.661 11.952 39.733 15.048 ;
     RECT  38.369 16.56 39.733 16.968 ;
     RECT  39.733 2.832 39.877 16.968 ;
     RECT  39.697 18 39.877 26.856 ;
     RECT  39.877 2.832 39.913 26.856 ;
     RECT  37.109 1.728 40.208 1.752 ;
     RECT  39.913 2.784 40.208 26.856 ;
     RECT  36.133 38.448 40.208 38.472 ;
     RECT  35.104 59.712 40.208 60.408 ;
     RECT  38.149 65.952 40.208 65.976 ;
     RECT  39.205 70.656 40.208 70.968 ;
     RECT  37.865 74.592 40.208 74.664 ;
     RECT  39.212 76.176 40.208 76.392 ;
     RECT  40.208 1.728 40.312 78.852 ;
     RECT  40.312 1.728 40.504 78.582 ;
     RECT  40.504 12.528 40.673 14.472 ;
     RECT  40.504 24.912 40.681 27 ;
     RECT  40.453 79.776 40.853 79.8 ;
     RECT  40.673 12.528 41.033 12.552 ;
     RECT  40.681 24.912 41.033 26.952 ;
     RECT  40.504 1.728 41.249 1.8 ;
     RECT  40.504 17.952 41.429 18.552 ;
     RECT  40.673 13.584 41.996 13.944 ;
     RECT  41.996 13.584 41.999 14.568 ;
     RECT  40.504 2.784 42.037 10.968 ;
     RECT  41.677 12.192 42.037 12.216 ;
     RECT  40.504 16.8 42.041 16.872 ;
     RECT  41.999 13.584 42.083 15.432 ;
     RECT  42.037 2.784 42.109 12.216 ;
     RECT  42.083 13.584 42.109 14.232 ;
     RECT  41.033 24.912 42.293 26.856 ;
     RECT  41.429 18.144 42.325 18.552 ;
     RECT  42.109 2.784 42.329 14.232 ;
     RECT  42.325 18.144 42.433 18.792 ;
     RECT  42.083 15.408 42.505 15.432 ;
     RECT  40.504 75.792 42.617 75.816 ;
     RECT  42.293 24.912 42.649 25.224 ;
     RECT  40.504 20.592 42.833 23.64 ;
     RECT  42.505 15.408 42.869 16.344 ;
     RECT  41.605 80.88 43.085 80.904 ;
     RECT  42.293 26.448 43.121 26.856 ;
     RECT  42.329 2.832 43.225 14.232 ;
     RECT  42.869 15.408 43.225 15.432 ;
     RECT  43.225 2.832 43.337 15.432 ;
     RECT  43.121 26.448 43.441 26.568 ;
     RECT  42.433 18.144 43.621 19.272 ;
     RECT  40.504 74.592 43.873 74.616 ;
     RECT  43.337 12.192 43.913 15.432 ;
     RECT  43.337 2.832 43.949 11.112 ;
     RECT  43.153 16.992 43.981 17.16 ;
     RECT  43.621 18.144 43.981 19.32 ;
     RECT  42.649 24.672 43.981 25.224 ;
     RECT  43.441 26.256 43.981 26.568 ;
     RECT  43.913 15.408 44.053 15.432 ;
     RECT  43.981 16.992 44.053 19.32 ;
     RECT  44.053 15.408 44.089 19.32 ;
     RECT  42.833 20.592 44.089 23.592 ;
     RECT  43.957 79.776 44.093 79.8 ;
     RECT  43.949 2.832 44.129 11.064 ;
     RECT  44.089 20.592 44.437 23.64 ;
     RECT  43.981 24.672 44.437 26.568 ;
     RECT  44.089 15.408 44.489 19.368 ;
     RECT  44.489 15.6 44.524 19.368 ;
     RECT  44.437 20.592 44.597 26.568 ;
     RECT  43.913 12.192 44.989 14.232 ;
     RECT  43.873 74.592 45.013 75.192 ;
     RECT  41.821 77.328 45.025 77.352 ;
     RECT  44.524 15.792 45.061 19.368 ;
     RECT  44.597 20.592 45.061 25.032 ;
     RECT  44.129 2.832 45.169 10.2 ;
     RECT  45.025 76.992 45.169 77.352 ;
     RECT  45.116 79.248 45.203 79.272 ;
     RECT  45.169 2.832 45.277 10.488 ;
     RECT  45.013 74.592 45.397 75.816 ;
     RECT  45.169 76.944 45.397 77.352 ;
     RECT  41.249 1.728 45.589 1.752 ;
     RECT  45.589 1.104 45.608 1.752 ;
     RECT  45.277 2.832 45.608 10.632 ;
     RECT  44.989 11.76 45.608 14.232 ;
     RECT  45.061 15.792 45.608 25.032 ;
     RECT  44.597 26.256 45.608 26.568 ;
     RECT  40.504 38.448 45.608 38.472 ;
     RECT  40.504 59.712 45.608 60.408 ;
     RECT  40.504 65.952 45.608 65.976 ;
     RECT  45.397 74.592 45.608 77.352 ;
     RECT  45.608 1.104 45.712 78.852 ;
     RECT  45.712 1.104 45.785 78.582 ;
     RECT  45.785 1.728 45.904 78.582 ;
     RECT  45.904 1.728 46.001 1.8 ;
     RECT  45.904 20.88 46.181 23.736 ;
     RECT  46.181 23.088 46.325 23.736 ;
     RECT  46.309 80.88 46.505 80.904 ;
     RECT  45.904 24.72 46.595 26.568 ;
     RECT  45.904 75.792 46.613 76.296 ;
     RECT  46.595 25.056 46.636 26.568 ;
     RECT  45.904 15.456 46.739 18.024 ;
     RECT  46.613 76.176 46.793 76.296 ;
     RECT  45.904 2.832 47.045 14.376 ;
     RECT  46.739 15.792 47.081 18.024 ;
     RECT  47.113 19.344 47.221 19.368 ;
     RECT  46.181 20.88 47.293 22.056 ;
     RECT  46.325 23.136 47.293 23.736 ;
     RECT  47.081 15.888 47.365 18.024 ;
     RECT  47.221 19.344 47.365 19.8 ;
     RECT  47.293 20.88 47.377 23.736 ;
     RECT  47.377 23.28 47.441 23.736 ;
     RECT  47.365 15.888 47.509 19.8 ;
     RECT  47.509 15.888 47.549 19.848 ;
     RECT  46.636 25.056 47.756 25.464 ;
     RECT  46.636 26.544 47.756 26.568 ;
     RECT  47.549 19.344 47.761 19.848 ;
     RECT  47.377 20.88 47.761 22.008 ;
     RECT  47.509 79.776 47.765 79.8 ;
     RECT  47.549 15.984 47.788 18.024 ;
     RECT  47.756 25.056 47.843 26.568 ;
     RECT  47.843 25.056 47.945 25.176 ;
     RECT  47.761 19.344 47.981 22.008 ;
     RECT  47.945 25.152 47.981 25.176 ;
     RECT  47.045 2.832 48.233 14.232 ;
     RECT  47.788 17.136 48.269 18.024 ;
     RECT  47.788 15.984 48.305 16.152 ;
     RECT  47.441 23.28 48.485 23.304 ;
     RECT  48.233 13.92 48.517 14.232 ;
     RECT  48.269 17.184 48.563 18.024 ;
     RECT  46.793 76.176 48.565 76.2 ;
     RECT  48.565 76.176 48.652 76.392 ;
     RECT  47.981 19.776 48.665 21.96 ;
     RECT  48.233 2.832 48.809 12.84 ;
     RECT  48.661 80.88 48.881 80.904 ;
     RECT  47.113 77.472 49.169 77.496 ;
     RECT  48.665 21.216 49.237 21.96 ;
     RECT  48.589 23.328 49.313 23.352 ;
     RECT  48.809 8.256 49.385 12.84 ;
     RECT  48.563 17.184 49.417 17.64 ;
     RECT  48.305 15.984 49.421 16.008 ;
     RECT  49.237 21.216 49.523 22.248 ;
     RECT  49.385 11.952 49.573 12.84 ;
     RECT  48.517 13.92 49.573 14.472 ;
     RECT  49.417 17.088 49.597 17.64 ;
     RECT  49.573 11.952 49.619 14.472 ;
     RECT  49.165 18.768 49.621 18.792 ;
     RECT  48.665 19.776 49.621 19.8 ;
     RECT  49.597 16.608 49.637 17.64 ;
     RECT  49.621 18.768 49.637 19.8 ;
     RECT  49.523 21.216 49.667 21.24 ;
     RECT  48.809 2.832 49.669 7.224 ;
     RECT  49.637 19.632 49.709 19.8 ;
     RECT  49.669 2.784 49.756 7.224 ;
     RECT  49.637 17.616 49.781 17.64 ;
     RECT  49.709 19.776 49.961 19.8 ;
     RECT  49.861 80.88 50.069 80.904 ;
     RECT  46.001 1.728 50.281 1.752 ;
     RECT  48.652 76.176 50.713 76.2 ;
     RECT  50.281 1.728 51.008 1.8 ;
     RECT  49.756 2.832 51.008 7.224 ;
     RECT  49.385 8.256 51.008 10.728 ;
     RECT  49.619 12.816 51.008 14.472 ;
     RECT  49.637 16.608 51.008 16.632 ;
     RECT  45.904 38.448 51.008 38.472 ;
     RECT  45.904 59.712 51.008 60.408 ;
     RECT  45.904 65.952 51.008 65.976 ;
     RECT  50.713 75.312 51.008 76.296 ;
     RECT  50.893 78.96 51.008 78.984 ;
     RECT  51.008 1.728 51.059 78.984 ;
     RECT  51.059 1.728 51.112 78.852 ;
     RECT  51.112 1.728 51.304 78.582 ;
     RECT  51.304 13.92 52.013 14.472 ;
     RECT  51.304 1.728 52.265 1.848 ;
     RECT  52.213 79.776 52.301 79.8 ;
     RECT  52.477 0.576 52.595 0.6 ;
     RECT  51.304 75.504 53.057 76.296 ;
     RECT  53.365 79.2 53.597 79.224 ;
     RECT  53.953 40.656 54.227 40.68 ;
     RECT  54.277 40.464 54.361 40.488 ;
     RECT  53.057 76.08 54.565 76.296 ;
     RECT  54.565 79.2 54.713 79.224 ;
     RECT  55.105 74.592 55.189 74.616 ;
     RECT  54.025 77.52 55.253 77.544 ;
     RECT  54.565 75.84 55.283 76.536 ;
     RECT  55.765 79.2 55.865 79.224 ;
     RECT  55.283 76.368 56.108 76.536 ;
     RECT  52.265 1.728 56.408 1.752 ;
     RECT  51.304 2.832 56.408 7.224 ;
     RECT  51.304 8.256 56.408 10.728 ;
     RECT  51.304 12.816 56.408 12.84 ;
     RECT  52.013 14.352 56.408 14.376 ;
     RECT  51.304 38.448 56.408 38.472 ;
     RECT  51.304 59.712 56.408 60.408 ;
     RECT  56.108 76.368 56.408 77.256 ;
     RECT  56.408 1.728 56.704 78.852 ;
     RECT  56.897 79.2 56.981 79.224 ;
     RECT  56.977 0.096 57.061 0.12 ;
     RECT  56.704 76.512 57.203 76.536 ;
     RECT  56.704 75.168 57.244 75.192 ;
     RECT  58.117 80.88 58.421 80.904 ;
     RECT  58.201 76.176 58.669 76.2 ;
     RECT  58.561 0.096 58.931 0.12 ;
     RECT  56.704 14.352 58.957 14.376 ;
     RECT  58.669 75.792 59.249 76.2 ;
     RECT  59.249 76.176 59.276 76.2 ;
     RECT  59.276 76.176 59.317 76.344 ;
     RECT  58.849 77.52 59.317 77.544 ;
     RECT  59.317 76.176 59.357 77.544 ;
     RECT  59.357 76.32 59.363 77.544 ;
     RECT  59.269 79.776 59.645 79.8 ;
     RECT  59.363 76.752 59.825 77.544 ;
     RECT  56.704 1.728 59.845 1.752 ;
     RECT  59.845 1.104 60.005 1.752 ;
     RECT  60.469 80.88 60.653 80.904 ;
     RECT  60.757 0.096 61.187 0.12 ;
     RECT  60.973 74.064 61.525 74.088 ;
     RECT  59.825 76.752 61.525 76.776 ;
     RECT  61.621 80.88 61.805 80.904 ;
     RECT  60.005 1.728 61.808 1.752 ;
     RECT  56.704 2.832 61.808 7.224 ;
     RECT  56.704 8.256 61.808 10.728 ;
     RECT  56.704 12.816 61.808 12.84 ;
     RECT  58.957 13.872 61.808 14.376 ;
     RECT  56.704 38.448 61.808 38.472 ;
     RECT  56.704 59.712 61.808 60.408 ;
     RECT  61.525 73.344 61.808 74.088 ;
     RECT  61.525 76.368 61.808 76.776 ;
     RECT  61.808 1.728 61.912 78.852 ;
     RECT  61.912 1.728 62.104 78.582 ;
     RECT  62.104 72.72 62.243 73.512 ;
     RECT  62.104 74.976 62.705 76.776 ;
     RECT  62.104 2.832 62.957 11.544 ;
     RECT  62.821 80.88 63.029 80.904 ;
     RECT  62.705 74.976 63.109 76.104 ;
     RECT  63.109 74.496 63.155 76.104 ;
     RECT  63.155 74.496 63.209 74.52 ;
     RECT  62.104 1.728 63.241 1.752 ;
     RECT  62.957 2.832 63.241 7.224 ;
     RECT  63.932 79.248 64.019 79.272 ;
     RECT  63.241 1.728 64.069 7.224 ;
     RECT  62.957 8.256 64.069 11.544 ;
     RECT  64.069 1.728 64.109 11.544 ;
     RECT  62.104 13.968 64.429 14.376 ;
     RECT  62.243 73.488 64.501 73.512 ;
     RECT  64.46 74.88 64.501 74.904 ;
     RECT  63.155 75.936 64.501 76.104 ;
     RECT  64.501 73.488 64.547 76.104 ;
     RECT  63.565 77.136 64.865 77.16 ;
     RECT  64.547 75.504 64.969 76.104 ;
     RECT  64.969 75.504 65.297 76.296 ;
     RECT  65.297 75.792 65.333 76.296 ;
     RECT  64.547 73.488 65.621 74.328 ;
     RECT  64.109 2.832 65.725 11.544 ;
     RECT  62.104 12.816 65.725 12.84 ;
     RECT  64.109 1.728 65.869 1.752 ;
     RECT  65.725 2.832 65.869 12.84 ;
     RECT  65.869 1.728 66.229 12.84 ;
     RECT  65.173 80.88 66.629 80.904 ;
     RECT  65.621 73.488 66.769 74.28 ;
     RECT  65.333 75.936 66.769 76.296 ;
     RECT  66.769 72.96 66.805 74.28 ;
     RECT  66.769 75.504 66.805 76.296 ;
     RECT  66.805 72.96 66.913 76.296 ;
     RECT  66.913 72.96 67.129 76.344 ;
     RECT  66.229 1.728 67.208 12.936 ;
     RECT  64.429 13.968 67.208 14.472 ;
     RECT  67.129 23.328 67.208 23.352 ;
     RECT  62.104 38.448 67.208 38.472 ;
     RECT  62.104 59.712 67.208 60.408 ;
     RECT  67.129 72.768 67.208 76.344 ;
     RECT  67.208 1.728 67.484 78.852 ;
     RECT  67.484 1.728 67.504 79.272 ;
     RECT  67.504 79.248 67.571 79.272 ;
     RECT  67.504 13.968 67.645 15.384 ;
     RECT  67.504 72.768 68.357 76.344 ;
     RECT  68.357 72.768 68.465 75.96 ;
     RECT  67.504 1.728 68.645 12.888 ;
     RECT  67.645 13.968 68.857 15 ;
     RECT  68.465 72.96 68.861 75.96 ;
     RECT  68.677 79.776 68.861 79.8 ;
     RECT  68.821 78.096 68.965 78.12 ;
     RECT  68.861 75.792 69.011 75.96 ;
     RECT  68.645 2.832 69.068 12.888 ;
     RECT  68.857 13.968 69.068 15.432 ;
     RECT  69.068 2.832 69.155 15.432 ;
     RECT  69.109 21.936 69.493 21.96 ;
     RECT  68.861 72.96 69.509 74.664 ;
     RECT  69.145 24.864 69.836 24.888 ;
     RECT  68.965 77.568 69.865 78.12 ;
     RECT  67.504 23.328 69.877 23.832 ;
     RECT  69.836 24.864 69.877 25.416 ;
     RECT  69.155 2.832 69.893 12.888 ;
     RECT  67.504 16.656 69.901 16.68 ;
     RECT  69.877 23.328 69.923 25.416 ;
     RECT  69.836 79.248 69.923 79.272 ;
     RECT  69.923 23.808 69.964 25.08 ;
     RECT  69.865 76.848 70.013 78.12 ;
     RECT  70.013 76.848 70.157 77.592 ;
     RECT  69.901 16.656 70.364 16.824 ;
     RECT  70.364 16.656 70.451 17.592 ;
     RECT  69.509 73.632 70.513 74.664 ;
     RECT  69.011 75.792 70.513 75.816 ;
     RECT  70.513 73.632 70.657 75.816 ;
     RECT  69.155 13.968 70.729 15.432 ;
     RECT  70.657 73.632 71.125 75.864 ;
     RECT  71.077 79.2 71.237 79.224 ;
     RECT  69.893 2.784 71.365 12.888 ;
     RECT  71.365 2.736 71.557 12.888 ;
     RECT  70.729 13.968 71.557 15.48 ;
     RECT  69.964 23.808 71.989 23.832 ;
     RECT  69.964 25.056 71.989 25.08 ;
     RECT  70.451 16.656 72.169 16.824 ;
     RECT  72.188 79.248 72.275 79.272 ;
     RECT  71.557 2.736 72.277 15.48 ;
     RECT  72.169 16.656 72.277 17.64 ;
     RECT  68.645 1.728 72.421 1.752 ;
     RECT  72.277 2.736 72.421 17.64 ;
     RECT  71.125 73.296 72.421 75.864 ;
     RECT  72.421 1.728 72.608 17.64 ;
     RECT  72.325 18.96 72.608 18.984 ;
     RECT  69.493 21.936 72.608 22.008 ;
     RECT  71.989 23.808 72.608 25.08 ;
     RECT  71.521 26.208 72.608 26.232 ;
     RECT  67.504 38.448 72.608 38.472 ;
     RECT  67.504 59.712 72.608 60.408 ;
     RECT  72.421 73.056 72.608 75.864 ;
     RECT  70.157 76.944 72.608 77.592 ;
     RECT  72.608 1.728 72.904 78.852 ;
     RECT  72.904 2.784 73.001 16.824 ;
     RECT  72.904 23.184 73.001 24.984 ;
     RECT  73.001 2.832 73.187 16.824 ;
     RECT  73.001 24.768 73.397 24.984 ;
     RECT  73.321 79.248 73.475 79.272 ;
     RECT  73.187 2.832 74.041 16.68 ;
     RECT  72.904 1.728 74.113 1.752 ;
     RECT  74.113 1.728 74.149 1.8 ;
     RECT  74.041 2.784 74.149 16.68 ;
     RECT  72.904 72.432 74.225 75.672 ;
     RECT  74.149 1.728 74.233 16.68 ;
     RECT  72.904 77.04 74.405 77.592 ;
     RECT  74.233 2.784 74.581 16.68 ;
     RECT  72.904 21.552 74.588 22.008 ;
     RECT  73.001 23.184 74.588 23.688 ;
     RECT  74.54 79.248 74.627 79.272 ;
     RECT  74.581 2.784 74.665 17.64 ;
     RECT  72.904 18.96 74.693 18.984 ;
     RECT  74.113 20.448 75.197 20.472 ;
     RECT  74.405 77.04 75.197 77.544 ;
     RECT  72.904 26.208 75.253 26.232 ;
     RECT  75.253 26.208 75.26 26.808 ;
     RECT  75.26 26.208 75.299 26.952 ;
     RECT  74.225 72.816 75.337 75.672 ;
     RECT  75.299 26.688 75.347 26.952 ;
     RECT  74.588 21.552 75.485 23.688 ;
     RECT  74.665 2.832 75.733 17.64 ;
     RECT  75.733 2.784 75.827 18.264 ;
     RECT  75.697 78.672 75.827 78.696 ;
     RECT  75.485 23.328 75.845 23.688 ;
     RECT  75.197 77.424 75.953 77.544 ;
     RECT  75.485 21.552 75.973 22.056 ;
     RECT  75.932 19.104 76.019 19.128 ;
     RECT  74.401 27.936 76.025 27.96 ;
     RECT  75.98 70.992 76.067 71.016 ;
     RECT  75.337 72.816 76.067 76.248 ;
     RECT  74.233 1.728 76.268 1.8 ;
     RECT  75.827 2.784 76.268 18.024 ;
     RECT  76.268 1.728 76.355 18.024 ;
     RECT  75.347 26.688 76.357 26.856 ;
     RECT  75.845 23.52 76.403 23.688 ;
     RECT  76.357 26.208 76.529 26.856 ;
     RECT  76.529 26.736 76.597 26.856 ;
     RECT  76.057 77.664 76.961 77.688 ;
     RECT  76.067 72.912 76.997 76.248 ;
     RECT  76.913 79.776 76.997 79.8 ;
     RECT  76.957 0.576 77.041 0.6 ;
     RECT  76.355 2.784 77.132 18.024 ;
     RECT  73.397 24.768 77.137 24.792 ;
     RECT  75.973 21.12 77.209 22.056 ;
     RECT  76.403 23.52 77.209 23.592 ;
     RECT  77.209 21.12 77.413 23.592 ;
     RECT  77.137 24.768 77.413 25.56 ;
     RECT  76.997 72.96 77.425 76.248 ;
     RECT  76.355 1.728 77.453 1.752 ;
     RECT  77.132 2.784 77.453 18.792 ;
     RECT  77.453 1.728 77.641 18.792 ;
     RECT  77.317 0.096 77.651 0.12 ;
     RECT  77.425 72.96 77.785 76.488 ;
     RECT  77.785 72.96 77.965 76.872 ;
     RECT  77.641 1.728 78.008 19.32 ;
     RECT  77.413 21.12 78.008 25.56 ;
     RECT  76.597 26.736 78.008 27.336 ;
     RECT  72.904 38.448 78.008 38.472 ;
     RECT  72.904 59.712 78.008 60.408 ;
     RECT  77.965 72.432 78.008 76.872 ;
     RECT  78.008 1.728 78.101 78.852 ;
     RECT  78.101 1.728 78.112 79.8 ;
     RECT  78.112 79.776 78.185 79.8 ;
     RECT  78.112 1.728 78.304 78.582 ;
     RECT  78.304 2.784 78.329 25.56 ;
     RECT  78.304 38.448 78.437 38.472 ;
     RECT  78.304 71.232 78.581 76.872 ;
     RECT  78.329 2.832 78.949 25.56 ;
     RECT  78.304 69.888 79.235 69.912 ;
     RECT  79.081 79.824 79.331 79.848 ;
     RECT  78.304 1.728 79.477 1.752 ;
     RECT  78.949 2.832 79.477 19.32 ;
     RECT  78.949 20.448 79.693 25.56 ;
     RECT  79.477 1.728 79.769 19.32 ;
     RECT  78.581 71.232 79.801 76.392 ;
     RECT  79.693 20.448 79.841 26.184 ;
     RECT  79.841 20.448 79.877 22.056 ;
     RECT  79.841 23.328 79.913 26.184 ;
     RECT  79.801 71.232 80.003 77.016 ;
     RECT  79.913 24.432 80.341 26.184 ;
     RECT  79.405 27.216 80.341 27.24 ;
     RECT  80.341 24.432 80.389 27.24 ;
     RECT  80.389 24.432 80.435 27.912 ;
     RECT  78.304 59.76 80.489 60.408 ;
     RECT  79.769 19.296 80.521 19.32 ;
     RECT  79.981 37.968 80.557 38.424 ;
     RECT  79.801 78.096 80.705 78.12 ;
     RECT  80.485 80.88 80.777 80.904 ;
     RECT  80.053 62.544 80.917 62.568 ;
     RECT  80.003 71.232 81.388 76.392 ;
     RECT  80.435 24.432 81.421 26.664 ;
     RECT  79.769 1.728 81.452 18.216 ;
     RECT  80.521 19.296 81.452 19.8 ;
     RECT  81.388 72.144 81.493 76.392 ;
     RECT  79.913 23.328 81.529 23.352 ;
     RECT  81.421 24.432 81.529 26.856 ;
     RECT  80.917 62.544 81.539 63.144 ;
     RECT  79.877 21.024 81.673 22.056 ;
     RECT  81.529 23.328 81.673 26.856 ;
     RECT  81.452 1.728 81.713 19.8 ;
     RECT  81.637 79.776 81.821 79.8 ;
     RECT  81.673 21.024 82.105 26.856 ;
     RECT  82.105 20.304 82.145 26.856 ;
     RECT  81.493 72.144 82.181 76.968 ;
     RECT  82.145 21.36 82.309 26.856 ;
     RECT  80.435 27.888 82.309 27.912 ;
     RECT  81.713 1.728 82.325 19.32 ;
     RECT  82.181 72.144 82.393 74.76 ;
     RECT  82.325 15.456 82.433 19.32 ;
     RECT  82.789 79.248 82.883 79.272 ;
     RECT  82.181 76.032 82.933 76.968 ;
     RECT  82.145 20.304 82.969 20.328 ;
     RECT  82.309 21.36 82.969 27.912 ;
     RECT  82.969 21.36 83.173 28.2 ;
     RECT  83.173 21.36 83.259 28.248 ;
     RECT  82.325 1.728 83.408 14.136 ;
     RECT  82.433 15.456 83.408 19.032 ;
     RECT  82.969 20.16 83.408 20.328 ;
     RECT  83.259 21.36 83.408 28.296 ;
     RECT  80.557 37.584 83.408 38.424 ;
     RECT  80.489 59.76 83.408 60.36 ;
     RECT  81.539 62.544 83.408 62.568 ;
     RECT  82.393 71.76 83.408 74.76 ;
     RECT  82.933 76.032 83.408 77.544 ;
     RECT  83.408 1.728 83.512 78.852 ;
     RECT  83.512 1.728 83.704 78.582 ;
     RECT  83.704 76.464 83.837 76.776 ;
     RECT  83.704 1.728 84.121 19.368 ;
     RECT  83.989 80.88 84.197 80.904 ;
     RECT  84.121 1.152 84.323 19.368 ;
     RECT  83.704 35.28 84.371 36.552 ;
     RECT  83.704 20.592 84.449 28.296 ;
     RECT  84.193 0.096 84.659 0.12 ;
     RECT  84.371 35.328 84.665 35.88 ;
     RECT  83.704 31.296 84.805 31.32 ;
     RECT  84.805 31.296 84.845 31.896 ;
     RECT  83.704 40.8 84.985 40.824 ;
     RECT  83.837 76.752 85.021 76.776 ;
     RECT  83.704 62.544 85.189 62.568 ;
     RECT  83.704 72.144 85.201 75.096 ;
     RECT  85.021 76.752 85.201 77.16 ;
     RECT  83.704 37.584 85.235 38.424 ;
     RECT  85.189 62.544 85.235 62.76 ;
     RECT  85.189 80.88 85.421 80.904 ;
     RECT  85.345 70.848 85.429 70.872 ;
     RECT  85.201 72.144 85.429 77.16 ;
     RECT  85.429 70.848 85.453 77.16 ;
     RECT  84.449 23.52 85.489 28.296 ;
     RECT  85.235 62.736 85.493 62.76 ;
     RECT  85.453 69.984 85.516 77.16 ;
     RECT  85.189 32.88 85.597 32.904 ;
     RECT  83.704 34.08 85.597 34.104 ;
     RECT  84.323 1.728 85.601 19.368 ;
     RECT  85.235 37.584 85.601 38.232 ;
     RECT  84.449 20.592 85.633 22.296 ;
     RECT  85.489 23.376 85.633 28.296 ;
     RECT  85.633 20.592 85.669 28.296 ;
     RECT  83.704 29.52 85.669 29.544 ;
     RECT  85.597 32.88 85.745 34.104 ;
     RECT  85.516 69.984 85.763 70.872 ;
     RECT  84.985 40.8 85.813 41.544 ;
     RECT  84.845 31.872 85.885 31.896 ;
     RECT  85.601 15.504 85.921 19.368 ;
     RECT  85.669 20.592 85.921 29.544 ;
     RECT  84.665 35.328 85.921 35.352 ;
     RECT  85.921 35.328 85.961 35.976 ;
     RECT  85.961 35.424 85.993 35.976 ;
     RECT  85.921 15.504 85.997 29.544 ;
     RECT  85.741 39.648 86.005 39.672 ;
     RECT  85.813 40.752 86.005 42.168 ;
     RECT  85.516 71.856 86.033 77.16 ;
     RECT  86.005 39.648 86.051 42.168 ;
     RECT  85.885 31.392 86.065 31.896 ;
     RECT  85.745 32.88 86.065 33.816 ;
     RECT  85.993 35.424 86.065 36.072 ;
     RECT  86.065 31.392 86.105 33.816 ;
     RECT  85.669 78.336 86.105 78.36 ;
     RECT  86.051 40.176 86.141 42.168 ;
     RECT  85.997 26.112 86.173 29.544 ;
     RECT  86.033 76.368 86.353 77.16 ;
     RECT  86.141 40.848 86.357 42.168 ;
     RECT  86.353 76.368 86.393 77.832 ;
     RECT  85.997 15.504 86.465 25.08 ;
     RECT  86.465 15.504 86.501 24.456 ;
     RECT  85.763 70.848 86.501 70.872 ;
     RECT  86.501 15.504 86.573 24.408 ;
     RECT  86.173 26.112 86.681 29.784 ;
     RECT  85.601 1.728 86.713 14.52 ;
     RECT  86.573 15.504 86.713 24.36 ;
     RECT  86.681 26.208 86.753 29.784 ;
     RECT  85.717 63.168 86.897 63.192 ;
     RECT  86.713 1.728 86.933 24.36 ;
     RECT  86.393 76.896 87.005 77.832 ;
     RECT  85.601 38.208 87.181 38.232 ;
     RECT  87.181 38.208 87.205 38.76 ;
     RECT  87.205 38.208 87.221 39.384 ;
     RECT  86.033 71.856 87.325 75.288 ;
     RECT  86.357 40.848 87.397 40.872 ;
     RECT  87.253 43.248 87.397 43.272 ;
     RECT  86.105 31.392 87.401 31.416 ;
     RECT  86.065 35.424 87.433 36.12 ;
     RECT  86.105 32.448 87.685 33.816 ;
     RECT  86.753 26.256 87.733 29.784 ;
     RECT  87.721 30.816 87.733 30.84 ;
     RECT  87.221 38.688 87.757 39.384 ;
     RECT  87.397 40.848 87.757 41.064 ;
     RECT  86.389 79.2 87.761 79.224 ;
     RECT  87.733 26.256 87.805 30.84 ;
     RECT  87.749 0.576 87.833 0.6 ;
     RECT  86.933 20.112 87.833 24.36 ;
     RECT  86.821 70.752 87.833 70.776 ;
     RECT  87.325 71.856 87.833 75.816 ;
     RECT  87.685 32.448 87.925 34.344 ;
     RECT  87.433 35.424 87.925 37.032 ;
     RECT  87.757 38.688 87.973 41.064 ;
     RECT  86.357 42.144 87.973 42.168 ;
     RECT  87.925 32.448 88.309 37.032 ;
     RECT  87.833 75.792 88.405 75.816 ;
     RECT  87.005 76.896 88.405 77.496 ;
     RECT  87.805 26.256 88.549 30.744 ;
     RECT  88.309 32.448 88.765 37.608 ;
     RECT  88.721 79.776 88.805 79.8 ;
     RECT  86.933 1.728 88.808 19.032 ;
     RECT  87.833 20.112 88.808 20.712 ;
     RECT  87.833 21.792 88.808 24.36 ;
     RECT  88.549 26.208 88.808 30.744 ;
     RECT  88.765 32.304 88.808 37.608 ;
     RECT  87.973 38.688 88.808 42.168 ;
     RECT  87.397 43.248 88.808 43.896 ;
     RECT  85.189 51.648 88.808 51.672 ;
     RECT  83.704 59.76 88.808 60.36 ;
     RECT  87.253 69.552 88.808 69.576 ;
     RECT  87.833 71.856 88.808 74.712 ;
     RECT  88.405 75.792 88.808 77.496 ;
     RECT  88.808 1.728 88.912 78.852 ;
     RECT  88.912 1.728 89.104 78.582 ;
     RECT  89.104 35.424 89.273 35.832 ;
     RECT  89.104 43.776 89.417 43.896 ;
     RECT  89.104 38.16 89.555 39.384 ;
     RECT  89.104 1.728 89.785 30.696 ;
     RECT  89.104 36.96 89.813 37.08 ;
     RECT  89.104 68.784 89.836 69.576 ;
     RECT  89.104 34.128 90.029 34.152 ;
     RECT  89.555 38.16 90.029 38.76 ;
     RECT  89.893 79.2 90.065 79.224 ;
     RECT  89.104 72.336 90.083 77.112 ;
     RECT  89.273 35.808 90.137 35.832 ;
     RECT  90.083 72.528 90.245 77.112 ;
     RECT  89.785 1.728 90.317 24.648 ;
     RECT  90.245 72.528 90.323 76.392 ;
     RECT  89.104 40.416 90.353 40.968 ;
     RECT  89.836 69.552 90.353 69.576 ;
     RECT  90.323 72.528 90.497 75.96 ;
     RECT  89.785 25.728 90.529 30.696 ;
     RECT  89.104 31.776 90.529 32.904 ;
     RECT  90.029 38.4 90.641 38.76 ;
     RECT  90.497 72.72 90.641 75.96 ;
     RECT  90.529 35.856 90.673 35.88 ;
     RECT  89.813 36.96 90.673 36.984 ;
     RECT  90.641 75.84 90.821 75.96 ;
     RECT  90.641 72.72 90.857 74.712 ;
     RECT  90.317 1.728 90.893 21.288 ;
     RECT  90.673 35.856 90.925 36.984 ;
     RECT  90.457 71.232 90.929 71.256 ;
     RECT  90.925 35.856 90.965 37.08 ;
     RECT  90.317 22.32 91.069 24.648 ;
     RECT  90.529 25.728 91.069 32.904 ;
     RECT  90.965 35.856 91.073 36.072 ;
     RECT  90.353 40.608 91.073 40.968 ;
     RECT  91.069 22.32 91.109 32.904 ;
     RECT  90.853 80.4 91.139 80.424 ;
     RECT  91.109 25.056 91.177 32.904 ;
     RECT  89.417 43.776 91.177 43.8 ;
     RECT  91.177 25.056 91.217 33.096 ;
     RECT  90.857 73.008 91.289 74.712 ;
     RECT  91.217 25.056 91.325 30.312 ;
     RECT  91.177 43.296 91.388 43.8 ;
     RECT  91.073 40.944 91.433 40.968 ;
     RECT  90.961 42.144 91.433 42.168 ;
     RECT  91.388 43.296 91.433 43.848 ;
     RECT  91.433 43.824 91.475 43.848 ;
     RECT  90.889 34.224 91.541 34.248 ;
     RECT  91.217 31.776 91.649 33.096 ;
     RECT  90.893 1.728 91.933 20.856 ;
     RECT  91.289 73.008 92.005 74.664 ;
     RECT  91.933 1.728 92.113 21.24 ;
     RECT  91.109 22.32 92.113 23.592 ;
     RECT  90.965 37.056 92.221 37.08 ;
     RECT  91.645 75.744 92.245 75.768 ;
     RECT  91.073 36.048 92.293 36.072 ;
     RECT  92.221 37.056 92.293 37.368 ;
     RECT  91.325 26.496 92.329 30.312 ;
     RECT  92.113 1.728 92.509 23.592 ;
     RECT  92.149 44.448 92.533 44.472 ;
     RECT  92.293 36.048 92.545 37.368 ;
     RECT  90.641 38.4 92.545 38.424 ;
     RECT  92.329 26.016 92.581 30.312 ;
     RECT  92.245 75.744 92.617 76.2 ;
     RECT  92.533 43.728 92.62 44.472 ;
     RECT  92.62 44.448 92.729 44.472 ;
     RECT  92.005 72.864 92.761 74.664 ;
     RECT  92.617 75.744 92.761 76.248 ;
     RECT  92.041 77.664 92.761 77.688 ;
     RECT  91.649 32.064 92.837 33.096 ;
     RECT  92.581 26.016 92.869 30.984 ;
     RECT  92.761 75.744 92.869 77.688 ;
     RECT  92.761 72.432 92.917 74.664 ;
     RECT  92.917 72.432 93.013 74.616 ;
     RECT  93.013 71.28 93.097 74.616 ;
     RECT  92.869 25.776 93.233 30.984 ;
     RECT  92.905 42.192 93.409 42.216 ;
     RECT  92.509 1.728 93.481 24.504 ;
     RECT  93.404 79.248 93.491 79.272 ;
     RECT  93.481 0.576 93.565 0.6 ;
     RECT  92.869 75.648 93.768 78.072 ;
     RECT  92.837 32.064 93.877 32.904 ;
     RECT  93.877 32.064 93.949 33.432 ;
     RECT  93.193 34.896 93.949 34.92 ;
     RECT  93.409 42.192 93.949 42.36 ;
     RECT  91.429 45.552 94.021 45.576 ;
     RECT  93.877 47.904 94.021 47.928 ;
     RECT  93.517 68.928 94.021 68.952 ;
     RECT  92.005 70.128 94.021 70.152 ;
     RECT  92.545 36.048 94.069 38.424 ;
     RECT  93.949 41.952 94.069 42.36 ;
     RECT  89.104 59.76 94.069 60.36 ;
     RECT  93.233 25.776 94.201 26.808 ;
     RECT  93.481 1.728 94.208 24.744 ;
     RECT  94.201 25.776 94.208 26.856 ;
     RECT  93.233 27.936 94.208 30.984 ;
     RECT  93.949 32.064 94.208 34.92 ;
     RECT  94.069 36.048 94.208 38.712 ;
     RECT  93.337 40.224 94.208 40.248 ;
     RECT  94.069 41.952 94.208 43.32 ;
     RECT  94.021 44.976 94.208 45.576 ;
     RECT  94.021 47.28 94.208 47.928 ;
     RECT  89.104 51.648 94.208 51.672 ;
     RECT  94.069 59.472 94.208 60.36 ;
     RECT  94.069 66.768 94.208 66.792 ;
     RECT  92.869 67.824 94.208 67.848 ;
     RECT  94.021 68.928 94.208 70.152 ;
     RECT  93.097 71.808 94.208 74.616 ;
     RECT  93.768 75.648 94.208 78.12 ;
     RECT  94.208 1.728 94.312 78.852 ;
     RECT  94.312 1.728 94.504 78.648 ;
     RECT  94.093 80.4 94.597 80.424 ;
     RECT  94.504 69.552 94.601 69.72 ;
     RECT  94.597 80.4 94.739 80.904 ;
     RECT  94.504 1.728 94.781 40.296 ;
     RECT  94.781 1.728 95.105 37.368 ;
     RECT  94.504 51.648 95.105 52.488 ;
     RECT  95.105 51.792 95.123 52.488 ;
     RECT  94.504 41.952 95.171 45 ;
     RECT  94.504 72.48 95.171 78.648 ;
     RECT  94.453 0.096 95.213 0.12 ;
     RECT  95.171 72.48 95.213 75.384 ;
     RECT  95.171 76.608 95.219 78.648 ;
     RECT  95.105 25.68 95.285 37.368 ;
     RECT  95.171 41.952 95.285 41.976 ;
     RECT  94.781 38.688 95.497 40.296 ;
     RECT  95.219 76.608 95.645 77.544 ;
     RECT  95.213 72.48 95.749 74.856 ;
     RECT  95.497 38.688 95.789 41.016 ;
     RECT  95.353 79.824 95.843 79.848 ;
     RECT  95.749 72.288 95.897 74.856 ;
     RECT  95.645 77.328 95.897 77.544 ;
     RECT  94.601 69.696 95.941 69.72 ;
     RECT  95.929 71.28 95.941 71.304 ;
     RECT  95.941 69.696 96.013 71.304 ;
     RECT  95.171 43.248 96.037 45 ;
     RECT  95.123 52.464 96.145 52.488 ;
     RECT  96.013 69.696 96.149 70.68 ;
     RECT  95.105 1.728 96.181 24.648 ;
     RECT  95.285 25.68 96.181 32.568 ;
     RECT  96.145 52.464 96.185 53.304 ;
     RECT  96.181 1.728 96.289 32.568 ;
     RECT  95.285 33.648 96.289 37.368 ;
     RECT  96.037 43.248 96.289 45.624 ;
     RECT  96.289 1.728 96.293 37.368 ;
     RECT  94.504 49.008 96.365 49.032 ;
     RECT  95.789 39.36 96.433 41.016 ;
     RECT  96.289 43.104 96.613 45.624 ;
     RECT  95.713 50.4 96.613 50.424 ;
     RECT  96.565 0.096 96.707 0.12 ;
     RECT  95.897 73.248 96.716 74.856 ;
     RECT  96.217 75.888 96.716 75.912 ;
     RECT  96.613 42.768 96.761 45.624 ;
     RECT  96.433 39.36 96.793 41.544 ;
     RECT  96.293 1.776 96.803 37.368 ;
     RECT  96.716 73.248 96.803 75.912 ;
     RECT  96.793 39.216 96.853 41.544 ;
     RECT  96.613 50.4 96.865 51.288 ;
     RECT  96.865 50.4 96.941 51.912 ;
     RECT  96.908 79.248 96.995 79.272 ;
     RECT  96.853 38.448 97.045 41.544 ;
     RECT  96.761 42.768 97.045 43.896 ;
     RECT  94.504 47.28 97.181 47.304 ;
     RECT  96.803 73.248 97.193 74.472 ;
     RECT  97.181 46.704 97.235 47.304 ;
     RECT  97.045 38.448 97.301 43.896 ;
     RECT  96.803 75.84 97.333 75.912 ;
     RECT  95.897 77.328 97.333 77.352 ;
     RECT  97.193 73.248 97.405 74.088 ;
     RECT  97.333 75.84 97.453 77.352 ;
     RECT  96.577 55.248 97.477 55.272 ;
     RECT  97.333 56.496 97.477 56.52 ;
     RECT  96.149 70.512 97.513 70.536 ;
     RECT  97.477 55.248 97.523 56.52 ;
     RECT  97.513 70.08 97.571 70.536 ;
     RECT  97.484 71.568 97.571 71.592 ;
     RECT  97.453 75.888 97.585 77.352 ;
     RECT  97.571 70.08 97.597 70.104 ;
     RECT  97.523 55.248 97.697 56.472 ;
     RECT  96.941 50.736 97.769 51.912 ;
     RECT  95.929 68.256 97.868 68.28 ;
     RECT  97.868 48.768 97.873 48.792 ;
     RECT  96.185 53.28 97.873 53.304 ;
     RECT  97.868 68.256 97.873 68.904 ;
     RECT  97.405 72.96 97.873 74.088 ;
     RECT  96.803 1.776 97.901 35.544 ;
     RECT  96.761 44.976 97.957 45.624 ;
     RECT  97.235 46.704 97.957 46.92 ;
     RECT  97.873 48.432 97.957 48.792 ;
     RECT  97.873 53.28 97.973 53.592 ;
     RECT  97.769 50.736 97.985 51.288 ;
     RECT  97.873 68.256 98.003 69.144 ;
     RECT  97.957 48.432 98.005 49.032 ;
     RECT  97.585 75.888 98.021 77.976 ;
     RECT  97.973 52.464 98.057 53.592 ;
     RECT  97.957 44.976 98.065 46.92 ;
     RECT  97.901 1.728 98.197 35.544 ;
     RECT  96.803 36.864 98.197 37.368 ;
     RECT  98.149 80.88 98.273 80.904 ;
     RECT  98.197 1.728 98.341 37.368 ;
     RECT  97.697 56.256 98.381 56.472 ;
     RECT  98.065 46.368 98.521 46.92 ;
     RECT  98.021 75.888 98.521 77.688 ;
     RECT  98.005 48.432 98.557 49.56 ;
     RECT  97.301 39.504 98.593 43.896 ;
     RECT  98.065 44.976 98.593 45.096 ;
     RECT  97.873 71.616 98.597 74.088 ;
     RECT  98.557 48.384 98.665 49.56 ;
     RECT  98.521 46.368 98.732 46.968 ;
     RECT  98.665 48.384 98.732 50.184 ;
     RECT  98.341 1.728 98.737 37.416 ;
     RECT  97.301 38.448 98.737 38.472 ;
     RECT  98.057 53.28 98.737 53.592 ;
     RECT  98.737 1.728 98.773 38.472 ;
     RECT  98.593 39.504 98.773 45.096 ;
     RECT  98.732 58.128 98.773 58.152 ;
     RECT  98.597 71.904 98.773 74.088 ;
     RECT  98.521 75.264 98.773 77.688 ;
     RECT  98.737 62.736 98.881 62.76 ;
     RECT  97.985 51.216 98.917 51.288 ;
     RECT  98.773 1.728 98.921 45.096 ;
     RECT  98.732 46.368 99.169 50.184 ;
     RECT  97.909 65.664 99.169 65.688 ;
     RECT  98.381 56.448 99.385 56.472 ;
     RECT  98.003 68.256 99.421 68.28 ;
     RECT  98.917 51.216 99.493 51.912 ;
     RECT  99.301 79.776 99.497 79.8 ;
     RECT  99.169 55.44 99.529 55.464 ;
     RECT  99.385 56.448 99.529 56.568 ;
     RECT  98.921 2.148 99.565 45.096 ;
     RECT  99.169 46.176 99.565 50.184 ;
     RECT  99.565 2.148 99.608 50.184 ;
     RECT  99.493 51.216 99.608 51.96 ;
     RECT  98.737 53.28 99.608 54.168 ;
     RECT  99.529 55.44 99.608 56.568 ;
     RECT  98.773 57.888 99.608 58.152 ;
     RECT  94.504 59.472 99.608 60.36 ;
     RECT  98.881 62.736 99.608 63.096 ;
     RECT  99.169 64.944 99.608 65.688 ;
     RECT  99.421 68.112 99.608 68.28 ;
     RECT  98.593 69.504 99.608 69.528 ;
     RECT  98.593 70.512 99.608 70.536 ;
     RECT  98.773 71.904 99.608 77.688 ;
     RECT  99.608 2.148 99.712 78.852 ;
     RECT  99.712 2.208 99.904 78.852 ;
     RECT  99.349 0.096 100.019 0.12 ;
     RECT  99.904 61.872 100.037 63.096 ;
     RECT  100.141 0.576 100.225 0.6 ;
     RECT  99.904 59.232 100.397 60.36 ;
     RECT  99.904 77.76 100.493 78.852 ;
     RECT  99.904 64.608 100.499 66.504 ;
     RECT  100.493 77.76 100.577 79.224 ;
     RECT  100.693 1.152 100.835 1.176 ;
     RECT  99.904 2.208 100.837 54.36 ;
     RECT  100.499 65.664 100.897 66.504 ;
     RECT  99.904 68.112 100.969 68.376 ;
     RECT  99.904 69.504 100.969 76.488 ;
     RECT  100.969 68.112 100.973 76.488 ;
     RECT  100.397 59.232 101.005 59.784 ;
     RECT  100.973 68.256 101.005 76.488 ;
     RECT  100.577 77.76 101.005 78.312 ;
     RECT  99.904 55.44 101.041 55.992 ;
     RECT  99.904 56.976 101.041 58.008 ;
     RECT  100.837 2.16 101.045 54.36 ;
     RECT  101.005 68.256 101.081 78.312 ;
     RECT  101.045 30.72 101.113 54.36 ;
     RECT  101.041 55.44 101.113 58.008 ;
     RECT  100.499 64.608 101.117 64.632 ;
     RECT  101.113 30.72 101.461 58.008 ;
     RECT  101.005 59.184 101.461 59.784 ;
     RECT  100.037 61.872 101.516 61.896 ;
     RECT  100.037 63.072 101.516 63.096 ;
     RECT  101.045 2.16 101.585 29.736 ;
     RECT  101.461 30.72 101.761 59.784 ;
     RECT  101.516 61.872 101.761 63.096 ;
     RECT  100.897 65.664 101.765 66.888 ;
     RECT  101.765 66.864 101.833 66.888 ;
     RECT  101.701 79.776 101.869 79.8 ;
     RECT  101.869 79.776 101.873 80.424 ;
     RECT  101.081 68.256 101.945 68.856 ;
     RECT  101.081 70.032 102.053 77.736 ;
     RECT  101.833 66.864 102.089 67.032 ;
     RECT  101.585 2.208 102.121 29.736 ;
     RECT  101.761 30.72 102.121 60.456 ;
     RECT  102.053 70.032 102.121 71.832 ;
     RECT  102.053 72.912 102.373 77.736 ;
     RECT  101.761 61.872 102.413 63.192 ;
     RECT  102.413 62.544 102.481 63.192 ;
     RECT  101.765 65.664 102.557 65.832 ;
     RECT  102.121 2.208 102.565 60.456 ;
     RECT  102.557 65.808 102.593 65.832 ;
     RECT  102.565 2.208 102.949 61.08 ;
     RECT  102.901 0.096 103.043 0.12 ;
     RECT  102.949 1.728 103.069 61.08 ;
     RECT  101.945 68.352 103.093 68.856 ;
     RECT  102.121 69.84 103.093 71.832 ;
     RECT  102.373 72.912 103.093 78.216 ;
     RECT  102.089 67.008 103.129 67.032 ;
     RECT  103.093 68.352 103.129 78.216 ;
     RECT  103.129 67.008 103.187 78.216 ;
     RECT  102.481 62.544 103.235 63.48 ;
     RECT  103.187 67.152 103.349 78.216 ;
     RECT  103.349 67.536 103.453 78.216 ;
     RECT  103.069 1.728 103.457 38.76 ;
     RECT  103.453 67.536 103.493 78.456 ;
     RECT  103.493 72.384 103.571 78.456 ;
     RECT  103.571 72.432 103.601 78.456 ;
     RECT  103.235 62.544 103.637 63.24 ;
     RECT  103.493 67.536 103.637 68.712 ;
     RECT  101.873 80.4 103.849 80.424 ;
     RECT  103.561 65.952 103.853 65.976 ;
     RECT  103.637 62.64 103.925 63.24 ;
     RECT  103.457 38.736 103.997 38.76 ;
     RECT  103.069 39.744 104.029 61.08 ;
     RECT  103.849 79.872 104.099 80.424 ;
     RECT  103.601 72.432 104.641 78.168 ;
     RECT  103.457 1.728 104.677 37.656 ;
     RECT  103.637 68.688 104.713 68.712 ;
     RECT  104.677 1.344 104.821 37.656 ;
     RECT  104.099 79.872 104.821 79.896 ;
     RECT  104.821 0.432 105.008 37.656 ;
     RECT  104.029 39.744 105.008 61.608 ;
     RECT  103.925 63.168 105.008 63.24 ;
     RECT  103.637 67.536 105.008 67.56 ;
     RECT  104.713 68.64 105.008 68.712 ;
     RECT  103.493 69.984 105.008 71.304 ;
     RECT  104.641 72.432 105.008 78.648 ;
     RECT  105.008 0.432 105.304 78.852 ;
     RECT  105.304 39.36 105.365 39.864 ;
     RECT  105.304 76.704 105.397 78.852 ;
     RECT  104.821 79.824 105.397 79.896 ;
     RECT  105.304 0.432 105.443 21.624 ;
     RECT  105.443 21.216 105.473 21.624 ;
     RECT  105.304 62.976 105.509 63.048 ;
     RECT  105.304 74.4 105.509 75.528 ;
     RECT  105.304 46.848 105.545 54.648 ;
     RECT  105.304 55.728 105.545 61.896 ;
     RECT  105.443 0.432 105.685 20.136 ;
     RECT  105.545 58.128 105.725 61.896 ;
     RECT  105.685 0.144 105.857 20.136 ;
     RECT  105.857 0.096 105.941 20.136 ;
     RECT  105.941 0.144 106.211 20.136 ;
     RECT  105.304 22.752 106.477 30.36 ;
     RECT  105.304 31.392 106.477 38.232 ;
     RECT  106.397 80.88 106.481 80.904 ;
     RECT  106.477 22.752 106.513 38.232 ;
     RECT  105.365 39.36 106.513 39.384 ;
     RECT  105.304 41.184 106.513 45.528 ;
     RECT  105.545 46.848 106.513 50.28 ;
     RECT  105.545 51.408 106.513 54.648 ;
     RECT  105.545 55.728 106.513 57.144 ;
     RECT  105.509 63.024 106.513 63.048 ;
     RECT  105.304 64.416 106.513 65.112 ;
     RECT  105.304 66.192 106.513 66.216 ;
     RECT  105.304 67.824 106.513 67.848 ;
     RECT  105.304 71.904 106.513 72.168 ;
     RECT  105.509 74.4 106.513 74.904 ;
     RECT  106.211 0.528 106.549 20.136 ;
     RECT  105.473 21.36 106.549 21.624 ;
     RECT  106.513 22.752 106.549 39.384 ;
     RECT  106.513 40.704 106.549 45.768 ;
     RECT  105.725 58.464 106.549 61.896 ;
     RECT  106.513 63.024 106.549 68.76 ;
     RECT  105.304 70.08 106.549 70.104 ;
     RECT  106.513 71.664 106.549 72.168 ;
     RECT  106.513 74.16 106.549 74.904 ;
     RECT  106.549 58.464 106.585 72.168 ;
     RECT  106.549 73.728 106.585 75.096 ;
     RECT  105.397 76.704 106.585 79.896 ;
     RECT  106.549 0.528 106.883 39.384 ;
     RECT  106.883 1.104 107.125 39.384 ;
     RECT  106.549 40.512 107.125 45.768 ;
     RECT  106.513 46.848 107.125 57.144 ;
     RECT  106.585 58.464 107.125 79.896 ;
     RECT  107.125 1.104 107.964 79.896 ;
    LAYER M5 ;
     RECT  1.152 0.016 106.872 0.467 ;
     RECT  106.512 0.467 106.872 0.563 ;
     RECT  1.152 0.467 105.432 0.611 ;
     RECT  1.488 0.611 105.432 1.525 ;
     RECT  106.512 0.563 106.536 1.525 ;
     RECT  1.488 1.525 106.536 1.763 ;
     RECT  20.832 1.763 20.856 1.811 ;
     RECT  40.2 1.763 41.16 1.811 ;
     RECT  50.64 1.763 52.248 1.811 ;
     RECT  74.16 1.763 74.472 1.811 ;
     RECT  75.744 1.763 76.344 1.811 ;
     RECT  92.208 1.763 92.232 1.811 ;
     RECT  34.176 1.763 35.112 1.859 ;
     RECT  51 1.811 52.248 1.859 ;
     RECT  83.328 1.763 83.712 2.003 ;
     RECT  29.4 1.763 30.696 2.243 ;
     RECT  37.008 1.763 37.032 2.243 ;
     RECT  85.872 1.763 85.896 2.291 ;
     RECT  1.488 1.763 3.384 2.339 ;
     RECT  88.32 1.763 89.112 2.725 ;
     RECT  93.456 1.763 105.624 2.725 ;
     RECT  67.2 1.763 67.704 2.773 ;
     RECT  71.376 2.725 71.4 2.773 ;
     RECT  72.432 1.763 72.912 2.773 ;
     RECT  74.16 1.811 74.184 2.773 ;
     RECT  76.32 1.811 76.344 2.773 ;
     RECT  77.472 1.763 78.312 2.773 ;
     RECT  24 1.763 26.76 3.011 ;
     RECT  79.488 1.763 79.512 3.013 ;
     RECT  13.2 1.763 13.512 3.061 ;
     RECT  87.744 2.725 89.112 3.205 ;
     RECT  90.144 2.821 90.168 3.205 ;
     RECT  74.064 2.773 74.616 3.253 ;
     RECT  75.744 2.773 78.312 3.253 ;
     RECT  61.8 1.763 62.112 3.301 ;
     RECT  93.024 2.725 105.624 3.397 ;
     RECT  10.08 2.821 10.104 3.443 ;
     RECT  74.064 3.253 78.312 3.493 ;
     RECT  74.016 3.493 78.312 3.541 ;
     RECT  34.8 1.859 35.112 3.589 ;
     RECT  92.64 3.397 105.624 3.685 ;
     RECT  61.68 3.301 62.112 3.877 ;
     RECT  87.744 3.205 90.6 3.877 ;
     RECT  22.032 2.821 22.056 3.925 ;
     RECT  25.968 3.011 26.76 3.925 ;
     RECT  40.2 1.811 40.512 3.925 ;
     RECT  87.744 3.877 90.696 3.925 ;
     RECT  91.728 3.685 105.624 3.925 ;
     RECT  5.04 3.397 5.064 3.971 ;
     RECT  12.768 3.061 13.512 3.971 ;
     RECT  21.936 3.925 22.056 3.971 ;
     RECT  7.8 1.763 8.112 4.117 ;
     RECT  87.696 3.925 105.624 4.261 ;
     RECT  21.936 3.971 21.96 4.403 ;
     RECT  14.832 4.117 14.856 4.501 ;
     RECT  69.936 2.773 72.912 4.501 ;
     RECT  80.976 3.925 81 4.501 ;
     RECT  87.072 4.261 105.624 4.501 ;
     RECT  1.488 2.339 2.712 4.595 ;
     RECT  25.968 3.925 26.808 4.595 ;
     RECT  34.176 3.589 35.112 4.595 ;
     RECT  40.08 3.925 40.512 4.595 ;
     RECT  61.488 3.877 62.112 4.595 ;
     RECT  66.72 2.773 67.704 4.595 ;
     RECT  26.064 4.595 26.808 4.643 ;
     RECT  69.936 4.501 73.032 4.643 ;
     RECT  74.016 3.541 78.456 4.643 ;
     RECT  49.68 2.773 49.704 4.645 ;
     RECT  26.736 4.643 26.808 4.693 ;
     RECT  46.992 4.645 47.016 4.787 ;
     RECT  49.584 4.645 49.704 4.787 ;
     RECT  29.4 2.243 29.712 4.885 ;
     RECT  36.432 4.117 36.456 5.027 ;
     RECT  67.104 4.595 67.512 5.027 ;
     RECT  7.8 4.117 8.52 5.029 ;
     RECT  45.6 1.763 45.912 5.029 ;
     RECT  13.2 3.971 13.512 5.077 ;
     RECT  80.976 4.501 81.72 5.077 ;
     RECT  83.4 2.003 83.712 5.077 ;
     RECT  85.968 3.205 85.992 5.077 ;
     RECT  14.832 4.501 15.192 5.171 ;
     RECT  71.28 4.643 71.4 5.171 ;
     RECT  15.168 5.171 15.192 5.173 ;
     RECT  16.272 4.501 16.296 5.173 ;
     RECT  21.12 4.501 21.144 5.173 ;
     RECT  71.376 5.171 71.4 5.219 ;
     RECT  85.584 5.077 85.992 5.221 ;
     RECT  26.736 4.693 27.144 5.267 ;
     RECT  65.664 3.925 65.688 5.267 ;
     RECT  79.488 3.013 79.704 5.267 ;
     RECT  80.928 5.077 83.712 5.317 ;
     RECT  84.912 5.221 85.992 5.363 ;
     RECT  80.16 5.317 83.712 5.555 ;
     RECT  72.432 4.643 73.032 5.605 ;
     RECT  15.168 5.173 16.296 5.701 ;
     RECT  40.2 4.595 40.512 5.701 ;
     RECT  41.616 4.933 41.64 5.701 ;
     RECT  6.48 4.357 6.504 5.747 ;
     RECT  19.92 4.549 19.944 5.747 ;
     RECT  26.784 5.267 27.144 5.747 ;
     RECT  41.616 5.701 42.072 5.747 ;
     RECT  74.688 4.643 78.456 5.749 ;
     RECT  81.024 5.555 83.712 5.749 ;
     RECT  27.12 5.747 27.144 5.795 ;
     RECT  74.688 5.749 79.032 5.795 ;
     RECT  39.84 5.701 40.512 5.941 ;
     RECT  81.024 5.749 83.928 6.083 ;
     RECT  75.648 5.795 79.032 6.179 ;
     RECT  45.6 5.029 46.008 6.181 ;
     RECT  21.024 5.173 21.144 6.277 ;
     RECT  39.84 5.941 41.016 6.323 ;
     RECT  20.208 6.277 21.144 6.419 ;
     RECT  81.024 6.083 83.712 6.467 ;
     RECT  13.008 5.077 13.512 6.469 ;
     RECT  42.048 5.747 42.072 6.517 ;
     RECT  44.4 6.037 44.424 6.563 ;
     RECT  87.072 4.501 106.008 6.611 ;
     RECT  40.2 6.323 41.016 6.659 ;
     RECT  21.024 6.419 21.144 6.755 ;
     RECT  85.584 5.363 85.992 6.805 ;
     RECT  87.072 6.611 89.448 6.805 ;
     RECT  3.936 5.653 3.96 6.851 ;
     RECT  81.36 6.467 83.712 6.899 ;
     RECT  84.912 6.805 89.448 7.045 ;
     RECT  15.168 5.701 16.584 7.093 ;
     RECT  24 3.011 24.456 7.139 ;
     RECT  45.6 6.181 46.104 7.139 ;
     RECT  84.72 7.045 89.448 7.187 ;
     RECT  75.648 6.179 78.888 7.189 ;
     RECT  74.688 7.189 78.888 7.379 ;
     RECT  7.8 5.029 8.856 7.427 ;
     RECT  75.648 7.379 78.888 7.475 ;
     RECT  12.528 6.469 13.512 7.523 ;
     RECT  26.784 6.805 26.808 7.619 ;
     RECT  76.944 7.475 78.888 7.619 ;
     RECT  80.304 7.525 80.328 7.621 ;
     RECT  69.12 6.229 69.144 7.717 ;
     RECT  70.368 5.653 70.392 7.717 ;
     RECT  79.44 7.621 80.328 7.763 ;
     RECT  48.528 5.029 48.552 7.811 ;
     RECT  15.168 7.093 16.968 7.859 ;
     RECT  40.2 6.659 40.512 7.861 ;
     RECT  80.304 7.763 80.328 7.861 ;
     RECT  81.408 6.899 83.712 7.861 ;
     RECT  29.4 4.885 29.88 7.909 ;
     RECT  31.104 6.757 31.128 7.909 ;
     RECT  76.944 7.619 78.312 7.955 ;
     RECT  69.12 7.717 70.392 8.003 ;
     RECT  80.304 7.861 83.712 8.003 ;
     RECT  74.112 7.957 74.136 8.005 ;
     RECT  24 7.139 24.408 8.051 ;
     RECT  64.08 4.693 64.104 8.195 ;
     RECT  29.4 7.909 31.128 8.197 ;
     RECT  84.912 7.187 89.448 8.245 ;
     RECT  90.432 6.611 106.008 8.245 ;
     RECT  69.648 8.003 70.392 8.341 ;
     RECT  75.648 7.475 75.672 8.435 ;
     RECT  67.2 5.027 67.512 8.437 ;
     RECT  42.048 6.517 42.552 8.483 ;
     RECT  69.648 8.341 70.536 8.483 ;
     RECT  21.024 6.755 21.048 8.485 ;
     RECT  29.28 8.197 31.128 8.485 ;
     RECT  29.28 8.485 31.512 8.675 ;
     RECT  74.016 8.005 74.136 8.675 ;
     RECT  72 5.605 73.032 8.821 ;
     RECT  74.016 8.675 74.088 8.821 ;
     RECT  39.984 7.861 40.512 8.965 ;
     RECT  72 8.821 74.088 9.011 ;
     RECT  7.8 7.427 8.112 9.061 ;
     RECT  18.6 1.763 18.912 9.061 ;
     RECT  80.88 8.003 83.712 9.131 ;
     RECT  5.28 5.365 5.304 9.155 ;
     RECT  37.056 7.237 37.08 9.155 ;
     RECT  42.048 8.483 42.216 9.155 ;
     RECT  72 9.011 74.04 9.155 ;
     RECT  21.024 8.485 21.672 9.203 ;
     RECT  77.376 7.955 78.312 9.203 ;
     RECT  16.272 7.859 16.968 9.395 ;
     RECT  16.272 9.395 16.296 9.445 ;
     RECT  31.104 8.675 31.512 9.491 ;
     RECT  84.912 8.245 106.008 9.539 ;
     RECT  66.336 8.437 67.512 9.589 ;
     RECT  13.2 7.523 13.512 9.637 ;
     RECT  47.904 8.485 47.928 9.683 ;
     RECT  31.104 9.491 31.128 9.731 ;
     RECT  84.912 9.539 89.496 9.731 ;
     RECT  25.632 9.013 25.656 9.779 ;
     RECT  29.28 8.675 29.88 9.779 ;
     RECT  90.576 9.539 106.008 9.779 ;
     RECT  18.6 9.061 19.752 9.923 ;
     RECT  66.336 9.589 68.28 10.115 ;
     RECT  34.8 4.595 35.112 10.117 ;
     RECT  22.8 9.781 22.824 10.211 ;
     RECT  10.8 9.637 10.824 10.259 ;
     RECT  29.28 9.779 29.712 10.259 ;
     RECT  85.584 9.731 89.496 10.307 ;
     RECT  85.584 10.307 86.376 10.403 ;
     RECT  18.6 9.923 18.912 10.501 ;
     RECT  13.2 9.637 13.656 10.549 ;
     RECT  15.168 7.859 15.192 10.549 ;
     RECT  45.6 7.139 45.912 10.597 ;
     RECT  16.176 9.445 16.296 10.787 ;
     RECT  69.648 8.483 70.392 10.931 ;
     RECT  33.168 10.165 33.192 10.979 ;
     RECT  72 9.155 73.512 10.979 ;
     RECT  87.36 10.307 89.496 11.027 ;
     RECT  87.744 11.027 89.496 11.029 ;
     RECT  7.8 9.061 8.472 11.123 ;
     RECT  80.832 9.131 83.712 11.267 ;
     RECT  91.152 9.779 106.008 11.317 ;
     RECT  24 8.051 24.312 11.365 ;
     RECT  13.2 10.549 15.192 11.459 ;
     RECT  70.368 10.931 70.392 11.459 ;
     RECT  24 11.365 24.408 11.507 ;
     RECT  26.88 10.837 26.904 11.603 ;
     RECT  10.608 11.173 10.632 11.699 ;
     RECT  72 10.979 73.464 11.699 ;
     RECT  80.88 11.267 83.712 11.845 ;
     RECT  87.744 11.029 89.592 11.845 ;
     RECT  17.904 10.501 18.912 11.891 ;
     RECT  45.6 10.597 46.584 11.939 ;
     RECT  39.888 8.965 40.512 11.941 ;
     RECT  37.488 10.597 37.512 12.227 ;
     RECT  80.88 11.845 83.88 12.323 ;
     RECT  21.024 9.203 21.048 12.469 ;
     RECT  86.352 10.403 86.376 12.469 ;
     RECT  87.744 11.845 90.024 12.469 ;
     RECT  91.104 11.317 106.008 12.515 ;
     RECT  7.8 11.123 8.112 12.517 ;
     RECT  20.784 12.469 21.048 12.517 ;
     RECT  66.336 10.115 67.512 12.517 ;
     RECT  72 11.699 73.032 12.563 ;
     RECT  91.104 12.515 105.768 12.563 ;
     RECT  86.352 12.469 90.024 12.565 ;
     RECT  81.504 12.323 83.88 12.611 ;
     RECT  20.4 12.517 21.048 12.661 ;
     RECT  34.8 10.117 35.496 12.755 ;
     RECT  20.4 12.661 21.096 12.803 ;
     RECT  39.312 11.941 40.512 12.803 ;
     RECT  66.336 12.517 67.656 12.901 ;
     RECT  77.568 9.203 78.312 12.949 ;
     RECT  86.352 12.565 90.072 12.997 ;
     RECT  18.6 11.891 18.912 13.093 ;
     RECT  85.392 12.997 90.072 13.187 ;
     RECT  49.584 4.787 49.608 13.283 ;
     RECT  7.8 12.517 8.52 13.331 ;
     RECT  7.8 13.331 8.112 13.333 ;
     RECT  22.848 12.373 22.872 13.333 ;
     RECT  15.168 11.459 15.192 13.525 ;
     RECT  16.272 10.787 16.296 13.525 ;
     RECT  51 1.859 51.312 13.525 ;
     RECT  79.824 12.517 79.848 13.525 ;
     RECT  20.4 12.803 21.048 13.619 ;
     RECT  77.568 12.949 78.648 13.619 ;
     RECT  29.4 10.259 29.712 13.621 ;
     RECT  81.504 12.611 82.392 13.621 ;
     RECT  83.4 12.611 83.88 13.621 ;
     RECT  85.392 13.187 86.376 13.667 ;
     RECT  2.4 4.595 2.712 13.669 ;
     RECT  20.784 13.619 21.048 13.715 ;
     RECT  34.8 12.755 35.352 13.813 ;
     RECT  45.6 11.939 45.912 13.813 ;
     RECT  87.744 13.187 90.072 13.813 ;
     RECT  91.152 12.563 105.768 13.813 ;
     RECT  22.224 13.333 22.872 13.955 ;
     RECT  50.88 13.525 51.312 13.955 ;
     RECT  79.824 13.525 79.944 13.957 ;
     RECT  81.504 13.621 83.88 13.957 ;
     RECT  63.888 10.213 63.912 14.099 ;
     RECT  31.296 12.325 31.32 14.197 ;
     RECT  31.008 14.197 31.32 14.243 ;
     RECT  72 12.563 72.912 14.245 ;
     RECT  22.224 13.955 22.248 14.291 ;
     RECT  15.168 13.525 16.296 14.341 ;
     RECT  66.24 12.901 67.656 14.483 ;
     RECT  77.568 13.619 78.312 14.485 ;
     RECT  14.832 14.341 16.296 14.531 ;
     RECT  85.584 13.667 86.376 14.531 ;
     RECT  18.144 13.093 18.912 14.533 ;
     RECT  87.744 13.813 105.768 14.533 ;
     RECT  2.4 13.669 3.672 14.627 ;
     RECT  17.856 14.533 18.912 14.629 ;
     RECT  26.736 13.429 26.76 14.819 ;
     RECT  34.8 13.813 35.592 14.867 ;
     RECT  71.088 14.245 72.912 14.867 ;
     RECT  17.856 14.629 19.416 14.917 ;
     RECT  77.184 14.485 78.312 14.917 ;
     RECT  79.824 13.957 83.88 14.917 ;
     RECT  77.184 14.917 83.88 15.013 ;
     RECT  29.28 13.621 29.712 15.059 ;
     RECT  31.008 14.243 31.032 15.301 ;
     RECT  69.12 13.045 69.144 15.349 ;
     RECT  13.2 11.459 13.512 15.397 ;
     RECT  15.168 14.531 16.296 15.443 ;
     RECT  42.048 13.573 42.072 15.443 ;
     RECT  45.6 13.813 46.728 15.491 ;
     RECT  30.96 15.301 31.032 15.829 ;
     RECT  40.2 12.803 40.512 15.877 ;
     RECT  87.456 14.533 105.768 15.877 ;
     RECT  48.528 14.437 48.552 15.973 ;
     RECT  72 14.867 72.912 15.973 ;
     RECT  36.816 15.349 36.84 16.019 ;
     RECT  75.024 13.573 75.048 16.019 ;
     RECT  24 11.507 24.312 16.021 ;
     RECT  6.864 13.333 8.112 16.115 ;
     RECT  76.896 15.013 83.88 16.115 ;
     RECT  77.184 16.115 83.88 16.165 ;
     RECT  13.056 15.397 13.512 16.307 ;
     RECT  77.184 16.165 84.264 16.405 ;
     RECT  87.456 15.877 106.008 16.405 ;
     RECT  30.96 15.829 31.368 16.501 ;
     RECT  2.4 14.627 3.432 16.547 ;
     RECT  7.056 16.115 8.112 16.595 ;
     RECT  77.184 16.405 85.224 16.643 ;
     RECT  67.2 14.483 67.656 16.691 ;
     RECT  47.712 15.973 48.552 16.787 ;
     RECT  69.12 15.349 69.528 16.789 ;
     RECT  10.272 14.341 10.296 16.835 ;
     RECT  72 15.973 73.176 16.835 ;
     RECT  45.6 15.491 45.912 16.933 ;
     RECT  17.808 14.917 19.416 17.075 ;
     RECT  77.184 16.643 82.392 17.075 ;
     RECT  15.168 15.443 15.192 17.077 ;
     RECT  16.272 15.443 16.296 17.077 ;
     RECT  22.224 17.029 22.248 17.077 ;
     RECT  24 16.021 24.456 17.123 ;
     RECT  17.808 17.075 18.912 17.363 ;
     RECT  20.784 13.715 20.808 17.459 ;
     RECT  34.8 14.867 35.112 17.461 ;
     RECT  77.184 17.075 80.472 17.507 ;
     RECT  69.12 16.789 70.44 17.603 ;
     RECT  13.2 16.307 13.512 17.605 ;
     RECT  34.8 17.461 36.072 17.605 ;
     RECT  48.528 16.787 48.552 17.605 ;
     RECT  87.36 16.405 106.008 17.699 ;
     RECT  29.4 15.059 29.712 17.749 ;
     RECT  30.72 16.501 31.368 17.749 ;
     RECT  44.448 15.589 44.472 17.843 ;
     RECT  48.528 17.605 49.512 17.843 ;
     RECT  7.104 16.595 8.112 17.845 ;
     RECT  6.624 17.845 8.112 17.891 ;
     RECT  29.4 17.749 31.368 17.893 ;
     RECT  32.448 15.973 32.472 17.893 ;
     RECT  45.6 16.933 46.632 17.987 ;
     RECT  34.128 17.605 36.072 18.035 ;
     RECT  10.32 16.885 10.344 18.181 ;
     RECT  11.664 11.941 11.688 18.181 ;
     RECT  12.96 17.605 13.512 18.181 ;
     RECT  21.984 17.077 22.248 18.181 ;
     RECT  27.36 15.301 27.384 18.181 ;
     RECT  10.32 18.181 13.512 18.227 ;
     RECT  26.928 18.181 27.384 18.227 ;
     RECT  77.184 17.507 79.944 18.227 ;
     RECT  75.792 16.837 75.816 18.275 ;
     RECT  87.36 17.699 90.072 18.275 ;
     RECT  91.152 17.699 106.008 18.275 ;
     RECT  29.4 17.893 32.472 18.469 ;
     RECT  29.28 18.469 32.472 18.659 ;
     RECT  87.744 18.275 90.072 18.707 ;
     RECT  81.504 17.075 82.392 18.803 ;
     RECT  15.168 17.077 16.296 18.851 ;
     RECT  77.184 18.227 79.272 18.851 ;
     RECT  10.8 18.227 13.512 18.901 ;
     RECT  24 17.123 24.408 18.901 ;
     RECT  6.624 17.891 6.648 18.947 ;
     RECT  5.472 14.197 5.496 19.093 ;
     RECT  39.744 15.877 40.512 19.093 ;
     RECT  5.472 19.093 6.456 19.139 ;
     RECT  91.248 18.275 106.008 19.139 ;
     RECT  10.8 18.901 13.704 19.235 ;
     RECT  45.6 17.987 46.44 19.285 ;
     RECT  18.144 17.363 18.912 19.333 ;
     RECT  21.984 18.181 22.296 19.333 ;
     RECT  10.8 19.235 11.688 19.379 ;
     RECT  34.128 18.035 35.112 19.427 ;
     RECT  91.248 19.139 105.528 19.427 ;
     RECT  10.8 19.379 10.824 19.523 ;
     RECT  7.8 17.891 8.112 19.525 ;
     RECT  9.456 19.477 9.48 19.525 ;
     RECT  49.488 17.843 49.512 19.621 ;
     RECT  7.8 19.525 9.48 19.909 ;
     RECT  77.184 18.851 78.936 20.003 ;
     RECT  92.448 19.427 105.528 20.003 ;
     RECT  87.744 18.707 89.112 20.147 ;
     RECT  16.272 18.851 16.296 20.245 ;
     RECT  38.016 13.909 38.04 20.389 ;
     RECT  47.568 19.813 47.592 20.437 ;
     RECT  12.96 19.235 13.704 20.485 ;
     RECT  6.336 19.139 6.456 20.579 ;
     RECT  30.72 18.659 32.472 20.581 ;
     RECT  7.8 19.909 10.296 20.627 ;
     RECT  87.792 20.147 89.112 20.627 ;
     RECT  83.4 16.643 85.224 20.675 ;
     RECT  86.352 14.531 86.376 20.723 ;
     RECT  88.8 20.627 89.112 20.725 ;
     RECT  90.336 20.149 90.36 20.725 ;
     RECT  88.8 20.725 90.36 20.819 ;
     RECT  30.72 20.581 33.432 20.867 ;
     RECT  18.096 19.333 18.912 20.869 ;
     RECT  45.072 19.285 46.44 20.963 ;
     RECT  12.96 20.485 13.752 20.965 ;
     RECT  34.8 19.427 35.112 20.965 ;
     RECT  92.448 20.003 105.312 20.965 ;
     RECT  18.096 20.869 19.032 21.107 ;
     RECT  29.28 18.659 29.712 21.109 ;
     RECT  7.8 20.627 9.48 21.155 ;
     RECT  16.272 20.245 16.584 21.155 ;
     RECT  26.928 18.227 26.952 21.155 ;
     RECT  45.168 20.963 46.44 21.155 ;
     RECT  47.568 20.437 47.928 21.155 ;
     RECT  75.984 19.093 76.008 21.155 ;
     RECT  31.632 20.867 33.432 21.203 ;
     RECT  39.312 19.093 40.512 21.203 ;
     RECT  49.488 19.621 49.656 21.251 ;
     RECT  9.456 21.155 9.48 21.395 ;
     RECT  31.632 21.203 32.472 21.395 ;
     RECT  34.8 20.965 35.688 21.445 ;
     RECT  39.6 21.203 40.512 21.445 ;
     RECT  6.336 20.579 6.36 21.637 ;
     RECT  10.8 21.157 10.824 21.637 ;
     RECT  77.184 20.003 78.312 21.683 ;
     RECT  92.448 20.965 105.432 21.683 ;
     RECT  83.4 20.675 85.032 21.731 ;
     RECT  69.12 17.603 69.528 21.971 ;
     RECT  24 18.901 25.08 21.973 ;
     RECT  18.192 21.107 19.032 22.019 ;
     RECT  69.504 21.971 69.528 22.019 ;
     RECT  87.792 20.627 87.816 22.163 ;
     RECT  15.168 18.851 15.192 22.165 ;
     RECT  16.272 21.155 16.296 22.165 ;
     RECT  21.984 19.333 22.344 22.165 ;
     RECT  88.8 20.819 89.736 22.165 ;
     RECT  82.224 18.803 82.392 22.211 ;
     RECT  49.488 21.251 49.512 22.259 ;
     RECT  74.64 21.541 74.664 22.451 ;
     RECT  45.6 21.155 46.44 22.453 ;
     RECT  47.568 21.155 47.592 22.453 ;
     RECT  34.8 21.445 35.976 22.499 ;
     RECT  29.184 21.109 29.712 22.741 ;
     RECT  75.264 22.597 75.288 22.741 ;
     RECT  5.952 21.637 6.36 22.787 ;
     RECT  86.4 21.973 86.424 22.835 ;
     RECT  21.984 22.165 22.68 23.027 ;
     RECT  93.312 21.683 105.432 23.027 ;
     RECT  18.6 22.019 19.032 23.029 ;
     RECT  75.264 22.741 75.432 23.219 ;
     RECT  15.168 22.165 16.296 23.221 ;
     RECT  15.168 23.221 16.968 23.267 ;
     RECT  96.192 23.027 105.432 23.315 ;
     RECT  83.4 21.731 83.928 23.365 ;
     RECT  85.008 21.731 85.032 23.365 ;
     RECT  88.8 22.165 90.072 23.365 ;
     RECT  12.336 20.965 13.752 23.411 ;
     RECT  31.632 21.395 31.656 23.411 ;
     RECT  97.584 23.315 105.432 23.411 ;
     RECT  75.408 23.219 75.432 23.557 ;
     RECT  88.8 23.365 90.648 23.603 ;
     RECT  24 21.973 25.272 23.653 ;
     RECT  75.408 23.557 76.392 23.699 ;
     RECT  93.312 23.027 94.512 23.699 ;
     RECT  45.6 22.453 47.592 23.747 ;
     RECT  67.2 16.691 67.608 23.843 ;
     RECT  83.4 23.365 85.032 23.893 ;
     RECT  6.336 22.787 6.36 23.987 ;
     RECT  77.424 21.683 78.312 23.987 ;
     RECT  82.32 22.211 82.392 23.987 ;
     RECT  12.48 23.411 13.752 24.133 ;
     RECT  37.584 20.389 38.04 24.181 ;
     RECT  7.8 21.155 8.112 24.229 ;
     RECT  96.192 23.315 96.6 24.325 ;
     RECT  39.6 21.445 40.824 24.419 ;
     RECT  82.32 23.987 82.344 24.469 ;
     RECT  98.352 23.411 105.432 24.469 ;
     RECT  21.984 23.027 22.392 24.565 ;
     RECT  16.272 23.267 16.968 24.613 ;
     RECT  10.8 21.637 11.352 24.707 ;
     RECT  18.6 23.029 19.368 24.707 ;
     RECT  11.328 24.707 11.352 24.851 ;
     RECT  45.6 23.747 46.584 25.045 ;
     RECT  47.568 23.747 47.592 25.045 ;
     RECT  72 16.835 72.912 25.045 ;
     RECT  88.8 23.603 89.736 25.139 ;
     RECT  96.192 24.325 96.888 25.139 ;
     RECT  45.6 25.045 47.592 25.141 ;
     RECT  12.48 24.133 13.992 25.235 ;
     RECT  44.448 23.317 44.472 25.235 ;
     RECT  21.936 24.565 22.392 25.285 ;
     RECT  24 23.653 25.8 25.285 ;
     RECT  69.888 23.317 69.912 25.427 ;
     RECT  96.48 25.139 96.888 25.427 ;
     RECT  13.2 25.235 13.992 25.475 ;
     RECT  21.936 25.285 25.8 25.475 ;
     RECT  45.6 25.141 47.832 25.475 ;
     RECT  77.472 23.987 78.312 25.571 ;
     RECT  34.8 22.499 35.688 25.573 ;
     RECT  40.2 24.419 40.824 25.621 ;
     RECT  45.6 25.475 46.584 25.715 ;
     RECT  81.6 24.469 82.344 25.715 ;
     RECT  28.944 22.741 29.712 25.763 ;
     RECT  22.272 25.475 25.8 25.811 ;
     RECT  22.752 25.811 25.8 26.003 ;
     RECT  97.92 24.469 105.432 26.195 ;
     RECT  11.616 25.285 11.64 26.197 ;
     RECT  13.2 25.475 13.848 26.243 ;
     RECT  71.808 25.045 72.912 26.243 ;
     RECT  76.368 23.699 76.392 26.243 ;
     RECT  7.488 24.229 8.112 26.291 ;
     RECT  23.232 26.003 25.8 26.339 ;
     RECT  37.584 24.181 38.184 26.435 ;
     RECT  16.272 24.613 17.256 26.483 ;
     RECT  47.808 25.475 47.832 26.579 ;
     RECT  34.8 25.573 36.456 26.675 ;
     RECT  82.32 25.715 82.344 26.725 ;
     RECT  83.4 23.893 85.224 26.725 ;
     RECT  36.432 26.675 36.456 26.819 ;
     RECT  40.2 25.621 40.92 26.819 ;
     RECT  75.264 26.197 75.288 26.819 ;
     RECT  23.232 26.339 25.128 26.867 ;
     RECT  37.584 26.435 38.04 26.867 ;
     RECT  23.232 26.867 24.408 26.963 ;
     RECT  40.2 26.819 40.632 27.011 ;
     RECT  10.704 26.197 11.64 27.251 ;
     RECT  86.304 23.029 86.328 27.301 ;
     RECT  88.8 25.139 89.112 27.301 ;
     RECT  82.32 26.725 85.224 27.779 ;
     RECT  11.616 27.251 11.64 27.875 ;
     RECT  34.8 26.675 35.4 27.875 ;
     RECT  80.4 27.205 80.424 27.923 ;
     RECT  75.312 26.917 75.336 27.971 ;
     RECT  83.184 27.779 85.224 28.019 ;
     RECT  94.08 23.699 94.512 28.165 ;
     RECT  83.184 28.019 84.072 28.259 ;
     RECT  93.264 28.165 94.512 28.787 ;
     RECT  97.92 26.195 105.312 28.837 ;
     RECT  88.8 27.301 89.352 29.029 ;
     RECT  88.8 29.029 89.448 29.509 ;
     RECT  86.304 27.301 86.616 29.603 ;
     RECT  86.592 29.603 86.616 29.795 ;
     RECT  97.584 28.837 105.312 30.229 ;
     RECT  87.984 29.509 89.448 30.709 ;
     RECT  97.44 30.229 105.312 30.709 ;
     RECT  37.776 26.867 38.04 30.851 ;
     RECT  87.744 30.709 89.448 30.851 ;
     RECT  96.576 30.709 105.312 31.379 ;
     RECT  94.2 28.787 94.512 31.477 ;
     RECT  36.144 31.429 36.168 31.861 ;
     RECT  87.984 30.851 89.448 32.099 ;
     RECT  97.584 31.379 103.656 32.341 ;
     RECT  97.584 32.341 103.752 32.437 ;
     RECT  94.2 31.477 94.68 32.531 ;
     RECT  85.2 28.019 85.224 32.915 ;
     RECT  94.2 32.531 94.512 33.013 ;
     RECT  92.352 32.437 92.376 33.107 ;
     RECT  94.08 33.013 94.512 33.589 ;
     RECT  96.576 31.379 96.6 33.733 ;
     RECT  97.584 32.437 103.896 33.733 ;
     RECT  96.576 33.733 103.896 33.779 ;
     RECT  87.984 32.099 89.112 33.827 ;
     RECT  96.768 33.779 103.896 34.501 ;
     RECT  105 31.379 105.312 34.501 ;
     RECT  94.08 33.589 94.92 34.931 ;
     RECT  96.768 34.501 105.312 35.027 ;
     RECT  88.368 33.827 89.112 35.029 ;
     RECT  83.4 28.259 84.072 35.269 ;
     RECT  98.352 35.027 105.312 35.317 ;
     RECT  94.2 34.931 94.92 35.555 ;
     RECT  96.768 35.027 96.792 36.035 ;
     RECT  87.936 35.029 89.112 36.131 ;
     RECT  83.4 35.269 84.36 36.563 ;
     RECT  98.352 35.317 105.432 37.091 ;
     RECT  98.352 37.091 105.312 37.427 ;
     RECT  88.32 36.131 89.112 37.619 ;
     RECT  83.4 36.563 84.072 38.003 ;
     RECT  88.8 37.619 89.112 38.149 ;
     RECT  94.2 35.555 94.512 38.389 ;
     RECT  36.144 31.861 36.456 38.483 ;
     RECT  88.8 38.149 89.544 38.677 ;
     RECT  88.032 38.677 89.544 38.725 ;
     RECT  87.216 38.725 89.544 39.395 ;
     RECT  85.2 38.389 85.224 39.637 ;
     RECT  96.864 38.437 96.888 39.733 ;
     RECT  87.936 39.395 89.112 39.923 ;
     RECT  54.288 38.437 54.312 40.499 ;
     RECT  96.864 39.733 97.464 40.499 ;
     RECT  96.864 40.499 96.888 40.595 ;
     RECT  98.688 37.427 105.312 40.933 ;
     RECT  98.4 40.933 105.312 41.123 ;
     RECT  85.2 39.637 86.04 41.411 ;
     RECT  88.032 39.923 89.112 41.651 ;
     RECT  98.4 41.123 103.032 41.699 ;
     RECT  85.2 41.411 85.848 42.179 ;
     RECT  104.16 41.123 105.312 42.613 ;
     RECT  98.688 41.699 103.032 42.661 ;
     RECT  104.112 42.613 105.312 42.661 ;
     RECT  94.08 38.389 94.512 42.709 ;
     RECT  94.08 42.709 95.16 43.283 ;
     RECT  98.688 42.661 105.312 43.813 ;
     RECT  92.544 43.717 92.568 44.483 ;
     RECT  94.08 43.283 94.512 45.011 ;
     RECT  98.688 43.813 105.432 45.059 ;
     RECT  98.688 45.059 105.312 45.541 ;
     RECT  91.44 43.813 91.464 45.587 ;
     RECT  98.016 45.541 105.312 45.733 ;
     RECT  24 26.963 24.408 45.827 ;
     RECT  97.968 45.733 105.312 46.693 ;
     RECT  37.776 30.851 37.8 47.269 ;
     RECT  94.2 45.011 94.512 47.269 ;
     RECT  36.432 38.483 36.456 47.315 ;
     RECT  97.2 46.693 105.312 47.315 ;
     RECT  37.44 47.269 37.8 47.507 ;
     RECT  97.968 47.315 105.312 47.845 ;
     RECT  94.032 47.269 94.512 47.939 ;
     RECT  21.36 46.117 21.384 48.515 ;
     RECT  97.968 47.845 105.432 48.757 ;
     RECT  97.92 48.757 105.432 50.195 ;
     RECT  37.44 47.507 37.464 50.771 ;
     RECT  97.92 50.195 105.312 50.771 ;
     RECT  94.2 47.939 94.512 51.781 ;
     RECT  98.016 50.771 105.312 51.923 ;
     RECT  94.2 51.781 95.112 52.499 ;
     RECT  98.016 51.923 98.04 52.499 ;
     RECT  99.6 51.923 105.312 53.557 ;
     RECT  99.168 53.557 105.312 54.179 ;
     RECT  101.232 54.179 105.312 54.755 ;
     RECT  101.232 54.755 102.552 55.331 ;
     RECT  101.472 55.331 102.552 55.813 ;
     RECT  103.632 54.755 105.312 55.813 ;
     RECT  97.488 55.813 97.512 56.531 ;
     RECT  101.472 55.813 105.312 56.723 ;
     RECT  99.6 54.179 99.912 56.965 ;
     RECT  99.6 56.965 100.296 57.635 ;
     RECT  102.816 56.723 105.312 57.827 ;
     RECT  101.472 56.723 101.496 58.021 ;
     RECT  99.6 57.635 99.912 58.117 ;
     RECT  103.584 57.827 105.312 58.117 ;
     RECT  101.472 58.021 101.736 58.691 ;
     RECT  101.568 58.691 101.736 58.981 ;
     RECT  103.584 58.117 105.432 59.221 ;
     RECT  103.536 59.221 105.432 59.315 ;
     RECT  94.2 52.499 94.512 59.461 ;
     RECT  98.784 58.117 99.912 59.507 ;
     RECT  15.168 23.267 15.192 59.797 ;
     RECT  101.568 58.981 102.552 59.797 ;
     RECT  103.536 59.315 105.312 59.797 ;
     RECT  15.072 59.797 15.192 59.843 ;
     RECT  16.272 26.483 16.296 59.891 ;
     RECT  101.568 59.797 105.312 59.939 ;
     RECT  102.576 59.939 105.312 60.275 ;
     RECT  102.576 60.275 102.6 61.091 ;
     RECT  104.256 60.275 105.312 61.619 ;
     RECT  85.2 42.179 85.224 62.771 ;
     RECT  103.2 63.205 103.224 63.491 ;
     RECT  99.6 59.507 99.912 64.933 ;
     RECT  51 13.955 51.312 65.941 ;
     RECT  16.224 60.373 16.248 66.085 ;
     RECT  99.6 64.933 100.488 66.515 ;
     RECT  94.08 59.461 94.512 67.859 ;
     RECT  24 45.827 24.312 68.101 ;
     RECT  99.6 66.515 100.344 68.147 ;
     RECT  97.92 65.653 97.944 68.245 ;
     RECT  103.152 66.997 103.176 68.435 ;
     RECT  23.04 68.101 24.312 68.675 ;
     RECT  7.8 26.291 8.112 68.725 ;
     RECT  88.8 41.651 89.112 68.773 ;
     RECT  94.2 67.859 94.512 68.917 ;
     RECT  97.92 68.245 97.992 69.493 ;
     RECT  99.6 68.147 99.912 69.493 ;
     RECT  88.8 68.773 89.784 69.587 ;
     RECT  94.032 68.917 94.512 69.587 ;
     RECT  16.224 66.085 16.824 69.779 ;
     RECT  16.224 69.779 16.248 69.875 ;
     RECT  78 25.571 78.312 69.877 ;
     RECT  101.568 59.939 101.592 70.021 ;
     RECT  100.944 70.021 101.592 70.067 ;
     RECT  97.92 69.493 99.912 70.069 ;
     RECT  29.4 25.763 29.712 70.261 ;
     RECT  15.072 59.843 15.096 70.403 ;
     RECT  21.696 48.997 21.72 70.453 ;
     RECT  7.8 68.725 8.664 70.499 ;
     RECT  21.696 70.453 21.816 70.499 ;
     RECT  97.536 70.069 99.912 70.547 ;
     RECT  40.2 27.011 40.512 70.645 ;
     RECT  99.6 70.547 99.912 70.645 ;
     RECT  100.944 70.067 100.968 70.645 ;
     RECT  7.8 70.499 8.232 70.739 ;
     RECT  39.216 70.645 40.512 70.979 ;
     RECT  13.2 26.243 13.512 71.173 ;
     RECT  81.504 63.109 81.528 71.221 ;
     RECT  85.728 63.157 85.752 71.221 ;
     RECT  25.92 69.877 25.944 71.267 ;
     RECT  78 69.877 79.224 71.267 ;
     RECT  93.024 70.117 93.048 71.315 ;
     RECT  95.952 70.645 95.976 71.315 ;
     RECT  99.6 70.645 100.968 71.363 ;
     RECT  29.4 70.261 29.976 71.699 ;
     RECT  94.2 69.587 94.512 71.797 ;
     RECT  11.04 70.501 11.064 71.843 ;
     RECT  32.784 71.221 32.808 71.843 ;
     RECT  78 71.267 78.408 71.891 ;
     RECT  85.44 71.221 85.752 71.891 ;
     RECT  5.712 69.877 5.736 72.131 ;
     RECT  10.032 70.645 10.056 72.133 ;
     RECT  9.264 72.133 10.056 72.179 ;
     RECT  81.312 71.221 81.528 72.179 ;
     RECT  85.44 71.891 85.464 72.179 ;
     RECT  7.8 70.739 8.112 72.277 ;
     RECT  9.264 72.179 9.288 72.277 ;
     RECT  24 68.675 24.312 72.277 ;
     RECT  88.8 69.587 89.112 72.325 ;
     RECT  100.944 71.363 100.968 72.373 ;
     RECT  100.944 72.373 101.16 72.419 ;
     RECT  12.912 71.173 13.512 72.467 ;
     RECT  24 72.277 24.888 72.565 ;
     RECT  61.8 4.595 62.112 72.709 ;
     RECT  18.6 24.707 18.912 72.805 ;
     RECT  103.536 72.373 103.56 72.899 ;
     RECT  76.032 70.981 76.056 72.901 ;
     RECT  75.552 72.901 76.056 72.947 ;
     RECT  7.8 72.277 9.288 73.235 ;
     RECT  21.792 70.499 21.816 73.237 ;
     RECT  88.8 72.325 90.072 73.237 ;
     RECT  21.792 73.237 21.912 73.283 ;
     RECT  97.536 70.547 97.944 73.283 ;
     RECT  105 61.619 105.312 73.285 ;
     RECT  61.8 72.709 62.232 73.333 ;
     RECT  24 72.565 25.704 73.379 ;
     RECT  104.4 73.285 105.312 73.427 ;
     RECT  72.6 26.243 72.912 73.477 ;
     RECT  61.536 73.333 62.232 73.523 ;
     RECT  97.536 73.283 97.56 73.523 ;
     RECT  18.6 72.805 19.368 73.571 ;
     RECT  93.84 71.797 94.512 73.571 ;
     RECT  79.824 72.901 79.848 73.763 ;
     RECT  29.4 71.699 29.712 73.957 ;
     RECT  72.6 73.477 73.416 73.957 ;
     RECT  94.2 73.571 94.512 74.005 ;
     RECT  95.76 72.277 95.784 74.005 ;
     RECT  9.264 73.235 9.288 74.053 ;
     RECT  101.136 72.419 101.16 74.053 ;
     RECT  61.536 73.523 62.112 74.099 ;
     RECT  101.136 74.053 101.4 74.099 ;
     RECT  11.712 73.093 11.736 74.147 ;
     RECT  104.832 73.427 105.312 74.147 ;
     RECT  16.944 72.901 16.968 74.291 ;
     RECT  25.68 73.379 25.704 74.291 ;
     RECT  36.816 51.253 36.84 74.579 ;
     RECT  13.2 72.467 13.512 74.581 ;
     RECT  45.6 25.715 45.912 74.581 ;
     RECT  54.192 40.645 54.216 74.581 ;
     RECT  75.552 72.947 75.576 74.581 ;
     RECT  104.88 74.147 105.312 74.627 ;
     RECT  21.888 73.283 21.912 74.629 ;
     RECT  34.8 27.875 35.112 74.629 ;
     RECT  40.2 70.979 40.512 74.629 ;
     RECT  38.016 70.933 38.04 74.675 ;
     RECT  72.144 73.957 73.416 74.675 ;
     RECT  72.6 74.675 73.416 74.723 ;
     RECT  75.552 74.581 75.864 74.867 ;
     RECT  88.8 73.237 90.312 74.867 ;
     RECT  94.2 74.005 95.784 74.867 ;
     RECT  61.8 74.099 62.112 74.965 ;
     RECT  63.12 74.485 63.144 74.965 ;
     RECT  61.8 74.965 63.144 75.011 ;
     RECT  97.392 74.053 97.416 75.013 ;
     RECT  45.408 74.581 45.912 75.157 ;
     RECT  56.4 1.763 56.712 75.157 ;
     RECT  9.264 74.053 9.624 75.299 ;
     RECT  34.8 74.629 35.208 75.443 ;
     RECT  9.6 75.299 9.624 75.539 ;
     RECT  50.88 65.941 51.312 75.539 ;
     RECT  21.888 74.629 22.728 75.541 ;
     RECT  45.024 75.157 45.912 75.827 ;
     RECT  64.512 74.869 64.536 75.827 ;
     RECT  54.192 74.581 55.176 75.829 ;
     RECT  54.192 75.829 55.272 75.875 ;
     RECT  96.768 75.013 97.416 75.875 ;
     RECT  96.768 75.875 96.792 75.923 ;
     RECT  61.8 75.011 62.76 76.115 ;
     RECT  92.88 74.629 92.904 76.165 ;
     RECT  39.264 74.629 40.512 76.211 ;
     RECT  92.256 76.165 92.904 76.259 ;
     RECT  45.408 75.827 45.912 76.307 ;
     RECT  61.8 76.115 62.112 76.357 ;
     RECT  21.888 75.541 22.824 76.403 ;
     RECT  55.248 75.875 55.272 76.403 ;
     RECT  90.288 74.867 90.312 76.403 ;
     RECT  101.376 74.099 101.4 76.403 ;
     RECT  56.4 75.157 57.192 76.501 ;
     RECT  56.16 76.501 57.192 76.547 ;
     RECT  94.2 74.867 95.16 76.597 ;
     RECT  61.536 76.357 62.112 76.787 ;
     RECT  27.36 74.965 27.384 76.979 ;
     RECT  29.4 73.957 30.168 76.979 ;
     RECT  45.504 76.307 45.912 76.979 ;
     RECT  81.504 72.179 81.528 76.979 ;
     RECT  79.968 76.357 79.992 77.027 ;
     RECT  56.16 76.547 56.712 77.267 ;
     RECT  13.2 74.581 13.608 77.315 ;
     RECT  42.192 75.781 42.216 77.363 ;
     RECT  48.576 76.357 48.6 77.507 ;
     RECT  59.328 76.309 59.352 77.555 ;
     RECT  75.552 74.867 75.576 77.555 ;
     RECT  68.976 73.477 69 77.603 ;
     RECT  94.2 76.597 95.208 77.653 ;
     RECT  2.4 16.547 2.712 78.037 ;
     RECT  93.84 77.653 95.208 78.131 ;
     RECT  94.2 78.131 95.208 78.659 ;
     RECT  7.8 73.235 8.112 78.849 ;
     RECT  13.2 77.315 13.512 78.849 ;
     RECT  24 73.379 24.312 78.849 ;
     RECT  34.8 75.443 35.112 78.849 ;
     RECT  40.2 76.211 40.512 78.849 ;
     RECT  45.6 76.979 45.912 78.849 ;
     RECT  51 75.539 51.312 78.849 ;
     RECT  61.8 76.787 62.112 78.849 ;
     RECT  78 71.891 78.312 78.849 ;
     RECT  83.4 38.003 83.712 78.849 ;
     RECT  88.8 74.867 89.112 78.849 ;
     RECT  94.2 78.659 94.512 78.849 ;
     RECT  105 74.627 105.312 78.849 ;
     RECT  1.584 78.037 2.712 78.863 ;
     RECT  7.8 78.849 7.92 78.863 ;
     RECT  13.2 78.849 13.32 78.863 ;
     RECT  18.6 73.571 18.912 78.863 ;
     RECT  24 78.849 24.12 78.863 ;
     RECT  29.4 76.979 29.712 78.863 ;
     RECT  34.8 78.849 34.92 78.863 ;
     RECT  40.2 78.849 40.488 78.863 ;
     RECT  45.6 78.849 45.72 78.863 ;
     RECT  51 78.849 51.12 78.863 ;
     RECT  56.4 77.267 56.712 78.863 ;
     RECT  61.8 78.849 61.92 78.863 ;
     RECT  67.2 23.843 67.512 78.863 ;
     RECT  72.6 74.723 72.912 78.863 ;
     RECT  78 78.849 78.168 78.863 ;
     RECT  83.4 78.849 83.52 78.863 ;
     RECT  88.8 78.849 88.92 78.863 ;
     RECT  94.2 78.849 94.32 78.863 ;
     RECT  99.6 71.363 99.912 78.863 ;
     RECT  105 78.849 105.12 78.863 ;
     RECT  54.192 75.875 54.216 79.189 ;
     RECT  94.704 80.389 94.728 80.869 ;
     RECT  94.608 80.869 94.728 80.915 ;
     RECT  1.584 78.863 1.608 80.976 ;
     RECT  2.736 79.189 2.76 80.976 ;
     RECT  3.936 79.189 3.96 80.976 ;
     RECT  5.088 79.189 5.112 80.976 ;
     RECT  6.288 80.869 6.312 80.976 ;
     RECT  7.488 80.869 7.512 80.976 ;
     RECT  8.64 80.869 8.664 80.976 ;
     RECT  9.84 80.869 9.864 80.976 ;
     RECT  10.992 79.237 11.016 80.976 ;
     RECT  12.192 79.189 12.216 80.976 ;
     RECT  13.344 80.869 13.368 80.976 ;
     RECT  14.544 80.869 14.568 80.976 ;
     RECT  15.696 80.869 15.72 80.976 ;
     RECT  16.896 79.237 16.92 80.976 ;
     RECT  18.048 79.765 18.072 80.976 ;
     RECT  19.248 79.189 19.272 80.976 ;
     RECT  20.4 79.189 20.424 80.976 ;
     RECT  21.6 79.189 21.624 80.976 ;
     RECT  22.8 79.765 22.824 80.976 ;
     RECT  23.952 80.869 23.976 80.976 ;
     RECT  25.152 79.765 25.176 80.976 ;
     RECT  26.304 80.869 26.328 80.976 ;
     RECT  27.504 79.237 27.528 80.976 ;
     RECT  28.656 80.869 28.68 80.976 ;
     RECT  29.856 79.189 29.88 80.976 ;
     RECT  31.008 80.869 31.032 80.976 ;
     RECT  32.208 79.765 32.232 80.976 ;
     RECT  33.36 79.765 33.384 80.976 ;
     RECT  34.56 79.237 34.584 80.976 ;
     RECT  35.712 80.869 35.736 80.976 ;
     RECT  36.912 79.189 36.936 80.976 ;
     RECT  38.112 79.765 38.136 80.976 ;
     RECT  39.264 79.189 39.288 80.976 ;
     RECT  40.464 78.863 40.488 80.976 ;
     RECT  41.616 80.869 41.64 80.976 ;
     RECT  42.816 80.869 42.84 80.976 ;
     RECT  43.968 79.765 43.992 80.976 ;
     RECT  45.168 79.237 45.192 80.976 ;
     RECT  46.32 80.869 46.344 80.976 ;
     RECT  47.52 79.765 47.544 80.976 ;
     RECT  48.672 80.869 48.696 80.976 ;
     RECT  49.872 80.869 49.896 80.976 ;
     RECT  51.024 78.863 51.048 80.976 ;
     RECT  52.224 79.765 52.248 80.976 ;
     RECT  53.376 79.189 54.6 80.976 ;
     RECT  55.776 79.189 55.8 80.976 ;
     RECT  56.928 79.189 56.952 80.976 ;
     RECT  58.128 80.869 58.152 80.976 ;
     RECT  59.28 79.765 59.304 80.976 ;
     RECT  60.48 80.869 60.504 80.976 ;
     RECT  61.632 80.869 61.656 80.976 ;
     RECT  62.832 80.869 62.856 80.976 ;
     RECT  63.984 79.237 64.008 80.976 ;
     RECT  65.184 80.869 65.208 80.976 ;
     RECT  66.336 80.869 66.36 80.976 ;
     RECT  67.536 79.237 67.56 80.976 ;
     RECT  68.688 79.765 68.712 80.976 ;
     RECT  69.888 79.237 69.912 80.976 ;
     RECT  71.088 79.189 71.112 80.976 ;
     RECT  72.24 79.237 72.264 80.976 ;
     RECT  73.44 79.237 73.464 80.976 ;
     RECT  74.592 79.237 74.616 80.976 ;
     RECT  75.792 78.661 75.816 80.976 ;
     RECT  76.944 79.765 76.968 80.976 ;
     RECT  78.144 78.863 78.168 80.976 ;
     RECT  79.296 79.813 79.32 80.976 ;
     RECT  80.496 80.869 80.52 80.976 ;
     RECT  81.648 79.765 81.672 80.976 ;
     RECT  82.848 79.237 82.872 80.976 ;
     RECT  84 80.869 84.024 80.976 ;
     RECT  85.2 80.869 85.224 80.976 ;
     RECT  86.4 79.189 86.424 80.976 ;
     RECT  87.552 79.189 87.576 80.976 ;
     RECT  88.752 79.765 88.776 80.976 ;
     RECT  89.904 79.189 89.928 80.976 ;
     RECT  91.104 80.389 91.128 80.976 ;
     RECT  92.256 76.259 92.28 80.976 ;
     RECT  93.456 79.237 93.48 80.976 ;
     RECT  94.608 80.915 94.632 80.976 ;
     RECT  95.808 79.813 95.832 80.976 ;
     RECT  96.96 79.237 96.984 80.976 ;
     RECT  98.16 80.869 98.184 80.976 ;
     RECT  99.312 79.765 99.336 80.976 ;
     RECT  100.512 79.189 100.536 80.976 ;
     RECT  101.712 79.765 101.736 80.976 ;
     RECT  102.864 80.389 102.888 80.976 ;
     RECT  104.064 80.389 104.088 80.976 ;
     RECT  105.216 79.813 105.24 80.976 ;
     RECT  106.416 80.869 106.44 80.976 ;
  END
END qkd_ctrl_pc_obs_child
END LIBRARY
